VERSION 5.8 ;
BUSBITCHARS "[]" ;
DIVIDERCHAR "/" ;
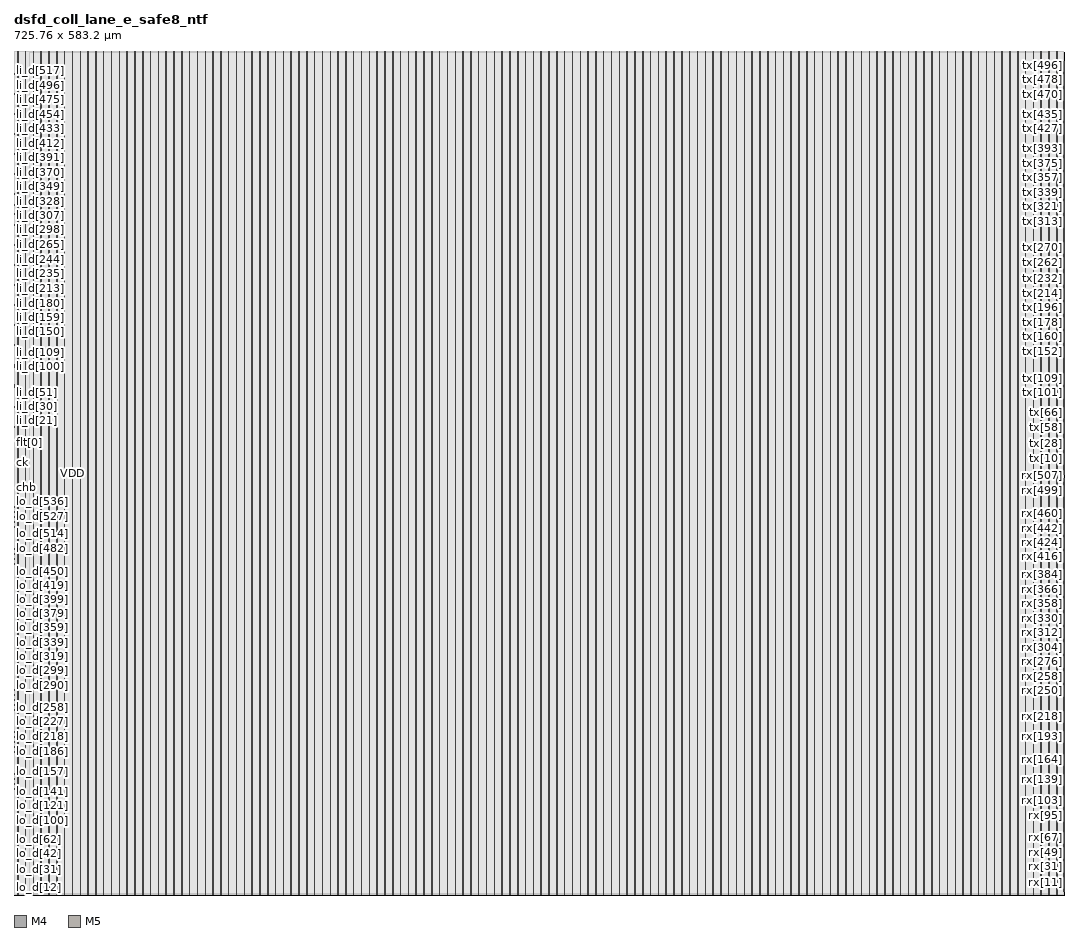
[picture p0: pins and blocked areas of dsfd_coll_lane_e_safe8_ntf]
MACRO dsfd_coll_lane_e_safe8_ntf
  CLASS BLOCK ;
  ORIGIN 0 0 ;
  FOREIGN dsfd_coll_lane_e_safe8_ntf 0 0 ;
  SIZE 725.76 BY 583.2 ;
  SYMMETRY X Y ;
  PIN lo_v
    DIRECTION INPUT ;
    USE SIGNAL ;
    PORT
      LAYER M4 ;
        RECT 0.000 277.008 0.192 277.032 ;
    END
  END lo_v
  PIN lo_r
    DIRECTION OUTPUT ;
    USE SIGNAL ;
    PORT
      LAYER M4 ;
        RECT 0.000 279.168 0.192 279.192 ;
    END
  END lo_r
  PIN lo_d[0]
    DIRECTION INPUT ;
    USE SIGNAL ;
    PORT
      LAYER M4 ;
        RECT 0.000 2.400 0.192 2.424 ;
    END
  END lo_d[0]
  PIN lo_d[1]
    DIRECTION INPUT ;
    USE SIGNAL ;
    PORT
      LAYER M4 ;
        RECT 0.000 2.880 0.192 2.904 ;
    END
  END lo_d[1]
  PIN lo_d[2]
    DIRECTION INPUT ;
    USE SIGNAL ;
    PORT
      LAYER M4 ;
        RECT 0.000 3.360 0.192 3.384 ;
    END
  END lo_d[2]
  PIN lo_d[3]
    DIRECTION INPUT ;
    USE SIGNAL ;
    PORT
      LAYER M4 ;
        RECT 0.000 3.888 0.192 3.912 ;
    END
  END lo_d[3]
  PIN lo_d[4]
    DIRECTION INPUT ;
    USE SIGNAL ;
    PORT
      LAYER M4 ;
        RECT 0.000 4.368 0.192 4.392 ;
    END
  END lo_d[4]
  PIN lo_d[5]
    DIRECTION INPUT ;
    USE SIGNAL ;
    PORT
      LAYER M4 ;
        RECT 0.000 4.848 0.192 4.872 ;
    END
  END lo_d[5]
  PIN lo_d[6]
    DIRECTION INPUT ;
    USE SIGNAL ;
    PORT
      LAYER M4 ;
        RECT 0.000 5.328 0.192 5.352 ;
    END
  END lo_d[6]
  PIN lo_d[7]
    DIRECTION INPUT ;
    USE SIGNAL ;
    PORT
      LAYER M4 ;
        RECT 0.000 5.856 0.192 5.880 ;
    END
  END lo_d[7]
  PIN lo_d[8]
    DIRECTION INPUT ;
    USE SIGNAL ;
    PORT
      LAYER M4 ;
        RECT 0.000 6.336 0.192 6.360 ;
    END
  END lo_d[8]
  PIN lo_d[9]
    DIRECTION INPUT ;
    USE SIGNAL ;
    PORT
      LAYER M4 ;
        RECT 0.000 6.816 0.192 6.840 ;
    END
  END lo_d[9]
  PIN lo_d[10]
    DIRECTION INPUT ;
    USE SIGNAL ;
    PORT
      LAYER M4 ;
        RECT 0.000 7.296 0.192 7.320 ;
    END
  END lo_d[10]
  PIN lo_d[11]
    DIRECTION INPUT ;
    USE SIGNAL ;
    PORT
      LAYER M4 ;
        RECT 0.000 7.824 0.192 7.848 ;
    END
  END lo_d[11]
  PIN lo_d[12]
    DIRECTION INPUT ;
    USE SIGNAL ;
    PORT
      LAYER M4 ;
        RECT 0.000 8.304 0.192 8.328 ;
    END
  END lo_d[12]
  PIN lo_d[13]
    DIRECTION INPUT ;
    USE SIGNAL ;
    PORT
      LAYER M4 ;
        RECT 0.000 8.784 0.192 8.808 ;
    END
  END lo_d[13]
  PIN lo_d[14]
    DIRECTION INPUT ;
    USE SIGNAL ;
    PORT
      LAYER M4 ;
        RECT 0.000 9.264 0.192 9.288 ;
    END
  END lo_d[14]
  PIN lo_d[15]
    DIRECTION INPUT ;
    USE SIGNAL ;
    PORT
      LAYER M4 ;
        RECT 0.000 9.792 0.192 9.816 ;
    END
  END lo_d[15]
  PIN lo_d[16]
    DIRECTION INPUT ;
    USE SIGNAL ;
    PORT
      LAYER M4 ;
        RECT 0.000 10.272 0.192 10.296 ;
    END
  END lo_d[16]
  PIN lo_d[17]
    DIRECTION INPUT ;
    USE SIGNAL ;
    PORT
      LAYER M4 ;
        RECT 0.000 10.752 0.192 10.776 ;
    END
  END lo_d[17]
  PIN lo_d[18]
    DIRECTION INPUT ;
    USE SIGNAL ;
    PORT
      LAYER M4 ;
        RECT 0.000 11.232 0.192 11.256 ;
    END
  END lo_d[18]
  PIN lo_d[19]
    DIRECTION INPUT ;
    USE SIGNAL ;
    PORT
      LAYER M4 ;
        RECT 0.000 11.760 0.192 11.784 ;
    END
  END lo_d[19]
  PIN lo_d[20]
    DIRECTION INPUT ;
    USE SIGNAL ;
    PORT
      LAYER M4 ;
        RECT 0.000 12.240 0.192 12.264 ;
    END
  END lo_d[20]
  PIN lo_d[21]
    DIRECTION INPUT ;
    USE SIGNAL ;
    PORT
      LAYER M4 ;
        RECT 0.000 12.720 0.192 12.744 ;
    END
  END lo_d[21]
  PIN lo_d[22]
    DIRECTION INPUT ;
    USE SIGNAL ;
    PORT
      LAYER M4 ;
        RECT 0.000 13.200 0.192 13.224 ;
    END
  END lo_d[22]
  PIN lo_d[23]
    DIRECTION INPUT ;
    USE SIGNAL ;
    PORT
      LAYER M4 ;
        RECT 0.000 13.728 0.192 13.752 ;
    END
  END lo_d[23]
  PIN lo_d[24]
    DIRECTION INPUT ;
    USE SIGNAL ;
    PORT
      LAYER M4 ;
        RECT 0.000 14.208 0.192 14.232 ;
    END
  END lo_d[24]
  PIN lo_d[25]
    DIRECTION INPUT ;
    USE SIGNAL ;
    PORT
      LAYER M4 ;
        RECT 0.000 14.688 0.192 14.712 ;
    END
  END lo_d[25]
  PIN lo_d[26]
    DIRECTION INPUT ;
    USE SIGNAL ;
    PORT
      LAYER M4 ;
        RECT 0.000 15.168 0.192 15.192 ;
    END
  END lo_d[26]
  PIN lo_d[27]
    DIRECTION INPUT ;
    USE SIGNAL ;
    PORT
      LAYER M4 ;
        RECT 0.000 15.696 0.192 15.720 ;
    END
  END lo_d[27]
  PIN lo_d[28]
    DIRECTION INPUT ;
    USE SIGNAL ;
    PORT
      LAYER M4 ;
        RECT 0.000 16.176 0.192 16.200 ;
    END
  END lo_d[28]
  PIN lo_d[29]
    DIRECTION INPUT ;
    USE SIGNAL ;
    PORT
      LAYER M4 ;
        RECT 0.000 16.656 0.192 16.680 ;
    END
  END lo_d[29]
  PIN lo_d[30]
    DIRECTION INPUT ;
    USE SIGNAL ;
    PORT
      LAYER M4 ;
        RECT 0.000 17.136 0.192 17.160 ;
    END
  END lo_d[30]
  PIN lo_d[31]
    DIRECTION INPUT ;
    USE SIGNAL ;
    PORT
      LAYER M4 ;
        RECT 0.000 17.664 0.192 17.688 ;
    END
  END lo_d[31]
  PIN lo_d[32]
    DIRECTION INPUT ;
    USE SIGNAL ;
    PORT
      LAYER M4 ;
        RECT 0.000 18.144 0.192 18.168 ;
    END
  END lo_d[32]
  PIN lo_d[33]
    DIRECTION INPUT ;
    USE SIGNAL ;
    PORT
      LAYER M4 ;
        RECT 0.000 18.624 0.192 18.648 ;
    END
  END lo_d[33]
  PIN lo_d[34]
    DIRECTION INPUT ;
    USE SIGNAL ;
    PORT
      LAYER M4 ;
        RECT 0.000 19.104 0.192 19.128 ;
    END
  END lo_d[34]
  PIN lo_d[35]
    DIRECTION INPUT ;
    USE SIGNAL ;
    PORT
      LAYER M4 ;
        RECT 0.000 19.632 0.192 19.656 ;
    END
  END lo_d[35]
  PIN lo_d[36]
    DIRECTION INPUT ;
    USE SIGNAL ;
    PORT
      LAYER M4 ;
        RECT 0.000 20.112 0.192 20.136 ;
    END
  END lo_d[36]
  PIN lo_d[37]
    DIRECTION INPUT ;
    USE SIGNAL ;
    PORT
      LAYER M4 ;
        RECT 0.000 20.592 0.192 20.616 ;
    END
  END lo_d[37]
  PIN lo_d[38]
    DIRECTION INPUT ;
    USE SIGNAL ;
    PORT
      LAYER M4 ;
        RECT 0.000 21.072 0.192 21.096 ;
    END
  END lo_d[38]
  PIN lo_d[39]
    DIRECTION INPUT ;
    USE SIGNAL ;
    PORT
      LAYER M4 ;
        RECT 0.000 21.600 0.192 21.624 ;
    END
  END lo_d[39]
  PIN lo_d[40]
    DIRECTION INPUT ;
    USE SIGNAL ;
    PORT
      LAYER M4 ;
        RECT 0.000 22.080 0.192 22.104 ;
    END
  END lo_d[40]
  PIN lo_d[41]
    DIRECTION INPUT ;
    USE SIGNAL ;
    PORT
      LAYER M4 ;
        RECT 0.000 22.560 0.192 22.584 ;
    END
  END lo_d[41]
  PIN lo_d[42]
    DIRECTION INPUT ;
    USE SIGNAL ;
    PORT
      LAYER M4 ;
        RECT 0.000 23.088 0.192 23.112 ;
    END
  END lo_d[42]
  PIN lo_d[43]
    DIRECTION INPUT ;
    USE SIGNAL ;
    PORT
      LAYER M4 ;
        RECT 0.000 23.568 0.192 23.592 ;
    END
  END lo_d[43]
  PIN lo_d[44]
    DIRECTION INPUT ;
    USE SIGNAL ;
    PORT
      LAYER M4 ;
        RECT 0.000 24.048 0.192 24.072 ;
    END
  END lo_d[44]
  PIN lo_d[45]
    DIRECTION INPUT ;
    USE SIGNAL ;
    PORT
      LAYER M4 ;
        RECT 0.000 24.528 0.192 24.552 ;
    END
  END lo_d[45]
  PIN lo_d[46]
    DIRECTION INPUT ;
    USE SIGNAL ;
    PORT
      LAYER M4 ;
        RECT 0.000 25.056 0.192 25.080 ;
    END
  END lo_d[46]
  PIN lo_d[47]
    DIRECTION INPUT ;
    USE SIGNAL ;
    PORT
      LAYER M4 ;
        RECT 0.000 25.536 0.192 25.560 ;
    END
  END lo_d[47]
  PIN lo_d[48]
    DIRECTION INPUT ;
    USE SIGNAL ;
    PORT
      LAYER M4 ;
        RECT 0.000 26.016 0.192 26.040 ;
    END
  END lo_d[48]
  PIN lo_d[49]
    DIRECTION INPUT ;
    USE SIGNAL ;
    PORT
      LAYER M4 ;
        RECT 0.000 26.496 0.192 26.520 ;
    END
  END lo_d[49]
  PIN lo_d[50]
    DIRECTION INPUT ;
    USE SIGNAL ;
    PORT
      LAYER M4 ;
        RECT 0.000 27.024 0.192 27.048 ;
    END
  END lo_d[50]
  PIN lo_d[51]
    DIRECTION INPUT ;
    USE SIGNAL ;
    PORT
      LAYER M4 ;
        RECT 0.000 27.504 0.192 27.528 ;
    END
  END lo_d[51]
  PIN lo_d[52]
    DIRECTION INPUT ;
    USE SIGNAL ;
    PORT
      LAYER M4 ;
        RECT 0.000 27.984 0.192 28.008 ;
    END
  END lo_d[52]
  PIN lo_d[53]
    DIRECTION INPUT ;
    USE SIGNAL ;
    PORT
      LAYER M4 ;
        RECT 0.000 28.464 0.192 28.488 ;
    END
  END lo_d[53]
  PIN lo_d[54]
    DIRECTION INPUT ;
    USE SIGNAL ;
    PORT
      LAYER M4 ;
        RECT 0.000 28.992 0.192 29.016 ;
    END
  END lo_d[54]
  PIN lo_d[55]
    DIRECTION INPUT ;
    USE SIGNAL ;
    PORT
      LAYER M4 ;
        RECT 0.000 29.472 0.192 29.496 ;
    END
  END lo_d[55]
  PIN lo_d[56]
    DIRECTION INPUT ;
    USE SIGNAL ;
    PORT
      LAYER M4 ;
        RECT 0.000 29.952 0.192 29.976 ;
    END
  END lo_d[56]
  PIN lo_d[57]
    DIRECTION INPUT ;
    USE SIGNAL ;
    PORT
      LAYER M4 ;
        RECT 0.000 30.432 0.192 30.456 ;
    END
  END lo_d[57]
  PIN lo_d[58]
    DIRECTION INPUT ;
    USE SIGNAL ;
    PORT
      LAYER M4 ;
        RECT 0.000 30.960 0.192 30.984 ;
    END
  END lo_d[58]
  PIN lo_d[59]
    DIRECTION INPUT ;
    USE SIGNAL ;
    PORT
      LAYER M4 ;
        RECT 0.000 31.440 0.192 31.464 ;
    END
  END lo_d[59]
  PIN lo_d[60]
    DIRECTION INPUT ;
    USE SIGNAL ;
    PORT
      LAYER M4 ;
        RECT 0.000 31.920 0.192 31.944 ;
    END
  END lo_d[60]
  PIN lo_d[61]
    DIRECTION INPUT ;
    USE SIGNAL ;
    PORT
      LAYER M4 ;
        RECT 0.000 32.400 0.192 32.424 ;
    END
  END lo_d[61]
  PIN lo_d[62]
    DIRECTION INPUT ;
    USE SIGNAL ;
    PORT
      LAYER M4 ;
        RECT 0.000 32.928 0.192 32.952 ;
    END
  END lo_d[62]
  PIN lo_d[63]
    DIRECTION INPUT ;
    USE SIGNAL ;
    PORT
      LAYER M4 ;
        RECT 0.000 33.408 0.192 33.432 ;
    END
  END lo_d[63]
  PIN lo_d[64]
    DIRECTION INPUT ;
    USE SIGNAL ;
    PORT
      LAYER M4 ;
        RECT 0.000 33.888 0.192 33.912 ;
    END
  END lo_d[64]
  PIN lo_d[65]
    DIRECTION INPUT ;
    USE SIGNAL ;
    PORT
      LAYER M4 ;
        RECT 0.000 34.368 0.192 34.392 ;
    END
  END lo_d[65]
  PIN lo_d[66]
    DIRECTION INPUT ;
    USE SIGNAL ;
    PORT
      LAYER M4 ;
        RECT 0.000 34.896 0.192 34.920 ;
    END
  END lo_d[66]
  PIN lo_d[67]
    DIRECTION INPUT ;
    USE SIGNAL ;
    PORT
      LAYER M4 ;
        RECT 0.000 35.376 0.192 35.400 ;
    END
  END lo_d[67]
  PIN lo_d[68]
    DIRECTION INPUT ;
    USE SIGNAL ;
    PORT
      LAYER M4 ;
        RECT 0.000 35.856 0.192 35.880 ;
    END
  END lo_d[68]
  PIN lo_d[69]
    DIRECTION INPUT ;
    USE SIGNAL ;
    PORT
      LAYER M4 ;
        RECT 0.000 36.336 0.192 36.360 ;
    END
  END lo_d[69]
  PIN lo_d[70]
    DIRECTION INPUT ;
    USE SIGNAL ;
    PORT
      LAYER M4 ;
        RECT 0.000 36.864 0.192 36.888 ;
    END
  END lo_d[70]
  PIN lo_d[71]
    DIRECTION INPUT ;
    USE SIGNAL ;
    PORT
      LAYER M4 ;
        RECT 0.000 37.344 0.192 37.368 ;
    END
  END lo_d[71]
  PIN lo_d[72]
    DIRECTION INPUT ;
    USE SIGNAL ;
    PORT
      LAYER M4 ;
        RECT 0.000 37.824 0.192 37.848 ;
    END
  END lo_d[72]
  PIN lo_d[73]
    DIRECTION INPUT ;
    USE SIGNAL ;
    PORT
      LAYER M4 ;
        RECT 0.000 38.304 0.192 38.328 ;
    END
  END lo_d[73]
  PIN lo_d[74]
    DIRECTION INPUT ;
    USE SIGNAL ;
    PORT
      LAYER M4 ;
        RECT 0.000 38.832 0.192 38.856 ;
    END
  END lo_d[74]
  PIN lo_d[75]
    DIRECTION INPUT ;
    USE SIGNAL ;
    PORT
      LAYER M4 ;
        RECT 0.000 39.312 0.192 39.336 ;
    END
  END lo_d[75]
  PIN lo_d[76]
    DIRECTION INPUT ;
    USE SIGNAL ;
    PORT
      LAYER M4 ;
        RECT 0.000 39.792 0.192 39.816 ;
    END
  END lo_d[76]
  PIN lo_d[77]
    DIRECTION INPUT ;
    USE SIGNAL ;
    PORT
      LAYER M4 ;
        RECT 0.000 40.272 0.192 40.296 ;
    END
  END lo_d[77]
  PIN lo_d[78]
    DIRECTION INPUT ;
    USE SIGNAL ;
    PORT
      LAYER M4 ;
        RECT 0.000 40.800 0.192 40.824 ;
    END
  END lo_d[78]
  PIN lo_d[79]
    DIRECTION INPUT ;
    USE SIGNAL ;
    PORT
      LAYER M4 ;
        RECT 0.000 41.280 0.192 41.304 ;
    END
  END lo_d[79]
  PIN lo_d[80]
    DIRECTION INPUT ;
    USE SIGNAL ;
    PORT
      LAYER M4 ;
        RECT 0.000 41.760 0.192 41.784 ;
    END
  END lo_d[80]
  PIN lo_d[81]
    DIRECTION INPUT ;
    USE SIGNAL ;
    PORT
      LAYER M4 ;
        RECT 0.000 42.240 0.192 42.264 ;
    END
  END lo_d[81]
  PIN lo_d[82]
    DIRECTION INPUT ;
    USE SIGNAL ;
    PORT
      LAYER M4 ;
        RECT 0.000 42.768 0.192 42.792 ;
    END
  END lo_d[82]
  PIN lo_d[83]
    DIRECTION INPUT ;
    USE SIGNAL ;
    PORT
      LAYER M4 ;
        RECT 0.000 43.248 0.192 43.272 ;
    END
  END lo_d[83]
  PIN lo_d[84]
    DIRECTION INPUT ;
    USE SIGNAL ;
    PORT
      LAYER M4 ;
        RECT 0.000 43.728 0.192 43.752 ;
    END
  END lo_d[84]
  PIN lo_d[85]
    DIRECTION INPUT ;
    USE SIGNAL ;
    PORT
      LAYER M4 ;
        RECT 0.000 44.208 0.192 44.232 ;
    END
  END lo_d[85]
  PIN lo_d[86]
    DIRECTION INPUT ;
    USE SIGNAL ;
    PORT
      LAYER M4 ;
        RECT 0.000 44.736 0.192 44.760 ;
    END
  END lo_d[86]
  PIN lo_d[87]
    DIRECTION INPUT ;
    USE SIGNAL ;
    PORT
      LAYER M4 ;
        RECT 0.000 45.216 0.192 45.240 ;
    END
  END lo_d[87]
  PIN lo_d[88]
    DIRECTION INPUT ;
    USE SIGNAL ;
    PORT
      LAYER M4 ;
        RECT 0.000 45.696 0.192 45.720 ;
    END
  END lo_d[88]
  PIN lo_d[89]
    DIRECTION INPUT ;
    USE SIGNAL ;
    PORT
      LAYER M4 ;
        RECT 0.000 46.176 0.192 46.200 ;
    END
  END lo_d[89]
  PIN lo_d[90]
    DIRECTION INPUT ;
    USE SIGNAL ;
    PORT
      LAYER M4 ;
        RECT 0.000 46.704 0.192 46.728 ;
    END
  END lo_d[90]
  PIN lo_d[91]
    DIRECTION INPUT ;
    USE SIGNAL ;
    PORT
      LAYER M4 ;
        RECT 0.000 47.184 0.192 47.208 ;
    END
  END lo_d[91]
  PIN lo_d[92]
    DIRECTION INPUT ;
    USE SIGNAL ;
    PORT
      LAYER M4 ;
        RECT 0.000 47.664 0.192 47.688 ;
    END
  END lo_d[92]
  PIN lo_d[93]
    DIRECTION INPUT ;
    USE SIGNAL ;
    PORT
      LAYER M4 ;
        RECT 0.000 48.144 0.192 48.168 ;
    END
  END lo_d[93]
  PIN lo_d[94]
    DIRECTION INPUT ;
    USE SIGNAL ;
    PORT
      LAYER M4 ;
        RECT 0.000 48.672 0.192 48.696 ;
    END
  END lo_d[94]
  PIN lo_d[95]
    DIRECTION INPUT ;
    USE SIGNAL ;
    PORT
      LAYER M4 ;
        RECT 0.000 49.152 0.192 49.176 ;
    END
  END lo_d[95]
  PIN lo_d[96]
    DIRECTION INPUT ;
    USE SIGNAL ;
    PORT
      LAYER M4 ;
        RECT 0.000 49.632 0.192 49.656 ;
    END
  END lo_d[96]
  PIN lo_d[97]
    DIRECTION INPUT ;
    USE SIGNAL ;
    PORT
      LAYER M4 ;
        RECT 0.000 50.112 0.192 50.136 ;
    END
  END lo_d[97]
  PIN lo_d[98]
    DIRECTION INPUT ;
    USE SIGNAL ;
    PORT
      LAYER M4 ;
        RECT 0.000 50.640 0.192 50.664 ;
    END
  END lo_d[98]
  PIN lo_d[99]
    DIRECTION INPUT ;
    USE SIGNAL ;
    PORT
      LAYER M4 ;
        RECT 0.000 51.120 0.192 51.144 ;
    END
  END lo_d[99]
  PIN lo_d[100]
    DIRECTION INPUT ;
    USE SIGNAL ;
    PORT
      LAYER M4 ;
        RECT 0.000 51.600 0.192 51.624 ;
    END
  END lo_d[100]
  PIN lo_d[101]
    DIRECTION INPUT ;
    USE SIGNAL ;
    PORT
      LAYER M4 ;
        RECT 0.000 52.080 0.192 52.104 ;
    END
  END lo_d[101]
  PIN lo_d[102]
    DIRECTION INPUT ;
    USE SIGNAL ;
    PORT
      LAYER M4 ;
        RECT 0.000 52.608 0.192 52.632 ;
    END
  END lo_d[102]
  PIN lo_d[103]
    DIRECTION INPUT ;
    USE SIGNAL ;
    PORT
      LAYER M4 ;
        RECT 0.000 53.088 0.192 53.112 ;
    END
  END lo_d[103]
  PIN lo_d[104]
    DIRECTION INPUT ;
    USE SIGNAL ;
    PORT
      LAYER M4 ;
        RECT 0.000 53.568 0.192 53.592 ;
    END
  END lo_d[104]
  PIN lo_d[105]
    DIRECTION INPUT ;
    USE SIGNAL ;
    PORT
      LAYER M4 ;
        RECT 0.000 54.048 0.192 54.072 ;
    END
  END lo_d[105]
  PIN lo_d[106]
    DIRECTION INPUT ;
    USE SIGNAL ;
    PORT
      LAYER M4 ;
        RECT 0.000 54.576 0.192 54.600 ;
    END
  END lo_d[106]
  PIN lo_d[107]
    DIRECTION INPUT ;
    USE SIGNAL ;
    PORT
      LAYER M4 ;
        RECT 0.000 55.056 0.192 55.080 ;
    END
  END lo_d[107]
  PIN lo_d[108]
    DIRECTION INPUT ;
    USE SIGNAL ;
    PORT
      LAYER M4 ;
        RECT 0.000 55.536 0.192 55.560 ;
    END
  END lo_d[108]
  PIN lo_d[109]
    DIRECTION INPUT ;
    USE SIGNAL ;
    PORT
      LAYER M4 ;
        RECT 0.000 56.016 0.192 56.040 ;
    END
  END lo_d[109]
  PIN lo_d[110]
    DIRECTION INPUT ;
    USE SIGNAL ;
    PORT
      LAYER M4 ;
        RECT 0.000 56.544 0.192 56.568 ;
    END
  END lo_d[110]
  PIN lo_d[111]
    DIRECTION INPUT ;
    USE SIGNAL ;
    PORT
      LAYER M4 ;
        RECT 0.000 57.024 0.192 57.048 ;
    END
  END lo_d[111]
  PIN lo_d[112]
    DIRECTION INPUT ;
    USE SIGNAL ;
    PORT
      LAYER M4 ;
        RECT 0.000 57.504 0.192 57.528 ;
    END
  END lo_d[112]
  PIN lo_d[113]
    DIRECTION INPUT ;
    USE SIGNAL ;
    PORT
      LAYER M4 ;
        RECT 0.000 57.984 0.192 58.008 ;
    END
  END lo_d[113]
  PIN lo_d[114]
    DIRECTION INPUT ;
    USE SIGNAL ;
    PORT
      LAYER M4 ;
        RECT 0.000 58.512 0.192 58.536 ;
    END
  END lo_d[114]
  PIN lo_d[115]
    DIRECTION INPUT ;
    USE SIGNAL ;
    PORT
      LAYER M4 ;
        RECT 0.000 58.992 0.192 59.016 ;
    END
  END lo_d[115]
  PIN lo_d[116]
    DIRECTION INPUT ;
    USE SIGNAL ;
    PORT
      LAYER M4 ;
        RECT 0.000 59.472 0.192 59.496 ;
    END
  END lo_d[116]
  PIN lo_d[117]
    DIRECTION INPUT ;
    USE SIGNAL ;
    PORT
      LAYER M4 ;
        RECT 0.000 59.952 0.192 59.976 ;
    END
  END lo_d[117]
  PIN lo_d[118]
    DIRECTION INPUT ;
    USE SIGNAL ;
    PORT
      LAYER M4 ;
        RECT 0.000 60.480 0.192 60.504 ;
    END
  END lo_d[118]
  PIN lo_d[119]
    DIRECTION INPUT ;
    USE SIGNAL ;
    PORT
      LAYER M4 ;
        RECT 0.000 60.960 0.192 60.984 ;
    END
  END lo_d[119]
  PIN lo_d[120]
    DIRECTION INPUT ;
    USE SIGNAL ;
    PORT
      LAYER M4 ;
        RECT 0.000 61.440 0.192 61.464 ;
    END
  END lo_d[120]
  PIN lo_d[121]
    DIRECTION INPUT ;
    USE SIGNAL ;
    PORT
      LAYER M4 ;
        RECT 0.000 61.968 0.192 61.992 ;
    END
  END lo_d[121]
  PIN lo_d[122]
    DIRECTION INPUT ;
    USE SIGNAL ;
    PORT
      LAYER M4 ;
        RECT 0.000 62.448 0.192 62.472 ;
    END
  END lo_d[122]
  PIN lo_d[123]
    DIRECTION INPUT ;
    USE SIGNAL ;
    PORT
      LAYER M4 ;
        RECT 0.000 62.928 0.192 62.952 ;
    END
  END lo_d[123]
  PIN lo_d[124]
    DIRECTION INPUT ;
    USE SIGNAL ;
    PORT
      LAYER M4 ;
        RECT 0.000 63.408 0.192 63.432 ;
    END
  END lo_d[124]
  PIN lo_d[125]
    DIRECTION INPUT ;
    USE SIGNAL ;
    PORT
      LAYER M4 ;
        RECT 0.000 63.936 0.192 63.960 ;
    END
  END lo_d[125]
  PIN lo_d[126]
    DIRECTION INPUT ;
    USE SIGNAL ;
    PORT
      LAYER M4 ;
        RECT 0.000 64.416 0.192 64.440 ;
    END
  END lo_d[126]
  PIN lo_d[127]
    DIRECTION INPUT ;
    USE SIGNAL ;
    PORT
      LAYER M4 ;
        RECT 0.000 64.896 0.192 64.920 ;
    END
  END lo_d[127]
  PIN lo_d[128]
    DIRECTION INPUT ;
    USE SIGNAL ;
    PORT
      LAYER M4 ;
        RECT 0.000 65.376 0.192 65.400 ;
    END
  END lo_d[128]
  PIN lo_d[129]
    DIRECTION INPUT ;
    USE SIGNAL ;
    PORT
      LAYER M4 ;
        RECT 0.000 65.904 0.192 65.928 ;
    END
  END lo_d[129]
  PIN lo_d[130]
    DIRECTION INPUT ;
    USE SIGNAL ;
    PORT
      LAYER M4 ;
        RECT 0.000 66.384 0.192 66.408 ;
    END
  END lo_d[130]
  PIN lo_d[131]
    DIRECTION INPUT ;
    USE SIGNAL ;
    PORT
      LAYER M4 ;
        RECT 0.000 66.864 0.192 66.888 ;
    END
  END lo_d[131]
  PIN lo_d[132]
    DIRECTION INPUT ;
    USE SIGNAL ;
    PORT
      LAYER M4 ;
        RECT 0.000 67.344 0.192 67.368 ;
    END
  END lo_d[132]
  PIN lo_d[133]
    DIRECTION INPUT ;
    USE SIGNAL ;
    PORT
      LAYER M4 ;
        RECT 0.000 67.872 0.192 67.896 ;
    END
  END lo_d[133]
  PIN lo_d[134]
    DIRECTION INPUT ;
    USE SIGNAL ;
    PORT
      LAYER M4 ;
        RECT 0.000 68.352 0.192 68.376 ;
    END
  END lo_d[134]
  PIN lo_d[135]
    DIRECTION INPUT ;
    USE SIGNAL ;
    PORT
      LAYER M4 ;
        RECT 0.000 68.832 0.192 68.856 ;
    END
  END lo_d[135]
  PIN lo_d[136]
    DIRECTION INPUT ;
    USE SIGNAL ;
    PORT
      LAYER M4 ;
        RECT 0.000 69.312 0.192 69.336 ;
    END
  END lo_d[136]
  PIN lo_d[137]
    DIRECTION INPUT ;
    USE SIGNAL ;
    PORT
      LAYER M4 ;
        RECT 0.000 69.840 0.192 69.864 ;
    END
  END lo_d[137]
  PIN lo_d[138]
    DIRECTION INPUT ;
    USE SIGNAL ;
    PORT
      LAYER M4 ;
        RECT 0.000 70.320 0.192 70.344 ;
    END
  END lo_d[138]
  PIN lo_d[139]
    DIRECTION INPUT ;
    USE SIGNAL ;
    PORT
      LAYER M4 ;
        RECT 0.000 70.800 0.192 70.824 ;
    END
  END lo_d[139]
  PIN lo_d[140]
    DIRECTION INPUT ;
    USE SIGNAL ;
    PORT
      LAYER M4 ;
        RECT 0.000 71.280 0.192 71.304 ;
    END
  END lo_d[140]
  PIN lo_d[141]
    DIRECTION INPUT ;
    USE SIGNAL ;
    PORT
      LAYER M4 ;
        RECT 0.000 71.808 0.192 71.832 ;
    END
  END lo_d[141]
  PIN lo_d[142]
    DIRECTION INPUT ;
    USE SIGNAL ;
    PORT
      LAYER M4 ;
        RECT 0.000 72.288 0.192 72.312 ;
    END
  END lo_d[142]
  PIN lo_d[143]
    DIRECTION INPUT ;
    USE SIGNAL ;
    PORT
      LAYER M4 ;
        RECT 0.000 72.768 0.192 72.792 ;
    END
  END lo_d[143]
  PIN lo_d[144]
    DIRECTION INPUT ;
    USE SIGNAL ;
    PORT
      LAYER M4 ;
        RECT 0.000 73.248 0.192 73.272 ;
    END
  END lo_d[144]
  PIN lo_d[145]
    DIRECTION INPUT ;
    USE SIGNAL ;
    PORT
      LAYER M4 ;
        RECT 0.000 73.776 0.192 73.800 ;
    END
  END lo_d[145]
  PIN lo_d[146]
    DIRECTION INPUT ;
    USE SIGNAL ;
    PORT
      LAYER M4 ;
        RECT 0.000 74.256 0.192 74.280 ;
    END
  END lo_d[146]
  PIN lo_d[147]
    DIRECTION INPUT ;
    USE SIGNAL ;
    PORT
      LAYER M4 ;
        RECT 0.000 74.736 0.192 74.760 ;
    END
  END lo_d[147]
  PIN lo_d[148]
    DIRECTION INPUT ;
    USE SIGNAL ;
    PORT
      LAYER M4 ;
        RECT 0.000 75.216 0.192 75.240 ;
    END
  END lo_d[148]
  PIN lo_d[149]
    DIRECTION INPUT ;
    USE SIGNAL ;
    PORT
      LAYER M4 ;
        RECT 0.000 75.744 0.192 75.768 ;
    END
  END lo_d[149]
  PIN lo_d[150]
    DIRECTION INPUT ;
    USE SIGNAL ;
    PORT
      LAYER M4 ;
        RECT 0.000 76.224 0.192 76.248 ;
    END
  END lo_d[150]
  PIN lo_d[151]
    DIRECTION INPUT ;
    USE SIGNAL ;
    PORT
      LAYER M4 ;
        RECT 0.000 76.704 0.192 76.728 ;
    END
  END lo_d[151]
  PIN lo_d[152]
    DIRECTION INPUT ;
    USE SIGNAL ;
    PORT
      LAYER M4 ;
        RECT 0.000 77.184 0.192 77.208 ;
    END
  END lo_d[152]
  PIN lo_d[153]
    DIRECTION INPUT ;
    USE SIGNAL ;
    PORT
      LAYER M4 ;
        RECT 0.000 77.712 0.192 77.736 ;
    END
  END lo_d[153]
  PIN lo_d[154]
    DIRECTION INPUT ;
    USE SIGNAL ;
    PORT
      LAYER M4 ;
        RECT 0.000 78.192 0.192 78.216 ;
    END
  END lo_d[154]
  PIN lo_d[155]
    DIRECTION INPUT ;
    USE SIGNAL ;
    PORT
      LAYER M4 ;
        RECT 0.000 78.672 0.192 78.696 ;
    END
  END lo_d[155]
  PIN lo_d[156]
    DIRECTION INPUT ;
    USE SIGNAL ;
    PORT
      LAYER M4 ;
        RECT 0.000 79.152 0.192 79.176 ;
    END
  END lo_d[156]
  PIN lo_d[157]
    DIRECTION INPUT ;
    USE SIGNAL ;
    PORT
      LAYER M4 ;
        RECT 0.000 79.680 0.192 79.704 ;
    END
  END lo_d[157]
  PIN lo_d[158]
    DIRECTION INPUT ;
    USE SIGNAL ;
    PORT
      LAYER M4 ;
        RECT 0.000 80.160 0.192 80.184 ;
    END
  END lo_d[158]
  PIN lo_d[159]
    DIRECTION INPUT ;
    USE SIGNAL ;
    PORT
      LAYER M4 ;
        RECT 0.000 80.640 0.192 80.664 ;
    END
  END lo_d[159]
  PIN lo_d[160]
    DIRECTION INPUT ;
    USE SIGNAL ;
    PORT
      LAYER M4 ;
        RECT 0.000 81.120 0.192 81.144 ;
    END
  END lo_d[160]
  PIN lo_d[161]
    DIRECTION INPUT ;
    USE SIGNAL ;
    PORT
      LAYER M4 ;
        RECT 0.000 81.648 0.192 81.672 ;
    END
  END lo_d[161]
  PIN lo_d[162]
    DIRECTION INPUT ;
    USE SIGNAL ;
    PORT
      LAYER M4 ;
        RECT 0.000 82.128 0.192 82.152 ;
    END
  END lo_d[162]
  PIN lo_d[163]
    DIRECTION INPUT ;
    USE SIGNAL ;
    PORT
      LAYER M4 ;
        RECT 0.000 82.608 0.192 82.632 ;
    END
  END lo_d[163]
  PIN lo_d[164]
    DIRECTION INPUT ;
    USE SIGNAL ;
    PORT
      LAYER M4 ;
        RECT 0.000 83.088 0.192 83.112 ;
    END
  END lo_d[164]
  PIN lo_d[165]
    DIRECTION INPUT ;
    USE SIGNAL ;
    PORT
      LAYER M4 ;
        RECT 0.000 83.616 0.192 83.640 ;
    END
  END lo_d[165]
  PIN lo_d[166]
    DIRECTION INPUT ;
    USE SIGNAL ;
    PORT
      LAYER M4 ;
        RECT 0.000 84.096 0.192 84.120 ;
    END
  END lo_d[166]
  PIN lo_d[167]
    DIRECTION INPUT ;
    USE SIGNAL ;
    PORT
      LAYER M4 ;
        RECT 0.000 84.576 0.192 84.600 ;
    END
  END lo_d[167]
  PIN lo_d[168]
    DIRECTION INPUT ;
    USE SIGNAL ;
    PORT
      LAYER M4 ;
        RECT 0.000 85.056 0.192 85.080 ;
    END
  END lo_d[168]
  PIN lo_d[169]
    DIRECTION INPUT ;
    USE SIGNAL ;
    PORT
      LAYER M4 ;
        RECT 0.000 85.584 0.192 85.608 ;
    END
  END lo_d[169]
  PIN lo_d[170]
    DIRECTION INPUT ;
    USE SIGNAL ;
    PORT
      LAYER M4 ;
        RECT 0.000 86.064 0.192 86.088 ;
    END
  END lo_d[170]
  PIN lo_d[171]
    DIRECTION INPUT ;
    USE SIGNAL ;
    PORT
      LAYER M4 ;
        RECT 0.000 86.544 0.192 86.568 ;
    END
  END lo_d[171]
  PIN lo_d[172]
    DIRECTION INPUT ;
    USE SIGNAL ;
    PORT
      LAYER M4 ;
        RECT 0.000 87.024 0.192 87.048 ;
    END
  END lo_d[172]
  PIN lo_d[173]
    DIRECTION INPUT ;
    USE SIGNAL ;
    PORT
      LAYER M4 ;
        RECT 0.000 87.552 0.192 87.576 ;
    END
  END lo_d[173]
  PIN lo_d[174]
    DIRECTION INPUT ;
    USE SIGNAL ;
    PORT
      LAYER M4 ;
        RECT 0.000 88.032 0.192 88.056 ;
    END
  END lo_d[174]
  PIN lo_d[175]
    DIRECTION INPUT ;
    USE SIGNAL ;
    PORT
      LAYER M4 ;
        RECT 0.000 88.512 0.192 88.536 ;
    END
  END lo_d[175]
  PIN lo_d[176]
    DIRECTION INPUT ;
    USE SIGNAL ;
    PORT
      LAYER M4 ;
        RECT 0.000 88.992 0.192 89.016 ;
    END
  END lo_d[176]
  PIN lo_d[177]
    DIRECTION INPUT ;
    USE SIGNAL ;
    PORT
      LAYER M4 ;
        RECT 0.000 89.520 0.192 89.544 ;
    END
  END lo_d[177]
  PIN lo_d[178]
    DIRECTION INPUT ;
    USE SIGNAL ;
    PORT
      LAYER M4 ;
        RECT 0.000 90.000 0.192 90.024 ;
    END
  END lo_d[178]
  PIN lo_d[179]
    DIRECTION INPUT ;
    USE SIGNAL ;
    PORT
      LAYER M4 ;
        RECT 0.000 90.480 0.192 90.504 ;
    END
  END lo_d[179]
  PIN lo_d[180]
    DIRECTION INPUT ;
    USE SIGNAL ;
    PORT
      LAYER M4 ;
        RECT 0.000 90.960 0.192 90.984 ;
    END
  END lo_d[180]
  PIN lo_d[181]
    DIRECTION INPUT ;
    USE SIGNAL ;
    PORT
      LAYER M4 ;
        RECT 0.000 91.488 0.192 91.512 ;
    END
  END lo_d[181]
  PIN lo_d[182]
    DIRECTION INPUT ;
    USE SIGNAL ;
    PORT
      LAYER M4 ;
        RECT 0.000 91.968 0.192 91.992 ;
    END
  END lo_d[182]
  PIN lo_d[183]
    DIRECTION INPUT ;
    USE SIGNAL ;
    PORT
      LAYER M4 ;
        RECT 0.000 92.448 0.192 92.472 ;
    END
  END lo_d[183]
  PIN lo_d[184]
    DIRECTION INPUT ;
    USE SIGNAL ;
    PORT
      LAYER M4 ;
        RECT 0.000 92.928 0.192 92.952 ;
    END
  END lo_d[184]
  PIN lo_d[185]
    DIRECTION INPUT ;
    USE SIGNAL ;
    PORT
      LAYER M4 ;
        RECT 0.000 93.456 0.192 93.480 ;
    END
  END lo_d[185]
  PIN lo_d[186]
    DIRECTION INPUT ;
    USE SIGNAL ;
    PORT
      LAYER M4 ;
        RECT 0.000 93.936 0.192 93.960 ;
    END
  END lo_d[186]
  PIN lo_d[187]
    DIRECTION INPUT ;
    USE SIGNAL ;
    PORT
      LAYER M4 ;
        RECT 0.000 94.416 0.192 94.440 ;
    END
  END lo_d[187]
  PIN lo_d[188]
    DIRECTION INPUT ;
    USE SIGNAL ;
    PORT
      LAYER M4 ;
        RECT 0.000 94.896 0.192 94.920 ;
    END
  END lo_d[188]
  PIN lo_d[189]
    DIRECTION INPUT ;
    USE SIGNAL ;
    PORT
      LAYER M4 ;
        RECT 0.000 95.424 0.192 95.448 ;
    END
  END lo_d[189]
  PIN lo_d[190]
    DIRECTION INPUT ;
    USE SIGNAL ;
    PORT
      LAYER M4 ;
        RECT 0.000 95.904 0.192 95.928 ;
    END
  END lo_d[190]
  PIN lo_d[191]
    DIRECTION INPUT ;
    USE SIGNAL ;
    PORT
      LAYER M4 ;
        RECT 0.000 96.384 0.192 96.408 ;
    END
  END lo_d[191]
  PIN lo_d[192]
    DIRECTION INPUT ;
    USE SIGNAL ;
    PORT
      LAYER M4 ;
        RECT 0.000 96.864 0.192 96.888 ;
    END
  END lo_d[192]
  PIN lo_d[193]
    DIRECTION INPUT ;
    USE SIGNAL ;
    PORT
      LAYER M4 ;
        RECT 0.000 97.392 0.192 97.416 ;
    END
  END lo_d[193]
  PIN lo_d[194]
    DIRECTION INPUT ;
    USE SIGNAL ;
    PORT
      LAYER M4 ;
        RECT 0.000 97.872 0.192 97.896 ;
    END
  END lo_d[194]
  PIN lo_d[195]
    DIRECTION INPUT ;
    USE SIGNAL ;
    PORT
      LAYER M4 ;
        RECT 0.000 98.352 0.192 98.376 ;
    END
  END lo_d[195]
  PIN lo_d[196]
    DIRECTION INPUT ;
    USE SIGNAL ;
    PORT
      LAYER M4 ;
        RECT 0.000 98.832 0.192 98.856 ;
    END
  END lo_d[196]
  PIN lo_d[197]
    DIRECTION INPUT ;
    USE SIGNAL ;
    PORT
      LAYER M4 ;
        RECT 0.000 99.360 0.192 99.384 ;
    END
  END lo_d[197]
  PIN lo_d[198]
    DIRECTION INPUT ;
    USE SIGNAL ;
    PORT
      LAYER M4 ;
        RECT 0.000 99.840 0.192 99.864 ;
    END
  END lo_d[198]
  PIN lo_d[199]
    DIRECTION INPUT ;
    USE SIGNAL ;
    PORT
      LAYER M4 ;
        RECT 0.000 100.320 0.192 100.344 ;
    END
  END lo_d[199]
  PIN lo_d[200]
    DIRECTION INPUT ;
    USE SIGNAL ;
    PORT
      LAYER M4 ;
        RECT 0.000 100.848 0.192 100.872 ;
    END
  END lo_d[200]
  PIN lo_d[201]
    DIRECTION INPUT ;
    USE SIGNAL ;
    PORT
      LAYER M4 ;
        RECT 0.000 101.328 0.192 101.352 ;
    END
  END lo_d[201]
  PIN lo_d[202]
    DIRECTION INPUT ;
    USE SIGNAL ;
    PORT
      LAYER M4 ;
        RECT 0.000 101.808 0.192 101.832 ;
    END
  END lo_d[202]
  PIN lo_d[203]
    DIRECTION INPUT ;
    USE SIGNAL ;
    PORT
      LAYER M4 ;
        RECT 0.000 102.288 0.192 102.312 ;
    END
  END lo_d[203]
  PIN lo_d[204]
    DIRECTION INPUT ;
    USE SIGNAL ;
    PORT
      LAYER M4 ;
        RECT 0.000 102.816 0.192 102.840 ;
    END
  END lo_d[204]
  PIN lo_d[205]
    DIRECTION INPUT ;
    USE SIGNAL ;
    PORT
      LAYER M4 ;
        RECT 0.000 103.296 0.192 103.320 ;
    END
  END lo_d[205]
  PIN lo_d[206]
    DIRECTION INPUT ;
    USE SIGNAL ;
    PORT
      LAYER M4 ;
        RECT 0.000 103.776 0.192 103.800 ;
    END
  END lo_d[206]
  PIN lo_d[207]
    DIRECTION INPUT ;
    USE SIGNAL ;
    PORT
      LAYER M4 ;
        RECT 0.000 104.256 0.192 104.280 ;
    END
  END lo_d[207]
  PIN lo_d[208]
    DIRECTION INPUT ;
    USE SIGNAL ;
    PORT
      LAYER M4 ;
        RECT 0.000 104.784 0.192 104.808 ;
    END
  END lo_d[208]
  PIN lo_d[209]
    DIRECTION INPUT ;
    USE SIGNAL ;
    PORT
      LAYER M4 ;
        RECT 0.000 105.264 0.192 105.288 ;
    END
  END lo_d[209]
  PIN lo_d[210]
    DIRECTION INPUT ;
    USE SIGNAL ;
    PORT
      LAYER M4 ;
        RECT 0.000 105.744 0.192 105.768 ;
    END
  END lo_d[210]
  PIN lo_d[211]
    DIRECTION INPUT ;
    USE SIGNAL ;
    PORT
      LAYER M4 ;
        RECT 0.000 106.224 0.192 106.248 ;
    END
  END lo_d[211]
  PIN lo_d[212]
    DIRECTION INPUT ;
    USE SIGNAL ;
    PORT
      LAYER M4 ;
        RECT 0.000 106.752 0.192 106.776 ;
    END
  END lo_d[212]
  PIN lo_d[213]
    DIRECTION INPUT ;
    USE SIGNAL ;
    PORT
      LAYER M4 ;
        RECT 0.000 107.232 0.192 107.256 ;
    END
  END lo_d[213]
  PIN lo_d[214]
    DIRECTION INPUT ;
    USE SIGNAL ;
    PORT
      LAYER M4 ;
        RECT 0.000 107.712 0.192 107.736 ;
    END
  END lo_d[214]
  PIN lo_d[215]
    DIRECTION INPUT ;
    USE SIGNAL ;
    PORT
      LAYER M4 ;
        RECT 0.000 108.192 0.192 108.216 ;
    END
  END lo_d[215]
  PIN lo_d[216]
    DIRECTION INPUT ;
    USE SIGNAL ;
    PORT
      LAYER M4 ;
        RECT 0.000 108.720 0.192 108.744 ;
    END
  END lo_d[216]
  PIN lo_d[217]
    DIRECTION INPUT ;
    USE SIGNAL ;
    PORT
      LAYER M4 ;
        RECT 0.000 109.200 0.192 109.224 ;
    END
  END lo_d[217]
  PIN lo_d[218]
    DIRECTION INPUT ;
    USE SIGNAL ;
    PORT
      LAYER M4 ;
        RECT 0.000 109.680 0.192 109.704 ;
    END
  END lo_d[218]
  PIN lo_d[219]
    DIRECTION INPUT ;
    USE SIGNAL ;
    PORT
      LAYER M4 ;
        RECT 0.000 110.160 0.192 110.184 ;
    END
  END lo_d[219]
  PIN lo_d[220]
    DIRECTION INPUT ;
    USE SIGNAL ;
    PORT
      LAYER M4 ;
        RECT 0.000 110.688 0.192 110.712 ;
    END
  END lo_d[220]
  PIN lo_d[221]
    DIRECTION INPUT ;
    USE SIGNAL ;
    PORT
      LAYER M4 ;
        RECT 0.000 111.168 0.192 111.192 ;
    END
  END lo_d[221]
  PIN lo_d[222]
    DIRECTION INPUT ;
    USE SIGNAL ;
    PORT
      LAYER M4 ;
        RECT 0.000 111.648 0.192 111.672 ;
    END
  END lo_d[222]
  PIN lo_d[223]
    DIRECTION INPUT ;
    USE SIGNAL ;
    PORT
      LAYER M4 ;
        RECT 0.000 112.128 0.192 112.152 ;
    END
  END lo_d[223]
  PIN lo_d[224]
    DIRECTION INPUT ;
    USE SIGNAL ;
    PORT
      LAYER M4 ;
        RECT 0.000 112.656 0.192 112.680 ;
    END
  END lo_d[224]
  PIN lo_d[225]
    DIRECTION INPUT ;
    USE SIGNAL ;
    PORT
      LAYER M4 ;
        RECT 0.000 113.136 0.192 113.160 ;
    END
  END lo_d[225]
  PIN lo_d[226]
    DIRECTION INPUT ;
    USE SIGNAL ;
    PORT
      LAYER M4 ;
        RECT 0.000 113.616 0.192 113.640 ;
    END
  END lo_d[226]
  PIN lo_d[227]
    DIRECTION INPUT ;
    USE SIGNAL ;
    PORT
      LAYER M4 ;
        RECT 0.000 114.096 0.192 114.120 ;
    END
  END lo_d[227]
  PIN lo_d[228]
    DIRECTION INPUT ;
    USE SIGNAL ;
    PORT
      LAYER M4 ;
        RECT 0.000 114.624 0.192 114.648 ;
    END
  END lo_d[228]
  PIN lo_d[229]
    DIRECTION INPUT ;
    USE SIGNAL ;
    PORT
      LAYER M4 ;
        RECT 0.000 115.104 0.192 115.128 ;
    END
  END lo_d[229]
  PIN lo_d[230]
    DIRECTION INPUT ;
    USE SIGNAL ;
    PORT
      LAYER M4 ;
        RECT 0.000 115.584 0.192 115.608 ;
    END
  END lo_d[230]
  PIN lo_d[231]
    DIRECTION INPUT ;
    USE SIGNAL ;
    PORT
      LAYER M4 ;
        RECT 0.000 116.064 0.192 116.088 ;
    END
  END lo_d[231]
  PIN lo_d[232]
    DIRECTION INPUT ;
    USE SIGNAL ;
    PORT
      LAYER M4 ;
        RECT 0.000 116.592 0.192 116.616 ;
    END
  END lo_d[232]
  PIN lo_d[233]
    DIRECTION INPUT ;
    USE SIGNAL ;
    PORT
      LAYER M4 ;
        RECT 0.000 117.072 0.192 117.096 ;
    END
  END lo_d[233]
  PIN lo_d[234]
    DIRECTION INPUT ;
    USE SIGNAL ;
    PORT
      LAYER M4 ;
        RECT 0.000 117.552 0.192 117.576 ;
    END
  END lo_d[234]
  PIN lo_d[235]
    DIRECTION INPUT ;
    USE SIGNAL ;
    PORT
      LAYER M4 ;
        RECT 0.000 118.032 0.192 118.056 ;
    END
  END lo_d[235]
  PIN lo_d[236]
    DIRECTION INPUT ;
    USE SIGNAL ;
    PORT
      LAYER M4 ;
        RECT 0.000 118.560 0.192 118.584 ;
    END
  END lo_d[236]
  PIN lo_d[237]
    DIRECTION INPUT ;
    USE SIGNAL ;
    PORT
      LAYER M4 ;
        RECT 0.000 119.040 0.192 119.064 ;
    END
  END lo_d[237]
  PIN lo_d[238]
    DIRECTION INPUT ;
    USE SIGNAL ;
    PORT
      LAYER M4 ;
        RECT 0.000 119.520 0.192 119.544 ;
    END
  END lo_d[238]
  PIN lo_d[239]
    DIRECTION INPUT ;
    USE SIGNAL ;
    PORT
      LAYER M4 ;
        RECT 0.000 120.000 0.192 120.024 ;
    END
  END lo_d[239]
  PIN lo_d[240]
    DIRECTION INPUT ;
    USE SIGNAL ;
    PORT
      LAYER M4 ;
        RECT 0.000 120.528 0.192 120.552 ;
    END
  END lo_d[240]
  PIN lo_d[241]
    DIRECTION INPUT ;
    USE SIGNAL ;
    PORT
      LAYER M4 ;
        RECT 0.000 121.008 0.192 121.032 ;
    END
  END lo_d[241]
  PIN lo_d[242]
    DIRECTION INPUT ;
    USE SIGNAL ;
    PORT
      LAYER M4 ;
        RECT 0.000 121.488 0.192 121.512 ;
    END
  END lo_d[242]
  PIN lo_d[243]
    DIRECTION INPUT ;
    USE SIGNAL ;
    PORT
      LAYER M4 ;
        RECT 0.000 121.968 0.192 121.992 ;
    END
  END lo_d[243]
  PIN lo_d[244]
    DIRECTION INPUT ;
    USE SIGNAL ;
    PORT
      LAYER M4 ;
        RECT 0.000 122.496 0.192 122.520 ;
    END
  END lo_d[244]
  PIN lo_d[245]
    DIRECTION INPUT ;
    USE SIGNAL ;
    PORT
      LAYER M4 ;
        RECT 0.000 122.976 0.192 123.000 ;
    END
  END lo_d[245]
  PIN lo_d[246]
    DIRECTION INPUT ;
    USE SIGNAL ;
    PORT
      LAYER M4 ;
        RECT 0.000 123.456 0.192 123.480 ;
    END
  END lo_d[246]
  PIN lo_d[247]
    DIRECTION INPUT ;
    USE SIGNAL ;
    PORT
      LAYER M4 ;
        RECT 0.000 123.936 0.192 123.960 ;
    END
  END lo_d[247]
  PIN lo_d[248]
    DIRECTION INPUT ;
    USE SIGNAL ;
    PORT
      LAYER M4 ;
        RECT 0.000 124.464 0.192 124.488 ;
    END
  END lo_d[248]
  PIN lo_d[249]
    DIRECTION INPUT ;
    USE SIGNAL ;
    PORT
      LAYER M4 ;
        RECT 0.000 124.944 0.192 124.968 ;
    END
  END lo_d[249]
  PIN lo_d[250]
    DIRECTION INPUT ;
    USE SIGNAL ;
    PORT
      LAYER M4 ;
        RECT 0.000 125.424 0.192 125.448 ;
    END
  END lo_d[250]
  PIN lo_d[251]
    DIRECTION INPUT ;
    USE SIGNAL ;
    PORT
      LAYER M4 ;
        RECT 0.000 125.904 0.192 125.928 ;
    END
  END lo_d[251]
  PIN lo_d[252]
    DIRECTION INPUT ;
    USE SIGNAL ;
    PORT
      LAYER M4 ;
        RECT 0.000 126.432 0.192 126.456 ;
    END
  END lo_d[252]
  PIN lo_d[253]
    DIRECTION INPUT ;
    USE SIGNAL ;
    PORT
      LAYER M4 ;
        RECT 0.000 126.912 0.192 126.936 ;
    END
  END lo_d[253]
  PIN lo_d[254]
    DIRECTION INPUT ;
    USE SIGNAL ;
    PORT
      LAYER M4 ;
        RECT 0.000 127.392 0.192 127.416 ;
    END
  END lo_d[254]
  PIN lo_d[255]
    DIRECTION INPUT ;
    USE SIGNAL ;
    PORT
      LAYER M4 ;
        RECT 0.000 127.872 0.192 127.896 ;
    END
  END lo_d[255]
  PIN lo_d[256]
    DIRECTION INPUT ;
    USE SIGNAL ;
    PORT
      LAYER M4 ;
        RECT 0.000 128.400 0.192 128.424 ;
    END
  END lo_d[256]
  PIN lo_d[257]
    DIRECTION INPUT ;
    USE SIGNAL ;
    PORT
      LAYER M4 ;
        RECT 0.000 128.880 0.192 128.904 ;
    END
  END lo_d[257]
  PIN lo_d[258]
    DIRECTION INPUT ;
    USE SIGNAL ;
    PORT
      LAYER M4 ;
        RECT 0.000 129.360 0.192 129.384 ;
    END
  END lo_d[258]
  PIN lo_d[259]
    DIRECTION INPUT ;
    USE SIGNAL ;
    PORT
      LAYER M4 ;
        RECT 0.000 129.840 0.192 129.864 ;
    END
  END lo_d[259]
  PIN lo_d[260]
    DIRECTION INPUT ;
    USE SIGNAL ;
    PORT
      LAYER M4 ;
        RECT 0.000 130.368 0.192 130.392 ;
    END
  END lo_d[260]
  PIN lo_d[261]
    DIRECTION INPUT ;
    USE SIGNAL ;
    PORT
      LAYER M4 ;
        RECT 0.000 130.848 0.192 130.872 ;
    END
  END lo_d[261]
  PIN lo_d[262]
    DIRECTION INPUT ;
    USE SIGNAL ;
    PORT
      LAYER M4 ;
        RECT 0.000 131.328 0.192 131.352 ;
    END
  END lo_d[262]
  PIN lo_d[263]
    DIRECTION INPUT ;
    USE SIGNAL ;
    PORT
      LAYER M4 ;
        RECT 0.000 131.808 0.192 131.832 ;
    END
  END lo_d[263]
  PIN lo_d[264]
    DIRECTION INPUT ;
    USE SIGNAL ;
    PORT
      LAYER M4 ;
        RECT 0.000 132.336 0.192 132.360 ;
    END
  END lo_d[264]
  PIN lo_d[265]
    DIRECTION INPUT ;
    USE SIGNAL ;
    PORT
      LAYER M4 ;
        RECT 0.000 132.816 0.192 132.840 ;
    END
  END lo_d[265]
  PIN lo_d[266]
    DIRECTION INPUT ;
    USE SIGNAL ;
    PORT
      LAYER M4 ;
        RECT 0.000 133.296 0.192 133.320 ;
    END
  END lo_d[266]
  PIN lo_d[267]
    DIRECTION INPUT ;
    USE SIGNAL ;
    PORT
      LAYER M4 ;
        RECT 0.000 133.776 0.192 133.800 ;
    END
  END lo_d[267]
  PIN lo_d[268]
    DIRECTION INPUT ;
    USE SIGNAL ;
    PORT
      LAYER M4 ;
        RECT 0.000 134.304 0.192 134.328 ;
    END
  END lo_d[268]
  PIN lo_d[269]
    DIRECTION INPUT ;
    USE SIGNAL ;
    PORT
      LAYER M4 ;
        RECT 0.000 134.784 0.192 134.808 ;
    END
  END lo_d[269]
  PIN lo_d[270]
    DIRECTION INPUT ;
    USE SIGNAL ;
    PORT
      LAYER M4 ;
        RECT 0.000 135.264 0.192 135.288 ;
    END
  END lo_d[270]
  PIN lo_d[271]
    DIRECTION INPUT ;
    USE SIGNAL ;
    PORT
      LAYER M4 ;
        RECT 0.000 135.744 0.192 135.768 ;
    END
  END lo_d[271]
  PIN lo_d[272]
    DIRECTION INPUT ;
    USE SIGNAL ;
    PORT
      LAYER M4 ;
        RECT 0.000 136.272 0.192 136.296 ;
    END
  END lo_d[272]
  PIN lo_d[273]
    DIRECTION INPUT ;
    USE SIGNAL ;
    PORT
      LAYER M4 ;
        RECT 0.000 136.752 0.192 136.776 ;
    END
  END lo_d[273]
  PIN lo_d[274]
    DIRECTION INPUT ;
    USE SIGNAL ;
    PORT
      LAYER M4 ;
        RECT 0.000 137.232 0.192 137.256 ;
    END
  END lo_d[274]
  PIN lo_d[275]
    DIRECTION INPUT ;
    USE SIGNAL ;
    PORT
      LAYER M4 ;
        RECT 0.000 137.712 0.192 137.736 ;
    END
  END lo_d[275]
  PIN lo_d[276]
    DIRECTION INPUT ;
    USE SIGNAL ;
    PORT
      LAYER M4 ;
        RECT 0.000 138.240 0.192 138.264 ;
    END
  END lo_d[276]
  PIN lo_d[277]
    DIRECTION INPUT ;
    USE SIGNAL ;
    PORT
      LAYER M4 ;
        RECT 0.000 138.720 0.192 138.744 ;
    END
  END lo_d[277]
  PIN lo_d[278]
    DIRECTION INPUT ;
    USE SIGNAL ;
    PORT
      LAYER M4 ;
        RECT 0.000 139.200 0.192 139.224 ;
    END
  END lo_d[278]
  PIN lo_d[279]
    DIRECTION INPUT ;
    USE SIGNAL ;
    PORT
      LAYER M4 ;
        RECT 0.000 139.728 0.192 139.752 ;
    END
  END lo_d[279]
  PIN lo_d[280]
    DIRECTION INPUT ;
    USE SIGNAL ;
    PORT
      LAYER M4 ;
        RECT 0.000 140.208 0.192 140.232 ;
    END
  END lo_d[280]
  PIN lo_d[281]
    DIRECTION INPUT ;
    USE SIGNAL ;
    PORT
      LAYER M4 ;
        RECT 0.000 140.688 0.192 140.712 ;
    END
  END lo_d[281]
  PIN lo_d[282]
    DIRECTION INPUT ;
    USE SIGNAL ;
    PORT
      LAYER M4 ;
        RECT 0.000 141.168 0.192 141.192 ;
    END
  END lo_d[282]
  PIN lo_d[283]
    DIRECTION INPUT ;
    USE SIGNAL ;
    PORT
      LAYER M4 ;
        RECT 0.000 141.696 0.192 141.720 ;
    END
  END lo_d[283]
  PIN lo_d[284]
    DIRECTION INPUT ;
    USE SIGNAL ;
    PORT
      LAYER M4 ;
        RECT 0.000 142.176 0.192 142.200 ;
    END
  END lo_d[284]
  PIN lo_d[285]
    DIRECTION INPUT ;
    USE SIGNAL ;
    PORT
      LAYER M4 ;
        RECT 0.000 142.656 0.192 142.680 ;
    END
  END lo_d[285]
  PIN lo_d[286]
    DIRECTION INPUT ;
    USE SIGNAL ;
    PORT
      LAYER M4 ;
        RECT 0.000 143.136 0.192 143.160 ;
    END
  END lo_d[286]
  PIN lo_d[287]
    DIRECTION INPUT ;
    USE SIGNAL ;
    PORT
      LAYER M4 ;
        RECT 0.000 143.664 0.192 143.688 ;
    END
  END lo_d[287]
  PIN lo_d[288]
    DIRECTION INPUT ;
    USE SIGNAL ;
    PORT
      LAYER M4 ;
        RECT 0.000 144.144 0.192 144.168 ;
    END
  END lo_d[288]
  PIN lo_d[289]
    DIRECTION INPUT ;
    USE SIGNAL ;
    PORT
      LAYER M4 ;
        RECT 0.000 144.624 0.192 144.648 ;
    END
  END lo_d[289]
  PIN lo_d[290]
    DIRECTION INPUT ;
    USE SIGNAL ;
    PORT
      LAYER M4 ;
        RECT 0.000 145.104 0.192 145.128 ;
    END
  END lo_d[290]
  PIN lo_d[291]
    DIRECTION INPUT ;
    USE SIGNAL ;
    PORT
      LAYER M4 ;
        RECT 0.000 145.632 0.192 145.656 ;
    END
  END lo_d[291]
  PIN lo_d[292]
    DIRECTION INPUT ;
    USE SIGNAL ;
    PORT
      LAYER M4 ;
        RECT 0.000 146.112 0.192 146.136 ;
    END
  END lo_d[292]
  PIN lo_d[293]
    DIRECTION INPUT ;
    USE SIGNAL ;
    PORT
      LAYER M4 ;
        RECT 0.000 146.592 0.192 146.616 ;
    END
  END lo_d[293]
  PIN lo_d[294]
    DIRECTION INPUT ;
    USE SIGNAL ;
    PORT
      LAYER M4 ;
        RECT 0.000 147.072 0.192 147.096 ;
    END
  END lo_d[294]
  PIN lo_d[295]
    DIRECTION INPUT ;
    USE SIGNAL ;
    PORT
      LAYER M4 ;
        RECT 0.000 147.600 0.192 147.624 ;
    END
  END lo_d[295]
  PIN lo_d[296]
    DIRECTION INPUT ;
    USE SIGNAL ;
    PORT
      LAYER M4 ;
        RECT 0.000 148.080 0.192 148.104 ;
    END
  END lo_d[296]
  PIN lo_d[297]
    DIRECTION INPUT ;
    USE SIGNAL ;
    PORT
      LAYER M4 ;
        RECT 0.000 148.560 0.192 148.584 ;
    END
  END lo_d[297]
  PIN lo_d[298]
    DIRECTION INPUT ;
    USE SIGNAL ;
    PORT
      LAYER M4 ;
        RECT 0.000 149.040 0.192 149.064 ;
    END
  END lo_d[298]
  PIN lo_d[299]
    DIRECTION INPUT ;
    USE SIGNAL ;
    PORT
      LAYER M4 ;
        RECT 0.000 149.568 0.192 149.592 ;
    END
  END lo_d[299]
  PIN lo_d[300]
    DIRECTION INPUT ;
    USE SIGNAL ;
    PORT
      LAYER M4 ;
        RECT 0.000 150.048 0.192 150.072 ;
    END
  END lo_d[300]
  PIN lo_d[301]
    DIRECTION INPUT ;
    USE SIGNAL ;
    PORT
      LAYER M4 ;
        RECT 0.000 150.528 0.192 150.552 ;
    END
  END lo_d[301]
  PIN lo_d[302]
    DIRECTION INPUT ;
    USE SIGNAL ;
    PORT
      LAYER M4 ;
        RECT 0.000 151.008 0.192 151.032 ;
    END
  END lo_d[302]
  PIN lo_d[303]
    DIRECTION INPUT ;
    USE SIGNAL ;
    PORT
      LAYER M4 ;
        RECT 0.000 151.536 0.192 151.560 ;
    END
  END lo_d[303]
  PIN lo_d[304]
    DIRECTION INPUT ;
    USE SIGNAL ;
    PORT
      LAYER M4 ;
        RECT 0.000 152.016 0.192 152.040 ;
    END
  END lo_d[304]
  PIN lo_d[305]
    DIRECTION INPUT ;
    USE SIGNAL ;
    PORT
      LAYER M4 ;
        RECT 0.000 152.496 0.192 152.520 ;
    END
  END lo_d[305]
  PIN lo_d[306]
    DIRECTION INPUT ;
    USE SIGNAL ;
    PORT
      LAYER M4 ;
        RECT 0.000 152.976 0.192 153.000 ;
    END
  END lo_d[306]
  PIN lo_d[307]
    DIRECTION INPUT ;
    USE SIGNAL ;
    PORT
      LAYER M4 ;
        RECT 0.000 153.504 0.192 153.528 ;
    END
  END lo_d[307]
  PIN lo_d[308]
    DIRECTION INPUT ;
    USE SIGNAL ;
    PORT
      LAYER M4 ;
        RECT 0.000 153.984 0.192 154.008 ;
    END
  END lo_d[308]
  PIN lo_d[309]
    DIRECTION INPUT ;
    USE SIGNAL ;
    PORT
      LAYER M4 ;
        RECT 0.000 154.464 0.192 154.488 ;
    END
  END lo_d[309]
  PIN lo_d[310]
    DIRECTION INPUT ;
    USE SIGNAL ;
    PORT
      LAYER M4 ;
        RECT 0.000 154.944 0.192 154.968 ;
    END
  END lo_d[310]
  PIN lo_d[311]
    DIRECTION INPUT ;
    USE SIGNAL ;
    PORT
      LAYER M4 ;
        RECT 0.000 155.472 0.192 155.496 ;
    END
  END lo_d[311]
  PIN lo_d[312]
    DIRECTION INPUT ;
    USE SIGNAL ;
    PORT
      LAYER M4 ;
        RECT 0.000 155.952 0.192 155.976 ;
    END
  END lo_d[312]
  PIN lo_d[313]
    DIRECTION INPUT ;
    USE SIGNAL ;
    PORT
      LAYER M4 ;
        RECT 0.000 156.432 0.192 156.456 ;
    END
  END lo_d[313]
  PIN lo_d[314]
    DIRECTION INPUT ;
    USE SIGNAL ;
    PORT
      LAYER M4 ;
        RECT 0.000 156.912 0.192 156.936 ;
    END
  END lo_d[314]
  PIN lo_d[315]
    DIRECTION INPUT ;
    USE SIGNAL ;
    PORT
      LAYER M4 ;
        RECT 0.000 157.440 0.192 157.464 ;
    END
  END lo_d[315]
  PIN lo_d[316]
    DIRECTION INPUT ;
    USE SIGNAL ;
    PORT
      LAYER M4 ;
        RECT 0.000 157.920 0.192 157.944 ;
    END
  END lo_d[316]
  PIN lo_d[317]
    DIRECTION INPUT ;
    USE SIGNAL ;
    PORT
      LAYER M4 ;
        RECT 0.000 158.400 0.192 158.424 ;
    END
  END lo_d[317]
  PIN lo_d[318]
    DIRECTION INPUT ;
    USE SIGNAL ;
    PORT
      LAYER M4 ;
        RECT 0.000 158.880 0.192 158.904 ;
    END
  END lo_d[318]
  PIN lo_d[319]
    DIRECTION INPUT ;
    USE SIGNAL ;
    PORT
      LAYER M4 ;
        RECT 0.000 159.408 0.192 159.432 ;
    END
  END lo_d[319]
  PIN lo_d[320]
    DIRECTION INPUT ;
    USE SIGNAL ;
    PORT
      LAYER M4 ;
        RECT 0.000 159.888 0.192 159.912 ;
    END
  END lo_d[320]
  PIN lo_d[321]
    DIRECTION INPUT ;
    USE SIGNAL ;
    PORT
      LAYER M4 ;
        RECT 0.000 160.368 0.192 160.392 ;
    END
  END lo_d[321]
  PIN lo_d[322]
    DIRECTION INPUT ;
    USE SIGNAL ;
    PORT
      LAYER M4 ;
        RECT 0.000 160.848 0.192 160.872 ;
    END
  END lo_d[322]
  PIN lo_d[323]
    DIRECTION INPUT ;
    USE SIGNAL ;
    PORT
      LAYER M4 ;
        RECT 0.000 161.376 0.192 161.400 ;
    END
  END lo_d[323]
  PIN lo_d[324]
    DIRECTION INPUT ;
    USE SIGNAL ;
    PORT
      LAYER M4 ;
        RECT 0.000 161.856 0.192 161.880 ;
    END
  END lo_d[324]
  PIN lo_d[325]
    DIRECTION INPUT ;
    USE SIGNAL ;
    PORT
      LAYER M4 ;
        RECT 0.000 162.336 0.192 162.360 ;
    END
  END lo_d[325]
  PIN lo_d[326]
    DIRECTION INPUT ;
    USE SIGNAL ;
    PORT
      LAYER M4 ;
        RECT 0.000 162.816 0.192 162.840 ;
    END
  END lo_d[326]
  PIN lo_d[327]
    DIRECTION INPUT ;
    USE SIGNAL ;
    PORT
      LAYER M4 ;
        RECT 0.000 163.344 0.192 163.368 ;
    END
  END lo_d[327]
  PIN lo_d[328]
    DIRECTION INPUT ;
    USE SIGNAL ;
    PORT
      LAYER M4 ;
        RECT 0.000 163.824 0.192 163.848 ;
    END
  END lo_d[328]
  PIN lo_d[329]
    DIRECTION INPUT ;
    USE SIGNAL ;
    PORT
      LAYER M4 ;
        RECT 0.000 164.304 0.192 164.328 ;
    END
  END lo_d[329]
  PIN lo_d[330]
    DIRECTION INPUT ;
    USE SIGNAL ;
    PORT
      LAYER M4 ;
        RECT 0.000 164.784 0.192 164.808 ;
    END
  END lo_d[330]
  PIN lo_d[331]
    DIRECTION INPUT ;
    USE SIGNAL ;
    PORT
      LAYER M4 ;
        RECT 0.000 165.312 0.192 165.336 ;
    END
  END lo_d[331]
  PIN lo_d[332]
    DIRECTION INPUT ;
    USE SIGNAL ;
    PORT
      LAYER M4 ;
        RECT 0.000 165.792 0.192 165.816 ;
    END
  END lo_d[332]
  PIN lo_d[333]
    DIRECTION INPUT ;
    USE SIGNAL ;
    PORT
      LAYER M4 ;
        RECT 0.000 166.272 0.192 166.296 ;
    END
  END lo_d[333]
  PIN lo_d[334]
    DIRECTION INPUT ;
    USE SIGNAL ;
    PORT
      LAYER M4 ;
        RECT 0.000 166.752 0.192 166.776 ;
    END
  END lo_d[334]
  PIN lo_d[335]
    DIRECTION INPUT ;
    USE SIGNAL ;
    PORT
      LAYER M4 ;
        RECT 0.000 167.280 0.192 167.304 ;
    END
  END lo_d[335]
  PIN lo_d[336]
    DIRECTION INPUT ;
    USE SIGNAL ;
    PORT
      LAYER M4 ;
        RECT 0.000 167.760 0.192 167.784 ;
    END
  END lo_d[336]
  PIN lo_d[337]
    DIRECTION INPUT ;
    USE SIGNAL ;
    PORT
      LAYER M4 ;
        RECT 0.000 168.240 0.192 168.264 ;
    END
  END lo_d[337]
  PIN lo_d[338]
    DIRECTION INPUT ;
    USE SIGNAL ;
    PORT
      LAYER M4 ;
        RECT 0.000 168.720 0.192 168.744 ;
    END
  END lo_d[338]
  PIN lo_d[339]
    DIRECTION INPUT ;
    USE SIGNAL ;
    PORT
      LAYER M4 ;
        RECT 0.000 169.248 0.192 169.272 ;
    END
  END lo_d[339]
  PIN lo_d[340]
    DIRECTION INPUT ;
    USE SIGNAL ;
    PORT
      LAYER M4 ;
        RECT 0.000 169.728 0.192 169.752 ;
    END
  END lo_d[340]
  PIN lo_d[341]
    DIRECTION INPUT ;
    USE SIGNAL ;
    PORT
      LAYER M4 ;
        RECT 0.000 170.208 0.192 170.232 ;
    END
  END lo_d[341]
  PIN lo_d[342]
    DIRECTION INPUT ;
    USE SIGNAL ;
    PORT
      LAYER M4 ;
        RECT 0.000 170.688 0.192 170.712 ;
    END
  END lo_d[342]
  PIN lo_d[343]
    DIRECTION INPUT ;
    USE SIGNAL ;
    PORT
      LAYER M4 ;
        RECT 0.000 171.216 0.192 171.240 ;
    END
  END lo_d[343]
  PIN lo_d[344]
    DIRECTION INPUT ;
    USE SIGNAL ;
    PORT
      LAYER M4 ;
        RECT 0.000 171.696 0.192 171.720 ;
    END
  END lo_d[344]
  PIN lo_d[345]
    DIRECTION INPUT ;
    USE SIGNAL ;
    PORT
      LAYER M4 ;
        RECT 0.000 172.176 0.192 172.200 ;
    END
  END lo_d[345]
  PIN lo_d[346]
    DIRECTION INPUT ;
    USE SIGNAL ;
    PORT
      LAYER M4 ;
        RECT 0.000 172.656 0.192 172.680 ;
    END
  END lo_d[346]
  PIN lo_d[347]
    DIRECTION INPUT ;
    USE SIGNAL ;
    PORT
      LAYER M4 ;
        RECT 0.000 173.184 0.192 173.208 ;
    END
  END lo_d[347]
  PIN lo_d[348]
    DIRECTION INPUT ;
    USE SIGNAL ;
    PORT
      LAYER M4 ;
        RECT 0.000 173.664 0.192 173.688 ;
    END
  END lo_d[348]
  PIN lo_d[349]
    DIRECTION INPUT ;
    USE SIGNAL ;
    PORT
      LAYER M4 ;
        RECT 0.000 174.144 0.192 174.168 ;
    END
  END lo_d[349]
  PIN lo_d[350]
    DIRECTION INPUT ;
    USE SIGNAL ;
    PORT
      LAYER M4 ;
        RECT 0.000 174.624 0.192 174.648 ;
    END
  END lo_d[350]
  PIN lo_d[351]
    DIRECTION INPUT ;
    USE SIGNAL ;
    PORT
      LAYER M4 ;
        RECT 0.000 175.152 0.192 175.176 ;
    END
  END lo_d[351]
  PIN lo_d[352]
    DIRECTION INPUT ;
    USE SIGNAL ;
    PORT
      LAYER M4 ;
        RECT 0.000 175.632 0.192 175.656 ;
    END
  END lo_d[352]
  PIN lo_d[353]
    DIRECTION INPUT ;
    USE SIGNAL ;
    PORT
      LAYER M4 ;
        RECT 0.000 176.112 0.192 176.136 ;
    END
  END lo_d[353]
  PIN lo_d[354]
    DIRECTION INPUT ;
    USE SIGNAL ;
    PORT
      LAYER M4 ;
        RECT 0.000 176.592 0.192 176.616 ;
    END
  END lo_d[354]
  PIN lo_d[355]
    DIRECTION INPUT ;
    USE SIGNAL ;
    PORT
      LAYER M4 ;
        RECT 0.000 177.120 0.192 177.144 ;
    END
  END lo_d[355]
  PIN lo_d[356]
    DIRECTION INPUT ;
    USE SIGNAL ;
    PORT
      LAYER M4 ;
        RECT 0.000 177.600 0.192 177.624 ;
    END
  END lo_d[356]
  PIN lo_d[357]
    DIRECTION INPUT ;
    USE SIGNAL ;
    PORT
      LAYER M4 ;
        RECT 0.000 178.080 0.192 178.104 ;
    END
  END lo_d[357]
  PIN lo_d[358]
    DIRECTION INPUT ;
    USE SIGNAL ;
    PORT
      LAYER M4 ;
        RECT 0.000 178.608 0.192 178.632 ;
    END
  END lo_d[358]
  PIN lo_d[359]
    DIRECTION INPUT ;
    USE SIGNAL ;
    PORT
      LAYER M4 ;
        RECT 0.000 179.088 0.192 179.112 ;
    END
  END lo_d[359]
  PIN lo_d[360]
    DIRECTION INPUT ;
    USE SIGNAL ;
    PORT
      LAYER M4 ;
        RECT 0.000 179.568 0.192 179.592 ;
    END
  END lo_d[360]
  PIN lo_d[361]
    DIRECTION INPUT ;
    USE SIGNAL ;
    PORT
      LAYER M4 ;
        RECT 0.000 180.048 0.192 180.072 ;
    END
  END lo_d[361]
  PIN lo_d[362]
    DIRECTION INPUT ;
    USE SIGNAL ;
    PORT
      LAYER M4 ;
        RECT 0.000 180.576 0.192 180.600 ;
    END
  END lo_d[362]
  PIN lo_d[363]
    DIRECTION INPUT ;
    USE SIGNAL ;
    PORT
      LAYER M4 ;
        RECT 0.000 181.056 0.192 181.080 ;
    END
  END lo_d[363]
  PIN lo_d[364]
    DIRECTION INPUT ;
    USE SIGNAL ;
    PORT
      LAYER M4 ;
        RECT 0.000 181.536 0.192 181.560 ;
    END
  END lo_d[364]
  PIN lo_d[365]
    DIRECTION INPUT ;
    USE SIGNAL ;
    PORT
      LAYER M4 ;
        RECT 0.000 182.016 0.192 182.040 ;
    END
  END lo_d[365]
  PIN lo_d[366]
    DIRECTION INPUT ;
    USE SIGNAL ;
    PORT
      LAYER M4 ;
        RECT 0.000 182.544 0.192 182.568 ;
    END
  END lo_d[366]
  PIN lo_d[367]
    DIRECTION INPUT ;
    USE SIGNAL ;
    PORT
      LAYER M4 ;
        RECT 0.000 183.024 0.192 183.048 ;
    END
  END lo_d[367]
  PIN lo_d[368]
    DIRECTION INPUT ;
    USE SIGNAL ;
    PORT
      LAYER M4 ;
        RECT 0.000 183.504 0.192 183.528 ;
    END
  END lo_d[368]
  PIN lo_d[369]
    DIRECTION INPUT ;
    USE SIGNAL ;
    PORT
      LAYER M4 ;
        RECT 0.000 183.984 0.192 184.008 ;
    END
  END lo_d[369]
  PIN lo_d[370]
    DIRECTION INPUT ;
    USE SIGNAL ;
    PORT
      LAYER M4 ;
        RECT 0.000 184.512 0.192 184.536 ;
    END
  END lo_d[370]
  PIN lo_d[371]
    DIRECTION INPUT ;
    USE SIGNAL ;
    PORT
      LAYER M4 ;
        RECT 0.000 184.992 0.192 185.016 ;
    END
  END lo_d[371]
  PIN lo_d[372]
    DIRECTION INPUT ;
    USE SIGNAL ;
    PORT
      LAYER M4 ;
        RECT 0.000 185.472 0.192 185.496 ;
    END
  END lo_d[372]
  PIN lo_d[373]
    DIRECTION INPUT ;
    USE SIGNAL ;
    PORT
      LAYER M4 ;
        RECT 0.000 185.952 0.192 185.976 ;
    END
  END lo_d[373]
  PIN lo_d[374]
    DIRECTION INPUT ;
    USE SIGNAL ;
    PORT
      LAYER M4 ;
        RECT 0.000 186.480 0.192 186.504 ;
    END
  END lo_d[374]
  PIN lo_d[375]
    DIRECTION INPUT ;
    USE SIGNAL ;
    PORT
      LAYER M4 ;
        RECT 0.000 186.960 0.192 186.984 ;
    END
  END lo_d[375]
  PIN lo_d[376]
    DIRECTION INPUT ;
    USE SIGNAL ;
    PORT
      LAYER M4 ;
        RECT 0.000 187.440 0.192 187.464 ;
    END
  END lo_d[376]
  PIN lo_d[377]
    DIRECTION INPUT ;
    USE SIGNAL ;
    PORT
      LAYER M4 ;
        RECT 0.000 187.920 0.192 187.944 ;
    END
  END lo_d[377]
  PIN lo_d[378]
    DIRECTION INPUT ;
    USE SIGNAL ;
    PORT
      LAYER M4 ;
        RECT 0.000 188.448 0.192 188.472 ;
    END
  END lo_d[378]
  PIN lo_d[379]
    DIRECTION INPUT ;
    USE SIGNAL ;
    PORT
      LAYER M4 ;
        RECT 0.000 188.928 0.192 188.952 ;
    END
  END lo_d[379]
  PIN lo_d[380]
    DIRECTION INPUT ;
    USE SIGNAL ;
    PORT
      LAYER M4 ;
        RECT 0.000 189.408 0.192 189.432 ;
    END
  END lo_d[380]
  PIN lo_d[381]
    DIRECTION INPUT ;
    USE SIGNAL ;
    PORT
      LAYER M4 ;
        RECT 0.000 189.888 0.192 189.912 ;
    END
  END lo_d[381]
  PIN lo_d[382]
    DIRECTION INPUT ;
    USE SIGNAL ;
    PORT
      LAYER M4 ;
        RECT 0.000 190.416 0.192 190.440 ;
    END
  END lo_d[382]
  PIN lo_d[383]
    DIRECTION INPUT ;
    USE SIGNAL ;
    PORT
      LAYER M4 ;
        RECT 0.000 190.896 0.192 190.920 ;
    END
  END lo_d[383]
  PIN lo_d[384]
    DIRECTION INPUT ;
    USE SIGNAL ;
    PORT
      LAYER M4 ;
        RECT 0.000 191.376 0.192 191.400 ;
    END
  END lo_d[384]
  PIN lo_d[385]
    DIRECTION INPUT ;
    USE SIGNAL ;
    PORT
      LAYER M4 ;
        RECT 0.000 191.856 0.192 191.880 ;
    END
  END lo_d[385]
  PIN lo_d[386]
    DIRECTION INPUT ;
    USE SIGNAL ;
    PORT
      LAYER M4 ;
        RECT 0.000 192.384 0.192 192.408 ;
    END
  END lo_d[386]
  PIN lo_d[387]
    DIRECTION INPUT ;
    USE SIGNAL ;
    PORT
      LAYER M4 ;
        RECT 0.000 192.864 0.192 192.888 ;
    END
  END lo_d[387]
  PIN lo_d[388]
    DIRECTION INPUT ;
    USE SIGNAL ;
    PORT
      LAYER M4 ;
        RECT 0.000 193.344 0.192 193.368 ;
    END
  END lo_d[388]
  PIN lo_d[389]
    DIRECTION INPUT ;
    USE SIGNAL ;
    PORT
      LAYER M4 ;
        RECT 0.000 193.824 0.192 193.848 ;
    END
  END lo_d[389]
  PIN lo_d[390]
    DIRECTION INPUT ;
    USE SIGNAL ;
    PORT
      LAYER M4 ;
        RECT 0.000 194.352 0.192 194.376 ;
    END
  END lo_d[390]
  PIN lo_d[391]
    DIRECTION INPUT ;
    USE SIGNAL ;
    PORT
      LAYER M4 ;
        RECT 0.000 194.832 0.192 194.856 ;
    END
  END lo_d[391]
  PIN lo_d[392]
    DIRECTION INPUT ;
    USE SIGNAL ;
    PORT
      LAYER M4 ;
        RECT 0.000 195.312 0.192 195.336 ;
    END
  END lo_d[392]
  PIN lo_d[393]
    DIRECTION INPUT ;
    USE SIGNAL ;
    PORT
      LAYER M4 ;
        RECT 0.000 195.792 0.192 195.816 ;
    END
  END lo_d[393]
  PIN lo_d[394]
    DIRECTION INPUT ;
    USE SIGNAL ;
    PORT
      LAYER M4 ;
        RECT 0.000 196.320 0.192 196.344 ;
    END
  END lo_d[394]
  PIN lo_d[395]
    DIRECTION INPUT ;
    USE SIGNAL ;
    PORT
      LAYER M4 ;
        RECT 0.000 196.800 0.192 196.824 ;
    END
  END lo_d[395]
  PIN lo_d[396]
    DIRECTION INPUT ;
    USE SIGNAL ;
    PORT
      LAYER M4 ;
        RECT 0.000 197.280 0.192 197.304 ;
    END
  END lo_d[396]
  PIN lo_d[397]
    DIRECTION INPUT ;
    USE SIGNAL ;
    PORT
      LAYER M4 ;
        RECT 0.000 197.760 0.192 197.784 ;
    END
  END lo_d[397]
  PIN lo_d[398]
    DIRECTION INPUT ;
    USE SIGNAL ;
    PORT
      LAYER M4 ;
        RECT 0.000 198.288 0.192 198.312 ;
    END
  END lo_d[398]
  PIN lo_d[399]
    DIRECTION INPUT ;
    USE SIGNAL ;
    PORT
      LAYER M4 ;
        RECT 0.000 198.768 0.192 198.792 ;
    END
  END lo_d[399]
  PIN lo_d[400]
    DIRECTION INPUT ;
    USE SIGNAL ;
    PORT
      LAYER M4 ;
        RECT 0.000 199.248 0.192 199.272 ;
    END
  END lo_d[400]
  PIN lo_d[401]
    DIRECTION INPUT ;
    USE SIGNAL ;
    PORT
      LAYER M4 ;
        RECT 0.000 199.728 0.192 199.752 ;
    END
  END lo_d[401]
  PIN lo_d[402]
    DIRECTION INPUT ;
    USE SIGNAL ;
    PORT
      LAYER M4 ;
        RECT 0.000 200.256 0.192 200.280 ;
    END
  END lo_d[402]
  PIN lo_d[403]
    DIRECTION INPUT ;
    USE SIGNAL ;
    PORT
      LAYER M4 ;
        RECT 0.000 200.736 0.192 200.760 ;
    END
  END lo_d[403]
  PIN lo_d[404]
    DIRECTION INPUT ;
    USE SIGNAL ;
    PORT
      LAYER M4 ;
        RECT 0.000 201.216 0.192 201.240 ;
    END
  END lo_d[404]
  PIN lo_d[405]
    DIRECTION INPUT ;
    USE SIGNAL ;
    PORT
      LAYER M4 ;
        RECT 0.000 201.696 0.192 201.720 ;
    END
  END lo_d[405]
  PIN lo_d[406]
    DIRECTION INPUT ;
    USE SIGNAL ;
    PORT
      LAYER M4 ;
        RECT 0.000 202.224 0.192 202.248 ;
    END
  END lo_d[406]
  PIN lo_d[407]
    DIRECTION INPUT ;
    USE SIGNAL ;
    PORT
      LAYER M4 ;
        RECT 0.000 202.704 0.192 202.728 ;
    END
  END lo_d[407]
  PIN lo_d[408]
    DIRECTION INPUT ;
    USE SIGNAL ;
    PORT
      LAYER M4 ;
        RECT 0.000 203.184 0.192 203.208 ;
    END
  END lo_d[408]
  PIN lo_d[409]
    DIRECTION INPUT ;
    USE SIGNAL ;
    PORT
      LAYER M4 ;
        RECT 0.000 203.664 0.192 203.688 ;
    END
  END lo_d[409]
  PIN lo_d[410]
    DIRECTION INPUT ;
    USE SIGNAL ;
    PORT
      LAYER M4 ;
        RECT 0.000 204.192 0.192 204.216 ;
    END
  END lo_d[410]
  PIN lo_d[411]
    DIRECTION INPUT ;
    USE SIGNAL ;
    PORT
      LAYER M4 ;
        RECT 0.000 204.672 0.192 204.696 ;
    END
  END lo_d[411]
  PIN lo_d[412]
    DIRECTION INPUT ;
    USE SIGNAL ;
    PORT
      LAYER M4 ;
        RECT 0.000 205.152 0.192 205.176 ;
    END
  END lo_d[412]
  PIN lo_d[413]
    DIRECTION INPUT ;
    USE SIGNAL ;
    PORT
      LAYER M4 ;
        RECT 0.000 205.632 0.192 205.656 ;
    END
  END lo_d[413]
  PIN lo_d[414]
    DIRECTION INPUT ;
    USE SIGNAL ;
    PORT
      LAYER M4 ;
        RECT 0.000 206.160 0.192 206.184 ;
    END
  END lo_d[414]
  PIN lo_d[415]
    DIRECTION INPUT ;
    USE SIGNAL ;
    PORT
      LAYER M4 ;
        RECT 0.000 206.640 0.192 206.664 ;
    END
  END lo_d[415]
  PIN lo_d[416]
    DIRECTION INPUT ;
    USE SIGNAL ;
    PORT
      LAYER M4 ;
        RECT 0.000 207.120 0.192 207.144 ;
    END
  END lo_d[416]
  PIN lo_d[417]
    DIRECTION INPUT ;
    USE SIGNAL ;
    PORT
      LAYER M4 ;
        RECT 0.000 207.600 0.192 207.624 ;
    END
  END lo_d[417]
  PIN lo_d[418]
    DIRECTION INPUT ;
    USE SIGNAL ;
    PORT
      LAYER M4 ;
        RECT 0.000 208.128 0.192 208.152 ;
    END
  END lo_d[418]
  PIN lo_d[419]
    DIRECTION INPUT ;
    USE SIGNAL ;
    PORT
      LAYER M4 ;
        RECT 0.000 208.608 0.192 208.632 ;
    END
  END lo_d[419]
  PIN lo_d[420]
    DIRECTION INPUT ;
    USE SIGNAL ;
    PORT
      LAYER M4 ;
        RECT 0.000 209.088 0.192 209.112 ;
    END
  END lo_d[420]
  PIN lo_d[421]
    DIRECTION INPUT ;
    USE SIGNAL ;
    PORT
      LAYER M4 ;
        RECT 0.000 209.568 0.192 209.592 ;
    END
  END lo_d[421]
  PIN lo_d[422]
    DIRECTION INPUT ;
    USE SIGNAL ;
    PORT
      LAYER M4 ;
        RECT 0.000 210.096 0.192 210.120 ;
    END
  END lo_d[422]
  PIN lo_d[423]
    DIRECTION INPUT ;
    USE SIGNAL ;
    PORT
      LAYER M4 ;
        RECT 0.000 210.576 0.192 210.600 ;
    END
  END lo_d[423]
  PIN lo_d[424]
    DIRECTION INPUT ;
    USE SIGNAL ;
    PORT
      LAYER M4 ;
        RECT 0.000 211.056 0.192 211.080 ;
    END
  END lo_d[424]
  PIN lo_d[425]
    DIRECTION INPUT ;
    USE SIGNAL ;
    PORT
      LAYER M4 ;
        RECT 0.000 211.536 0.192 211.560 ;
    END
  END lo_d[425]
  PIN lo_d[426]
    DIRECTION INPUT ;
    USE SIGNAL ;
    PORT
      LAYER M4 ;
        RECT 0.000 212.064 0.192 212.088 ;
    END
  END lo_d[426]
  PIN lo_d[427]
    DIRECTION INPUT ;
    USE SIGNAL ;
    PORT
      LAYER M4 ;
        RECT 0.000 212.544 0.192 212.568 ;
    END
  END lo_d[427]
  PIN lo_d[428]
    DIRECTION INPUT ;
    USE SIGNAL ;
    PORT
      LAYER M4 ;
        RECT 0.000 213.024 0.192 213.048 ;
    END
  END lo_d[428]
  PIN lo_d[429]
    DIRECTION INPUT ;
    USE SIGNAL ;
    PORT
      LAYER M4 ;
        RECT 0.000 213.504 0.192 213.528 ;
    END
  END lo_d[429]
  PIN lo_d[430]
    DIRECTION INPUT ;
    USE SIGNAL ;
    PORT
      LAYER M4 ;
        RECT 0.000 214.032 0.192 214.056 ;
    END
  END lo_d[430]
  PIN lo_d[431]
    DIRECTION INPUT ;
    USE SIGNAL ;
    PORT
      LAYER M4 ;
        RECT 0.000 214.512 0.192 214.536 ;
    END
  END lo_d[431]
  PIN lo_d[432]
    DIRECTION INPUT ;
    USE SIGNAL ;
    PORT
      LAYER M4 ;
        RECT 0.000 214.992 0.192 215.016 ;
    END
  END lo_d[432]
  PIN lo_d[433]
    DIRECTION INPUT ;
    USE SIGNAL ;
    PORT
      LAYER M4 ;
        RECT 0.000 215.472 0.192 215.496 ;
    END
  END lo_d[433]
  PIN lo_d[434]
    DIRECTION INPUT ;
    USE SIGNAL ;
    PORT
      LAYER M4 ;
        RECT 0.000 216.000 0.192 216.024 ;
    END
  END lo_d[434]
  PIN lo_d[435]
    DIRECTION INPUT ;
    USE SIGNAL ;
    PORT
      LAYER M4 ;
        RECT 0.000 216.480 0.192 216.504 ;
    END
  END lo_d[435]
  PIN lo_d[436]
    DIRECTION INPUT ;
    USE SIGNAL ;
    PORT
      LAYER M4 ;
        RECT 0.000 216.960 0.192 216.984 ;
    END
  END lo_d[436]
  PIN lo_d[437]
    DIRECTION INPUT ;
    USE SIGNAL ;
    PORT
      LAYER M4 ;
        RECT 0.000 217.488 0.192 217.512 ;
    END
  END lo_d[437]
  PIN lo_d[438]
    DIRECTION INPUT ;
    USE SIGNAL ;
    PORT
      LAYER M4 ;
        RECT 0.000 217.968 0.192 217.992 ;
    END
  END lo_d[438]
  PIN lo_d[439]
    DIRECTION INPUT ;
    USE SIGNAL ;
    PORT
      LAYER M4 ;
        RECT 0.000 218.448 0.192 218.472 ;
    END
  END lo_d[439]
  PIN lo_d[440]
    DIRECTION INPUT ;
    USE SIGNAL ;
    PORT
      LAYER M4 ;
        RECT 0.000 218.928 0.192 218.952 ;
    END
  END lo_d[440]
  PIN lo_d[441]
    DIRECTION INPUT ;
    USE SIGNAL ;
    PORT
      LAYER M4 ;
        RECT 0.000 219.456 0.192 219.480 ;
    END
  END lo_d[441]
  PIN lo_d[442]
    DIRECTION INPUT ;
    USE SIGNAL ;
    PORT
      LAYER M4 ;
        RECT 0.000 219.936 0.192 219.960 ;
    END
  END lo_d[442]
  PIN lo_d[443]
    DIRECTION INPUT ;
    USE SIGNAL ;
    PORT
      LAYER M4 ;
        RECT 0.000 220.416 0.192 220.440 ;
    END
  END lo_d[443]
  PIN lo_d[444]
    DIRECTION INPUT ;
    USE SIGNAL ;
    PORT
      LAYER M4 ;
        RECT 0.000 220.896 0.192 220.920 ;
    END
  END lo_d[444]
  PIN lo_d[445]
    DIRECTION INPUT ;
    USE SIGNAL ;
    PORT
      LAYER M4 ;
        RECT 0.000 221.424 0.192 221.448 ;
    END
  END lo_d[445]
  PIN lo_d[446]
    DIRECTION INPUT ;
    USE SIGNAL ;
    PORT
      LAYER M4 ;
        RECT 0.000 221.904 0.192 221.928 ;
    END
  END lo_d[446]
  PIN lo_d[447]
    DIRECTION INPUT ;
    USE SIGNAL ;
    PORT
      LAYER M4 ;
        RECT 0.000 222.384 0.192 222.408 ;
    END
  END lo_d[447]
  PIN lo_d[448]
    DIRECTION INPUT ;
    USE SIGNAL ;
    PORT
      LAYER M4 ;
        RECT 0.000 222.864 0.192 222.888 ;
    END
  END lo_d[448]
  PIN lo_d[449]
    DIRECTION INPUT ;
    USE SIGNAL ;
    PORT
      LAYER M4 ;
        RECT 0.000 223.392 0.192 223.416 ;
    END
  END lo_d[449]
  PIN lo_d[450]
    DIRECTION INPUT ;
    USE SIGNAL ;
    PORT
      LAYER M4 ;
        RECT 0.000 223.872 0.192 223.896 ;
    END
  END lo_d[450]
  PIN lo_d[451]
    DIRECTION INPUT ;
    USE SIGNAL ;
    PORT
      LAYER M4 ;
        RECT 0.000 224.352 0.192 224.376 ;
    END
  END lo_d[451]
  PIN lo_d[452]
    DIRECTION INPUT ;
    USE SIGNAL ;
    PORT
      LAYER M4 ;
        RECT 0.000 224.832 0.192 224.856 ;
    END
  END lo_d[452]
  PIN lo_d[453]
    DIRECTION INPUT ;
    USE SIGNAL ;
    PORT
      LAYER M4 ;
        RECT 0.000 225.360 0.192 225.384 ;
    END
  END lo_d[453]
  PIN lo_d[454]
    DIRECTION INPUT ;
    USE SIGNAL ;
    PORT
      LAYER M4 ;
        RECT 0.000 225.840 0.192 225.864 ;
    END
  END lo_d[454]
  PIN lo_d[455]
    DIRECTION INPUT ;
    USE SIGNAL ;
    PORT
      LAYER M4 ;
        RECT 0.000 226.320 0.192 226.344 ;
    END
  END lo_d[455]
  PIN lo_d[456]
    DIRECTION INPUT ;
    USE SIGNAL ;
    PORT
      LAYER M4 ;
        RECT 0.000 226.800 0.192 226.824 ;
    END
  END lo_d[456]
  PIN lo_d[457]
    DIRECTION INPUT ;
    USE SIGNAL ;
    PORT
      LAYER M4 ;
        RECT 0.000 227.328 0.192 227.352 ;
    END
  END lo_d[457]
  PIN lo_d[458]
    DIRECTION INPUT ;
    USE SIGNAL ;
    PORT
      LAYER M4 ;
        RECT 0.000 227.808 0.192 227.832 ;
    END
  END lo_d[458]
  PIN lo_d[459]
    DIRECTION INPUT ;
    USE SIGNAL ;
    PORT
      LAYER M4 ;
        RECT 0.000 228.288 0.192 228.312 ;
    END
  END lo_d[459]
  PIN lo_d[460]
    DIRECTION INPUT ;
    USE SIGNAL ;
    PORT
      LAYER M4 ;
        RECT 0.000 228.768 0.192 228.792 ;
    END
  END lo_d[460]
  PIN lo_d[461]
    DIRECTION INPUT ;
    USE SIGNAL ;
    PORT
      LAYER M4 ;
        RECT 0.000 229.296 0.192 229.320 ;
    END
  END lo_d[461]
  PIN lo_d[462]
    DIRECTION INPUT ;
    USE SIGNAL ;
    PORT
      LAYER M4 ;
        RECT 0.000 229.776 0.192 229.800 ;
    END
  END lo_d[462]
  PIN lo_d[463]
    DIRECTION INPUT ;
    USE SIGNAL ;
    PORT
      LAYER M4 ;
        RECT 0.000 230.256 0.192 230.280 ;
    END
  END lo_d[463]
  PIN lo_d[464]
    DIRECTION INPUT ;
    USE SIGNAL ;
    PORT
      LAYER M4 ;
        RECT 0.000 230.736 0.192 230.760 ;
    END
  END lo_d[464]
  PIN lo_d[465]
    DIRECTION INPUT ;
    USE SIGNAL ;
    PORT
      LAYER M4 ;
        RECT 0.000 231.264 0.192 231.288 ;
    END
  END lo_d[465]
  PIN lo_d[466]
    DIRECTION INPUT ;
    USE SIGNAL ;
    PORT
      LAYER M4 ;
        RECT 0.000 231.744 0.192 231.768 ;
    END
  END lo_d[466]
  PIN lo_d[467]
    DIRECTION INPUT ;
    USE SIGNAL ;
    PORT
      LAYER M4 ;
        RECT 0.000 232.224 0.192 232.248 ;
    END
  END lo_d[467]
  PIN lo_d[468]
    DIRECTION INPUT ;
    USE SIGNAL ;
    PORT
      LAYER M4 ;
        RECT 0.000 232.704 0.192 232.728 ;
    END
  END lo_d[468]
  PIN lo_d[469]
    DIRECTION INPUT ;
    USE SIGNAL ;
    PORT
      LAYER M4 ;
        RECT 0.000 233.232 0.192 233.256 ;
    END
  END lo_d[469]
  PIN lo_d[470]
    DIRECTION INPUT ;
    USE SIGNAL ;
    PORT
      LAYER M4 ;
        RECT 0.000 233.712 0.192 233.736 ;
    END
  END lo_d[470]
  PIN lo_d[471]
    DIRECTION INPUT ;
    USE SIGNAL ;
    PORT
      LAYER M4 ;
        RECT 0.000 234.192 0.192 234.216 ;
    END
  END lo_d[471]
  PIN lo_d[472]
    DIRECTION INPUT ;
    USE SIGNAL ;
    PORT
      LAYER M4 ;
        RECT 0.000 234.672 0.192 234.696 ;
    END
  END lo_d[472]
  PIN lo_d[473]
    DIRECTION INPUT ;
    USE SIGNAL ;
    PORT
      LAYER M4 ;
        RECT 0.000 235.200 0.192 235.224 ;
    END
  END lo_d[473]
  PIN lo_d[474]
    DIRECTION INPUT ;
    USE SIGNAL ;
    PORT
      LAYER M4 ;
        RECT 0.000 235.680 0.192 235.704 ;
    END
  END lo_d[474]
  PIN lo_d[475]
    DIRECTION INPUT ;
    USE SIGNAL ;
    PORT
      LAYER M4 ;
        RECT 0.000 236.160 0.192 236.184 ;
    END
  END lo_d[475]
  PIN lo_d[476]
    DIRECTION INPUT ;
    USE SIGNAL ;
    PORT
      LAYER M4 ;
        RECT 0.000 236.640 0.192 236.664 ;
    END
  END lo_d[476]
  PIN lo_d[477]
    DIRECTION INPUT ;
    USE SIGNAL ;
    PORT
      LAYER M4 ;
        RECT 0.000 237.168 0.192 237.192 ;
    END
  END lo_d[477]
  PIN lo_d[478]
    DIRECTION INPUT ;
    USE SIGNAL ;
    PORT
      LAYER M4 ;
        RECT 0.000 237.648 0.192 237.672 ;
    END
  END lo_d[478]
  PIN lo_d[479]
    DIRECTION INPUT ;
    USE SIGNAL ;
    PORT
      LAYER M4 ;
        RECT 0.000 238.128 0.192 238.152 ;
    END
  END lo_d[479]
  PIN lo_d[480]
    DIRECTION INPUT ;
    USE SIGNAL ;
    PORT
      LAYER M4 ;
        RECT 0.000 238.608 0.192 238.632 ;
    END
  END lo_d[480]
  PIN lo_d[481]
    DIRECTION INPUT ;
    USE SIGNAL ;
    PORT
      LAYER M4 ;
        RECT 0.000 239.136 0.192 239.160 ;
    END
  END lo_d[481]
  PIN lo_d[482]
    DIRECTION INPUT ;
    USE SIGNAL ;
    PORT
      LAYER M4 ;
        RECT 0.000 239.616 0.192 239.640 ;
    END
  END lo_d[482]
  PIN lo_d[483]
    DIRECTION INPUT ;
    USE SIGNAL ;
    PORT
      LAYER M4 ;
        RECT 0.000 240.096 0.192 240.120 ;
    END
  END lo_d[483]
  PIN lo_d[484]
    DIRECTION INPUT ;
    USE SIGNAL ;
    PORT
      LAYER M4 ;
        RECT 0.000 240.576 0.192 240.600 ;
    END
  END lo_d[484]
  PIN lo_d[485]
    DIRECTION INPUT ;
    USE SIGNAL ;
    PORT
      LAYER M4 ;
        RECT 0.000 241.104 0.192 241.128 ;
    END
  END lo_d[485]
  PIN lo_d[486]
    DIRECTION INPUT ;
    USE SIGNAL ;
    PORT
      LAYER M4 ;
        RECT 0.000 241.584 0.192 241.608 ;
    END
  END lo_d[486]
  PIN lo_d[487]
    DIRECTION INPUT ;
    USE SIGNAL ;
    PORT
      LAYER M4 ;
        RECT 0.000 242.064 0.192 242.088 ;
    END
  END lo_d[487]
  PIN lo_d[488]
    DIRECTION INPUT ;
    USE SIGNAL ;
    PORT
      LAYER M4 ;
        RECT 0.000 242.544 0.192 242.568 ;
    END
  END lo_d[488]
  PIN lo_d[489]
    DIRECTION INPUT ;
    USE SIGNAL ;
    PORT
      LAYER M4 ;
        RECT 0.000 243.072 0.192 243.096 ;
    END
  END lo_d[489]
  PIN lo_d[490]
    DIRECTION INPUT ;
    USE SIGNAL ;
    PORT
      LAYER M4 ;
        RECT 0.000 243.552 0.192 243.576 ;
    END
  END lo_d[490]
  PIN lo_d[491]
    DIRECTION INPUT ;
    USE SIGNAL ;
    PORT
      LAYER M4 ;
        RECT 0.000 244.032 0.192 244.056 ;
    END
  END lo_d[491]
  PIN lo_d[492]
    DIRECTION INPUT ;
    USE SIGNAL ;
    PORT
      LAYER M4 ;
        RECT 0.000 244.512 0.192 244.536 ;
    END
  END lo_d[492]
  PIN lo_d[493]
    DIRECTION INPUT ;
    USE SIGNAL ;
    PORT
      LAYER M4 ;
        RECT 0.000 245.040 0.192 245.064 ;
    END
  END lo_d[493]
  PIN lo_d[494]
    DIRECTION INPUT ;
    USE SIGNAL ;
    PORT
      LAYER M4 ;
        RECT 0.000 245.520 0.192 245.544 ;
    END
  END lo_d[494]
  PIN lo_d[495]
    DIRECTION INPUT ;
    USE SIGNAL ;
    PORT
      LAYER M4 ;
        RECT 0.000 246.000 0.192 246.024 ;
    END
  END lo_d[495]
  PIN lo_d[496]
    DIRECTION INPUT ;
    USE SIGNAL ;
    PORT
      LAYER M4 ;
        RECT 0.000 246.480 0.192 246.504 ;
    END
  END lo_d[496]
  PIN lo_d[497]
    DIRECTION INPUT ;
    USE SIGNAL ;
    PORT
      LAYER M4 ;
        RECT 0.000 247.008 0.192 247.032 ;
    END
  END lo_d[497]
  PIN lo_d[498]
    DIRECTION INPUT ;
    USE SIGNAL ;
    PORT
      LAYER M4 ;
        RECT 0.000 247.488 0.192 247.512 ;
    END
  END lo_d[498]
  PIN lo_d[499]
    DIRECTION INPUT ;
    USE SIGNAL ;
    PORT
      LAYER M4 ;
        RECT 0.000 247.968 0.192 247.992 ;
    END
  END lo_d[499]
  PIN lo_d[500]
    DIRECTION INPUT ;
    USE SIGNAL ;
    PORT
      LAYER M4 ;
        RECT 0.000 248.448 0.192 248.472 ;
    END
  END lo_d[500]
  PIN lo_d[501]
    DIRECTION INPUT ;
    USE SIGNAL ;
    PORT
      LAYER M4 ;
        RECT 0.000 248.976 0.192 249.000 ;
    END
  END lo_d[501]
  PIN lo_d[502]
    DIRECTION INPUT ;
    USE SIGNAL ;
    PORT
      LAYER M4 ;
        RECT 0.000 249.456 0.192 249.480 ;
    END
  END lo_d[502]
  PIN lo_d[503]
    DIRECTION INPUT ;
    USE SIGNAL ;
    PORT
      LAYER M4 ;
        RECT 0.000 249.936 0.192 249.960 ;
    END
  END lo_d[503]
  PIN lo_d[504]
    DIRECTION INPUT ;
    USE SIGNAL ;
    PORT
      LAYER M4 ;
        RECT 0.000 250.416 0.192 250.440 ;
    END
  END lo_d[504]
  PIN lo_d[505]
    DIRECTION INPUT ;
    USE SIGNAL ;
    PORT
      LAYER M4 ;
        RECT 0.000 250.944 0.192 250.968 ;
    END
  END lo_d[505]
  PIN lo_d[506]
    DIRECTION INPUT ;
    USE SIGNAL ;
    PORT
      LAYER M4 ;
        RECT 0.000 251.424 0.192 251.448 ;
    END
  END lo_d[506]
  PIN lo_d[507]
    DIRECTION INPUT ;
    USE SIGNAL ;
    PORT
      LAYER M4 ;
        RECT 0.000 251.904 0.192 251.928 ;
    END
  END lo_d[507]
  PIN lo_d[508]
    DIRECTION INPUT ;
    USE SIGNAL ;
    PORT
      LAYER M4 ;
        RECT 0.000 252.384 0.192 252.408 ;
    END
  END lo_d[508]
  PIN lo_d[509]
    DIRECTION INPUT ;
    USE SIGNAL ;
    PORT
      LAYER M4 ;
        RECT 0.000 252.912 0.192 252.936 ;
    END
  END lo_d[509]
  PIN lo_d[510]
    DIRECTION INPUT ;
    USE SIGNAL ;
    PORT
      LAYER M4 ;
        RECT 0.000 253.392 0.192 253.416 ;
    END
  END lo_d[510]
  PIN lo_d[511]
    DIRECTION INPUT ;
    USE SIGNAL ;
    PORT
      LAYER M4 ;
        RECT 0.000 253.872 0.192 253.896 ;
    END
  END lo_d[511]
  PIN lo_d[512]
    DIRECTION INPUT ;
    USE SIGNAL ;
    PORT
      LAYER M4 ;
        RECT 0.000 254.352 0.192 254.376 ;
    END
  END lo_d[512]
  PIN lo_d[513]
    DIRECTION INPUT ;
    USE SIGNAL ;
    PORT
      LAYER M4 ;
        RECT 0.000 254.880 0.192 254.904 ;
    END
  END lo_d[513]
  PIN lo_d[514]
    DIRECTION INPUT ;
    USE SIGNAL ;
    PORT
      LAYER M4 ;
        RECT 0.000 255.360 0.192 255.384 ;
    END
  END lo_d[514]
  PIN lo_d[515]
    DIRECTION INPUT ;
    USE SIGNAL ;
    PORT
      LAYER M4 ;
        RECT 0.000 255.840 0.192 255.864 ;
    END
  END lo_d[515]
  PIN lo_d[516]
    DIRECTION INPUT ;
    USE SIGNAL ;
    PORT
      LAYER M4 ;
        RECT 0.000 256.368 0.192 256.392 ;
    END
  END lo_d[516]
  PIN lo_d[517]
    DIRECTION INPUT ;
    USE SIGNAL ;
    PORT
      LAYER M4 ;
        RECT 0.000 256.848 0.192 256.872 ;
    END
  END lo_d[517]
  PIN lo_d[518]
    DIRECTION INPUT ;
    USE SIGNAL ;
    PORT
      LAYER M4 ;
        RECT 0.000 257.328 0.192 257.352 ;
    END
  END lo_d[518]
  PIN lo_d[519]
    DIRECTION INPUT ;
    USE SIGNAL ;
    PORT
      LAYER M4 ;
        RECT 0.000 257.808 0.192 257.832 ;
    END
  END lo_d[519]
  PIN lo_d[520]
    DIRECTION INPUT ;
    USE SIGNAL ;
    PORT
      LAYER M4 ;
        RECT 0.000 258.336 0.192 258.360 ;
    END
  END lo_d[520]
  PIN lo_d[521]
    DIRECTION INPUT ;
    USE SIGNAL ;
    PORT
      LAYER M4 ;
        RECT 0.000 258.816 0.192 258.840 ;
    END
  END lo_d[521]
  PIN lo_d[522]
    DIRECTION INPUT ;
    USE SIGNAL ;
    PORT
      LAYER M4 ;
        RECT 0.000 259.296 0.192 259.320 ;
    END
  END lo_d[522]
  PIN lo_d[523]
    DIRECTION INPUT ;
    USE SIGNAL ;
    PORT
      LAYER M4 ;
        RECT 0.000 259.776 0.192 259.800 ;
    END
  END lo_d[523]
  PIN lo_d[524]
    DIRECTION INPUT ;
    USE SIGNAL ;
    PORT
      LAYER M4 ;
        RECT 0.000 260.304 0.192 260.328 ;
    END
  END lo_d[524]
  PIN lo_d[525]
    DIRECTION INPUT ;
    USE SIGNAL ;
    PORT
      LAYER M4 ;
        RECT 0.000 260.784 0.192 260.808 ;
    END
  END lo_d[525]
  PIN lo_d[526]
    DIRECTION INPUT ;
    USE SIGNAL ;
    PORT
      LAYER M4 ;
        RECT 0.000 261.264 0.192 261.288 ;
    END
  END lo_d[526]
  PIN lo_d[527]
    DIRECTION INPUT ;
    USE SIGNAL ;
    PORT
      LAYER M4 ;
        RECT 0.000 261.744 0.192 261.768 ;
    END
  END lo_d[527]
  PIN lo_d[528]
    DIRECTION INPUT ;
    USE SIGNAL ;
    PORT
      LAYER M4 ;
        RECT 0.000 262.272 0.192 262.296 ;
    END
  END lo_d[528]
  PIN lo_d[529]
    DIRECTION INPUT ;
    USE SIGNAL ;
    PORT
      LAYER M4 ;
        RECT 0.000 262.752 0.192 262.776 ;
    END
  END lo_d[529]
  PIN lo_d[530]
    DIRECTION INPUT ;
    USE SIGNAL ;
    PORT
      LAYER M4 ;
        RECT 0.000 263.232 0.192 263.256 ;
    END
  END lo_d[530]
  PIN lo_d[531]
    DIRECTION INPUT ;
    USE SIGNAL ;
    PORT
      LAYER M4 ;
        RECT 0.000 263.712 0.192 263.736 ;
    END
  END lo_d[531]
  PIN lo_d[532]
    DIRECTION INPUT ;
    USE SIGNAL ;
    PORT
      LAYER M4 ;
        RECT 0.000 264.240 0.192 264.264 ;
    END
  END lo_d[532]
  PIN lo_d[533]
    DIRECTION INPUT ;
    USE SIGNAL ;
    PORT
      LAYER M4 ;
        RECT 0.000 264.720 0.192 264.744 ;
    END
  END lo_d[533]
  PIN lo_d[534]
    DIRECTION INPUT ;
    USE SIGNAL ;
    PORT
      LAYER M4 ;
        RECT 0.000 265.200 0.192 265.224 ;
    END
  END lo_d[534]
  PIN lo_d[535]
    DIRECTION INPUT ;
    USE SIGNAL ;
    PORT
      LAYER M4 ;
        RECT 0.000 265.680 0.192 265.704 ;
    END
  END lo_d[535]
  PIN lo_d[536]
    DIRECTION INPUT ;
    USE SIGNAL ;
    PORT
      LAYER M4 ;
        RECT 0.000 266.208 0.192 266.232 ;
    END
  END lo_d[536]
  PIN lo_d[537]
    DIRECTION INPUT ;
    USE SIGNAL ;
    PORT
      LAYER M4 ;
        RECT 0.000 266.688 0.192 266.712 ;
    END
  END lo_d[537]
  PIN lo_d[538]
    DIRECTION INPUT ;
    USE SIGNAL ;
    PORT
      LAYER M4 ;
        RECT 0.000 267.168 0.192 267.192 ;
    END
  END lo_d[538]
  PIN lo_d[539]
    DIRECTION INPUT ;
    USE SIGNAL ;
    PORT
      LAYER M4 ;
        RECT 0.000 267.648 0.192 267.672 ;
    END
  END lo_d[539]
  PIN lo_d[540]
    DIRECTION INPUT ;
    USE SIGNAL ;
    PORT
      LAYER M4 ;
        RECT 0.000 268.176 0.192 268.200 ;
    END
  END lo_d[540]
  PIN lo_d[541]
    DIRECTION INPUT ;
    USE SIGNAL ;
    PORT
      LAYER M4 ;
        RECT 0.000 268.656 0.192 268.680 ;
    END
  END lo_d[541]
  PIN lo_d[542]
    DIRECTION INPUT ;
    USE SIGNAL ;
    PORT
      LAYER M4 ;
        RECT 0.000 269.136 0.192 269.160 ;
    END
  END lo_d[542]
  PIN lo_d[543]
    DIRECTION INPUT ;
    USE SIGNAL ;
    PORT
      LAYER M4 ;
        RECT 0.000 269.616 0.192 269.640 ;
    END
  END lo_d[543]
  PIN lo_d[544]
    DIRECTION INPUT ;
    USE SIGNAL ;
    PORT
      LAYER M4 ;
        RECT 0.000 270.144 0.192 270.168 ;
    END
  END lo_d[544]
  PIN lo_d[545]
    DIRECTION INPUT ;
    USE SIGNAL ;
    PORT
      LAYER M4 ;
        RECT 0.000 270.624 0.192 270.648 ;
    END
  END lo_d[545]
  PIN lo_d[546]
    DIRECTION INPUT ;
    USE SIGNAL ;
    PORT
      LAYER M4 ;
        RECT 0.000 271.104 0.192 271.128 ;
    END
  END lo_d[546]
  PIN lo_d[547]
    DIRECTION INPUT ;
    USE SIGNAL ;
    PORT
      LAYER M4 ;
        RECT 0.000 271.584 0.192 271.608 ;
    END
  END lo_d[547]
  PIN lo_d[548]
    DIRECTION INPUT ;
    USE SIGNAL ;
    PORT
      LAYER M4 ;
        RECT 0.000 272.112 0.192 272.136 ;
    END
  END lo_d[548]
  PIN lo_d[549]
    DIRECTION INPUT ;
    USE SIGNAL ;
    PORT
      LAYER M4 ;
        RECT 0.000 272.592 0.192 272.616 ;
    END
  END lo_d[549]
  PIN lo_d[550]
    DIRECTION INPUT ;
    USE SIGNAL ;
    PORT
      LAYER M4 ;
        RECT 0.000 273.072 0.192 273.096 ;
    END
  END lo_d[550]
  PIN lo_d[551]
    DIRECTION INPUT ;
    USE SIGNAL ;
    PORT
      LAYER M4 ;
        RECT 0.000 273.552 0.192 273.576 ;
    END
  END lo_d[551]
  PIN lo_d[552]
    DIRECTION INPUT ;
    USE SIGNAL ;
    PORT
      LAYER M4 ;
        RECT 0.000 274.080 0.192 274.104 ;
    END
  END lo_d[552]
  PIN li_v
    DIRECTION OUTPUT ;
    USE SIGNAL ;
    PORT
      LAYER M4 ;
        RECT 0.000 307.248 0.192 307.272 ;
    END
  END li_v
  PIN li_r
    DIRECTION INPUT ;
    USE SIGNAL ;
    PORT
      LAYER M4 ;
        RECT 0.000 309.408 0.192 309.432 ;
    END
  END li_r
  PIN li_d[0]
    DIRECTION OUTPUT ;
    USE SIGNAL ;
    PORT
      LAYER M4 ;
        RECT 0.000 317.760 0.192 317.784 ;
    END
  END li_d[0]
  PIN li_d[1]
    DIRECTION OUTPUT ;
    USE SIGNAL ;
    PORT
      LAYER M4 ;
        RECT 0.000 318.240 0.192 318.264 ;
    END
  END li_d[1]
  PIN li_d[2]
    DIRECTION OUTPUT ;
    USE SIGNAL ;
    PORT
      LAYER M4 ;
        RECT 0.000 318.720 0.192 318.744 ;
    END
  END li_d[2]
  PIN li_d[3]
    DIRECTION OUTPUT ;
    USE SIGNAL ;
    PORT
      LAYER M4 ;
        RECT 0.000 319.152 0.192 319.176 ;
    END
  END li_d[3]
  PIN li_d[4]
    DIRECTION OUTPUT ;
    USE SIGNAL ;
    PORT
      LAYER M4 ;
        RECT 0.000 319.632 0.192 319.656 ;
    END
  END li_d[4]
  PIN li_d[5]
    DIRECTION OUTPUT ;
    USE SIGNAL ;
    PORT
      LAYER M4 ;
        RECT 0.000 320.112 0.192 320.136 ;
    END
  END li_d[5]
  PIN li_d[6]
    DIRECTION OUTPUT ;
    USE SIGNAL ;
    PORT
      LAYER M4 ;
        RECT 0.000 320.592 0.192 320.616 ;
    END
  END li_d[6]
  PIN li_d[7]
    DIRECTION OUTPUT ;
    USE SIGNAL ;
    PORT
      LAYER M4 ;
        RECT 0.000 321.072 0.192 321.096 ;
    END
  END li_d[7]
  PIN li_d[8]
    DIRECTION OUTPUT ;
    USE SIGNAL ;
    PORT
      LAYER M4 ;
        RECT 0.000 321.552 0.192 321.576 ;
    END
  END li_d[8]
  PIN li_d[9]
    DIRECTION OUTPUT ;
    USE SIGNAL ;
    PORT
      LAYER M4 ;
        RECT 0.000 322.032 0.192 322.056 ;
    END
  END li_d[9]
  PIN li_d[10]
    DIRECTION OUTPUT ;
    USE SIGNAL ;
    PORT
      LAYER M4 ;
        RECT 0.000 322.512 0.192 322.536 ;
    END
  END li_d[10]
  PIN li_d[11]
    DIRECTION OUTPUT ;
    USE SIGNAL ;
    PORT
      LAYER M4 ;
        RECT 0.000 322.992 0.192 323.016 ;
    END
  END li_d[11]
  PIN li_d[12]
    DIRECTION OUTPUT ;
    USE SIGNAL ;
    PORT
      LAYER M4 ;
        RECT 0.000 323.472 0.192 323.496 ;
    END
  END li_d[12]
  PIN li_d[13]
    DIRECTION OUTPUT ;
    USE SIGNAL ;
    PORT
      LAYER M4 ;
        RECT 0.000 323.952 0.192 323.976 ;
    END
  END li_d[13]
  PIN li_d[14]
    DIRECTION OUTPUT ;
    USE SIGNAL ;
    PORT
      LAYER M4 ;
        RECT 0.000 324.432 0.192 324.456 ;
    END
  END li_d[14]
  PIN li_d[15]
    DIRECTION OUTPUT ;
    USE SIGNAL ;
    PORT
      LAYER M4 ;
        RECT 0.000 324.912 0.192 324.936 ;
    END
  END li_d[15]
  PIN li_d[16]
    DIRECTION OUTPUT ;
    USE SIGNAL ;
    PORT
      LAYER M4 ;
        RECT 0.000 325.392 0.192 325.416 ;
    END
  END li_d[16]
  PIN li_d[17]
    DIRECTION OUTPUT ;
    USE SIGNAL ;
    PORT
      LAYER M4 ;
        RECT 0.000 325.824 0.192 325.848 ;
    END
  END li_d[17]
  PIN li_d[18]
    DIRECTION OUTPUT ;
    USE SIGNAL ;
    PORT
      LAYER M4 ;
        RECT 0.000 326.304 0.192 326.328 ;
    END
  END li_d[18]
  PIN li_d[19]
    DIRECTION OUTPUT ;
    USE SIGNAL ;
    PORT
      LAYER M4 ;
        RECT 0.000 326.784 0.192 326.808 ;
    END
  END li_d[19]
  PIN li_d[20]
    DIRECTION OUTPUT ;
    USE SIGNAL ;
    PORT
      LAYER M4 ;
        RECT 0.000 327.264 0.192 327.288 ;
    END
  END li_d[20]
  PIN li_d[21]
    DIRECTION OUTPUT ;
    USE SIGNAL ;
    PORT
      LAYER M4 ;
        RECT 0.000 327.744 0.192 327.768 ;
    END
  END li_d[21]
  PIN li_d[22]
    DIRECTION OUTPUT ;
    USE SIGNAL ;
    PORT
      LAYER M4 ;
        RECT 0.000 328.224 0.192 328.248 ;
    END
  END li_d[22]
  PIN li_d[23]
    DIRECTION OUTPUT ;
    USE SIGNAL ;
    PORT
      LAYER M4 ;
        RECT 0.000 328.704 0.192 328.728 ;
    END
  END li_d[23]
  PIN li_d[24]
    DIRECTION OUTPUT ;
    USE SIGNAL ;
    PORT
      LAYER M4 ;
        RECT 0.000 329.184 0.192 329.208 ;
    END
  END li_d[24]
  PIN li_d[25]
    DIRECTION OUTPUT ;
    USE SIGNAL ;
    PORT
      LAYER M4 ;
        RECT 0.000 329.664 0.192 329.688 ;
    END
  END li_d[25]
  PIN li_d[26]
    DIRECTION OUTPUT ;
    USE SIGNAL ;
    PORT
      LAYER M4 ;
        RECT 0.000 330.144 0.192 330.168 ;
    END
  END li_d[26]
  PIN li_d[27]
    DIRECTION OUTPUT ;
    USE SIGNAL ;
    PORT
      LAYER M4 ;
        RECT 0.000 330.624 0.192 330.648 ;
    END
  END li_d[27]
  PIN li_d[28]
    DIRECTION OUTPUT ;
    USE SIGNAL ;
    PORT
      LAYER M4 ;
        RECT 0.000 331.104 0.192 331.128 ;
    END
  END li_d[28]
  PIN li_d[29]
    DIRECTION OUTPUT ;
    USE SIGNAL ;
    PORT
      LAYER M4 ;
        RECT 0.000 331.584 0.192 331.608 ;
    END
  END li_d[29]
  PIN li_d[30]
    DIRECTION OUTPUT ;
    USE SIGNAL ;
    PORT
      LAYER M4 ;
        RECT 0.000 332.064 0.192 332.088 ;
    END
  END li_d[30]
  PIN li_d[31]
    DIRECTION OUTPUT ;
    USE SIGNAL ;
    PORT
      LAYER M4 ;
        RECT 0.000 332.496 0.192 332.520 ;
    END
  END li_d[31]
  PIN li_d[32]
    DIRECTION OUTPUT ;
    USE SIGNAL ;
    PORT
      LAYER M4 ;
        RECT 0.000 332.976 0.192 333.000 ;
    END
  END li_d[32]
  PIN li_d[33]
    DIRECTION OUTPUT ;
    USE SIGNAL ;
    PORT
      LAYER M4 ;
        RECT 0.000 333.456 0.192 333.480 ;
    END
  END li_d[33]
  PIN li_d[34]
    DIRECTION OUTPUT ;
    USE SIGNAL ;
    PORT
      LAYER M4 ;
        RECT 0.000 333.936 0.192 333.960 ;
    END
  END li_d[34]
  PIN li_d[35]
    DIRECTION OUTPUT ;
    USE SIGNAL ;
    PORT
      LAYER M4 ;
        RECT 0.000 334.416 0.192 334.440 ;
    END
  END li_d[35]
  PIN li_d[36]
    DIRECTION OUTPUT ;
    USE SIGNAL ;
    PORT
      LAYER M4 ;
        RECT 0.000 334.896 0.192 334.920 ;
    END
  END li_d[36]
  PIN li_d[37]
    DIRECTION OUTPUT ;
    USE SIGNAL ;
    PORT
      LAYER M4 ;
        RECT 0.000 335.376 0.192 335.400 ;
    END
  END li_d[37]
  PIN li_d[38]
    DIRECTION OUTPUT ;
    USE SIGNAL ;
    PORT
      LAYER M4 ;
        RECT 0.000 335.856 0.192 335.880 ;
    END
  END li_d[38]
  PIN li_d[39]
    DIRECTION OUTPUT ;
    USE SIGNAL ;
    PORT
      LAYER M4 ;
        RECT 0.000 336.336 0.192 336.360 ;
    END
  END li_d[39]
  PIN li_d[40]
    DIRECTION OUTPUT ;
    USE SIGNAL ;
    PORT
      LAYER M4 ;
        RECT 0.000 336.816 0.192 336.840 ;
    END
  END li_d[40]
  PIN li_d[41]
    DIRECTION OUTPUT ;
    USE SIGNAL ;
    PORT
      LAYER M4 ;
        RECT 0.000 337.296 0.192 337.320 ;
    END
  END li_d[41]
  PIN li_d[42]
    DIRECTION OUTPUT ;
    USE SIGNAL ;
    PORT
      LAYER M4 ;
        RECT 0.000 337.776 0.192 337.800 ;
    END
  END li_d[42]
  PIN li_d[43]
    DIRECTION OUTPUT ;
    USE SIGNAL ;
    PORT
      LAYER M4 ;
        RECT 0.000 338.256 0.192 338.280 ;
    END
  END li_d[43]
  PIN li_d[44]
    DIRECTION OUTPUT ;
    USE SIGNAL ;
    PORT
      LAYER M4 ;
        RECT 0.000 338.736 0.192 338.760 ;
    END
  END li_d[44]
  PIN li_d[45]
    DIRECTION OUTPUT ;
    USE SIGNAL ;
    PORT
      LAYER M4 ;
        RECT 0.000 339.168 0.192 339.192 ;
    END
  END li_d[45]
  PIN li_d[46]
    DIRECTION OUTPUT ;
    USE SIGNAL ;
    PORT
      LAYER M4 ;
        RECT 0.000 339.648 0.192 339.672 ;
    END
  END li_d[46]
  PIN li_d[47]
    DIRECTION OUTPUT ;
    USE SIGNAL ;
    PORT
      LAYER M4 ;
        RECT 0.000 340.128 0.192 340.152 ;
    END
  END li_d[47]
  PIN li_d[48]
    DIRECTION OUTPUT ;
    USE SIGNAL ;
    PORT
      LAYER M4 ;
        RECT 0.000 340.608 0.192 340.632 ;
    END
  END li_d[48]
  PIN li_d[49]
    DIRECTION OUTPUT ;
    USE SIGNAL ;
    PORT
      LAYER M4 ;
        RECT 0.000 341.088 0.192 341.112 ;
    END
  END li_d[49]
  PIN li_d[50]
    DIRECTION OUTPUT ;
    USE SIGNAL ;
    PORT
      LAYER M4 ;
        RECT 0.000 341.568 0.192 341.592 ;
    END
  END li_d[50]
  PIN li_d[51]
    DIRECTION OUTPUT ;
    USE SIGNAL ;
    PORT
      LAYER M4 ;
        RECT 0.000 342.048 0.192 342.072 ;
    END
  END li_d[51]
  PIN li_d[52]
    DIRECTION OUTPUT ;
    USE SIGNAL ;
    PORT
      LAYER M4 ;
        RECT 0.000 342.528 0.192 342.552 ;
    END
  END li_d[52]
  PIN li_d[53]
    DIRECTION OUTPUT ;
    USE SIGNAL ;
    PORT
      LAYER M4 ;
        RECT 0.000 343.008 0.192 343.032 ;
    END
  END li_d[53]
  PIN li_d[54]
    DIRECTION OUTPUT ;
    USE SIGNAL ;
    PORT
      LAYER M4 ;
        RECT 0.000 343.488 0.192 343.512 ;
    END
  END li_d[54]
  PIN li_d[55]
    DIRECTION OUTPUT ;
    USE SIGNAL ;
    PORT
      LAYER M4 ;
        RECT 0.000 343.968 0.192 343.992 ;
    END
  END li_d[55]
  PIN li_d[56]
    DIRECTION OUTPUT ;
    USE SIGNAL ;
    PORT
      LAYER M4 ;
        RECT 0.000 344.448 0.192 344.472 ;
    END
  END li_d[56]
  PIN li_d[57]
    DIRECTION OUTPUT ;
    USE SIGNAL ;
    PORT
      LAYER M4 ;
        RECT 0.000 344.928 0.192 344.952 ;
    END
  END li_d[57]
  PIN li_d[58]
    DIRECTION OUTPUT ;
    USE SIGNAL ;
    PORT
      LAYER M4 ;
        RECT 0.000 345.408 0.192 345.432 ;
    END
  END li_d[58]
  PIN li_d[59]
    DIRECTION OUTPUT ;
    USE SIGNAL ;
    PORT
      LAYER M4 ;
        RECT 0.000 345.840 0.192 345.864 ;
    END
  END li_d[59]
  PIN li_d[60]
    DIRECTION OUTPUT ;
    USE SIGNAL ;
    PORT
      LAYER M4 ;
        RECT 0.000 346.320 0.192 346.344 ;
    END
  END li_d[60]
  PIN li_d[61]
    DIRECTION OUTPUT ;
    USE SIGNAL ;
    PORT
      LAYER M4 ;
        RECT 0.000 346.800 0.192 346.824 ;
    END
  END li_d[61]
  PIN li_d[62]
    DIRECTION OUTPUT ;
    USE SIGNAL ;
    PORT
      LAYER M4 ;
        RECT 0.000 347.280 0.192 347.304 ;
    END
  END li_d[62]
  PIN li_d[63]
    DIRECTION OUTPUT ;
    USE SIGNAL ;
    PORT
      LAYER M4 ;
        RECT 0.000 347.760 0.192 347.784 ;
    END
  END li_d[63]
  PIN li_d[64]
    DIRECTION OUTPUT ;
    USE SIGNAL ;
    PORT
      LAYER M4 ;
        RECT 0.000 348.240 0.192 348.264 ;
    END
  END li_d[64]
  PIN li_d[65]
    DIRECTION OUTPUT ;
    USE SIGNAL ;
    PORT
      LAYER M4 ;
        RECT 0.000 348.720 0.192 348.744 ;
    END
  END li_d[65]
  PIN li_d[66]
    DIRECTION OUTPUT ;
    USE SIGNAL ;
    PORT
      LAYER M4 ;
        RECT 0.000 349.200 0.192 349.224 ;
    END
  END li_d[66]
  PIN li_d[67]
    DIRECTION OUTPUT ;
    USE SIGNAL ;
    PORT
      LAYER M4 ;
        RECT 0.000 349.680 0.192 349.704 ;
    END
  END li_d[67]
  PIN li_d[68]
    DIRECTION OUTPUT ;
    USE SIGNAL ;
    PORT
      LAYER M4 ;
        RECT 0.000 350.160 0.192 350.184 ;
    END
  END li_d[68]
  PIN li_d[69]
    DIRECTION OUTPUT ;
    USE SIGNAL ;
    PORT
      LAYER M4 ;
        RECT 0.000 350.640 0.192 350.664 ;
    END
  END li_d[69]
  PIN li_d[70]
    DIRECTION OUTPUT ;
    USE SIGNAL ;
    PORT
      LAYER M4 ;
        RECT 0.000 351.120 0.192 351.144 ;
    END
  END li_d[70]
  PIN li_d[71]
    DIRECTION OUTPUT ;
    USE SIGNAL ;
    PORT
      LAYER M4 ;
        RECT 0.000 351.600 0.192 351.624 ;
    END
  END li_d[71]
  PIN li_d[72]
    DIRECTION OUTPUT ;
    USE SIGNAL ;
    PORT
      LAYER M4 ;
        RECT 0.000 352.080 0.192 352.104 ;
    END
  END li_d[72]
  PIN li_d[73]
    DIRECTION OUTPUT ;
    USE SIGNAL ;
    PORT
      LAYER M4 ;
        RECT 0.000 352.512 0.192 352.536 ;
    END
  END li_d[73]
  PIN li_d[74]
    DIRECTION OUTPUT ;
    USE SIGNAL ;
    PORT
      LAYER M4 ;
        RECT 0.000 352.992 0.192 353.016 ;
    END
  END li_d[74]
  PIN li_d[75]
    DIRECTION OUTPUT ;
    USE SIGNAL ;
    PORT
      LAYER M4 ;
        RECT 0.000 353.472 0.192 353.496 ;
    END
  END li_d[75]
  PIN li_d[76]
    DIRECTION OUTPUT ;
    USE SIGNAL ;
    PORT
      LAYER M4 ;
        RECT 0.000 353.952 0.192 353.976 ;
    END
  END li_d[76]
  PIN li_d[77]
    DIRECTION OUTPUT ;
    USE SIGNAL ;
    PORT
      LAYER M4 ;
        RECT 0.000 354.432 0.192 354.456 ;
    END
  END li_d[77]
  PIN li_d[78]
    DIRECTION OUTPUT ;
    USE SIGNAL ;
    PORT
      LAYER M4 ;
        RECT 0.000 354.912 0.192 354.936 ;
    END
  END li_d[78]
  PIN li_d[79]
    DIRECTION OUTPUT ;
    USE SIGNAL ;
    PORT
      LAYER M4 ;
        RECT 0.000 355.392 0.192 355.416 ;
    END
  END li_d[79]
  PIN li_d[80]
    DIRECTION OUTPUT ;
    USE SIGNAL ;
    PORT
      LAYER M4 ;
        RECT 0.000 355.872 0.192 355.896 ;
    END
  END li_d[80]
  PIN li_d[81]
    DIRECTION OUTPUT ;
    USE SIGNAL ;
    PORT
      LAYER M4 ;
        RECT 0.000 356.352 0.192 356.376 ;
    END
  END li_d[81]
  PIN li_d[82]
    DIRECTION OUTPUT ;
    USE SIGNAL ;
    PORT
      LAYER M4 ;
        RECT 0.000 356.832 0.192 356.856 ;
    END
  END li_d[82]
  PIN li_d[83]
    DIRECTION OUTPUT ;
    USE SIGNAL ;
    PORT
      LAYER M4 ;
        RECT 0.000 357.312 0.192 357.336 ;
    END
  END li_d[83]
  PIN li_d[84]
    DIRECTION OUTPUT ;
    USE SIGNAL ;
    PORT
      LAYER M4 ;
        RECT 0.000 357.792 0.192 357.816 ;
    END
  END li_d[84]
  PIN li_d[85]
    DIRECTION OUTPUT ;
    USE SIGNAL ;
    PORT
      LAYER M4 ;
        RECT 0.000 358.272 0.192 358.296 ;
    END
  END li_d[85]
  PIN li_d[86]
    DIRECTION OUTPUT ;
    USE SIGNAL ;
    PORT
      LAYER M4 ;
        RECT 0.000 358.704 0.192 358.728 ;
    END
  END li_d[86]
  PIN li_d[87]
    DIRECTION OUTPUT ;
    USE SIGNAL ;
    PORT
      LAYER M4 ;
        RECT 0.000 359.184 0.192 359.208 ;
    END
  END li_d[87]
  PIN li_d[88]
    DIRECTION OUTPUT ;
    USE SIGNAL ;
    PORT
      LAYER M4 ;
        RECT 0.000 359.664 0.192 359.688 ;
    END
  END li_d[88]
  PIN li_d[89]
    DIRECTION OUTPUT ;
    USE SIGNAL ;
    PORT
      LAYER M4 ;
        RECT 0.000 360.144 0.192 360.168 ;
    END
  END li_d[89]
  PIN li_d[90]
    DIRECTION OUTPUT ;
    USE SIGNAL ;
    PORT
      LAYER M4 ;
        RECT 0.000 360.624 0.192 360.648 ;
    END
  END li_d[90]
  PIN li_d[91]
    DIRECTION OUTPUT ;
    USE SIGNAL ;
    PORT
      LAYER M4 ;
        RECT 0.000 361.104 0.192 361.128 ;
    END
  END li_d[91]
  PIN li_d[92]
    DIRECTION OUTPUT ;
    USE SIGNAL ;
    PORT
      LAYER M4 ;
        RECT 0.000 361.584 0.192 361.608 ;
    END
  END li_d[92]
  PIN li_d[93]
    DIRECTION OUTPUT ;
    USE SIGNAL ;
    PORT
      LAYER M4 ;
        RECT 0.000 362.064 0.192 362.088 ;
    END
  END li_d[93]
  PIN li_d[94]
    DIRECTION OUTPUT ;
    USE SIGNAL ;
    PORT
      LAYER M4 ;
        RECT 0.000 362.544 0.192 362.568 ;
    END
  END li_d[94]
  PIN li_d[95]
    DIRECTION OUTPUT ;
    USE SIGNAL ;
    PORT
      LAYER M4 ;
        RECT 0.000 363.024 0.192 363.048 ;
    END
  END li_d[95]
  PIN li_d[96]
    DIRECTION OUTPUT ;
    USE SIGNAL ;
    PORT
      LAYER M4 ;
        RECT 0.000 363.504 0.192 363.528 ;
    END
  END li_d[96]
  PIN li_d[97]
    DIRECTION OUTPUT ;
    USE SIGNAL ;
    PORT
      LAYER M4 ;
        RECT 0.000 363.984 0.192 364.008 ;
    END
  END li_d[97]
  PIN li_d[98]
    DIRECTION OUTPUT ;
    USE SIGNAL ;
    PORT
      LAYER M4 ;
        RECT 0.000 364.464 0.192 364.488 ;
    END
  END li_d[98]
  PIN li_d[99]
    DIRECTION OUTPUT ;
    USE SIGNAL ;
    PORT
      LAYER M4 ;
        RECT 0.000 364.944 0.192 364.968 ;
    END
  END li_d[99]
  PIN li_d[100]
    DIRECTION OUTPUT ;
    USE SIGNAL ;
    PORT
      LAYER M4 ;
        RECT 0.000 365.376 0.192 365.400 ;
    END
  END li_d[100]
  PIN li_d[101]
    DIRECTION OUTPUT ;
    USE SIGNAL ;
    PORT
      LAYER M4 ;
        RECT 0.000 365.856 0.192 365.880 ;
    END
  END li_d[101]
  PIN li_d[102]
    DIRECTION OUTPUT ;
    USE SIGNAL ;
    PORT
      LAYER M4 ;
        RECT 0.000 366.336 0.192 366.360 ;
    END
  END li_d[102]
  PIN li_d[103]
    DIRECTION OUTPUT ;
    USE SIGNAL ;
    PORT
      LAYER M4 ;
        RECT 0.000 366.816 0.192 366.840 ;
    END
  END li_d[103]
  PIN li_d[104]
    DIRECTION OUTPUT ;
    USE SIGNAL ;
    PORT
      LAYER M4 ;
        RECT 0.000 367.296 0.192 367.320 ;
    END
  END li_d[104]
  PIN li_d[105]
    DIRECTION OUTPUT ;
    USE SIGNAL ;
    PORT
      LAYER M4 ;
        RECT 0.000 367.776 0.192 367.800 ;
    END
  END li_d[105]
  PIN li_d[106]
    DIRECTION OUTPUT ;
    USE SIGNAL ;
    PORT
      LAYER M4 ;
        RECT 0.000 368.256 0.192 368.280 ;
    END
  END li_d[106]
  PIN li_d[107]
    DIRECTION OUTPUT ;
    USE SIGNAL ;
    PORT
      LAYER M4 ;
        RECT 0.000 368.736 0.192 368.760 ;
    END
  END li_d[107]
  PIN li_d[108]
    DIRECTION OUTPUT ;
    USE SIGNAL ;
    PORT
      LAYER M4 ;
        RECT 0.000 369.216 0.192 369.240 ;
    END
  END li_d[108]
  PIN li_d[109]
    DIRECTION OUTPUT ;
    USE SIGNAL ;
    PORT
      LAYER M4 ;
        RECT 0.000 369.696 0.192 369.720 ;
    END
  END li_d[109]
  PIN li_d[110]
    DIRECTION OUTPUT ;
    USE SIGNAL ;
    PORT
      LAYER M4 ;
        RECT 0.000 370.176 0.192 370.200 ;
    END
  END li_d[110]
  PIN li_d[111]
    DIRECTION OUTPUT ;
    USE SIGNAL ;
    PORT
      LAYER M4 ;
        RECT 0.000 370.656 0.192 370.680 ;
    END
  END li_d[111]
  PIN li_d[112]
    DIRECTION OUTPUT ;
    USE SIGNAL ;
    PORT
      LAYER M4 ;
        RECT 0.000 371.136 0.192 371.160 ;
    END
  END li_d[112]
  PIN li_d[113]
    DIRECTION OUTPUT ;
    USE SIGNAL ;
    PORT
      LAYER M4 ;
        RECT 0.000 371.616 0.192 371.640 ;
    END
  END li_d[113]
  PIN li_d[114]
    DIRECTION OUTPUT ;
    USE SIGNAL ;
    PORT
      LAYER M4 ;
        RECT 0.000 372.048 0.192 372.072 ;
    END
  END li_d[114]
  PIN li_d[115]
    DIRECTION OUTPUT ;
    USE SIGNAL ;
    PORT
      LAYER M4 ;
        RECT 0.000 372.528 0.192 372.552 ;
    END
  END li_d[115]
  PIN li_d[116]
    DIRECTION OUTPUT ;
    USE SIGNAL ;
    PORT
      LAYER M4 ;
        RECT 0.000 373.008 0.192 373.032 ;
    END
  END li_d[116]
  PIN li_d[117]
    DIRECTION OUTPUT ;
    USE SIGNAL ;
    PORT
      LAYER M4 ;
        RECT 0.000 373.488 0.192 373.512 ;
    END
  END li_d[117]
  PIN li_d[118]
    DIRECTION OUTPUT ;
    USE SIGNAL ;
    PORT
      LAYER M4 ;
        RECT 0.000 373.968 0.192 373.992 ;
    END
  END li_d[118]
  PIN li_d[119]
    DIRECTION OUTPUT ;
    USE SIGNAL ;
    PORT
      LAYER M4 ;
        RECT 0.000 374.448 0.192 374.472 ;
    END
  END li_d[119]
  PIN li_d[120]
    DIRECTION OUTPUT ;
    USE SIGNAL ;
    PORT
      LAYER M4 ;
        RECT 0.000 374.928 0.192 374.952 ;
    END
  END li_d[120]
  PIN li_d[121]
    DIRECTION OUTPUT ;
    USE SIGNAL ;
    PORT
      LAYER M4 ;
        RECT 0.000 375.408 0.192 375.432 ;
    END
  END li_d[121]
  PIN li_d[122]
    DIRECTION OUTPUT ;
    USE SIGNAL ;
    PORT
      LAYER M4 ;
        RECT 0.000 375.888 0.192 375.912 ;
    END
  END li_d[122]
  PIN li_d[123]
    DIRECTION OUTPUT ;
    USE SIGNAL ;
    PORT
      LAYER M4 ;
        RECT 0.000 376.368 0.192 376.392 ;
    END
  END li_d[123]
  PIN li_d[124]
    DIRECTION OUTPUT ;
    USE SIGNAL ;
    PORT
      LAYER M4 ;
        RECT 0.000 376.848 0.192 376.872 ;
    END
  END li_d[124]
  PIN li_d[125]
    DIRECTION OUTPUT ;
    USE SIGNAL ;
    PORT
      LAYER M4 ;
        RECT 0.000 377.328 0.192 377.352 ;
    END
  END li_d[125]
  PIN li_d[126]
    DIRECTION OUTPUT ;
    USE SIGNAL ;
    PORT
      LAYER M4 ;
        RECT 0.000 377.808 0.192 377.832 ;
    END
  END li_d[126]
  PIN li_d[127]
    DIRECTION OUTPUT ;
    USE SIGNAL ;
    PORT
      LAYER M4 ;
        RECT 0.000 378.288 0.192 378.312 ;
    END
  END li_d[127]
  PIN li_d[128]
    DIRECTION OUTPUT ;
    USE SIGNAL ;
    PORT
      LAYER M4 ;
        RECT 0.000 378.720 0.192 378.744 ;
    END
  END li_d[128]
  PIN li_d[129]
    DIRECTION OUTPUT ;
    USE SIGNAL ;
    PORT
      LAYER M4 ;
        RECT 0.000 379.200 0.192 379.224 ;
    END
  END li_d[129]
  PIN li_d[130]
    DIRECTION OUTPUT ;
    USE SIGNAL ;
    PORT
      LAYER M4 ;
        RECT 0.000 379.680 0.192 379.704 ;
    END
  END li_d[130]
  PIN li_d[131]
    DIRECTION OUTPUT ;
    USE SIGNAL ;
    PORT
      LAYER M4 ;
        RECT 0.000 380.160 0.192 380.184 ;
    END
  END li_d[131]
  PIN li_d[132]
    DIRECTION OUTPUT ;
    USE SIGNAL ;
    PORT
      LAYER M4 ;
        RECT 0.000 380.640 0.192 380.664 ;
    END
  END li_d[132]
  PIN li_d[133]
    DIRECTION OUTPUT ;
    USE SIGNAL ;
    PORT
      LAYER M4 ;
        RECT 0.000 381.120 0.192 381.144 ;
    END
  END li_d[133]
  PIN li_d[134]
    DIRECTION OUTPUT ;
    USE SIGNAL ;
    PORT
      LAYER M4 ;
        RECT 0.000 381.600 0.192 381.624 ;
    END
  END li_d[134]
  PIN li_d[135]
    DIRECTION OUTPUT ;
    USE SIGNAL ;
    PORT
      LAYER M4 ;
        RECT 0.000 382.080 0.192 382.104 ;
    END
  END li_d[135]
  PIN li_d[136]
    DIRECTION OUTPUT ;
    USE SIGNAL ;
    PORT
      LAYER M4 ;
        RECT 0.000 382.560 0.192 382.584 ;
    END
  END li_d[136]
  PIN li_d[137]
    DIRECTION OUTPUT ;
    USE SIGNAL ;
    PORT
      LAYER M4 ;
        RECT 0.000 383.040 0.192 383.064 ;
    END
  END li_d[137]
  PIN li_d[138]
    DIRECTION OUTPUT ;
    USE SIGNAL ;
    PORT
      LAYER M4 ;
        RECT 0.000 383.520 0.192 383.544 ;
    END
  END li_d[138]
  PIN li_d[139]
    DIRECTION OUTPUT ;
    USE SIGNAL ;
    PORT
      LAYER M4 ;
        RECT 0.000 384.000 0.192 384.024 ;
    END
  END li_d[139]
  PIN li_d[140]
    DIRECTION OUTPUT ;
    USE SIGNAL ;
    PORT
      LAYER M4 ;
        RECT 0.000 384.480 0.192 384.504 ;
    END
  END li_d[140]
  PIN li_d[141]
    DIRECTION OUTPUT ;
    USE SIGNAL ;
    PORT
      LAYER M4 ;
        RECT 0.000 384.960 0.192 384.984 ;
    END
  END li_d[141]
  PIN li_d[142]
    DIRECTION OUTPUT ;
    USE SIGNAL ;
    PORT
      LAYER M4 ;
        RECT 0.000 385.392 0.192 385.416 ;
    END
  END li_d[142]
  PIN li_d[143]
    DIRECTION OUTPUT ;
    USE SIGNAL ;
    PORT
      LAYER M4 ;
        RECT 0.000 385.872 0.192 385.896 ;
    END
  END li_d[143]
  PIN li_d[144]
    DIRECTION OUTPUT ;
    USE SIGNAL ;
    PORT
      LAYER M4 ;
        RECT 0.000 386.352 0.192 386.376 ;
    END
  END li_d[144]
  PIN li_d[145]
    DIRECTION OUTPUT ;
    USE SIGNAL ;
    PORT
      LAYER M4 ;
        RECT 0.000 386.832 0.192 386.856 ;
    END
  END li_d[145]
  PIN li_d[146]
    DIRECTION OUTPUT ;
    USE SIGNAL ;
    PORT
      LAYER M4 ;
        RECT 0.000 387.312 0.192 387.336 ;
    END
  END li_d[146]
  PIN li_d[147]
    DIRECTION OUTPUT ;
    USE SIGNAL ;
    PORT
      LAYER M4 ;
        RECT 0.000 387.792 0.192 387.816 ;
    END
  END li_d[147]
  PIN li_d[148]
    DIRECTION OUTPUT ;
    USE SIGNAL ;
    PORT
      LAYER M4 ;
        RECT 0.000 388.272 0.192 388.296 ;
    END
  END li_d[148]
  PIN li_d[149]
    DIRECTION OUTPUT ;
    USE SIGNAL ;
    PORT
      LAYER M4 ;
        RECT 0.000 388.752 0.192 388.776 ;
    END
  END li_d[149]
  PIN li_d[150]
    DIRECTION OUTPUT ;
    USE SIGNAL ;
    PORT
      LAYER M4 ;
        RECT 0.000 389.232 0.192 389.256 ;
    END
  END li_d[150]
  PIN li_d[151]
    DIRECTION OUTPUT ;
    USE SIGNAL ;
    PORT
      LAYER M4 ;
        RECT 0.000 389.712 0.192 389.736 ;
    END
  END li_d[151]
  PIN li_d[152]
    DIRECTION OUTPUT ;
    USE SIGNAL ;
    PORT
      LAYER M4 ;
        RECT 0.000 390.192 0.192 390.216 ;
    END
  END li_d[152]
  PIN li_d[153]
    DIRECTION OUTPUT ;
    USE SIGNAL ;
    PORT
      LAYER M4 ;
        RECT 0.000 390.672 0.192 390.696 ;
    END
  END li_d[153]
  PIN li_d[154]
    DIRECTION OUTPUT ;
    USE SIGNAL ;
    PORT
      LAYER M4 ;
        RECT 0.000 391.152 0.192 391.176 ;
    END
  END li_d[154]
  PIN li_d[155]
    DIRECTION OUTPUT ;
    USE SIGNAL ;
    PORT
      LAYER M4 ;
        RECT 0.000 391.632 0.192 391.656 ;
    END
  END li_d[155]
  PIN li_d[156]
    DIRECTION OUTPUT ;
    USE SIGNAL ;
    PORT
      LAYER M4 ;
        RECT 0.000 392.064 0.192 392.088 ;
    END
  END li_d[156]
  PIN li_d[157]
    DIRECTION OUTPUT ;
    USE SIGNAL ;
    PORT
      LAYER M4 ;
        RECT 0.000 392.544 0.192 392.568 ;
    END
  END li_d[157]
  PIN li_d[158]
    DIRECTION OUTPUT ;
    USE SIGNAL ;
    PORT
      LAYER M4 ;
        RECT 0.000 393.024 0.192 393.048 ;
    END
  END li_d[158]
  PIN li_d[159]
    DIRECTION OUTPUT ;
    USE SIGNAL ;
    PORT
      LAYER M4 ;
        RECT 0.000 393.504 0.192 393.528 ;
    END
  END li_d[159]
  PIN li_d[160]
    DIRECTION OUTPUT ;
    USE SIGNAL ;
    PORT
      LAYER M4 ;
        RECT 0.000 393.984 0.192 394.008 ;
    END
  END li_d[160]
  PIN li_d[161]
    DIRECTION OUTPUT ;
    USE SIGNAL ;
    PORT
      LAYER M4 ;
        RECT 0.000 394.464 0.192 394.488 ;
    END
  END li_d[161]
  PIN li_d[162]
    DIRECTION OUTPUT ;
    USE SIGNAL ;
    PORT
      LAYER M4 ;
        RECT 0.000 394.944 0.192 394.968 ;
    END
  END li_d[162]
  PIN li_d[163]
    DIRECTION OUTPUT ;
    USE SIGNAL ;
    PORT
      LAYER M4 ;
        RECT 0.000 395.424 0.192 395.448 ;
    END
  END li_d[163]
  PIN li_d[164]
    DIRECTION OUTPUT ;
    USE SIGNAL ;
    PORT
      LAYER M4 ;
        RECT 0.000 395.904 0.192 395.928 ;
    END
  END li_d[164]
  PIN li_d[165]
    DIRECTION OUTPUT ;
    USE SIGNAL ;
    PORT
      LAYER M4 ;
        RECT 0.000 396.384 0.192 396.408 ;
    END
  END li_d[165]
  PIN li_d[166]
    DIRECTION OUTPUT ;
    USE SIGNAL ;
    PORT
      LAYER M4 ;
        RECT 0.000 396.864 0.192 396.888 ;
    END
  END li_d[166]
  PIN li_d[167]
    DIRECTION OUTPUT ;
    USE SIGNAL ;
    PORT
      LAYER M4 ;
        RECT 0.000 397.344 0.192 397.368 ;
    END
  END li_d[167]
  PIN li_d[168]
    DIRECTION OUTPUT ;
    USE SIGNAL ;
    PORT
      LAYER M4 ;
        RECT 0.000 397.824 0.192 397.848 ;
    END
  END li_d[168]
  PIN li_d[169]
    DIRECTION OUTPUT ;
    USE SIGNAL ;
    PORT
      LAYER M4 ;
        RECT 0.000 398.256 0.192 398.280 ;
    END
  END li_d[169]
  PIN li_d[170]
    DIRECTION OUTPUT ;
    USE SIGNAL ;
    PORT
      LAYER M4 ;
        RECT 0.000 398.736 0.192 398.760 ;
    END
  END li_d[170]
  PIN li_d[171]
    DIRECTION OUTPUT ;
    USE SIGNAL ;
    PORT
      LAYER M4 ;
        RECT 0.000 399.216 0.192 399.240 ;
    END
  END li_d[171]
  PIN li_d[172]
    DIRECTION OUTPUT ;
    USE SIGNAL ;
    PORT
      LAYER M4 ;
        RECT 0.000 399.696 0.192 399.720 ;
    END
  END li_d[172]
  PIN li_d[173]
    DIRECTION OUTPUT ;
    USE SIGNAL ;
    PORT
      LAYER M4 ;
        RECT 0.000 400.176 0.192 400.200 ;
    END
  END li_d[173]
  PIN li_d[174]
    DIRECTION OUTPUT ;
    USE SIGNAL ;
    PORT
      LAYER M4 ;
        RECT 0.000 400.656 0.192 400.680 ;
    END
  END li_d[174]
  PIN li_d[175]
    DIRECTION OUTPUT ;
    USE SIGNAL ;
    PORT
      LAYER M4 ;
        RECT 0.000 401.136 0.192 401.160 ;
    END
  END li_d[175]
  PIN li_d[176]
    DIRECTION OUTPUT ;
    USE SIGNAL ;
    PORT
      LAYER M4 ;
        RECT 0.000 401.616 0.192 401.640 ;
    END
  END li_d[176]
  PIN li_d[177]
    DIRECTION OUTPUT ;
    USE SIGNAL ;
    PORT
      LAYER M4 ;
        RECT 0.000 402.096 0.192 402.120 ;
    END
  END li_d[177]
  PIN li_d[178]
    DIRECTION OUTPUT ;
    USE SIGNAL ;
    PORT
      LAYER M4 ;
        RECT 0.000 402.576 0.192 402.600 ;
    END
  END li_d[178]
  PIN li_d[179]
    DIRECTION OUTPUT ;
    USE SIGNAL ;
    PORT
      LAYER M4 ;
        RECT 0.000 403.056 0.192 403.080 ;
    END
  END li_d[179]
  PIN li_d[180]
    DIRECTION OUTPUT ;
    USE SIGNAL ;
    PORT
      LAYER M4 ;
        RECT 0.000 403.536 0.192 403.560 ;
    END
  END li_d[180]
  PIN li_d[181]
    DIRECTION OUTPUT ;
    USE SIGNAL ;
    PORT
      LAYER M4 ;
        RECT 0.000 404.016 0.192 404.040 ;
    END
  END li_d[181]
  PIN li_d[182]
    DIRECTION OUTPUT ;
    USE SIGNAL ;
    PORT
      LAYER M4 ;
        RECT 0.000 404.496 0.192 404.520 ;
    END
  END li_d[182]
  PIN li_d[183]
    DIRECTION OUTPUT ;
    USE SIGNAL ;
    PORT
      LAYER M4 ;
        RECT 0.000 404.928 0.192 404.952 ;
    END
  END li_d[183]
  PIN li_d[184]
    DIRECTION OUTPUT ;
    USE SIGNAL ;
    PORT
      LAYER M4 ;
        RECT 0.000 405.408 0.192 405.432 ;
    END
  END li_d[184]
  PIN li_d[185]
    DIRECTION OUTPUT ;
    USE SIGNAL ;
    PORT
      LAYER M4 ;
        RECT 0.000 405.888 0.192 405.912 ;
    END
  END li_d[185]
  PIN li_d[186]
    DIRECTION OUTPUT ;
    USE SIGNAL ;
    PORT
      LAYER M4 ;
        RECT 0.000 406.368 0.192 406.392 ;
    END
  END li_d[186]
  PIN li_d[187]
    DIRECTION OUTPUT ;
    USE SIGNAL ;
    PORT
      LAYER M4 ;
        RECT 0.000 406.848 0.192 406.872 ;
    END
  END li_d[187]
  PIN li_d[188]
    DIRECTION OUTPUT ;
    USE SIGNAL ;
    PORT
      LAYER M4 ;
        RECT 0.000 407.328 0.192 407.352 ;
    END
  END li_d[188]
  PIN li_d[189]
    DIRECTION OUTPUT ;
    USE SIGNAL ;
    PORT
      LAYER M4 ;
        RECT 0.000 407.808 0.192 407.832 ;
    END
  END li_d[189]
  PIN li_d[190]
    DIRECTION OUTPUT ;
    USE SIGNAL ;
    PORT
      LAYER M4 ;
        RECT 0.000 408.288 0.192 408.312 ;
    END
  END li_d[190]
  PIN li_d[191]
    DIRECTION OUTPUT ;
    USE SIGNAL ;
    PORT
      LAYER M4 ;
        RECT 0.000 408.768 0.192 408.792 ;
    END
  END li_d[191]
  PIN li_d[192]
    DIRECTION OUTPUT ;
    USE SIGNAL ;
    PORT
      LAYER M4 ;
        RECT 0.000 409.248 0.192 409.272 ;
    END
  END li_d[192]
  PIN li_d[193]
    DIRECTION OUTPUT ;
    USE SIGNAL ;
    PORT
      LAYER M4 ;
        RECT 0.000 409.728 0.192 409.752 ;
    END
  END li_d[193]
  PIN li_d[194]
    DIRECTION OUTPUT ;
    USE SIGNAL ;
    PORT
      LAYER M4 ;
        RECT 0.000 410.208 0.192 410.232 ;
    END
  END li_d[194]
  PIN li_d[195]
    DIRECTION OUTPUT ;
    USE SIGNAL ;
    PORT
      LAYER M4 ;
        RECT 0.000 410.688 0.192 410.712 ;
    END
  END li_d[195]
  PIN li_d[196]
    DIRECTION OUTPUT ;
    USE SIGNAL ;
    PORT
      LAYER M4 ;
        RECT 0.000 411.168 0.192 411.192 ;
    END
  END li_d[196]
  PIN li_d[197]
    DIRECTION OUTPUT ;
    USE SIGNAL ;
    PORT
      LAYER M4 ;
        RECT 0.000 411.600 0.192 411.624 ;
    END
  END li_d[197]
  PIN li_d[198]
    DIRECTION OUTPUT ;
    USE SIGNAL ;
    PORT
      LAYER M4 ;
        RECT 0.000 412.080 0.192 412.104 ;
    END
  END li_d[198]
  PIN li_d[199]
    DIRECTION OUTPUT ;
    USE SIGNAL ;
    PORT
      LAYER M4 ;
        RECT 0.000 412.560 0.192 412.584 ;
    END
  END li_d[199]
  PIN li_d[200]
    DIRECTION OUTPUT ;
    USE SIGNAL ;
    PORT
      LAYER M4 ;
        RECT 0.000 413.040 0.192 413.064 ;
    END
  END li_d[200]
  PIN li_d[201]
    DIRECTION OUTPUT ;
    USE SIGNAL ;
    PORT
      LAYER M4 ;
        RECT 0.000 413.520 0.192 413.544 ;
    END
  END li_d[201]
  PIN li_d[202]
    DIRECTION OUTPUT ;
    USE SIGNAL ;
    PORT
      LAYER M4 ;
        RECT 0.000 414.000 0.192 414.024 ;
    END
  END li_d[202]
  PIN li_d[203]
    DIRECTION OUTPUT ;
    USE SIGNAL ;
    PORT
      LAYER M4 ;
        RECT 0.000 414.480 0.192 414.504 ;
    END
  END li_d[203]
  PIN li_d[204]
    DIRECTION OUTPUT ;
    USE SIGNAL ;
    PORT
      LAYER M4 ;
        RECT 0.000 414.960 0.192 414.984 ;
    END
  END li_d[204]
  PIN li_d[205]
    DIRECTION OUTPUT ;
    USE SIGNAL ;
    PORT
      LAYER M4 ;
        RECT 0.000 415.440 0.192 415.464 ;
    END
  END li_d[205]
  PIN li_d[206]
    DIRECTION OUTPUT ;
    USE SIGNAL ;
    PORT
      LAYER M4 ;
        RECT 0.000 415.920 0.192 415.944 ;
    END
  END li_d[206]
  PIN li_d[207]
    DIRECTION OUTPUT ;
    USE SIGNAL ;
    PORT
      LAYER M4 ;
        RECT 0.000 416.400 0.192 416.424 ;
    END
  END li_d[207]
  PIN li_d[208]
    DIRECTION OUTPUT ;
    USE SIGNAL ;
    PORT
      LAYER M4 ;
        RECT 0.000 416.880 0.192 416.904 ;
    END
  END li_d[208]
  PIN li_d[209]
    DIRECTION OUTPUT ;
    USE SIGNAL ;
    PORT
      LAYER M4 ;
        RECT 0.000 417.360 0.192 417.384 ;
    END
  END li_d[209]
  PIN li_d[210]
    DIRECTION OUTPUT ;
    USE SIGNAL ;
    PORT
      LAYER M4 ;
        RECT 0.000 417.840 0.192 417.864 ;
    END
  END li_d[210]
  PIN li_d[211]
    DIRECTION OUTPUT ;
    USE SIGNAL ;
    PORT
      LAYER M4 ;
        RECT 0.000 418.272 0.192 418.296 ;
    END
  END li_d[211]
  PIN li_d[212]
    DIRECTION OUTPUT ;
    USE SIGNAL ;
    PORT
      LAYER M4 ;
        RECT 0.000 418.752 0.192 418.776 ;
    END
  END li_d[212]
  PIN li_d[213]
    DIRECTION OUTPUT ;
    USE SIGNAL ;
    PORT
      LAYER M4 ;
        RECT 0.000 419.232 0.192 419.256 ;
    END
  END li_d[213]
  PIN li_d[214]
    DIRECTION OUTPUT ;
    USE SIGNAL ;
    PORT
      LAYER M4 ;
        RECT 0.000 419.712 0.192 419.736 ;
    END
  END li_d[214]
  PIN li_d[215]
    DIRECTION OUTPUT ;
    USE SIGNAL ;
    PORT
      LAYER M4 ;
        RECT 0.000 420.192 0.192 420.216 ;
    END
  END li_d[215]
  PIN li_d[216]
    DIRECTION OUTPUT ;
    USE SIGNAL ;
    PORT
      LAYER M4 ;
        RECT 0.000 420.672 0.192 420.696 ;
    END
  END li_d[216]
  PIN li_d[217]
    DIRECTION OUTPUT ;
    USE SIGNAL ;
    PORT
      LAYER M4 ;
        RECT 0.000 421.152 0.192 421.176 ;
    END
  END li_d[217]
  PIN li_d[218]
    DIRECTION OUTPUT ;
    USE SIGNAL ;
    PORT
      LAYER M4 ;
        RECT 0.000 421.632 0.192 421.656 ;
    END
  END li_d[218]
  PIN li_d[219]
    DIRECTION OUTPUT ;
    USE SIGNAL ;
    PORT
      LAYER M4 ;
        RECT 0.000 422.112 0.192 422.136 ;
    END
  END li_d[219]
  PIN li_d[220]
    DIRECTION OUTPUT ;
    USE SIGNAL ;
    PORT
      LAYER M4 ;
        RECT 0.000 422.592 0.192 422.616 ;
    END
  END li_d[220]
  PIN li_d[221]
    DIRECTION OUTPUT ;
    USE SIGNAL ;
    PORT
      LAYER M4 ;
        RECT 0.000 423.072 0.192 423.096 ;
    END
  END li_d[221]
  PIN li_d[222]
    DIRECTION OUTPUT ;
    USE SIGNAL ;
    PORT
      LAYER M4 ;
        RECT 0.000 423.552 0.192 423.576 ;
    END
  END li_d[222]
  PIN li_d[223]
    DIRECTION OUTPUT ;
    USE SIGNAL ;
    PORT
      LAYER M4 ;
        RECT 0.000 424.032 0.192 424.056 ;
    END
  END li_d[223]
  PIN li_d[224]
    DIRECTION OUTPUT ;
    USE SIGNAL ;
    PORT
      LAYER M4 ;
        RECT 0.000 424.512 0.192 424.536 ;
    END
  END li_d[224]
  PIN li_d[225]
    DIRECTION OUTPUT ;
    USE SIGNAL ;
    PORT
      LAYER M4 ;
        RECT 0.000 424.944 0.192 424.968 ;
    END
  END li_d[225]
  PIN li_d[226]
    DIRECTION OUTPUT ;
    USE SIGNAL ;
    PORT
      LAYER M4 ;
        RECT 0.000 425.424 0.192 425.448 ;
    END
  END li_d[226]
  PIN li_d[227]
    DIRECTION OUTPUT ;
    USE SIGNAL ;
    PORT
      LAYER M4 ;
        RECT 0.000 425.904 0.192 425.928 ;
    END
  END li_d[227]
  PIN li_d[228]
    DIRECTION OUTPUT ;
    USE SIGNAL ;
    PORT
      LAYER M4 ;
        RECT 0.000 426.384 0.192 426.408 ;
    END
  END li_d[228]
  PIN li_d[229]
    DIRECTION OUTPUT ;
    USE SIGNAL ;
    PORT
      LAYER M4 ;
        RECT 0.000 426.864 0.192 426.888 ;
    END
  END li_d[229]
  PIN li_d[230]
    DIRECTION OUTPUT ;
    USE SIGNAL ;
    PORT
      LAYER M4 ;
        RECT 0.000 427.344 0.192 427.368 ;
    END
  END li_d[230]
  PIN li_d[231]
    DIRECTION OUTPUT ;
    USE SIGNAL ;
    PORT
      LAYER M4 ;
        RECT 0.000 427.824 0.192 427.848 ;
    END
  END li_d[231]
  PIN li_d[232]
    DIRECTION OUTPUT ;
    USE SIGNAL ;
    PORT
      LAYER M4 ;
        RECT 0.000 428.304 0.192 428.328 ;
    END
  END li_d[232]
  PIN li_d[233]
    DIRECTION OUTPUT ;
    USE SIGNAL ;
    PORT
      LAYER M4 ;
        RECT 0.000 428.784 0.192 428.808 ;
    END
  END li_d[233]
  PIN li_d[234]
    DIRECTION OUTPUT ;
    USE SIGNAL ;
    PORT
      LAYER M4 ;
        RECT 0.000 429.264 0.192 429.288 ;
    END
  END li_d[234]
  PIN li_d[235]
    DIRECTION OUTPUT ;
    USE SIGNAL ;
    PORT
      LAYER M4 ;
        RECT 0.000 429.744 0.192 429.768 ;
    END
  END li_d[235]
  PIN li_d[236]
    DIRECTION OUTPUT ;
    USE SIGNAL ;
    PORT
      LAYER M4 ;
        RECT 0.000 430.224 0.192 430.248 ;
    END
  END li_d[236]
  PIN li_d[237]
    DIRECTION OUTPUT ;
    USE SIGNAL ;
    PORT
      LAYER M4 ;
        RECT 0.000 430.704 0.192 430.728 ;
    END
  END li_d[237]
  PIN li_d[238]
    DIRECTION OUTPUT ;
    USE SIGNAL ;
    PORT
      LAYER M4 ;
        RECT 0.000 431.136 0.192 431.160 ;
    END
  END li_d[238]
  PIN li_d[239]
    DIRECTION OUTPUT ;
    USE SIGNAL ;
    PORT
      LAYER M4 ;
        RECT 0.000 431.616 0.192 431.640 ;
    END
  END li_d[239]
  PIN li_d[240]
    DIRECTION OUTPUT ;
    USE SIGNAL ;
    PORT
      LAYER M4 ;
        RECT 0.000 432.096 0.192 432.120 ;
    END
  END li_d[240]
  PIN li_d[241]
    DIRECTION OUTPUT ;
    USE SIGNAL ;
    PORT
      LAYER M4 ;
        RECT 0.000 432.576 0.192 432.600 ;
    END
  END li_d[241]
  PIN li_d[242]
    DIRECTION OUTPUT ;
    USE SIGNAL ;
    PORT
      LAYER M4 ;
        RECT 0.000 433.056 0.192 433.080 ;
    END
  END li_d[242]
  PIN li_d[243]
    DIRECTION OUTPUT ;
    USE SIGNAL ;
    PORT
      LAYER M4 ;
        RECT 0.000 433.536 0.192 433.560 ;
    END
  END li_d[243]
  PIN li_d[244]
    DIRECTION OUTPUT ;
    USE SIGNAL ;
    PORT
      LAYER M4 ;
        RECT 0.000 434.016 0.192 434.040 ;
    END
  END li_d[244]
  PIN li_d[245]
    DIRECTION OUTPUT ;
    USE SIGNAL ;
    PORT
      LAYER M4 ;
        RECT 0.000 434.496 0.192 434.520 ;
    END
  END li_d[245]
  PIN li_d[246]
    DIRECTION OUTPUT ;
    USE SIGNAL ;
    PORT
      LAYER M4 ;
        RECT 0.000 434.976 0.192 435.000 ;
    END
  END li_d[246]
  PIN li_d[247]
    DIRECTION OUTPUT ;
    USE SIGNAL ;
    PORT
      LAYER M4 ;
        RECT 0.000 435.456 0.192 435.480 ;
    END
  END li_d[247]
  PIN li_d[248]
    DIRECTION OUTPUT ;
    USE SIGNAL ;
    PORT
      LAYER M4 ;
        RECT 0.000 435.936 0.192 435.960 ;
    END
  END li_d[248]
  PIN li_d[249]
    DIRECTION OUTPUT ;
    USE SIGNAL ;
    PORT
      LAYER M4 ;
        RECT 0.000 436.416 0.192 436.440 ;
    END
  END li_d[249]
  PIN li_d[250]
    DIRECTION OUTPUT ;
    USE SIGNAL ;
    PORT
      LAYER M4 ;
        RECT 0.000 436.896 0.192 436.920 ;
    END
  END li_d[250]
  PIN li_d[251]
    DIRECTION OUTPUT ;
    USE SIGNAL ;
    PORT
      LAYER M4 ;
        RECT 0.000 437.376 0.192 437.400 ;
    END
  END li_d[251]
  PIN li_d[252]
    DIRECTION OUTPUT ;
    USE SIGNAL ;
    PORT
      LAYER M4 ;
        RECT 0.000 437.808 0.192 437.832 ;
    END
  END li_d[252]
  PIN li_d[253]
    DIRECTION OUTPUT ;
    USE SIGNAL ;
    PORT
      LAYER M4 ;
        RECT 0.000 438.288 0.192 438.312 ;
    END
  END li_d[253]
  PIN li_d[254]
    DIRECTION OUTPUT ;
    USE SIGNAL ;
    PORT
      LAYER M4 ;
        RECT 0.000 438.768 0.192 438.792 ;
    END
  END li_d[254]
  PIN li_d[255]
    DIRECTION OUTPUT ;
    USE SIGNAL ;
    PORT
      LAYER M4 ;
        RECT 0.000 439.248 0.192 439.272 ;
    END
  END li_d[255]
  PIN li_d[256]
    DIRECTION OUTPUT ;
    USE SIGNAL ;
    PORT
      LAYER M4 ;
        RECT 0.000 439.728 0.192 439.752 ;
    END
  END li_d[256]
  PIN li_d[257]
    DIRECTION OUTPUT ;
    USE SIGNAL ;
    PORT
      LAYER M4 ;
        RECT 0.000 440.208 0.192 440.232 ;
    END
  END li_d[257]
  PIN li_d[258]
    DIRECTION OUTPUT ;
    USE SIGNAL ;
    PORT
      LAYER M4 ;
        RECT 0.000 440.688 0.192 440.712 ;
    END
  END li_d[258]
  PIN li_d[259]
    DIRECTION OUTPUT ;
    USE SIGNAL ;
    PORT
      LAYER M4 ;
        RECT 0.000 441.168 0.192 441.192 ;
    END
  END li_d[259]
  PIN li_d[260]
    DIRECTION OUTPUT ;
    USE SIGNAL ;
    PORT
      LAYER M4 ;
        RECT 0.000 441.648 0.192 441.672 ;
    END
  END li_d[260]
  PIN li_d[261]
    DIRECTION OUTPUT ;
    USE SIGNAL ;
    PORT
      LAYER M4 ;
        RECT 0.000 442.128 0.192 442.152 ;
    END
  END li_d[261]
  PIN li_d[262]
    DIRECTION OUTPUT ;
    USE SIGNAL ;
    PORT
      LAYER M4 ;
        RECT 0.000 442.608 0.192 442.632 ;
    END
  END li_d[262]
  PIN li_d[263]
    DIRECTION OUTPUT ;
    USE SIGNAL ;
    PORT
      LAYER M4 ;
        RECT 0.000 443.088 0.192 443.112 ;
    END
  END li_d[263]
  PIN li_d[264]
    DIRECTION OUTPUT ;
    USE SIGNAL ;
    PORT
      LAYER M4 ;
        RECT 0.000 443.568 0.192 443.592 ;
    END
  END li_d[264]
  PIN li_d[265]
    DIRECTION OUTPUT ;
    USE SIGNAL ;
    PORT
      LAYER M4 ;
        RECT 0.000 444.048 0.192 444.072 ;
    END
  END li_d[265]
  PIN li_d[266]
    DIRECTION OUTPUT ;
    USE SIGNAL ;
    PORT
      LAYER M4 ;
        RECT 0.000 444.480 0.192 444.504 ;
    END
  END li_d[266]
  PIN li_d[267]
    DIRECTION OUTPUT ;
    USE SIGNAL ;
    PORT
      LAYER M4 ;
        RECT 0.000 444.960 0.192 444.984 ;
    END
  END li_d[267]
  PIN li_d[268]
    DIRECTION OUTPUT ;
    USE SIGNAL ;
    PORT
      LAYER M4 ;
        RECT 0.000 445.440 0.192 445.464 ;
    END
  END li_d[268]
  PIN li_d[269]
    DIRECTION OUTPUT ;
    USE SIGNAL ;
    PORT
      LAYER M4 ;
        RECT 0.000 445.920 0.192 445.944 ;
    END
  END li_d[269]
  PIN li_d[270]
    DIRECTION OUTPUT ;
    USE SIGNAL ;
    PORT
      LAYER M4 ;
        RECT 0.000 446.400 0.192 446.424 ;
    END
  END li_d[270]
  PIN li_d[271]
    DIRECTION OUTPUT ;
    USE SIGNAL ;
    PORT
      LAYER M4 ;
        RECT 0.000 446.880 0.192 446.904 ;
    END
  END li_d[271]
  PIN li_d[272]
    DIRECTION OUTPUT ;
    USE SIGNAL ;
    PORT
      LAYER M4 ;
        RECT 0.000 447.360 0.192 447.384 ;
    END
  END li_d[272]
  PIN li_d[273]
    DIRECTION OUTPUT ;
    USE SIGNAL ;
    PORT
      LAYER M4 ;
        RECT 0.000 447.840 0.192 447.864 ;
    END
  END li_d[273]
  PIN li_d[274]
    DIRECTION OUTPUT ;
    USE SIGNAL ;
    PORT
      LAYER M4 ;
        RECT 0.000 448.320 0.192 448.344 ;
    END
  END li_d[274]
  PIN li_d[275]
    DIRECTION OUTPUT ;
    USE SIGNAL ;
    PORT
      LAYER M4 ;
        RECT 0.000 448.800 0.192 448.824 ;
    END
  END li_d[275]
  PIN li_d[276]
    DIRECTION OUTPUT ;
    USE SIGNAL ;
    PORT
      LAYER M4 ;
        RECT 0.000 449.280 0.192 449.304 ;
    END
  END li_d[276]
  PIN li_d[277]
    DIRECTION OUTPUT ;
    USE SIGNAL ;
    PORT
      LAYER M4 ;
        RECT 0.000 449.760 0.192 449.784 ;
    END
  END li_d[277]
  PIN li_d[278]
    DIRECTION OUTPUT ;
    USE SIGNAL ;
    PORT
      LAYER M4 ;
        RECT 0.000 450.240 0.192 450.264 ;
    END
  END li_d[278]
  PIN li_d[279]
    DIRECTION OUTPUT ;
    USE SIGNAL ;
    PORT
      LAYER M4 ;
        RECT 0.000 450.720 0.192 450.744 ;
    END
  END li_d[279]
  PIN li_d[280]
    DIRECTION OUTPUT ;
    USE SIGNAL ;
    PORT
      LAYER M4 ;
        RECT 0.000 451.152 0.192 451.176 ;
    END
  END li_d[280]
  PIN li_d[281]
    DIRECTION OUTPUT ;
    USE SIGNAL ;
    PORT
      LAYER M4 ;
        RECT 0.000 451.632 0.192 451.656 ;
    END
  END li_d[281]
  PIN li_d[282]
    DIRECTION OUTPUT ;
    USE SIGNAL ;
    PORT
      LAYER M4 ;
        RECT 0.000 452.112 0.192 452.136 ;
    END
  END li_d[282]
  PIN li_d[283]
    DIRECTION OUTPUT ;
    USE SIGNAL ;
    PORT
      LAYER M4 ;
        RECT 0.000 452.592 0.192 452.616 ;
    END
  END li_d[283]
  PIN li_d[284]
    DIRECTION OUTPUT ;
    USE SIGNAL ;
    PORT
      LAYER M4 ;
        RECT 0.000 453.072 0.192 453.096 ;
    END
  END li_d[284]
  PIN li_d[285]
    DIRECTION OUTPUT ;
    USE SIGNAL ;
    PORT
      LAYER M4 ;
        RECT 0.000 453.552 0.192 453.576 ;
    END
  END li_d[285]
  PIN li_d[286]
    DIRECTION OUTPUT ;
    USE SIGNAL ;
    PORT
      LAYER M4 ;
        RECT 0.000 454.032 0.192 454.056 ;
    END
  END li_d[286]
  PIN li_d[287]
    DIRECTION OUTPUT ;
    USE SIGNAL ;
    PORT
      LAYER M4 ;
        RECT 0.000 454.512 0.192 454.536 ;
    END
  END li_d[287]
  PIN li_d[288]
    DIRECTION OUTPUT ;
    USE SIGNAL ;
    PORT
      LAYER M4 ;
        RECT 0.000 454.992 0.192 455.016 ;
    END
  END li_d[288]
  PIN li_d[289]
    DIRECTION OUTPUT ;
    USE SIGNAL ;
    PORT
      LAYER M4 ;
        RECT 0.000 455.472 0.192 455.496 ;
    END
  END li_d[289]
  PIN li_d[290]
    DIRECTION OUTPUT ;
    USE SIGNAL ;
    PORT
      LAYER M4 ;
        RECT 0.000 455.952 0.192 455.976 ;
    END
  END li_d[290]
  PIN li_d[291]
    DIRECTION OUTPUT ;
    USE SIGNAL ;
    PORT
      LAYER M4 ;
        RECT 0.000 456.432 0.192 456.456 ;
    END
  END li_d[291]
  PIN li_d[292]
    DIRECTION OUTPUT ;
    USE SIGNAL ;
    PORT
      LAYER M4 ;
        RECT 0.000 456.912 0.192 456.936 ;
    END
  END li_d[292]
  PIN li_d[293]
    DIRECTION OUTPUT ;
    USE SIGNAL ;
    PORT
      LAYER M4 ;
        RECT 0.000 457.392 0.192 457.416 ;
    END
  END li_d[293]
  PIN li_d[294]
    DIRECTION OUTPUT ;
    USE SIGNAL ;
    PORT
      LAYER M4 ;
        RECT 0.000 457.824 0.192 457.848 ;
    END
  END li_d[294]
  PIN li_d[295]
    DIRECTION OUTPUT ;
    USE SIGNAL ;
    PORT
      LAYER M4 ;
        RECT 0.000 458.304 0.192 458.328 ;
    END
  END li_d[295]
  PIN li_d[296]
    DIRECTION OUTPUT ;
    USE SIGNAL ;
    PORT
      LAYER M4 ;
        RECT 0.000 458.784 0.192 458.808 ;
    END
  END li_d[296]
  PIN li_d[297]
    DIRECTION OUTPUT ;
    USE SIGNAL ;
    PORT
      LAYER M4 ;
        RECT 0.000 459.264 0.192 459.288 ;
    END
  END li_d[297]
  PIN li_d[298]
    DIRECTION OUTPUT ;
    USE SIGNAL ;
    PORT
      LAYER M4 ;
        RECT 0.000 459.744 0.192 459.768 ;
    END
  END li_d[298]
  PIN li_d[299]
    DIRECTION OUTPUT ;
    USE SIGNAL ;
    PORT
      LAYER M4 ;
        RECT 0.000 460.224 0.192 460.248 ;
    END
  END li_d[299]
  PIN li_d[300]
    DIRECTION OUTPUT ;
    USE SIGNAL ;
    PORT
      LAYER M4 ;
        RECT 0.000 460.704 0.192 460.728 ;
    END
  END li_d[300]
  PIN li_d[301]
    DIRECTION OUTPUT ;
    USE SIGNAL ;
    PORT
      LAYER M4 ;
        RECT 0.000 461.184 0.192 461.208 ;
    END
  END li_d[301]
  PIN li_d[302]
    DIRECTION OUTPUT ;
    USE SIGNAL ;
    PORT
      LAYER M4 ;
        RECT 0.000 461.664 0.192 461.688 ;
    END
  END li_d[302]
  PIN li_d[303]
    DIRECTION OUTPUT ;
    USE SIGNAL ;
    PORT
      LAYER M4 ;
        RECT 0.000 462.144 0.192 462.168 ;
    END
  END li_d[303]
  PIN li_d[304]
    DIRECTION OUTPUT ;
    USE SIGNAL ;
    PORT
      LAYER M4 ;
        RECT 0.000 462.624 0.192 462.648 ;
    END
  END li_d[304]
  PIN li_d[305]
    DIRECTION OUTPUT ;
    USE SIGNAL ;
    PORT
      LAYER M4 ;
        RECT 0.000 463.104 0.192 463.128 ;
    END
  END li_d[305]
  PIN li_d[306]
    DIRECTION OUTPUT ;
    USE SIGNAL ;
    PORT
      LAYER M4 ;
        RECT 0.000 463.584 0.192 463.608 ;
    END
  END li_d[306]
  PIN li_d[307]
    DIRECTION OUTPUT ;
    USE SIGNAL ;
    PORT
      LAYER M4 ;
        RECT 0.000 464.064 0.192 464.088 ;
    END
  END li_d[307]
  PIN li_d[308]
    DIRECTION OUTPUT ;
    USE SIGNAL ;
    PORT
      LAYER M4 ;
        RECT 0.000 464.496 0.192 464.520 ;
    END
  END li_d[308]
  PIN li_d[309]
    DIRECTION OUTPUT ;
    USE SIGNAL ;
    PORT
      LAYER M4 ;
        RECT 0.000 464.976 0.192 465.000 ;
    END
  END li_d[309]
  PIN li_d[310]
    DIRECTION OUTPUT ;
    USE SIGNAL ;
    PORT
      LAYER M4 ;
        RECT 0.000 465.456 0.192 465.480 ;
    END
  END li_d[310]
  PIN li_d[311]
    DIRECTION OUTPUT ;
    USE SIGNAL ;
    PORT
      LAYER M4 ;
        RECT 0.000 465.936 0.192 465.960 ;
    END
  END li_d[311]
  PIN li_d[312]
    DIRECTION OUTPUT ;
    USE SIGNAL ;
    PORT
      LAYER M4 ;
        RECT 0.000 466.416 0.192 466.440 ;
    END
  END li_d[312]
  PIN li_d[313]
    DIRECTION OUTPUT ;
    USE SIGNAL ;
    PORT
      LAYER M4 ;
        RECT 0.000 466.896 0.192 466.920 ;
    END
  END li_d[313]
  PIN li_d[314]
    DIRECTION OUTPUT ;
    USE SIGNAL ;
    PORT
      LAYER M4 ;
        RECT 0.000 467.376 0.192 467.400 ;
    END
  END li_d[314]
  PIN li_d[315]
    DIRECTION OUTPUT ;
    USE SIGNAL ;
    PORT
      LAYER M4 ;
        RECT 0.000 467.856 0.192 467.880 ;
    END
  END li_d[315]
  PIN li_d[316]
    DIRECTION OUTPUT ;
    USE SIGNAL ;
    PORT
      LAYER M4 ;
        RECT 0.000 468.336 0.192 468.360 ;
    END
  END li_d[316]
  PIN li_d[317]
    DIRECTION OUTPUT ;
    USE SIGNAL ;
    PORT
      LAYER M4 ;
        RECT 0.000 468.816 0.192 468.840 ;
    END
  END li_d[317]
  PIN li_d[318]
    DIRECTION OUTPUT ;
    USE SIGNAL ;
    PORT
      LAYER M4 ;
        RECT 0.000 469.296 0.192 469.320 ;
    END
  END li_d[318]
  PIN li_d[319]
    DIRECTION OUTPUT ;
    USE SIGNAL ;
    PORT
      LAYER M4 ;
        RECT 0.000 469.776 0.192 469.800 ;
    END
  END li_d[319]
  PIN li_d[320]
    DIRECTION OUTPUT ;
    USE SIGNAL ;
    PORT
      LAYER M4 ;
        RECT 0.000 470.256 0.192 470.280 ;
    END
  END li_d[320]
  PIN li_d[321]
    DIRECTION OUTPUT ;
    USE SIGNAL ;
    PORT
      LAYER M4 ;
        RECT 0.000 470.688 0.192 470.712 ;
    END
  END li_d[321]
  PIN li_d[322]
    DIRECTION OUTPUT ;
    USE SIGNAL ;
    PORT
      LAYER M4 ;
        RECT 0.000 471.168 0.192 471.192 ;
    END
  END li_d[322]
  PIN li_d[323]
    DIRECTION OUTPUT ;
    USE SIGNAL ;
    PORT
      LAYER M4 ;
        RECT 0.000 471.648 0.192 471.672 ;
    END
  END li_d[323]
  PIN li_d[324]
    DIRECTION OUTPUT ;
    USE SIGNAL ;
    PORT
      LAYER M4 ;
        RECT 0.000 472.128 0.192 472.152 ;
    END
  END li_d[324]
  PIN li_d[325]
    DIRECTION OUTPUT ;
    USE SIGNAL ;
    PORT
      LAYER M4 ;
        RECT 0.000 472.608 0.192 472.632 ;
    END
  END li_d[325]
  PIN li_d[326]
    DIRECTION OUTPUT ;
    USE SIGNAL ;
    PORT
      LAYER M4 ;
        RECT 0.000 473.088 0.192 473.112 ;
    END
  END li_d[326]
  PIN li_d[327]
    DIRECTION OUTPUT ;
    USE SIGNAL ;
    PORT
      LAYER M4 ;
        RECT 0.000 473.568 0.192 473.592 ;
    END
  END li_d[327]
  PIN li_d[328]
    DIRECTION OUTPUT ;
    USE SIGNAL ;
    PORT
      LAYER M4 ;
        RECT 0.000 474.048 0.192 474.072 ;
    END
  END li_d[328]
  PIN li_d[329]
    DIRECTION OUTPUT ;
    USE SIGNAL ;
    PORT
      LAYER M4 ;
        RECT 0.000 474.528 0.192 474.552 ;
    END
  END li_d[329]
  PIN li_d[330]
    DIRECTION OUTPUT ;
    USE SIGNAL ;
    PORT
      LAYER M4 ;
        RECT 0.000 475.008 0.192 475.032 ;
    END
  END li_d[330]
  PIN li_d[331]
    DIRECTION OUTPUT ;
    USE SIGNAL ;
    PORT
      LAYER M4 ;
        RECT 0.000 475.488 0.192 475.512 ;
    END
  END li_d[331]
  PIN li_d[332]
    DIRECTION OUTPUT ;
    USE SIGNAL ;
    PORT
      LAYER M4 ;
        RECT 0.000 475.968 0.192 475.992 ;
    END
  END li_d[332]
  PIN li_d[333]
    DIRECTION OUTPUT ;
    USE SIGNAL ;
    PORT
      LAYER M4 ;
        RECT 0.000 476.448 0.192 476.472 ;
    END
  END li_d[333]
  PIN li_d[334]
    DIRECTION OUTPUT ;
    USE SIGNAL ;
    PORT
      LAYER M4 ;
        RECT 0.000 476.928 0.192 476.952 ;
    END
  END li_d[334]
  PIN li_d[335]
    DIRECTION OUTPUT ;
    USE SIGNAL ;
    PORT
      LAYER M4 ;
        RECT 0.000 477.360 0.192 477.384 ;
    END
  END li_d[335]
  PIN li_d[336]
    DIRECTION OUTPUT ;
    USE SIGNAL ;
    PORT
      LAYER M4 ;
        RECT 0.000 477.840 0.192 477.864 ;
    END
  END li_d[336]
  PIN li_d[337]
    DIRECTION OUTPUT ;
    USE SIGNAL ;
    PORT
      LAYER M4 ;
        RECT 0.000 478.320 0.192 478.344 ;
    END
  END li_d[337]
  PIN li_d[338]
    DIRECTION OUTPUT ;
    USE SIGNAL ;
    PORT
      LAYER M4 ;
        RECT 0.000 478.800 0.192 478.824 ;
    END
  END li_d[338]
  PIN li_d[339]
    DIRECTION OUTPUT ;
    USE SIGNAL ;
    PORT
      LAYER M4 ;
        RECT 0.000 479.280 0.192 479.304 ;
    END
  END li_d[339]
  PIN li_d[340]
    DIRECTION OUTPUT ;
    USE SIGNAL ;
    PORT
      LAYER M4 ;
        RECT 0.000 479.760 0.192 479.784 ;
    END
  END li_d[340]
  PIN li_d[341]
    DIRECTION OUTPUT ;
    USE SIGNAL ;
    PORT
      LAYER M4 ;
        RECT 0.000 480.240 0.192 480.264 ;
    END
  END li_d[341]
  PIN li_d[342]
    DIRECTION OUTPUT ;
    USE SIGNAL ;
    PORT
      LAYER M4 ;
        RECT 0.000 480.720 0.192 480.744 ;
    END
  END li_d[342]
  PIN li_d[343]
    DIRECTION OUTPUT ;
    USE SIGNAL ;
    PORT
      LAYER M4 ;
        RECT 0.000 481.200 0.192 481.224 ;
    END
  END li_d[343]
  PIN li_d[344]
    DIRECTION OUTPUT ;
    USE SIGNAL ;
    PORT
      LAYER M4 ;
        RECT 0.000 481.680 0.192 481.704 ;
    END
  END li_d[344]
  PIN li_d[345]
    DIRECTION OUTPUT ;
    USE SIGNAL ;
    PORT
      LAYER M4 ;
        RECT 0.000 482.160 0.192 482.184 ;
    END
  END li_d[345]
  PIN li_d[346]
    DIRECTION OUTPUT ;
    USE SIGNAL ;
    PORT
      LAYER M4 ;
        RECT 0.000 482.640 0.192 482.664 ;
    END
  END li_d[346]
  PIN li_d[347]
    DIRECTION OUTPUT ;
    USE SIGNAL ;
    PORT
      LAYER M4 ;
        RECT 0.000 483.120 0.192 483.144 ;
    END
  END li_d[347]
  PIN li_d[348]
    DIRECTION OUTPUT ;
    USE SIGNAL ;
    PORT
      LAYER M4 ;
        RECT 0.000 483.600 0.192 483.624 ;
    END
  END li_d[348]
  PIN li_d[349]
    DIRECTION OUTPUT ;
    USE SIGNAL ;
    PORT
      LAYER M4 ;
        RECT 0.000 484.032 0.192 484.056 ;
    END
  END li_d[349]
  PIN li_d[350]
    DIRECTION OUTPUT ;
    USE SIGNAL ;
    PORT
      LAYER M4 ;
        RECT 0.000 484.512 0.192 484.536 ;
    END
  END li_d[350]
  PIN li_d[351]
    DIRECTION OUTPUT ;
    USE SIGNAL ;
    PORT
      LAYER M4 ;
        RECT 0.000 484.992 0.192 485.016 ;
    END
  END li_d[351]
  PIN li_d[352]
    DIRECTION OUTPUT ;
    USE SIGNAL ;
    PORT
      LAYER M4 ;
        RECT 0.000 485.472 0.192 485.496 ;
    END
  END li_d[352]
  PIN li_d[353]
    DIRECTION OUTPUT ;
    USE SIGNAL ;
    PORT
      LAYER M4 ;
        RECT 0.000 485.952 0.192 485.976 ;
    END
  END li_d[353]
  PIN li_d[354]
    DIRECTION OUTPUT ;
    USE SIGNAL ;
    PORT
      LAYER M4 ;
        RECT 0.000 486.432 0.192 486.456 ;
    END
  END li_d[354]
  PIN li_d[355]
    DIRECTION OUTPUT ;
    USE SIGNAL ;
    PORT
      LAYER M4 ;
        RECT 0.000 486.912 0.192 486.936 ;
    END
  END li_d[355]
  PIN li_d[356]
    DIRECTION OUTPUT ;
    USE SIGNAL ;
    PORT
      LAYER M4 ;
        RECT 0.000 487.392 0.192 487.416 ;
    END
  END li_d[356]
  PIN li_d[357]
    DIRECTION OUTPUT ;
    USE SIGNAL ;
    PORT
      LAYER M4 ;
        RECT 0.000 487.872 0.192 487.896 ;
    END
  END li_d[357]
  PIN li_d[358]
    DIRECTION OUTPUT ;
    USE SIGNAL ;
    PORT
      LAYER M4 ;
        RECT 0.000 488.352 0.192 488.376 ;
    END
  END li_d[358]
  PIN li_d[359]
    DIRECTION OUTPUT ;
    USE SIGNAL ;
    PORT
      LAYER M4 ;
        RECT 0.000 488.832 0.192 488.856 ;
    END
  END li_d[359]
  PIN li_d[360]
    DIRECTION OUTPUT ;
    USE SIGNAL ;
    PORT
      LAYER M4 ;
        RECT 0.000 489.312 0.192 489.336 ;
    END
  END li_d[360]
  PIN li_d[361]
    DIRECTION OUTPUT ;
    USE SIGNAL ;
    PORT
      LAYER M4 ;
        RECT 0.000 489.792 0.192 489.816 ;
    END
  END li_d[361]
  PIN li_d[362]
    DIRECTION OUTPUT ;
    USE SIGNAL ;
    PORT
      LAYER M4 ;
        RECT 0.000 490.272 0.192 490.296 ;
    END
  END li_d[362]
  PIN li_d[363]
    DIRECTION OUTPUT ;
    USE SIGNAL ;
    PORT
      LAYER M4 ;
        RECT 0.000 490.704 0.192 490.728 ;
    END
  END li_d[363]
  PIN li_d[364]
    DIRECTION OUTPUT ;
    USE SIGNAL ;
    PORT
      LAYER M4 ;
        RECT 0.000 491.184 0.192 491.208 ;
    END
  END li_d[364]
  PIN li_d[365]
    DIRECTION OUTPUT ;
    USE SIGNAL ;
    PORT
      LAYER M4 ;
        RECT 0.000 491.664 0.192 491.688 ;
    END
  END li_d[365]
  PIN li_d[366]
    DIRECTION OUTPUT ;
    USE SIGNAL ;
    PORT
      LAYER M4 ;
        RECT 0.000 492.144 0.192 492.168 ;
    END
  END li_d[366]
  PIN li_d[367]
    DIRECTION OUTPUT ;
    USE SIGNAL ;
    PORT
      LAYER M4 ;
        RECT 0.000 492.624 0.192 492.648 ;
    END
  END li_d[367]
  PIN li_d[368]
    DIRECTION OUTPUT ;
    USE SIGNAL ;
    PORT
      LAYER M4 ;
        RECT 0.000 493.104 0.192 493.128 ;
    END
  END li_d[368]
  PIN li_d[369]
    DIRECTION OUTPUT ;
    USE SIGNAL ;
    PORT
      LAYER M4 ;
        RECT 0.000 493.584 0.192 493.608 ;
    END
  END li_d[369]
  PIN li_d[370]
    DIRECTION OUTPUT ;
    USE SIGNAL ;
    PORT
      LAYER M4 ;
        RECT 0.000 494.064 0.192 494.088 ;
    END
  END li_d[370]
  PIN li_d[371]
    DIRECTION OUTPUT ;
    USE SIGNAL ;
    PORT
      LAYER M4 ;
        RECT 0.000 494.544 0.192 494.568 ;
    END
  END li_d[371]
  PIN li_d[372]
    DIRECTION OUTPUT ;
    USE SIGNAL ;
    PORT
      LAYER M4 ;
        RECT 0.000 495.024 0.192 495.048 ;
    END
  END li_d[372]
  PIN li_d[373]
    DIRECTION OUTPUT ;
    USE SIGNAL ;
    PORT
      LAYER M4 ;
        RECT 0.000 495.504 0.192 495.528 ;
    END
  END li_d[373]
  PIN li_d[374]
    DIRECTION OUTPUT ;
    USE SIGNAL ;
    PORT
      LAYER M4 ;
        RECT 0.000 495.984 0.192 496.008 ;
    END
  END li_d[374]
  PIN li_d[375]
    DIRECTION OUTPUT ;
    USE SIGNAL ;
    PORT
      LAYER M4 ;
        RECT 0.000 496.464 0.192 496.488 ;
    END
  END li_d[375]
  PIN li_d[376]
    DIRECTION OUTPUT ;
    USE SIGNAL ;
    PORT
      LAYER M4 ;
        RECT 0.000 496.944 0.192 496.968 ;
    END
  END li_d[376]
  PIN li_d[377]
    DIRECTION OUTPUT ;
    USE SIGNAL ;
    PORT
      LAYER M4 ;
        RECT 0.000 497.376 0.192 497.400 ;
    END
  END li_d[377]
  PIN li_d[378]
    DIRECTION OUTPUT ;
    USE SIGNAL ;
    PORT
      LAYER M4 ;
        RECT 0.000 497.856 0.192 497.880 ;
    END
  END li_d[378]
  PIN li_d[379]
    DIRECTION OUTPUT ;
    USE SIGNAL ;
    PORT
      LAYER M4 ;
        RECT 0.000 498.336 0.192 498.360 ;
    END
  END li_d[379]
  PIN li_d[380]
    DIRECTION OUTPUT ;
    USE SIGNAL ;
    PORT
      LAYER M4 ;
        RECT 0.000 498.816 0.192 498.840 ;
    END
  END li_d[380]
  PIN li_d[381]
    DIRECTION OUTPUT ;
    USE SIGNAL ;
    PORT
      LAYER M4 ;
        RECT 0.000 499.296 0.192 499.320 ;
    END
  END li_d[381]
  PIN li_d[382]
    DIRECTION OUTPUT ;
    USE SIGNAL ;
    PORT
      LAYER M4 ;
        RECT 0.000 499.776 0.192 499.800 ;
    END
  END li_d[382]
  PIN li_d[383]
    DIRECTION OUTPUT ;
    USE SIGNAL ;
    PORT
      LAYER M4 ;
        RECT 0.000 500.256 0.192 500.280 ;
    END
  END li_d[383]
  PIN li_d[384]
    DIRECTION OUTPUT ;
    USE SIGNAL ;
    PORT
      LAYER M4 ;
        RECT 0.000 500.736 0.192 500.760 ;
    END
  END li_d[384]
  PIN li_d[385]
    DIRECTION OUTPUT ;
    USE SIGNAL ;
    PORT
      LAYER M4 ;
        RECT 0.000 501.216 0.192 501.240 ;
    END
  END li_d[385]
  PIN li_d[386]
    DIRECTION OUTPUT ;
    USE SIGNAL ;
    PORT
      LAYER M4 ;
        RECT 0.000 501.696 0.192 501.720 ;
    END
  END li_d[386]
  PIN li_d[387]
    DIRECTION OUTPUT ;
    USE SIGNAL ;
    PORT
      LAYER M4 ;
        RECT 0.000 502.176 0.192 502.200 ;
    END
  END li_d[387]
  PIN li_d[388]
    DIRECTION OUTPUT ;
    USE SIGNAL ;
    PORT
      LAYER M4 ;
        RECT 0.000 502.656 0.192 502.680 ;
    END
  END li_d[388]
  PIN li_d[389]
    DIRECTION OUTPUT ;
    USE SIGNAL ;
    PORT
      LAYER M4 ;
        RECT 0.000 503.136 0.192 503.160 ;
    END
  END li_d[389]
  PIN li_d[390]
    DIRECTION OUTPUT ;
    USE SIGNAL ;
    PORT
      LAYER M4 ;
        RECT 0.000 503.616 0.192 503.640 ;
    END
  END li_d[390]
  PIN li_d[391]
    DIRECTION OUTPUT ;
    USE SIGNAL ;
    PORT
      LAYER M4 ;
        RECT 0.000 504.048 0.192 504.072 ;
    END
  END li_d[391]
  PIN li_d[392]
    DIRECTION OUTPUT ;
    USE SIGNAL ;
    PORT
      LAYER M4 ;
        RECT 0.000 504.528 0.192 504.552 ;
    END
  END li_d[392]
  PIN li_d[393]
    DIRECTION OUTPUT ;
    USE SIGNAL ;
    PORT
      LAYER M4 ;
        RECT 0.000 505.008 0.192 505.032 ;
    END
  END li_d[393]
  PIN li_d[394]
    DIRECTION OUTPUT ;
    USE SIGNAL ;
    PORT
      LAYER M4 ;
        RECT 0.000 505.488 0.192 505.512 ;
    END
  END li_d[394]
  PIN li_d[395]
    DIRECTION OUTPUT ;
    USE SIGNAL ;
    PORT
      LAYER M4 ;
        RECT 0.000 505.968 0.192 505.992 ;
    END
  END li_d[395]
  PIN li_d[396]
    DIRECTION OUTPUT ;
    USE SIGNAL ;
    PORT
      LAYER M4 ;
        RECT 0.000 506.448 0.192 506.472 ;
    END
  END li_d[396]
  PIN li_d[397]
    DIRECTION OUTPUT ;
    USE SIGNAL ;
    PORT
      LAYER M4 ;
        RECT 0.000 506.928 0.192 506.952 ;
    END
  END li_d[397]
  PIN li_d[398]
    DIRECTION OUTPUT ;
    USE SIGNAL ;
    PORT
      LAYER M4 ;
        RECT 0.000 507.408 0.192 507.432 ;
    END
  END li_d[398]
  PIN li_d[399]
    DIRECTION OUTPUT ;
    USE SIGNAL ;
    PORT
      LAYER M4 ;
        RECT 0.000 507.888 0.192 507.912 ;
    END
  END li_d[399]
  PIN li_d[400]
    DIRECTION OUTPUT ;
    USE SIGNAL ;
    PORT
      LAYER M4 ;
        RECT 0.000 508.368 0.192 508.392 ;
    END
  END li_d[400]
  PIN li_d[401]
    DIRECTION OUTPUT ;
    USE SIGNAL ;
    PORT
      LAYER M4 ;
        RECT 0.000 508.848 0.192 508.872 ;
    END
  END li_d[401]
  PIN li_d[402]
    DIRECTION OUTPUT ;
    USE SIGNAL ;
    PORT
      LAYER M4 ;
        RECT 0.000 509.328 0.192 509.352 ;
    END
  END li_d[402]
  PIN li_d[403]
    DIRECTION OUTPUT ;
    USE SIGNAL ;
    PORT
      LAYER M4 ;
        RECT 0.000 509.808 0.192 509.832 ;
    END
  END li_d[403]
  PIN li_d[404]
    DIRECTION OUTPUT ;
    USE SIGNAL ;
    PORT
      LAYER M4 ;
        RECT 0.000 510.240 0.192 510.264 ;
    END
  END li_d[404]
  PIN li_d[405]
    DIRECTION OUTPUT ;
    USE SIGNAL ;
    PORT
      LAYER M4 ;
        RECT 0.000 510.720 0.192 510.744 ;
    END
  END li_d[405]
  PIN li_d[406]
    DIRECTION OUTPUT ;
    USE SIGNAL ;
    PORT
      LAYER M4 ;
        RECT 0.000 511.200 0.192 511.224 ;
    END
  END li_d[406]
  PIN li_d[407]
    DIRECTION OUTPUT ;
    USE SIGNAL ;
    PORT
      LAYER M4 ;
        RECT 0.000 511.680 0.192 511.704 ;
    END
  END li_d[407]
  PIN li_d[408]
    DIRECTION OUTPUT ;
    USE SIGNAL ;
    PORT
      LAYER M4 ;
        RECT 0.000 512.160 0.192 512.184 ;
    END
  END li_d[408]
  PIN li_d[409]
    DIRECTION OUTPUT ;
    USE SIGNAL ;
    PORT
      LAYER M4 ;
        RECT 0.000 512.640 0.192 512.664 ;
    END
  END li_d[409]
  PIN li_d[410]
    DIRECTION OUTPUT ;
    USE SIGNAL ;
    PORT
      LAYER M4 ;
        RECT 0.000 513.120 0.192 513.144 ;
    END
  END li_d[410]
  PIN li_d[411]
    DIRECTION OUTPUT ;
    USE SIGNAL ;
    PORT
      LAYER M4 ;
        RECT 0.000 513.600 0.192 513.624 ;
    END
  END li_d[411]
  PIN li_d[412]
    DIRECTION OUTPUT ;
    USE SIGNAL ;
    PORT
      LAYER M4 ;
        RECT 0.000 514.080 0.192 514.104 ;
    END
  END li_d[412]
  PIN li_d[413]
    DIRECTION OUTPUT ;
    USE SIGNAL ;
    PORT
      LAYER M4 ;
        RECT 0.000 514.560 0.192 514.584 ;
    END
  END li_d[413]
  PIN li_d[414]
    DIRECTION OUTPUT ;
    USE SIGNAL ;
    PORT
      LAYER M4 ;
        RECT 0.000 515.040 0.192 515.064 ;
    END
  END li_d[414]
  PIN li_d[415]
    DIRECTION OUTPUT ;
    USE SIGNAL ;
    PORT
      LAYER M4 ;
        RECT 0.000 515.520 0.192 515.544 ;
    END
  END li_d[415]
  PIN li_d[416]
    DIRECTION OUTPUT ;
    USE SIGNAL ;
    PORT
      LAYER M4 ;
        RECT 0.000 516.000 0.192 516.024 ;
    END
  END li_d[416]
  PIN li_d[417]
    DIRECTION OUTPUT ;
    USE SIGNAL ;
    PORT
      LAYER M4 ;
        RECT 0.000 516.480 0.192 516.504 ;
    END
  END li_d[417]
  PIN li_d[418]
    DIRECTION OUTPUT ;
    USE SIGNAL ;
    PORT
      LAYER M4 ;
        RECT 0.000 516.912 0.192 516.936 ;
    END
  END li_d[418]
  PIN li_d[419]
    DIRECTION OUTPUT ;
    USE SIGNAL ;
    PORT
      LAYER M4 ;
        RECT 0.000 517.392 0.192 517.416 ;
    END
  END li_d[419]
  PIN li_d[420]
    DIRECTION OUTPUT ;
    USE SIGNAL ;
    PORT
      LAYER M4 ;
        RECT 0.000 517.872 0.192 517.896 ;
    END
  END li_d[420]
  PIN li_d[421]
    DIRECTION OUTPUT ;
    USE SIGNAL ;
    PORT
      LAYER M4 ;
        RECT 0.000 518.352 0.192 518.376 ;
    END
  END li_d[421]
  PIN li_d[422]
    DIRECTION OUTPUT ;
    USE SIGNAL ;
    PORT
      LAYER M4 ;
        RECT 0.000 518.832 0.192 518.856 ;
    END
  END li_d[422]
  PIN li_d[423]
    DIRECTION OUTPUT ;
    USE SIGNAL ;
    PORT
      LAYER M4 ;
        RECT 0.000 519.312 0.192 519.336 ;
    END
  END li_d[423]
  PIN li_d[424]
    DIRECTION OUTPUT ;
    USE SIGNAL ;
    PORT
      LAYER M4 ;
        RECT 0.000 519.792 0.192 519.816 ;
    END
  END li_d[424]
  PIN li_d[425]
    DIRECTION OUTPUT ;
    USE SIGNAL ;
    PORT
      LAYER M4 ;
        RECT 0.000 520.272 0.192 520.296 ;
    END
  END li_d[425]
  PIN li_d[426]
    DIRECTION OUTPUT ;
    USE SIGNAL ;
    PORT
      LAYER M4 ;
        RECT 0.000 520.752 0.192 520.776 ;
    END
  END li_d[426]
  PIN li_d[427]
    DIRECTION OUTPUT ;
    USE SIGNAL ;
    PORT
      LAYER M4 ;
        RECT 0.000 521.232 0.192 521.256 ;
    END
  END li_d[427]
  PIN li_d[428]
    DIRECTION OUTPUT ;
    USE SIGNAL ;
    PORT
      LAYER M4 ;
        RECT 0.000 521.712 0.192 521.736 ;
    END
  END li_d[428]
  PIN li_d[429]
    DIRECTION OUTPUT ;
    USE SIGNAL ;
    PORT
      LAYER M4 ;
        RECT 0.000 522.192 0.192 522.216 ;
    END
  END li_d[429]
  PIN li_d[430]
    DIRECTION OUTPUT ;
    USE SIGNAL ;
    PORT
      LAYER M4 ;
        RECT 0.000 522.672 0.192 522.696 ;
    END
  END li_d[430]
  PIN li_d[431]
    DIRECTION OUTPUT ;
    USE SIGNAL ;
    PORT
      LAYER M4 ;
        RECT 0.000 523.152 0.192 523.176 ;
    END
  END li_d[431]
  PIN li_d[432]
    DIRECTION OUTPUT ;
    USE SIGNAL ;
    PORT
      LAYER M4 ;
        RECT 0.000 523.584 0.192 523.608 ;
    END
  END li_d[432]
  PIN li_d[433]
    DIRECTION OUTPUT ;
    USE SIGNAL ;
    PORT
      LAYER M4 ;
        RECT 0.000 524.064 0.192 524.088 ;
    END
  END li_d[433]
  PIN li_d[434]
    DIRECTION OUTPUT ;
    USE SIGNAL ;
    PORT
      LAYER M4 ;
        RECT 0.000 524.544 0.192 524.568 ;
    END
  END li_d[434]
  PIN li_d[435]
    DIRECTION OUTPUT ;
    USE SIGNAL ;
    PORT
      LAYER M4 ;
        RECT 0.000 525.024 0.192 525.048 ;
    END
  END li_d[435]
  PIN li_d[436]
    DIRECTION OUTPUT ;
    USE SIGNAL ;
    PORT
      LAYER M4 ;
        RECT 0.000 525.504 0.192 525.528 ;
    END
  END li_d[436]
  PIN li_d[437]
    DIRECTION OUTPUT ;
    USE SIGNAL ;
    PORT
      LAYER M4 ;
        RECT 0.000 525.984 0.192 526.008 ;
    END
  END li_d[437]
  PIN li_d[438]
    DIRECTION OUTPUT ;
    USE SIGNAL ;
    PORT
      LAYER M4 ;
        RECT 0.000 526.464 0.192 526.488 ;
    END
  END li_d[438]
  PIN li_d[439]
    DIRECTION OUTPUT ;
    USE SIGNAL ;
    PORT
      LAYER M4 ;
        RECT 0.000 526.944 0.192 526.968 ;
    END
  END li_d[439]
  PIN li_d[440]
    DIRECTION OUTPUT ;
    USE SIGNAL ;
    PORT
      LAYER M4 ;
        RECT 0.000 527.424 0.192 527.448 ;
    END
  END li_d[440]
  PIN li_d[441]
    DIRECTION OUTPUT ;
    USE SIGNAL ;
    PORT
      LAYER M4 ;
        RECT 0.000 527.904 0.192 527.928 ;
    END
  END li_d[441]
  PIN li_d[442]
    DIRECTION OUTPUT ;
    USE SIGNAL ;
    PORT
      LAYER M4 ;
        RECT 0.000 528.384 0.192 528.408 ;
    END
  END li_d[442]
  PIN li_d[443]
    DIRECTION OUTPUT ;
    USE SIGNAL ;
    PORT
      LAYER M4 ;
        RECT 0.000 528.864 0.192 528.888 ;
    END
  END li_d[443]
  PIN li_d[444]
    DIRECTION OUTPUT ;
    USE SIGNAL ;
    PORT
      LAYER M4 ;
        RECT 0.000 529.344 0.192 529.368 ;
    END
  END li_d[444]
  PIN li_d[445]
    DIRECTION OUTPUT ;
    USE SIGNAL ;
    PORT
      LAYER M4 ;
        RECT 0.000 529.824 0.192 529.848 ;
    END
  END li_d[445]
  PIN li_d[446]
    DIRECTION OUTPUT ;
    USE SIGNAL ;
    PORT
      LAYER M4 ;
        RECT 0.000 530.256 0.192 530.280 ;
    END
  END li_d[446]
  PIN li_d[447]
    DIRECTION OUTPUT ;
    USE SIGNAL ;
    PORT
      LAYER M4 ;
        RECT 0.000 530.736 0.192 530.760 ;
    END
  END li_d[447]
  PIN li_d[448]
    DIRECTION OUTPUT ;
    USE SIGNAL ;
    PORT
      LAYER M4 ;
        RECT 0.000 531.216 0.192 531.240 ;
    END
  END li_d[448]
  PIN li_d[449]
    DIRECTION OUTPUT ;
    USE SIGNAL ;
    PORT
      LAYER M4 ;
        RECT 0.000 531.696 0.192 531.720 ;
    END
  END li_d[449]
  PIN li_d[450]
    DIRECTION OUTPUT ;
    USE SIGNAL ;
    PORT
      LAYER M4 ;
        RECT 0.000 532.176 0.192 532.200 ;
    END
  END li_d[450]
  PIN li_d[451]
    DIRECTION OUTPUT ;
    USE SIGNAL ;
    PORT
      LAYER M4 ;
        RECT 0.000 532.656 0.192 532.680 ;
    END
  END li_d[451]
  PIN li_d[452]
    DIRECTION OUTPUT ;
    USE SIGNAL ;
    PORT
      LAYER M4 ;
        RECT 0.000 533.136 0.192 533.160 ;
    END
  END li_d[452]
  PIN li_d[453]
    DIRECTION OUTPUT ;
    USE SIGNAL ;
    PORT
      LAYER M4 ;
        RECT 0.000 533.616 0.192 533.640 ;
    END
  END li_d[453]
  PIN li_d[454]
    DIRECTION OUTPUT ;
    USE SIGNAL ;
    PORT
      LAYER M4 ;
        RECT 0.000 534.096 0.192 534.120 ;
    END
  END li_d[454]
  PIN li_d[455]
    DIRECTION OUTPUT ;
    USE SIGNAL ;
    PORT
      LAYER M4 ;
        RECT 0.000 534.576 0.192 534.600 ;
    END
  END li_d[455]
  PIN li_d[456]
    DIRECTION OUTPUT ;
    USE SIGNAL ;
    PORT
      LAYER M4 ;
        RECT 0.000 535.056 0.192 535.080 ;
    END
  END li_d[456]
  PIN li_d[457]
    DIRECTION OUTPUT ;
    USE SIGNAL ;
    PORT
      LAYER M4 ;
        RECT 0.000 535.536 0.192 535.560 ;
    END
  END li_d[457]
  PIN li_d[458]
    DIRECTION OUTPUT ;
    USE SIGNAL ;
    PORT
      LAYER M4 ;
        RECT 0.000 536.016 0.192 536.040 ;
    END
  END li_d[458]
  PIN li_d[459]
    DIRECTION OUTPUT ;
    USE SIGNAL ;
    PORT
      LAYER M4 ;
        RECT 0.000 536.496 0.192 536.520 ;
    END
  END li_d[459]
  PIN li_d[460]
    DIRECTION OUTPUT ;
    USE SIGNAL ;
    PORT
      LAYER M4 ;
        RECT 0.000 536.928 0.192 536.952 ;
    END
  END li_d[460]
  PIN li_d[461]
    DIRECTION OUTPUT ;
    USE SIGNAL ;
    PORT
      LAYER M4 ;
        RECT 0.000 537.408 0.192 537.432 ;
    END
  END li_d[461]
  PIN li_d[462]
    DIRECTION OUTPUT ;
    USE SIGNAL ;
    PORT
      LAYER M4 ;
        RECT 0.000 537.888 0.192 537.912 ;
    END
  END li_d[462]
  PIN li_d[463]
    DIRECTION OUTPUT ;
    USE SIGNAL ;
    PORT
      LAYER M4 ;
        RECT 0.000 538.368 0.192 538.392 ;
    END
  END li_d[463]
  PIN li_d[464]
    DIRECTION OUTPUT ;
    USE SIGNAL ;
    PORT
      LAYER M4 ;
        RECT 0.000 538.848 0.192 538.872 ;
    END
  END li_d[464]
  PIN li_d[465]
    DIRECTION OUTPUT ;
    USE SIGNAL ;
    PORT
      LAYER M4 ;
        RECT 0.000 539.328 0.192 539.352 ;
    END
  END li_d[465]
  PIN li_d[466]
    DIRECTION OUTPUT ;
    USE SIGNAL ;
    PORT
      LAYER M4 ;
        RECT 0.000 539.808 0.192 539.832 ;
    END
  END li_d[466]
  PIN li_d[467]
    DIRECTION OUTPUT ;
    USE SIGNAL ;
    PORT
      LAYER M4 ;
        RECT 0.000 540.288 0.192 540.312 ;
    END
  END li_d[467]
  PIN li_d[468]
    DIRECTION OUTPUT ;
    USE SIGNAL ;
    PORT
      LAYER M4 ;
        RECT 0.000 540.768 0.192 540.792 ;
    END
  END li_d[468]
  PIN li_d[469]
    DIRECTION OUTPUT ;
    USE SIGNAL ;
    PORT
      LAYER M4 ;
        RECT 0.000 541.248 0.192 541.272 ;
    END
  END li_d[469]
  PIN li_d[470]
    DIRECTION OUTPUT ;
    USE SIGNAL ;
    PORT
      LAYER M4 ;
        RECT 0.000 541.728 0.192 541.752 ;
    END
  END li_d[470]
  PIN li_d[471]
    DIRECTION OUTPUT ;
    USE SIGNAL ;
    PORT
      LAYER M4 ;
        RECT 0.000 542.208 0.192 542.232 ;
    END
  END li_d[471]
  PIN li_d[472]
    DIRECTION OUTPUT ;
    USE SIGNAL ;
    PORT
      LAYER M4 ;
        RECT 0.000 542.688 0.192 542.712 ;
    END
  END li_d[472]
  PIN li_d[473]
    DIRECTION OUTPUT ;
    USE SIGNAL ;
    PORT
      LAYER M4 ;
        RECT 0.000 543.168 0.192 543.192 ;
    END
  END li_d[473]
  PIN li_d[474]
    DIRECTION OUTPUT ;
    USE SIGNAL ;
    PORT
      LAYER M4 ;
        RECT 0.000 543.600 0.192 543.624 ;
    END
  END li_d[474]
  PIN li_d[475]
    DIRECTION OUTPUT ;
    USE SIGNAL ;
    PORT
      LAYER M4 ;
        RECT 0.000 544.080 0.192 544.104 ;
    END
  END li_d[475]
  PIN li_d[476]
    DIRECTION OUTPUT ;
    USE SIGNAL ;
    PORT
      LAYER M4 ;
        RECT 0.000 544.560 0.192 544.584 ;
    END
  END li_d[476]
  PIN li_d[477]
    DIRECTION OUTPUT ;
    USE SIGNAL ;
    PORT
      LAYER M4 ;
        RECT 0.000 545.040 0.192 545.064 ;
    END
  END li_d[477]
  PIN li_d[478]
    DIRECTION OUTPUT ;
    USE SIGNAL ;
    PORT
      LAYER M4 ;
        RECT 0.000 545.520 0.192 545.544 ;
    END
  END li_d[478]
  PIN li_d[479]
    DIRECTION OUTPUT ;
    USE SIGNAL ;
    PORT
      LAYER M4 ;
        RECT 0.000 546.000 0.192 546.024 ;
    END
  END li_d[479]
  PIN li_d[480]
    DIRECTION OUTPUT ;
    USE SIGNAL ;
    PORT
      LAYER M4 ;
        RECT 0.000 546.480 0.192 546.504 ;
    END
  END li_d[480]
  PIN li_d[481]
    DIRECTION OUTPUT ;
    USE SIGNAL ;
    PORT
      LAYER M4 ;
        RECT 0.000 546.960 0.192 546.984 ;
    END
  END li_d[481]
  PIN li_d[482]
    DIRECTION OUTPUT ;
    USE SIGNAL ;
    PORT
      LAYER M4 ;
        RECT 0.000 547.440 0.192 547.464 ;
    END
  END li_d[482]
  PIN li_d[483]
    DIRECTION OUTPUT ;
    USE SIGNAL ;
    PORT
      LAYER M4 ;
        RECT 0.000 547.920 0.192 547.944 ;
    END
  END li_d[483]
  PIN li_d[484]
    DIRECTION OUTPUT ;
    USE SIGNAL ;
    PORT
      LAYER M4 ;
        RECT 0.000 548.400 0.192 548.424 ;
    END
  END li_d[484]
  PIN li_d[485]
    DIRECTION OUTPUT ;
    USE SIGNAL ;
    PORT
      LAYER M4 ;
        RECT 0.000 548.880 0.192 548.904 ;
    END
  END li_d[485]
  PIN li_d[486]
    DIRECTION OUTPUT ;
    USE SIGNAL ;
    PORT
      LAYER M4 ;
        RECT 0.000 549.360 0.192 549.384 ;
    END
  END li_d[486]
  PIN li_d[487]
    DIRECTION OUTPUT ;
    USE SIGNAL ;
    PORT
      LAYER M4 ;
        RECT 0.000 549.792 0.192 549.816 ;
    END
  END li_d[487]
  PIN li_d[488]
    DIRECTION OUTPUT ;
    USE SIGNAL ;
    PORT
      LAYER M4 ;
        RECT 0.000 550.272 0.192 550.296 ;
    END
  END li_d[488]
  PIN li_d[489]
    DIRECTION OUTPUT ;
    USE SIGNAL ;
    PORT
      LAYER M4 ;
        RECT 0.000 550.752 0.192 550.776 ;
    END
  END li_d[489]
  PIN li_d[490]
    DIRECTION OUTPUT ;
    USE SIGNAL ;
    PORT
      LAYER M4 ;
        RECT 0.000 551.232 0.192 551.256 ;
    END
  END li_d[490]
  PIN li_d[491]
    DIRECTION OUTPUT ;
    USE SIGNAL ;
    PORT
      LAYER M4 ;
        RECT 0.000 551.712 0.192 551.736 ;
    END
  END li_d[491]
  PIN li_d[492]
    DIRECTION OUTPUT ;
    USE SIGNAL ;
    PORT
      LAYER M4 ;
        RECT 0.000 552.192 0.192 552.216 ;
    END
  END li_d[492]
  PIN li_d[493]
    DIRECTION OUTPUT ;
    USE SIGNAL ;
    PORT
      LAYER M4 ;
        RECT 0.000 552.672 0.192 552.696 ;
    END
  END li_d[493]
  PIN li_d[494]
    DIRECTION OUTPUT ;
    USE SIGNAL ;
    PORT
      LAYER M4 ;
        RECT 0.000 553.152 0.192 553.176 ;
    END
  END li_d[494]
  PIN li_d[495]
    DIRECTION OUTPUT ;
    USE SIGNAL ;
    PORT
      LAYER M4 ;
        RECT 0.000 553.632 0.192 553.656 ;
    END
  END li_d[495]
  PIN li_d[496]
    DIRECTION OUTPUT ;
    USE SIGNAL ;
    PORT
      LAYER M4 ;
        RECT 0.000 554.112 0.192 554.136 ;
    END
  END li_d[496]
  PIN li_d[497]
    DIRECTION OUTPUT ;
    USE SIGNAL ;
    PORT
      LAYER M4 ;
        RECT 0.000 554.592 0.192 554.616 ;
    END
  END li_d[497]
  PIN li_d[498]
    DIRECTION OUTPUT ;
    USE SIGNAL ;
    PORT
      LAYER M4 ;
        RECT 0.000 555.072 0.192 555.096 ;
    END
  END li_d[498]
  PIN li_d[499]
    DIRECTION OUTPUT ;
    USE SIGNAL ;
    PORT
      LAYER M4 ;
        RECT 0.000 555.552 0.192 555.576 ;
    END
  END li_d[499]
  PIN li_d[500]
    DIRECTION OUTPUT ;
    USE SIGNAL ;
    PORT
      LAYER M4 ;
        RECT 0.000 556.032 0.192 556.056 ;
    END
  END li_d[500]
  PIN li_d[501]
    DIRECTION OUTPUT ;
    USE SIGNAL ;
    PORT
      LAYER M4 ;
        RECT 0.000 556.464 0.192 556.488 ;
    END
  END li_d[501]
  PIN li_d[502]
    DIRECTION OUTPUT ;
    USE SIGNAL ;
    PORT
      LAYER M4 ;
        RECT 0.000 556.944 0.192 556.968 ;
    END
  END li_d[502]
  PIN li_d[503]
    DIRECTION OUTPUT ;
    USE SIGNAL ;
    PORT
      LAYER M4 ;
        RECT 0.000 557.424 0.192 557.448 ;
    END
  END li_d[503]
  PIN li_d[504]
    DIRECTION OUTPUT ;
    USE SIGNAL ;
    PORT
      LAYER M4 ;
        RECT 0.000 557.904 0.192 557.928 ;
    END
  END li_d[504]
  PIN li_d[505]
    DIRECTION OUTPUT ;
    USE SIGNAL ;
    PORT
      LAYER M4 ;
        RECT 0.000 558.384 0.192 558.408 ;
    END
  END li_d[505]
  PIN li_d[506]
    DIRECTION OUTPUT ;
    USE SIGNAL ;
    PORT
      LAYER M4 ;
        RECT 0.000 558.864 0.192 558.888 ;
    END
  END li_d[506]
  PIN li_d[507]
    DIRECTION OUTPUT ;
    USE SIGNAL ;
    PORT
      LAYER M4 ;
        RECT 0.000 559.344 0.192 559.368 ;
    END
  END li_d[507]
  PIN li_d[508]
    DIRECTION OUTPUT ;
    USE SIGNAL ;
    PORT
      LAYER M4 ;
        RECT 0.000 559.824 0.192 559.848 ;
    END
  END li_d[508]
  PIN li_d[509]
    DIRECTION OUTPUT ;
    USE SIGNAL ;
    PORT
      LAYER M4 ;
        RECT 0.000 560.304 0.192 560.328 ;
    END
  END li_d[509]
  PIN li_d[510]
    DIRECTION OUTPUT ;
    USE SIGNAL ;
    PORT
      LAYER M4 ;
        RECT 0.000 560.784 0.192 560.808 ;
    END
  END li_d[510]
  PIN li_d[511]
    DIRECTION OUTPUT ;
    USE SIGNAL ;
    PORT
      LAYER M4 ;
        RECT 0.000 561.264 0.192 561.288 ;
    END
  END li_d[511]
  PIN li_d[512]
    DIRECTION OUTPUT ;
    USE SIGNAL ;
    PORT
      LAYER M4 ;
        RECT 0.000 561.744 0.192 561.768 ;
    END
  END li_d[512]
  PIN li_d[513]
    DIRECTION OUTPUT ;
    USE SIGNAL ;
    PORT
      LAYER M4 ;
        RECT 0.000 562.224 0.192 562.248 ;
    END
  END li_d[513]
  PIN li_d[514]
    DIRECTION OUTPUT ;
    USE SIGNAL ;
    PORT
      LAYER M4 ;
        RECT 0.000 562.704 0.192 562.728 ;
    END
  END li_d[514]
  PIN li_d[515]
    DIRECTION OUTPUT ;
    USE SIGNAL ;
    PORT
      LAYER M4 ;
        RECT 0.000 563.136 0.192 563.160 ;
    END
  END li_d[515]
  PIN li_d[516]
    DIRECTION OUTPUT ;
    USE SIGNAL ;
    PORT
      LAYER M4 ;
        RECT 0.000 563.616 0.192 563.640 ;
    END
  END li_d[516]
  PIN li_d[517]
    DIRECTION OUTPUT ;
    USE SIGNAL ;
    PORT
      LAYER M4 ;
        RECT 0.000 564.096 0.192 564.120 ;
    END
  END li_d[517]
  PIN li_d[518]
    DIRECTION OUTPUT ;
    USE SIGNAL ;
    PORT
      LAYER M4 ;
        RECT 0.000 564.576 0.192 564.600 ;
    END
  END li_d[518]
  PIN li_d[519]
    DIRECTION OUTPUT ;
    USE SIGNAL ;
    PORT
      LAYER M4 ;
        RECT 0.000 565.056 0.192 565.080 ;
    END
  END li_d[519]
  PIN li_d[520]
    DIRECTION OUTPUT ;
    USE SIGNAL ;
    PORT
      LAYER M4 ;
        RECT 0.000 565.536 0.192 565.560 ;
    END
  END li_d[520]
  PIN li_d[521]
    DIRECTION OUTPUT ;
    USE SIGNAL ;
    PORT
      LAYER M4 ;
        RECT 0.000 566.016 0.192 566.040 ;
    END
  END li_d[521]
  PIN li_d[522]
    DIRECTION OUTPUT ;
    USE SIGNAL ;
    PORT
      LAYER M4 ;
        RECT 0.000 566.496 0.192 566.520 ;
    END
  END li_d[522]
  PIN li_d[523]
    DIRECTION OUTPUT ;
    USE SIGNAL ;
    PORT
      LAYER M4 ;
        RECT 0.000 566.976 0.192 567.000 ;
    END
  END li_d[523]
  PIN li_d[524]
    DIRECTION OUTPUT ;
    USE SIGNAL ;
    PORT
      LAYER M4 ;
        RECT 0.000 567.456 0.192 567.480 ;
    END
  END li_d[524]
  PIN li_d[525]
    DIRECTION OUTPUT ;
    USE SIGNAL ;
    PORT
      LAYER M4 ;
        RECT 0.000 567.936 0.192 567.960 ;
    END
  END li_d[525]
  PIN li_d[526]
    DIRECTION OUTPUT ;
    USE SIGNAL ;
    PORT
      LAYER M4 ;
        RECT 0.000 568.416 0.192 568.440 ;
    END
  END li_d[526]
  PIN li_d[527]
    DIRECTION OUTPUT ;
    USE SIGNAL ;
    PORT
      LAYER M4 ;
        RECT 0.000 568.896 0.192 568.920 ;
    END
  END li_d[527]
  PIN li_d[528]
    DIRECTION OUTPUT ;
    USE SIGNAL ;
    PORT
      LAYER M4 ;
        RECT 0.000 569.376 0.192 569.400 ;
    END
  END li_d[528]
  PIN li_d[529]
    DIRECTION OUTPUT ;
    USE SIGNAL ;
    PORT
      LAYER M4 ;
        RECT 0.000 569.808 0.192 569.832 ;
    END
  END li_d[529]
  PIN li_d[530]
    DIRECTION OUTPUT ;
    USE SIGNAL ;
    PORT
      LAYER M4 ;
        RECT 0.000 570.288 0.192 570.312 ;
    END
  END li_d[530]
  PIN li_d[531]
    DIRECTION OUTPUT ;
    USE SIGNAL ;
    PORT
      LAYER M4 ;
        RECT 0.000 570.768 0.192 570.792 ;
    END
  END li_d[531]
  PIN li_d[532]
    DIRECTION OUTPUT ;
    USE SIGNAL ;
    PORT
      LAYER M4 ;
        RECT 0.000 571.248 0.192 571.272 ;
    END
  END li_d[532]
  PIN li_d[533]
    DIRECTION OUTPUT ;
    USE SIGNAL ;
    PORT
      LAYER M4 ;
        RECT 0.000 571.728 0.192 571.752 ;
    END
  END li_d[533]
  PIN li_d[534]
    DIRECTION OUTPUT ;
    USE SIGNAL ;
    PORT
      LAYER M4 ;
        RECT 0.000 572.208 0.192 572.232 ;
    END
  END li_d[534]
  PIN li_d[535]
    DIRECTION OUTPUT ;
    USE SIGNAL ;
    PORT
      LAYER M4 ;
        RECT 0.000 572.688 0.192 572.712 ;
    END
  END li_d[535]
  PIN li_d[536]
    DIRECTION OUTPUT ;
    USE SIGNAL ;
    PORT
      LAYER M4 ;
        RECT 0.000 573.168 0.192 573.192 ;
    END
  END li_d[536]
  PIN li_d[537]
    DIRECTION OUTPUT ;
    USE SIGNAL ;
    PORT
      LAYER M4 ;
        RECT 0.000 573.648 0.192 573.672 ;
    END
  END li_d[537]
  PIN li_d[538]
    DIRECTION OUTPUT ;
    USE SIGNAL ;
    PORT
      LAYER M4 ;
        RECT 0.000 574.128 0.192 574.152 ;
    END
  END li_d[538]
  PIN li_d[539]
    DIRECTION OUTPUT ;
    USE SIGNAL ;
    PORT
      LAYER M4 ;
        RECT 0.000 574.608 0.192 574.632 ;
    END
  END li_d[539]
  PIN li_d[540]
    DIRECTION OUTPUT ;
    USE SIGNAL ;
    PORT
      LAYER M4 ;
        RECT 0.000 575.088 0.192 575.112 ;
    END
  END li_d[540]
  PIN li_d[541]
    DIRECTION OUTPUT ;
    USE SIGNAL ;
    PORT
      LAYER M4 ;
        RECT 0.000 575.568 0.192 575.592 ;
    END
  END li_d[541]
  PIN li_d[542]
    DIRECTION OUTPUT ;
    USE SIGNAL ;
    PORT
      LAYER M4 ;
        RECT 0.000 576.048 0.192 576.072 ;
    END
  END li_d[542]
  PIN li_d[543]
    DIRECTION OUTPUT ;
    USE SIGNAL ;
    PORT
      LAYER M4 ;
        RECT 0.000 576.480 0.192 576.504 ;
    END
  END li_d[543]
  PIN li_d[544]
    DIRECTION OUTPUT ;
    USE SIGNAL ;
    PORT
      LAYER M4 ;
        RECT 0.000 576.960 0.192 576.984 ;
    END
  END li_d[544]
  PIN li_d[545]
    DIRECTION OUTPUT ;
    USE SIGNAL ;
    PORT
      LAYER M4 ;
        RECT 0.000 577.440 0.192 577.464 ;
    END
  END li_d[545]
  PIN li_d[546]
    DIRECTION OUTPUT ;
    USE SIGNAL ;
    PORT
      LAYER M4 ;
        RECT 0.000 577.920 0.192 577.944 ;
    END
  END li_d[546]
  PIN li_d[547]
    DIRECTION OUTPUT ;
    USE SIGNAL ;
    PORT
      LAYER M4 ;
        RECT 0.000 578.400 0.192 578.424 ;
    END
  END li_d[547]
  PIN li_d[548]
    DIRECTION OUTPUT ;
    USE SIGNAL ;
    PORT
      LAYER M4 ;
        RECT 0.000 578.880 0.192 578.904 ;
    END
  END li_d[548]
  PIN li_d[549]
    DIRECTION OUTPUT ;
    USE SIGNAL ;
    PORT
      LAYER M4 ;
        RECT 0.000 579.360 0.192 579.384 ;
    END
  END li_d[549]
  PIN li_d[550]
    DIRECTION OUTPUT ;
    USE SIGNAL ;
    PORT
      LAYER M4 ;
        RECT 0.000 579.840 0.192 579.864 ;
    END
  END li_d[550]
  PIN li_d[551]
    DIRECTION OUTPUT ;
    USE SIGNAL ;
    PORT
      LAYER M4 ;
        RECT 0.000 580.320 0.192 580.344 ;
    END
  END li_d[551]
  PIN li_d[552]
    DIRECTION OUTPUT ;
    USE SIGNAL ;
    PORT
      LAYER M4 ;
        RECT 0.000 580.800 0.192 580.824 ;
    END
  END li_d[552]
  PIN flt[0]
    DIRECTION OUTPUT ;
    USE SIGNAL ;
    PORT
      LAYER M4 ;
        RECT 0.000 312.672 0.192 312.696 ;
    END
  END flt[0]
  PIN flt[1]
    DIRECTION OUTPUT ;
    USE SIGNAL ;
    PORT
      LAYER M4 ;
        RECT 0.000 313.728 0.192 313.752 ;
    END
  END flt[1]
  PIN flt[2]
    DIRECTION OUTPUT ;
    USE SIGNAL ;
    PORT
      LAYER M4 ;
        RECT 0.000 314.784 0.192 314.808 ;
    END
  END flt[2]
  PIN ck
    DIRECTION INPUT ;
    USE CLOCK ;
    PORT
      LAYER M4 ;
        RECT 0.000 299.136 0.192 299.160 ;
    END
  END ck
  PIN rs
    DIRECTION INPUT ;
    USE SIGNAL ;
    PORT
      LAYER M4 ;
        RECT 0.000 303.456 0.192 303.480 ;
    END
  END rs
  PIN chb
    DIRECTION INPUT ;
    USE SIGNAL ;
    PORT
      LAYER M4 ;
        RECT 0.000 281.856 0.192 281.880 ;
    END
  END chb
  PIN rx[0]
    DIRECTION INPUT ;
    USE SIGNAL ;
    PORT
      LAYER M4 ;
        RECT 725.568 2.448 725.760 2.472 ;
    END
  END rx[0]
  PIN rx[1]
    DIRECTION INPUT ;
    USE SIGNAL ;
    PORT
      LAYER M4 ;
        RECT 725.568 2.976 725.760 3.000 ;
    END
  END rx[1]
  PIN rx[2]
    DIRECTION INPUT ;
    USE SIGNAL ;
    PORT
      LAYER M4 ;
        RECT 725.568 3.552 725.760 3.576 ;
    END
  END rx[2]
  PIN rx[3]
    DIRECTION INPUT ;
    USE SIGNAL ;
    PORT
      LAYER M4 ;
        RECT 725.568 4.080 725.760 4.104 ;
    END
  END rx[3]
  PIN rx[4]
    DIRECTION INPUT ;
    USE SIGNAL ;
    PORT
      LAYER M4 ;
        RECT 725.568 4.656 725.760 4.680 ;
    END
  END rx[4]
  PIN rx[5]
    DIRECTION INPUT ;
    USE SIGNAL ;
    PORT
      LAYER M4 ;
        RECT 725.568 5.184 725.760 5.208 ;
    END
  END rx[5]
  PIN rx[6]
    DIRECTION INPUT ;
    USE SIGNAL ;
    PORT
      LAYER M4 ;
        RECT 725.568 5.760 725.760 5.784 ;
    END
  END rx[6]
  PIN rx[7]
    DIRECTION INPUT ;
    USE SIGNAL ;
    PORT
      LAYER M4 ;
        RECT 725.568 6.336 725.760 6.360 ;
    END
  END rx[7]
  PIN rx[8]
    DIRECTION INPUT ;
    USE SIGNAL ;
    PORT
      LAYER M4 ;
        RECT 725.568 6.864 725.760 6.888 ;
    END
  END rx[8]
  PIN rx[9]
    DIRECTION INPUT ;
    USE SIGNAL ;
    PORT
      LAYER M4 ;
        RECT 725.568 7.440 725.760 7.464 ;
    END
  END rx[9]
  PIN rx[10]
    DIRECTION INPUT ;
    USE SIGNAL ;
    PORT
      LAYER M4 ;
        RECT 725.568 7.968 725.760 7.992 ;
    END
  END rx[10]
  PIN rx[11]
    DIRECTION INPUT ;
    USE SIGNAL ;
    PORT
      LAYER M4 ;
        RECT 725.568 8.544 725.760 8.568 ;
    END
  END rx[11]
  PIN rx[12]
    DIRECTION INPUT ;
    USE SIGNAL ;
    PORT
      LAYER M4 ;
        RECT 725.568 9.072 725.760 9.096 ;
    END
  END rx[12]
  PIN rx[13]
    DIRECTION INPUT ;
    USE SIGNAL ;
    PORT
      LAYER M4 ;
        RECT 725.568 9.648 725.760 9.672 ;
    END
  END rx[13]
  PIN rx[14]
    DIRECTION INPUT ;
    USE SIGNAL ;
    PORT
      LAYER M4 ;
        RECT 725.568 10.224 725.760 10.248 ;
    END
  END rx[14]
  PIN rx[15]
    DIRECTION INPUT ;
    USE SIGNAL ;
    PORT
      LAYER M4 ;
        RECT 725.568 10.752 725.760 10.776 ;
    END
  END rx[15]
  PIN rx[16]
    DIRECTION INPUT ;
    USE SIGNAL ;
    PORT
      LAYER M4 ;
        RECT 725.568 11.328 725.760 11.352 ;
    END
  END rx[16]
  PIN rx[17]
    DIRECTION INPUT ;
    USE SIGNAL ;
    PORT
      LAYER M4 ;
        RECT 725.568 11.856 725.760 11.880 ;
    END
  END rx[17]
  PIN rx[18]
    DIRECTION INPUT ;
    USE SIGNAL ;
    PORT
      LAYER M4 ;
        RECT 725.568 12.432 725.760 12.456 ;
    END
  END rx[18]
  PIN rx[19]
    DIRECTION INPUT ;
    USE SIGNAL ;
    PORT
      LAYER M4 ;
        RECT 725.568 13.008 725.760 13.032 ;
    END
  END rx[19]
  PIN rx[20]
    DIRECTION INPUT ;
    USE SIGNAL ;
    PORT
      LAYER M4 ;
        RECT 725.568 13.536 725.760 13.560 ;
    END
  END rx[20]
  PIN rx[21]
    DIRECTION INPUT ;
    USE SIGNAL ;
    PORT
      LAYER M4 ;
        RECT 725.568 14.112 725.760 14.136 ;
    END
  END rx[21]
  PIN rx[22]
    DIRECTION INPUT ;
    USE SIGNAL ;
    PORT
      LAYER M4 ;
        RECT 725.568 14.640 725.760 14.664 ;
    END
  END rx[22]
  PIN rx[23]
    DIRECTION INPUT ;
    USE SIGNAL ;
    PORT
      LAYER M4 ;
        RECT 725.568 15.216 725.760 15.240 ;
    END
  END rx[23]
  PIN rx[24]
    DIRECTION INPUT ;
    USE SIGNAL ;
    PORT
      LAYER M4 ;
        RECT 725.568 15.744 725.760 15.768 ;
    END
  END rx[24]
  PIN rx[25]
    DIRECTION INPUT ;
    USE SIGNAL ;
    PORT
      LAYER M4 ;
        RECT 725.568 16.320 725.760 16.344 ;
    END
  END rx[25]
  PIN rx[26]
    DIRECTION INPUT ;
    USE SIGNAL ;
    PORT
      LAYER M4 ;
        RECT 725.568 16.896 725.760 16.920 ;
    END
  END rx[26]
  PIN rx[27]
    DIRECTION INPUT ;
    USE SIGNAL ;
    PORT
      LAYER M4 ;
        RECT 725.568 17.424 725.760 17.448 ;
    END
  END rx[27]
  PIN rx[28]
    DIRECTION INPUT ;
    USE SIGNAL ;
    PORT
      LAYER M4 ;
        RECT 725.568 18.000 725.760 18.024 ;
    END
  END rx[28]
  PIN rx[29]
    DIRECTION INPUT ;
    USE SIGNAL ;
    PORT
      LAYER M4 ;
        RECT 725.568 18.528 725.760 18.552 ;
    END
  END rx[29]
  PIN rx[30]
    DIRECTION INPUT ;
    USE SIGNAL ;
    PORT
      LAYER M4 ;
        RECT 725.568 19.104 725.760 19.128 ;
    END
  END rx[30]
  PIN rx[31]
    DIRECTION INPUT ;
    USE SIGNAL ;
    PORT
      LAYER M4 ;
        RECT 725.568 19.632 725.760 19.656 ;
    END
  END rx[31]
  PIN rx[32]
    DIRECTION INPUT ;
    USE SIGNAL ;
    PORT
      LAYER M4 ;
        RECT 725.568 20.208 725.760 20.232 ;
    END
  END rx[32]
  PIN rx[33]
    DIRECTION INPUT ;
    USE SIGNAL ;
    PORT
      LAYER M4 ;
        RECT 725.568 20.784 725.760 20.808 ;
    END
  END rx[33]
  PIN rx[34]
    DIRECTION INPUT ;
    USE SIGNAL ;
    PORT
      LAYER M4 ;
        RECT 725.568 21.312 725.760 21.336 ;
    END
  END rx[34]
  PIN rx[35]
    DIRECTION INPUT ;
    USE SIGNAL ;
    PORT
      LAYER M4 ;
        RECT 725.568 21.888 725.760 21.912 ;
    END
  END rx[35]
  PIN rx[36]
    DIRECTION INPUT ;
    USE SIGNAL ;
    PORT
      LAYER M4 ;
        RECT 725.568 22.416 725.760 22.440 ;
    END
  END rx[36]
  PIN rx[37]
    DIRECTION INPUT ;
    USE SIGNAL ;
    PORT
      LAYER M4 ;
        RECT 725.568 22.992 725.760 23.016 ;
    END
  END rx[37]
  PIN rx[38]
    DIRECTION INPUT ;
    USE SIGNAL ;
    PORT
      LAYER M4 ;
        RECT 725.568 23.520 725.760 23.544 ;
    END
  END rx[38]
  PIN rx[39]
    DIRECTION INPUT ;
    USE SIGNAL ;
    PORT
      LAYER M4 ;
        RECT 725.568 24.096 725.760 24.120 ;
    END
  END rx[39]
  PIN rx[40]
    DIRECTION INPUT ;
    USE SIGNAL ;
    PORT
      LAYER M4 ;
        RECT 725.568 24.672 725.760 24.696 ;
    END
  END rx[40]
  PIN rx[41]
    DIRECTION INPUT ;
    USE SIGNAL ;
    PORT
      LAYER M4 ;
        RECT 725.568 25.200 725.760 25.224 ;
    END
  END rx[41]
  PIN rx[42]
    DIRECTION INPUT ;
    USE SIGNAL ;
    PORT
      LAYER M4 ;
        RECT 725.568 25.776 725.760 25.800 ;
    END
  END rx[42]
  PIN rx[43]
    DIRECTION INPUT ;
    USE SIGNAL ;
    PORT
      LAYER M4 ;
        RECT 725.568 26.304 725.760 26.328 ;
    END
  END rx[43]
  PIN rx[44]
    DIRECTION INPUT ;
    USE SIGNAL ;
    PORT
      LAYER M4 ;
        RECT 725.568 26.880 725.760 26.904 ;
    END
  END rx[44]
  PIN rx[45]
    DIRECTION INPUT ;
    USE SIGNAL ;
    PORT
      LAYER M4 ;
        RECT 725.568 27.456 725.760 27.480 ;
    END
  END rx[45]
  PIN rx[46]
    DIRECTION INPUT ;
    USE SIGNAL ;
    PORT
      LAYER M4 ;
        RECT 725.568 27.984 725.760 28.008 ;
    END
  END rx[46]
  PIN rx[47]
    DIRECTION INPUT ;
    USE SIGNAL ;
    PORT
      LAYER M4 ;
        RECT 725.568 28.560 725.760 28.584 ;
    END
  END rx[47]
  PIN rx[48]
    DIRECTION INPUT ;
    USE SIGNAL ;
    PORT
      LAYER M4 ;
        RECT 725.568 29.088 725.760 29.112 ;
    END
  END rx[48]
  PIN rx[49]
    DIRECTION INPUT ;
    USE SIGNAL ;
    PORT
      LAYER M4 ;
        RECT 725.568 29.664 725.760 29.688 ;
    END
  END rx[49]
  PIN rx[50]
    DIRECTION INPUT ;
    USE SIGNAL ;
    PORT
      LAYER M4 ;
        RECT 725.568 30.192 725.760 30.216 ;
    END
  END rx[50]
  PIN rx[51]
    DIRECTION INPUT ;
    USE SIGNAL ;
    PORT
      LAYER M4 ;
        RECT 725.568 30.768 725.760 30.792 ;
    END
  END rx[51]
  PIN rx[52]
    DIRECTION INPUT ;
    USE SIGNAL ;
    PORT
      LAYER M4 ;
        RECT 725.568 31.344 725.760 31.368 ;
    END
  END rx[52]
  PIN rx[53]
    DIRECTION INPUT ;
    USE SIGNAL ;
    PORT
      LAYER M4 ;
        RECT 725.568 31.872 725.760 31.896 ;
    END
  END rx[53]
  PIN rx[54]
    DIRECTION INPUT ;
    USE SIGNAL ;
    PORT
      LAYER M4 ;
        RECT 725.568 32.448 725.760 32.472 ;
    END
  END rx[54]
  PIN rx[55]
    DIRECTION INPUT ;
    USE SIGNAL ;
    PORT
      LAYER M4 ;
        RECT 725.568 32.976 725.760 33.000 ;
    END
  END rx[55]
  PIN rx[56]
    DIRECTION INPUT ;
    USE SIGNAL ;
    PORT
      LAYER M4 ;
        RECT 725.568 33.552 725.760 33.576 ;
    END
  END rx[56]
  PIN rx[57]
    DIRECTION INPUT ;
    USE SIGNAL ;
    PORT
      LAYER M4 ;
        RECT 725.568 34.080 725.760 34.104 ;
    END
  END rx[57]
  PIN rx[58]
    DIRECTION INPUT ;
    USE SIGNAL ;
    PORT
      LAYER M4 ;
        RECT 725.568 34.656 725.760 34.680 ;
    END
  END rx[58]
  PIN rx[59]
    DIRECTION INPUT ;
    USE SIGNAL ;
    PORT
      LAYER M4 ;
        RECT 725.568 35.232 725.760 35.256 ;
    END
  END rx[59]
  PIN rx[60]
    DIRECTION INPUT ;
    USE SIGNAL ;
    PORT
      LAYER M4 ;
        RECT 725.568 35.760 725.760 35.784 ;
    END
  END rx[60]
  PIN rx[61]
    DIRECTION INPUT ;
    USE SIGNAL ;
    PORT
      LAYER M4 ;
        RECT 725.568 36.336 725.760 36.360 ;
    END
  END rx[61]
  PIN rx[62]
    DIRECTION INPUT ;
    USE SIGNAL ;
    PORT
      LAYER M4 ;
        RECT 725.568 36.864 725.760 36.888 ;
    END
  END rx[62]
  PIN rx[63]
    DIRECTION INPUT ;
    USE SIGNAL ;
    PORT
      LAYER M4 ;
        RECT 725.568 37.440 725.760 37.464 ;
    END
  END rx[63]
  PIN rx[64]
    DIRECTION INPUT ;
    USE SIGNAL ;
    PORT
      LAYER M4 ;
        RECT 725.568 38.016 725.760 38.040 ;
    END
  END rx[64]
  PIN rx[65]
    DIRECTION INPUT ;
    USE SIGNAL ;
    PORT
      LAYER M4 ;
        RECT 725.568 38.544 725.760 38.568 ;
    END
  END rx[65]
  PIN rx[66]
    DIRECTION INPUT ;
    USE SIGNAL ;
    PORT
      LAYER M4 ;
        RECT 725.568 39.120 725.760 39.144 ;
    END
  END rx[66]
  PIN rx[67]
    DIRECTION INPUT ;
    USE SIGNAL ;
    PORT
      LAYER M4 ;
        RECT 725.568 39.648 725.760 39.672 ;
    END
  END rx[67]
  PIN rx[68]
    DIRECTION INPUT ;
    USE SIGNAL ;
    PORT
      LAYER M4 ;
        RECT 725.568 40.224 725.760 40.248 ;
    END
  END rx[68]
  PIN rx[69]
    DIRECTION INPUT ;
    USE SIGNAL ;
    PORT
      LAYER M4 ;
        RECT 725.568 40.752 725.760 40.776 ;
    END
  END rx[69]
  PIN rx[70]
    DIRECTION INPUT ;
    USE SIGNAL ;
    PORT
      LAYER M4 ;
        RECT 725.568 41.328 725.760 41.352 ;
    END
  END rx[70]
  PIN rx[71]
    DIRECTION INPUT ;
    USE SIGNAL ;
    PORT
      LAYER M4 ;
        RECT 725.568 41.904 725.760 41.928 ;
    END
  END rx[71]
  PIN rx[72]
    DIRECTION INPUT ;
    USE SIGNAL ;
    PORT
      LAYER M4 ;
        RECT 725.568 42.432 725.760 42.456 ;
    END
  END rx[72]
  PIN rx[73]
    DIRECTION INPUT ;
    USE SIGNAL ;
    PORT
      LAYER M4 ;
        RECT 725.568 43.008 725.760 43.032 ;
    END
  END rx[73]
  PIN rx[74]
    DIRECTION INPUT ;
    USE SIGNAL ;
    PORT
      LAYER M4 ;
        RECT 725.568 43.536 725.760 43.560 ;
    END
  END rx[74]
  PIN rx[75]
    DIRECTION INPUT ;
    USE SIGNAL ;
    PORT
      LAYER M4 ;
        RECT 725.568 44.112 725.760 44.136 ;
    END
  END rx[75]
  PIN rx[76]
    DIRECTION INPUT ;
    USE SIGNAL ;
    PORT
      LAYER M4 ;
        RECT 725.568 44.640 725.760 44.664 ;
    END
  END rx[76]
  PIN rx[77]
    DIRECTION INPUT ;
    USE SIGNAL ;
    PORT
      LAYER M4 ;
        RECT 725.568 45.216 725.760 45.240 ;
    END
  END rx[77]
  PIN rx[78]
    DIRECTION INPUT ;
    USE SIGNAL ;
    PORT
      LAYER M4 ;
        RECT 725.568 45.792 725.760 45.816 ;
    END
  END rx[78]
  PIN rx[79]
    DIRECTION INPUT ;
    USE SIGNAL ;
    PORT
      LAYER M4 ;
        RECT 725.568 46.320 725.760 46.344 ;
    END
  END rx[79]
  PIN rx[80]
    DIRECTION INPUT ;
    USE SIGNAL ;
    PORT
      LAYER M4 ;
        RECT 725.568 46.896 725.760 46.920 ;
    END
  END rx[80]
  PIN rx[81]
    DIRECTION INPUT ;
    USE SIGNAL ;
    PORT
      LAYER M4 ;
        RECT 725.568 47.424 725.760 47.448 ;
    END
  END rx[81]
  PIN rx[82]
    DIRECTION INPUT ;
    USE SIGNAL ;
    PORT
      LAYER M4 ;
        RECT 725.568 48.000 725.760 48.024 ;
    END
  END rx[82]
  PIN rx[83]
    DIRECTION INPUT ;
    USE SIGNAL ;
    PORT
      LAYER M4 ;
        RECT 725.568 48.528 725.760 48.552 ;
    END
  END rx[83]
  PIN rx[84]
    DIRECTION INPUT ;
    USE SIGNAL ;
    PORT
      LAYER M4 ;
        RECT 725.568 49.104 725.760 49.128 ;
    END
  END rx[84]
  PIN rx[85]
    DIRECTION INPUT ;
    USE SIGNAL ;
    PORT
      LAYER M4 ;
        RECT 725.568 49.680 725.760 49.704 ;
    END
  END rx[85]
  PIN rx[86]
    DIRECTION INPUT ;
    USE SIGNAL ;
    PORT
      LAYER M4 ;
        RECT 725.568 50.208 725.760 50.232 ;
    END
  END rx[86]
  PIN rx[87]
    DIRECTION INPUT ;
    USE SIGNAL ;
    PORT
      LAYER M4 ;
        RECT 725.568 50.784 725.760 50.808 ;
    END
  END rx[87]
  PIN rx[88]
    DIRECTION INPUT ;
    USE SIGNAL ;
    PORT
      LAYER M4 ;
        RECT 725.568 51.312 725.760 51.336 ;
    END
  END rx[88]
  PIN rx[89]
    DIRECTION INPUT ;
    USE SIGNAL ;
    PORT
      LAYER M4 ;
        RECT 725.568 51.888 725.760 51.912 ;
    END
  END rx[89]
  PIN rx[90]
    DIRECTION INPUT ;
    USE SIGNAL ;
    PORT
      LAYER M4 ;
        RECT 725.568 52.464 725.760 52.488 ;
    END
  END rx[90]
  PIN rx[91]
    DIRECTION INPUT ;
    USE SIGNAL ;
    PORT
      LAYER M4 ;
        RECT 725.568 52.992 725.760 53.016 ;
    END
  END rx[91]
  PIN rx[92]
    DIRECTION INPUT ;
    USE SIGNAL ;
    PORT
      LAYER M4 ;
        RECT 725.568 53.568 725.760 53.592 ;
    END
  END rx[92]
  PIN rx[93]
    DIRECTION INPUT ;
    USE SIGNAL ;
    PORT
      LAYER M4 ;
        RECT 725.568 54.096 725.760 54.120 ;
    END
  END rx[93]
  PIN rx[94]
    DIRECTION INPUT ;
    USE SIGNAL ;
    PORT
      LAYER M4 ;
        RECT 725.568 54.672 725.760 54.696 ;
    END
  END rx[94]
  PIN rx[95]
    DIRECTION INPUT ;
    USE SIGNAL ;
    PORT
      LAYER M4 ;
        RECT 725.568 55.200 725.760 55.224 ;
    END
  END rx[95]
  PIN rx[96]
    DIRECTION INPUT ;
    USE SIGNAL ;
    PORT
      LAYER M4 ;
        RECT 725.568 55.776 725.760 55.800 ;
    END
  END rx[96]
  PIN rx[97]
    DIRECTION INPUT ;
    USE SIGNAL ;
    PORT
      LAYER M4 ;
        RECT 725.568 56.352 725.760 56.376 ;
    END
  END rx[97]
  PIN rx[98]
    DIRECTION INPUT ;
    USE SIGNAL ;
    PORT
      LAYER M4 ;
        RECT 725.568 56.880 725.760 56.904 ;
    END
  END rx[98]
  PIN rx[99]
    DIRECTION INPUT ;
    USE SIGNAL ;
    PORT
      LAYER M4 ;
        RECT 725.568 57.456 725.760 57.480 ;
    END
  END rx[99]
  PIN rx[100]
    DIRECTION INPUT ;
    USE SIGNAL ;
    PORT
      LAYER M4 ;
        RECT 725.568 57.984 725.760 58.008 ;
    END
  END rx[100]
  PIN rx[101]
    DIRECTION INPUT ;
    USE SIGNAL ;
    PORT
      LAYER M4 ;
        RECT 725.568 58.560 725.760 58.584 ;
    END
  END rx[101]
  PIN rx[102]
    DIRECTION INPUT ;
    USE SIGNAL ;
    PORT
      LAYER M4 ;
        RECT 725.568 59.088 725.760 59.112 ;
    END
  END rx[102]
  PIN rx[103]
    DIRECTION INPUT ;
    USE SIGNAL ;
    PORT
      LAYER M4 ;
        RECT 725.568 59.664 725.760 59.688 ;
    END
  END rx[103]
  PIN rx[104]
    DIRECTION INPUT ;
    USE SIGNAL ;
    PORT
      LAYER M4 ;
        RECT 725.568 60.240 725.760 60.264 ;
    END
  END rx[104]
  PIN rx[105]
    DIRECTION INPUT ;
    USE SIGNAL ;
    PORT
      LAYER M4 ;
        RECT 725.568 60.768 725.760 60.792 ;
    END
  END rx[105]
  PIN rx[106]
    DIRECTION INPUT ;
    USE SIGNAL ;
    PORT
      LAYER M4 ;
        RECT 725.568 61.344 725.760 61.368 ;
    END
  END rx[106]
  PIN rx[107]
    DIRECTION INPUT ;
    USE SIGNAL ;
    PORT
      LAYER M4 ;
        RECT 725.568 61.872 725.760 61.896 ;
    END
  END rx[107]
  PIN rx[108]
    DIRECTION INPUT ;
    USE SIGNAL ;
    PORT
      LAYER M4 ;
        RECT 725.568 62.448 725.760 62.472 ;
    END
  END rx[108]
  PIN rx[109]
    DIRECTION INPUT ;
    USE SIGNAL ;
    PORT
      LAYER M4 ;
        RECT 725.568 63.024 725.760 63.048 ;
    END
  END rx[109]
  PIN rx[110]
    DIRECTION INPUT ;
    USE SIGNAL ;
    PORT
      LAYER M4 ;
        RECT 725.568 63.552 725.760 63.576 ;
    END
  END rx[110]
  PIN rx[111]
    DIRECTION INPUT ;
    USE SIGNAL ;
    PORT
      LAYER M4 ;
        RECT 725.568 64.128 725.760 64.152 ;
    END
  END rx[111]
  PIN rx[112]
    DIRECTION INPUT ;
    USE SIGNAL ;
    PORT
      LAYER M4 ;
        RECT 725.568 64.656 725.760 64.680 ;
    END
  END rx[112]
  PIN rx[113]
    DIRECTION INPUT ;
    USE SIGNAL ;
    PORT
      LAYER M4 ;
        RECT 725.568 65.232 725.760 65.256 ;
    END
  END rx[113]
  PIN rx[114]
    DIRECTION INPUT ;
    USE SIGNAL ;
    PORT
      LAYER M4 ;
        RECT 725.568 65.760 725.760 65.784 ;
    END
  END rx[114]
  PIN rx[115]
    DIRECTION INPUT ;
    USE SIGNAL ;
    PORT
      LAYER M4 ;
        RECT 725.568 66.336 725.760 66.360 ;
    END
  END rx[115]
  PIN rx[116]
    DIRECTION INPUT ;
    USE SIGNAL ;
    PORT
      LAYER M4 ;
        RECT 725.568 66.912 725.760 66.936 ;
    END
  END rx[116]
  PIN rx[117]
    DIRECTION INPUT ;
    USE SIGNAL ;
    PORT
      LAYER M4 ;
        RECT 725.568 67.440 725.760 67.464 ;
    END
  END rx[117]
  PIN rx[118]
    DIRECTION INPUT ;
    USE SIGNAL ;
    PORT
      LAYER M4 ;
        RECT 725.568 68.016 725.760 68.040 ;
    END
  END rx[118]
  PIN rx[119]
    DIRECTION INPUT ;
    USE SIGNAL ;
    PORT
      LAYER M4 ;
        RECT 725.568 68.544 725.760 68.568 ;
    END
  END rx[119]
  PIN rx[120]
    DIRECTION INPUT ;
    USE SIGNAL ;
    PORT
      LAYER M4 ;
        RECT 725.568 69.120 725.760 69.144 ;
    END
  END rx[120]
  PIN rx[121]
    DIRECTION INPUT ;
    USE SIGNAL ;
    PORT
      LAYER M4 ;
        RECT 725.568 69.648 725.760 69.672 ;
    END
  END rx[121]
  PIN rx[122]
    DIRECTION INPUT ;
    USE SIGNAL ;
    PORT
      LAYER M4 ;
        RECT 725.568 70.224 725.760 70.248 ;
    END
  END rx[122]
  PIN rx[123]
    DIRECTION INPUT ;
    USE SIGNAL ;
    PORT
      LAYER M4 ;
        RECT 725.568 70.800 725.760 70.824 ;
    END
  END rx[123]
  PIN rx[124]
    DIRECTION INPUT ;
    USE SIGNAL ;
    PORT
      LAYER M4 ;
        RECT 725.568 71.328 725.760 71.352 ;
    END
  END rx[124]
  PIN rx[125]
    DIRECTION INPUT ;
    USE SIGNAL ;
    PORT
      LAYER M4 ;
        RECT 725.568 71.904 725.760 71.928 ;
    END
  END rx[125]
  PIN rx[126]
    DIRECTION INPUT ;
    USE SIGNAL ;
    PORT
      LAYER M4 ;
        RECT 725.568 72.432 725.760 72.456 ;
    END
  END rx[126]
  PIN rx[127]
    DIRECTION INPUT ;
    USE SIGNAL ;
    PORT
      LAYER M4 ;
        RECT 725.568 73.008 725.760 73.032 ;
    END
  END rx[127]
  PIN rx[128]
    DIRECTION INPUT ;
    USE SIGNAL ;
    PORT
      LAYER M4 ;
        RECT 725.568 73.536 725.760 73.560 ;
    END
  END rx[128]
  PIN rx[129]
    DIRECTION INPUT ;
    USE SIGNAL ;
    PORT
      LAYER M4 ;
        RECT 725.568 74.112 725.760 74.136 ;
    END
  END rx[129]
  PIN rx[130]
    DIRECTION INPUT ;
    USE SIGNAL ;
    PORT
      LAYER M4 ;
        RECT 725.568 74.688 725.760 74.712 ;
    END
  END rx[130]
  PIN rx[131]
    DIRECTION INPUT ;
    USE SIGNAL ;
    PORT
      LAYER M4 ;
        RECT 725.568 75.216 725.760 75.240 ;
    END
  END rx[131]
  PIN rx[132]
    DIRECTION INPUT ;
    USE SIGNAL ;
    PORT
      LAYER M4 ;
        RECT 725.568 75.792 725.760 75.816 ;
    END
  END rx[132]
  PIN rx[133]
    DIRECTION INPUT ;
    USE SIGNAL ;
    PORT
      LAYER M4 ;
        RECT 725.568 76.320 725.760 76.344 ;
    END
  END rx[133]
  PIN rx[134]
    DIRECTION INPUT ;
    USE SIGNAL ;
    PORT
      LAYER M4 ;
        RECT 725.568 76.896 725.760 76.920 ;
    END
  END rx[134]
  PIN rx[135]
    DIRECTION INPUT ;
    USE SIGNAL ;
    PORT
      LAYER M4 ;
        RECT 725.568 77.472 725.760 77.496 ;
    END
  END rx[135]
  PIN rx[136]
    DIRECTION INPUT ;
    USE SIGNAL ;
    PORT
      LAYER M4 ;
        RECT 725.568 78.000 725.760 78.024 ;
    END
  END rx[136]
  PIN rx[137]
    DIRECTION INPUT ;
    USE SIGNAL ;
    PORT
      LAYER M4 ;
        RECT 725.568 78.576 725.760 78.600 ;
    END
  END rx[137]
  PIN rx[138]
    DIRECTION INPUT ;
    USE SIGNAL ;
    PORT
      LAYER M4 ;
        RECT 725.568 79.104 725.760 79.128 ;
    END
  END rx[138]
  PIN rx[139]
    DIRECTION INPUT ;
    USE SIGNAL ;
    PORT
      LAYER M4 ;
        RECT 725.568 79.680 725.760 79.704 ;
    END
  END rx[139]
  PIN rx[140]
    DIRECTION INPUT ;
    USE SIGNAL ;
    PORT
      LAYER M4 ;
        RECT 725.568 80.208 725.760 80.232 ;
    END
  END rx[140]
  PIN rx[141]
    DIRECTION INPUT ;
    USE SIGNAL ;
    PORT
      LAYER M4 ;
        RECT 725.568 80.784 725.760 80.808 ;
    END
  END rx[141]
  PIN rx[142]
    DIRECTION INPUT ;
    USE SIGNAL ;
    PORT
      LAYER M4 ;
        RECT 725.568 81.360 725.760 81.384 ;
    END
  END rx[142]
  PIN rx[143]
    DIRECTION INPUT ;
    USE SIGNAL ;
    PORT
      LAYER M4 ;
        RECT 725.568 81.888 725.760 81.912 ;
    END
  END rx[143]
  PIN rx[144]
    DIRECTION INPUT ;
    USE SIGNAL ;
    PORT
      LAYER M4 ;
        RECT 725.568 82.464 725.760 82.488 ;
    END
  END rx[144]
  PIN rx[145]
    DIRECTION INPUT ;
    USE SIGNAL ;
    PORT
      LAYER M4 ;
        RECT 725.568 82.992 725.760 83.016 ;
    END
  END rx[145]
  PIN rx[146]
    DIRECTION INPUT ;
    USE SIGNAL ;
    PORT
      LAYER M4 ;
        RECT 725.568 83.568 725.760 83.592 ;
    END
  END rx[146]
  PIN rx[147]
    DIRECTION INPUT ;
    USE SIGNAL ;
    PORT
      LAYER M4 ;
        RECT 725.568 84.096 725.760 84.120 ;
    END
  END rx[147]
  PIN rx[148]
    DIRECTION INPUT ;
    USE SIGNAL ;
    PORT
      LAYER M4 ;
        RECT 725.568 84.672 725.760 84.696 ;
    END
  END rx[148]
  PIN rx[149]
    DIRECTION INPUT ;
    USE SIGNAL ;
    PORT
      LAYER M4 ;
        RECT 725.568 85.248 725.760 85.272 ;
    END
  END rx[149]
  PIN rx[150]
    DIRECTION INPUT ;
    USE SIGNAL ;
    PORT
      LAYER M4 ;
        RECT 725.568 85.776 725.760 85.800 ;
    END
  END rx[150]
  PIN rx[151]
    DIRECTION INPUT ;
    USE SIGNAL ;
    PORT
      LAYER M4 ;
        RECT 725.568 86.352 725.760 86.376 ;
    END
  END rx[151]
  PIN rx[152]
    DIRECTION INPUT ;
    USE SIGNAL ;
    PORT
      LAYER M4 ;
        RECT 725.568 86.880 725.760 86.904 ;
    END
  END rx[152]
  PIN rx[153]
    DIRECTION INPUT ;
    USE SIGNAL ;
    PORT
      LAYER M4 ;
        RECT 725.568 87.456 725.760 87.480 ;
    END
  END rx[153]
  PIN rx[154]
    DIRECTION INPUT ;
    USE SIGNAL ;
    PORT
      LAYER M4 ;
        RECT 725.568 87.984 725.760 88.008 ;
    END
  END rx[154]
  PIN rx[155]
    DIRECTION INPUT ;
    USE SIGNAL ;
    PORT
      LAYER M4 ;
        RECT 725.568 88.560 725.760 88.584 ;
    END
  END rx[155]
  PIN rx[156]
    DIRECTION INPUT ;
    USE SIGNAL ;
    PORT
      LAYER M4 ;
        RECT 725.568 89.136 725.760 89.160 ;
    END
  END rx[156]
  PIN rx[157]
    DIRECTION INPUT ;
    USE SIGNAL ;
    PORT
      LAYER M4 ;
        RECT 725.568 89.664 725.760 89.688 ;
    END
  END rx[157]
  PIN rx[158]
    DIRECTION INPUT ;
    USE SIGNAL ;
    PORT
      LAYER M4 ;
        RECT 725.568 90.240 725.760 90.264 ;
    END
  END rx[158]
  PIN rx[159]
    DIRECTION INPUT ;
    USE SIGNAL ;
    PORT
      LAYER M4 ;
        RECT 725.568 90.768 725.760 90.792 ;
    END
  END rx[159]
  PIN rx[160]
    DIRECTION INPUT ;
    USE SIGNAL ;
    PORT
      LAYER M4 ;
        RECT 725.568 91.344 725.760 91.368 ;
    END
  END rx[160]
  PIN rx[161]
    DIRECTION INPUT ;
    USE SIGNAL ;
    PORT
      LAYER M4 ;
        RECT 725.568 91.920 725.760 91.944 ;
    END
  END rx[161]
  PIN rx[162]
    DIRECTION INPUT ;
    USE SIGNAL ;
    PORT
      LAYER M4 ;
        RECT 725.568 92.448 725.760 92.472 ;
    END
  END rx[162]
  PIN rx[163]
    DIRECTION INPUT ;
    USE SIGNAL ;
    PORT
      LAYER M4 ;
        RECT 725.568 93.024 725.760 93.048 ;
    END
  END rx[163]
  PIN rx[164]
    DIRECTION INPUT ;
    USE SIGNAL ;
    PORT
      LAYER M4 ;
        RECT 725.568 93.552 725.760 93.576 ;
    END
  END rx[164]
  PIN rx[165]
    DIRECTION INPUT ;
    USE SIGNAL ;
    PORT
      LAYER M4 ;
        RECT 725.568 94.128 725.760 94.152 ;
    END
  END rx[165]
  PIN rx[166]
    DIRECTION INPUT ;
    USE SIGNAL ;
    PORT
      LAYER M4 ;
        RECT 725.568 94.656 725.760 94.680 ;
    END
  END rx[166]
  PIN rx[167]
    DIRECTION INPUT ;
    USE SIGNAL ;
    PORT
      LAYER M4 ;
        RECT 725.568 95.232 725.760 95.256 ;
    END
  END rx[167]
  PIN rx[168]
    DIRECTION INPUT ;
    USE SIGNAL ;
    PORT
      LAYER M4 ;
        RECT 725.568 95.808 725.760 95.832 ;
    END
  END rx[168]
  PIN rx[169]
    DIRECTION INPUT ;
    USE SIGNAL ;
    PORT
      LAYER M4 ;
        RECT 725.568 96.336 725.760 96.360 ;
    END
  END rx[169]
  PIN rx[170]
    DIRECTION INPUT ;
    USE SIGNAL ;
    PORT
      LAYER M4 ;
        RECT 725.568 96.912 725.760 96.936 ;
    END
  END rx[170]
  PIN rx[171]
    DIRECTION INPUT ;
    USE SIGNAL ;
    PORT
      LAYER M4 ;
        RECT 725.568 97.440 725.760 97.464 ;
    END
  END rx[171]
  PIN rx[172]
    DIRECTION INPUT ;
    USE SIGNAL ;
    PORT
      LAYER M4 ;
        RECT 725.568 98.016 725.760 98.040 ;
    END
  END rx[172]
  PIN rx[173]
    DIRECTION INPUT ;
    USE SIGNAL ;
    PORT
      LAYER M4 ;
        RECT 725.568 98.544 725.760 98.568 ;
    END
  END rx[173]
  PIN rx[174]
    DIRECTION INPUT ;
    USE SIGNAL ;
    PORT
      LAYER M4 ;
        RECT 725.568 99.120 725.760 99.144 ;
    END
  END rx[174]
  PIN rx[175]
    DIRECTION INPUT ;
    USE SIGNAL ;
    PORT
      LAYER M4 ;
        RECT 725.568 99.696 725.760 99.720 ;
    END
  END rx[175]
  PIN rx[176]
    DIRECTION INPUT ;
    USE SIGNAL ;
    PORT
      LAYER M4 ;
        RECT 725.568 100.224 725.760 100.248 ;
    END
  END rx[176]
  PIN rx[177]
    DIRECTION INPUT ;
    USE SIGNAL ;
    PORT
      LAYER M4 ;
        RECT 725.568 100.800 725.760 100.824 ;
    END
  END rx[177]
  PIN rx[178]
    DIRECTION INPUT ;
    USE SIGNAL ;
    PORT
      LAYER M4 ;
        RECT 725.568 101.328 725.760 101.352 ;
    END
  END rx[178]
  PIN rx[179]
    DIRECTION INPUT ;
    USE SIGNAL ;
    PORT
      LAYER M4 ;
        RECT 725.568 101.904 725.760 101.928 ;
    END
  END rx[179]
  PIN rx[180]
    DIRECTION INPUT ;
    USE SIGNAL ;
    PORT
      LAYER M4 ;
        RECT 725.568 102.480 725.760 102.504 ;
    END
  END rx[180]
  PIN rx[181]
    DIRECTION INPUT ;
    USE SIGNAL ;
    PORT
      LAYER M4 ;
        RECT 725.568 103.008 725.760 103.032 ;
    END
  END rx[181]
  PIN rx[182]
    DIRECTION INPUT ;
    USE SIGNAL ;
    PORT
      LAYER M4 ;
        RECT 725.568 103.584 725.760 103.608 ;
    END
  END rx[182]
  PIN rx[183]
    DIRECTION INPUT ;
    USE SIGNAL ;
    PORT
      LAYER M4 ;
        RECT 725.568 104.112 725.760 104.136 ;
    END
  END rx[183]
  PIN rx[184]
    DIRECTION INPUT ;
    USE SIGNAL ;
    PORT
      LAYER M4 ;
        RECT 725.568 104.688 725.760 104.712 ;
    END
  END rx[184]
  PIN rx[185]
    DIRECTION INPUT ;
    USE SIGNAL ;
    PORT
      LAYER M4 ;
        RECT 725.568 105.216 725.760 105.240 ;
    END
  END rx[185]
  PIN rx[186]
    DIRECTION INPUT ;
    USE SIGNAL ;
    PORT
      LAYER M4 ;
        RECT 725.568 105.792 725.760 105.816 ;
    END
  END rx[186]
  PIN rx[187]
    DIRECTION INPUT ;
    USE SIGNAL ;
    PORT
      LAYER M4 ;
        RECT 725.568 106.368 725.760 106.392 ;
    END
  END rx[187]
  PIN rx[188]
    DIRECTION INPUT ;
    USE SIGNAL ;
    PORT
      LAYER M4 ;
        RECT 725.568 106.896 725.760 106.920 ;
    END
  END rx[188]
  PIN rx[189]
    DIRECTION INPUT ;
    USE SIGNAL ;
    PORT
      LAYER M4 ;
        RECT 725.568 107.472 725.760 107.496 ;
    END
  END rx[189]
  PIN rx[190]
    DIRECTION INPUT ;
    USE SIGNAL ;
    PORT
      LAYER M4 ;
        RECT 725.568 108.000 725.760 108.024 ;
    END
  END rx[190]
  PIN rx[191]
    DIRECTION INPUT ;
    USE SIGNAL ;
    PORT
      LAYER M4 ;
        RECT 725.568 108.576 725.760 108.600 ;
    END
  END rx[191]
  PIN rx[192]
    DIRECTION INPUT ;
    USE SIGNAL ;
    PORT
      LAYER M4 ;
        RECT 725.568 109.104 725.760 109.128 ;
    END
  END rx[192]
  PIN rx[193]
    DIRECTION INPUT ;
    USE SIGNAL ;
    PORT
      LAYER M4 ;
        RECT 725.568 109.680 725.760 109.704 ;
    END
  END rx[193]
  PIN rx[194]
    DIRECTION INPUT ;
    USE SIGNAL ;
    PORT
      LAYER M4 ;
        RECT 725.568 110.256 725.760 110.280 ;
    END
  END rx[194]
  PIN rx[195]
    DIRECTION INPUT ;
    USE SIGNAL ;
    PORT
      LAYER M4 ;
        RECT 725.568 110.784 725.760 110.808 ;
    END
  END rx[195]
  PIN rx[196]
    DIRECTION INPUT ;
    USE SIGNAL ;
    PORT
      LAYER M4 ;
        RECT 725.568 111.360 725.760 111.384 ;
    END
  END rx[196]
  PIN rx[197]
    DIRECTION INPUT ;
    USE SIGNAL ;
    PORT
      LAYER M4 ;
        RECT 725.568 111.888 725.760 111.912 ;
    END
  END rx[197]
  PIN rx[198]
    DIRECTION INPUT ;
    USE SIGNAL ;
    PORT
      LAYER M4 ;
        RECT 725.568 112.464 725.760 112.488 ;
    END
  END rx[198]
  PIN rx[199]
    DIRECTION INPUT ;
    USE SIGNAL ;
    PORT
      LAYER M4 ;
        RECT 725.568 112.992 725.760 113.016 ;
    END
  END rx[199]
  PIN rx[200]
    DIRECTION INPUT ;
    USE SIGNAL ;
    PORT
      LAYER M4 ;
        RECT 725.568 113.568 725.760 113.592 ;
    END
  END rx[200]
  PIN rx[201]
    DIRECTION INPUT ;
    USE SIGNAL ;
    PORT
      LAYER M4 ;
        RECT 725.568 114.144 725.760 114.168 ;
    END
  END rx[201]
  PIN rx[202]
    DIRECTION INPUT ;
    USE SIGNAL ;
    PORT
      LAYER M4 ;
        RECT 725.568 114.672 725.760 114.696 ;
    END
  END rx[202]
  PIN rx[203]
    DIRECTION INPUT ;
    USE SIGNAL ;
    PORT
      LAYER M4 ;
        RECT 725.568 115.248 725.760 115.272 ;
    END
  END rx[203]
  PIN rx[204]
    DIRECTION INPUT ;
    USE SIGNAL ;
    PORT
      LAYER M4 ;
        RECT 725.568 115.776 725.760 115.800 ;
    END
  END rx[204]
  PIN rx[205]
    DIRECTION INPUT ;
    USE SIGNAL ;
    PORT
      LAYER M4 ;
        RECT 725.568 116.352 725.760 116.376 ;
    END
  END rx[205]
  PIN rx[206]
    DIRECTION INPUT ;
    USE SIGNAL ;
    PORT
      LAYER M4 ;
        RECT 725.568 116.928 725.760 116.952 ;
    END
  END rx[206]
  PIN rx[207]
    DIRECTION INPUT ;
    USE SIGNAL ;
    PORT
      LAYER M4 ;
        RECT 725.568 117.456 725.760 117.480 ;
    END
  END rx[207]
  PIN rx[208]
    DIRECTION INPUT ;
    USE SIGNAL ;
    PORT
      LAYER M4 ;
        RECT 725.568 118.032 725.760 118.056 ;
    END
  END rx[208]
  PIN rx[209]
    DIRECTION INPUT ;
    USE SIGNAL ;
    PORT
      LAYER M4 ;
        RECT 725.568 118.560 725.760 118.584 ;
    END
  END rx[209]
  PIN rx[210]
    DIRECTION INPUT ;
    USE SIGNAL ;
    PORT
      LAYER M4 ;
        RECT 725.568 119.136 725.760 119.160 ;
    END
  END rx[210]
  PIN rx[211]
    DIRECTION INPUT ;
    USE SIGNAL ;
    PORT
      LAYER M4 ;
        RECT 725.568 119.664 725.760 119.688 ;
    END
  END rx[211]
  PIN rx[212]
    DIRECTION INPUT ;
    USE SIGNAL ;
    PORT
      LAYER M4 ;
        RECT 725.568 120.240 725.760 120.264 ;
    END
  END rx[212]
  PIN rx[213]
    DIRECTION INPUT ;
    USE SIGNAL ;
    PORT
      LAYER M4 ;
        RECT 725.568 120.816 725.760 120.840 ;
    END
  END rx[213]
  PIN rx[214]
    DIRECTION INPUT ;
    USE SIGNAL ;
    PORT
      LAYER M4 ;
        RECT 725.568 121.344 725.760 121.368 ;
    END
  END rx[214]
  PIN rx[215]
    DIRECTION INPUT ;
    USE SIGNAL ;
    PORT
      LAYER M4 ;
        RECT 725.568 121.920 725.760 121.944 ;
    END
  END rx[215]
  PIN rx[216]
    DIRECTION INPUT ;
    USE SIGNAL ;
    PORT
      LAYER M4 ;
        RECT 725.568 122.448 725.760 122.472 ;
    END
  END rx[216]
  PIN rx[217]
    DIRECTION INPUT ;
    USE SIGNAL ;
    PORT
      LAYER M4 ;
        RECT 725.568 123.024 725.760 123.048 ;
    END
  END rx[217]
  PIN rx[218]
    DIRECTION INPUT ;
    USE SIGNAL ;
    PORT
      LAYER M4 ;
        RECT 725.568 123.552 725.760 123.576 ;
    END
  END rx[218]
  PIN rx[219]
    DIRECTION INPUT ;
    USE SIGNAL ;
    PORT
      LAYER M4 ;
        RECT 725.568 124.128 725.760 124.152 ;
    END
  END rx[219]
  PIN rx[220]
    DIRECTION INPUT ;
    USE SIGNAL ;
    PORT
      LAYER M4 ;
        RECT 725.568 124.704 725.760 124.728 ;
    END
  END rx[220]
  PIN rx[221]
    DIRECTION INPUT ;
    USE SIGNAL ;
    PORT
      LAYER M4 ;
        RECT 725.568 125.232 725.760 125.256 ;
    END
  END rx[221]
  PIN rx[222]
    DIRECTION INPUT ;
    USE SIGNAL ;
    PORT
      LAYER M4 ;
        RECT 725.568 125.808 725.760 125.832 ;
    END
  END rx[222]
  PIN rx[223]
    DIRECTION INPUT ;
    USE SIGNAL ;
    PORT
      LAYER M4 ;
        RECT 725.568 126.336 725.760 126.360 ;
    END
  END rx[223]
  PIN rx[224]
    DIRECTION INPUT ;
    USE SIGNAL ;
    PORT
      LAYER M4 ;
        RECT 725.568 126.912 725.760 126.936 ;
    END
  END rx[224]
  PIN rx[225]
    DIRECTION INPUT ;
    USE SIGNAL ;
    PORT
      LAYER M4 ;
        RECT 725.568 127.488 725.760 127.512 ;
    END
  END rx[225]
  PIN rx[226]
    DIRECTION INPUT ;
    USE SIGNAL ;
    PORT
      LAYER M4 ;
        RECT 725.568 128.016 725.760 128.040 ;
    END
  END rx[226]
  PIN rx[227]
    DIRECTION INPUT ;
    USE SIGNAL ;
    PORT
      LAYER M4 ;
        RECT 725.568 128.592 725.760 128.616 ;
    END
  END rx[227]
  PIN rx[228]
    DIRECTION INPUT ;
    USE SIGNAL ;
    PORT
      LAYER M4 ;
        RECT 725.568 129.120 725.760 129.144 ;
    END
  END rx[228]
  PIN rx[229]
    DIRECTION INPUT ;
    USE SIGNAL ;
    PORT
      LAYER M4 ;
        RECT 725.568 129.696 725.760 129.720 ;
    END
  END rx[229]
  PIN rx[230]
    DIRECTION INPUT ;
    USE SIGNAL ;
    PORT
      LAYER M4 ;
        RECT 725.568 130.224 725.760 130.248 ;
    END
  END rx[230]
  PIN rx[231]
    DIRECTION INPUT ;
    USE SIGNAL ;
    PORT
      LAYER M4 ;
        RECT 725.568 130.800 725.760 130.824 ;
    END
  END rx[231]
  PIN rx[232]
    DIRECTION INPUT ;
    USE SIGNAL ;
    PORT
      LAYER M4 ;
        RECT 725.568 131.376 725.760 131.400 ;
    END
  END rx[232]
  PIN rx[233]
    DIRECTION INPUT ;
    USE SIGNAL ;
    PORT
      LAYER M4 ;
        RECT 725.568 131.904 725.760 131.928 ;
    END
  END rx[233]
  PIN rx[234]
    DIRECTION INPUT ;
    USE SIGNAL ;
    PORT
      LAYER M4 ;
        RECT 725.568 132.480 725.760 132.504 ;
    END
  END rx[234]
  PIN rx[235]
    DIRECTION INPUT ;
    USE SIGNAL ;
    PORT
      LAYER M4 ;
        RECT 725.568 133.008 725.760 133.032 ;
    END
  END rx[235]
  PIN rx[236]
    DIRECTION INPUT ;
    USE SIGNAL ;
    PORT
      LAYER M4 ;
        RECT 725.568 133.584 725.760 133.608 ;
    END
  END rx[236]
  PIN rx[237]
    DIRECTION INPUT ;
    USE SIGNAL ;
    PORT
      LAYER M4 ;
        RECT 725.568 134.112 725.760 134.136 ;
    END
  END rx[237]
  PIN rx[238]
    DIRECTION INPUT ;
    USE SIGNAL ;
    PORT
      LAYER M4 ;
        RECT 725.568 134.688 725.760 134.712 ;
    END
  END rx[238]
  PIN rx[239]
    DIRECTION INPUT ;
    USE SIGNAL ;
    PORT
      LAYER M4 ;
        RECT 725.568 135.264 725.760 135.288 ;
    END
  END rx[239]
  PIN rx[240]
    DIRECTION INPUT ;
    USE SIGNAL ;
    PORT
      LAYER M4 ;
        RECT 725.568 135.792 725.760 135.816 ;
    END
  END rx[240]
  PIN rx[241]
    DIRECTION INPUT ;
    USE SIGNAL ;
    PORT
      LAYER M4 ;
        RECT 725.568 136.368 725.760 136.392 ;
    END
  END rx[241]
  PIN rx[242]
    DIRECTION INPUT ;
    USE SIGNAL ;
    PORT
      LAYER M4 ;
        RECT 725.568 136.896 725.760 136.920 ;
    END
  END rx[242]
  PIN rx[243]
    DIRECTION INPUT ;
    USE SIGNAL ;
    PORT
      LAYER M4 ;
        RECT 725.568 137.472 725.760 137.496 ;
    END
  END rx[243]
  PIN rx[244]
    DIRECTION INPUT ;
    USE SIGNAL ;
    PORT
      LAYER M4 ;
        RECT 725.568 138.000 725.760 138.024 ;
    END
  END rx[244]
  PIN rx[245]
    DIRECTION INPUT ;
    USE SIGNAL ;
    PORT
      LAYER M4 ;
        RECT 725.568 138.576 725.760 138.600 ;
    END
  END rx[245]
  PIN rx[246]
    DIRECTION INPUT ;
    USE SIGNAL ;
    PORT
      LAYER M4 ;
        RECT 725.568 139.152 725.760 139.176 ;
    END
  END rx[246]
  PIN rx[247]
    DIRECTION INPUT ;
    USE SIGNAL ;
    PORT
      LAYER M4 ;
        RECT 725.568 139.680 725.760 139.704 ;
    END
  END rx[247]
  PIN rx[248]
    DIRECTION INPUT ;
    USE SIGNAL ;
    PORT
      LAYER M4 ;
        RECT 725.568 140.256 725.760 140.280 ;
    END
  END rx[248]
  PIN rx[249]
    DIRECTION INPUT ;
    USE SIGNAL ;
    PORT
      LAYER M4 ;
        RECT 725.568 140.784 725.760 140.808 ;
    END
  END rx[249]
  PIN rx[250]
    DIRECTION INPUT ;
    USE SIGNAL ;
    PORT
      LAYER M4 ;
        RECT 725.568 141.360 725.760 141.384 ;
    END
  END rx[250]
  PIN rx[251]
    DIRECTION INPUT ;
    USE SIGNAL ;
    PORT
      LAYER M4 ;
        RECT 725.568 141.936 725.760 141.960 ;
    END
  END rx[251]
  PIN rx[252]
    DIRECTION INPUT ;
    USE SIGNAL ;
    PORT
      LAYER M4 ;
        RECT 725.568 142.464 725.760 142.488 ;
    END
  END rx[252]
  PIN rx[253]
    DIRECTION INPUT ;
    USE SIGNAL ;
    PORT
      LAYER M4 ;
        RECT 725.568 143.040 725.760 143.064 ;
    END
  END rx[253]
  PIN rx[254]
    DIRECTION INPUT ;
    USE SIGNAL ;
    PORT
      LAYER M4 ;
        RECT 725.568 143.568 725.760 143.592 ;
    END
  END rx[254]
  PIN rx[255]
    DIRECTION INPUT ;
    USE SIGNAL ;
    PORT
      LAYER M4 ;
        RECT 725.568 144.144 725.760 144.168 ;
    END
  END rx[255]
  PIN rx[256]
    DIRECTION INPUT ;
    USE SIGNAL ;
    PORT
      LAYER M4 ;
        RECT 725.568 144.672 725.760 144.696 ;
    END
  END rx[256]
  PIN rx[257]
    DIRECTION INPUT ;
    USE SIGNAL ;
    PORT
      LAYER M4 ;
        RECT 725.568 145.248 725.760 145.272 ;
    END
  END rx[257]
  PIN rx[258]
    DIRECTION INPUT ;
    USE SIGNAL ;
    PORT
      LAYER M4 ;
        RECT 725.568 145.824 725.760 145.848 ;
    END
  END rx[258]
  PIN rx[259]
    DIRECTION INPUT ;
    USE SIGNAL ;
    PORT
      LAYER M4 ;
        RECT 725.568 146.352 725.760 146.376 ;
    END
  END rx[259]
  PIN rx[260]
    DIRECTION INPUT ;
    USE SIGNAL ;
    PORT
      LAYER M4 ;
        RECT 725.568 146.928 725.760 146.952 ;
    END
  END rx[260]
  PIN rx[261]
    DIRECTION INPUT ;
    USE SIGNAL ;
    PORT
      LAYER M4 ;
        RECT 725.568 147.456 725.760 147.480 ;
    END
  END rx[261]
  PIN rx[262]
    DIRECTION INPUT ;
    USE SIGNAL ;
    PORT
      LAYER M4 ;
        RECT 725.568 148.032 725.760 148.056 ;
    END
  END rx[262]
  PIN rx[263]
    DIRECTION INPUT ;
    USE SIGNAL ;
    PORT
      LAYER M4 ;
        RECT 725.568 148.560 725.760 148.584 ;
    END
  END rx[263]
  PIN rx[264]
    DIRECTION INPUT ;
    USE SIGNAL ;
    PORT
      LAYER M4 ;
        RECT 725.568 149.136 725.760 149.160 ;
    END
  END rx[264]
  PIN rx[265]
    DIRECTION INPUT ;
    USE SIGNAL ;
    PORT
      LAYER M4 ;
        RECT 725.568 149.712 725.760 149.736 ;
    END
  END rx[265]
  PIN rx[266]
    DIRECTION INPUT ;
    USE SIGNAL ;
    PORT
      LAYER M4 ;
        RECT 725.568 150.240 725.760 150.264 ;
    END
  END rx[266]
  PIN rx[267]
    DIRECTION INPUT ;
    USE SIGNAL ;
    PORT
      LAYER M4 ;
        RECT 725.568 150.816 725.760 150.840 ;
    END
  END rx[267]
  PIN rx[268]
    DIRECTION INPUT ;
    USE SIGNAL ;
    PORT
      LAYER M4 ;
        RECT 725.568 151.344 725.760 151.368 ;
    END
  END rx[268]
  PIN rx[269]
    DIRECTION INPUT ;
    USE SIGNAL ;
    PORT
      LAYER M4 ;
        RECT 725.568 151.920 725.760 151.944 ;
    END
  END rx[269]
  PIN rx[270]
    DIRECTION INPUT ;
    USE SIGNAL ;
    PORT
      LAYER M4 ;
        RECT 725.568 152.496 725.760 152.520 ;
    END
  END rx[270]
  PIN rx[271]
    DIRECTION INPUT ;
    USE SIGNAL ;
    PORT
      LAYER M4 ;
        RECT 725.568 153.024 725.760 153.048 ;
    END
  END rx[271]
  PIN rx[272]
    DIRECTION INPUT ;
    USE SIGNAL ;
    PORT
      LAYER M4 ;
        RECT 725.568 153.600 725.760 153.624 ;
    END
  END rx[272]
  PIN rx[273]
    DIRECTION INPUT ;
    USE SIGNAL ;
    PORT
      LAYER M4 ;
        RECT 725.568 154.128 725.760 154.152 ;
    END
  END rx[273]
  PIN rx[274]
    DIRECTION INPUT ;
    USE SIGNAL ;
    PORT
      LAYER M4 ;
        RECT 725.568 154.704 725.760 154.728 ;
    END
  END rx[274]
  PIN rx[275]
    DIRECTION INPUT ;
    USE SIGNAL ;
    PORT
      LAYER M4 ;
        RECT 725.568 155.232 725.760 155.256 ;
    END
  END rx[275]
  PIN rx[276]
    DIRECTION INPUT ;
    USE SIGNAL ;
    PORT
      LAYER M4 ;
        RECT 725.568 155.808 725.760 155.832 ;
    END
  END rx[276]
  PIN rx[277]
    DIRECTION INPUT ;
    USE SIGNAL ;
    PORT
      LAYER M4 ;
        RECT 725.568 156.384 725.760 156.408 ;
    END
  END rx[277]
  PIN rx[278]
    DIRECTION INPUT ;
    USE SIGNAL ;
    PORT
      LAYER M4 ;
        RECT 725.568 156.912 725.760 156.936 ;
    END
  END rx[278]
  PIN rx[279]
    DIRECTION INPUT ;
    USE SIGNAL ;
    PORT
      LAYER M4 ;
        RECT 725.568 157.488 725.760 157.512 ;
    END
  END rx[279]
  PIN rx[280]
    DIRECTION INPUT ;
    USE SIGNAL ;
    PORT
      LAYER M4 ;
        RECT 725.568 158.016 725.760 158.040 ;
    END
  END rx[280]
  PIN rx[281]
    DIRECTION INPUT ;
    USE SIGNAL ;
    PORT
      LAYER M4 ;
        RECT 725.568 158.592 725.760 158.616 ;
    END
  END rx[281]
  PIN rx[282]
    DIRECTION INPUT ;
    USE SIGNAL ;
    PORT
      LAYER M4 ;
        RECT 725.568 159.120 725.760 159.144 ;
    END
  END rx[282]
  PIN rx[283]
    DIRECTION INPUT ;
    USE SIGNAL ;
    PORT
      LAYER M4 ;
        RECT 725.568 159.696 725.760 159.720 ;
    END
  END rx[283]
  PIN rx[284]
    DIRECTION INPUT ;
    USE SIGNAL ;
    PORT
      LAYER M4 ;
        RECT 725.568 160.272 725.760 160.296 ;
    END
  END rx[284]
  PIN rx[285]
    DIRECTION INPUT ;
    USE SIGNAL ;
    PORT
      LAYER M4 ;
        RECT 725.568 160.800 725.760 160.824 ;
    END
  END rx[285]
  PIN rx[286]
    DIRECTION INPUT ;
    USE SIGNAL ;
    PORT
      LAYER M4 ;
        RECT 725.568 161.376 725.760 161.400 ;
    END
  END rx[286]
  PIN rx[287]
    DIRECTION INPUT ;
    USE SIGNAL ;
    PORT
      LAYER M4 ;
        RECT 725.568 161.904 725.760 161.928 ;
    END
  END rx[287]
  PIN rx[288]
    DIRECTION INPUT ;
    USE SIGNAL ;
    PORT
      LAYER M4 ;
        RECT 725.568 162.480 725.760 162.504 ;
    END
  END rx[288]
  PIN rx[289]
    DIRECTION INPUT ;
    USE SIGNAL ;
    PORT
      LAYER M4 ;
        RECT 725.568 163.008 725.760 163.032 ;
    END
  END rx[289]
  PIN rx[290]
    DIRECTION INPUT ;
    USE SIGNAL ;
    PORT
      LAYER M4 ;
        RECT 725.568 163.584 725.760 163.608 ;
    END
  END rx[290]
  PIN rx[291]
    DIRECTION INPUT ;
    USE SIGNAL ;
    PORT
      LAYER M4 ;
        RECT 725.568 164.160 725.760 164.184 ;
    END
  END rx[291]
  PIN rx[292]
    DIRECTION INPUT ;
    USE SIGNAL ;
    PORT
      LAYER M4 ;
        RECT 725.568 164.688 725.760 164.712 ;
    END
  END rx[292]
  PIN rx[293]
    DIRECTION INPUT ;
    USE SIGNAL ;
    PORT
      LAYER M4 ;
        RECT 725.568 165.264 725.760 165.288 ;
    END
  END rx[293]
  PIN rx[294]
    DIRECTION INPUT ;
    USE SIGNAL ;
    PORT
      LAYER M4 ;
        RECT 725.568 165.792 725.760 165.816 ;
    END
  END rx[294]
  PIN rx[295]
    DIRECTION INPUT ;
    USE SIGNAL ;
    PORT
      LAYER M4 ;
        RECT 725.568 166.368 725.760 166.392 ;
    END
  END rx[295]
  PIN rx[296]
    DIRECTION INPUT ;
    USE SIGNAL ;
    PORT
      LAYER M4 ;
        RECT 725.568 166.944 725.760 166.968 ;
    END
  END rx[296]
  PIN rx[297]
    DIRECTION INPUT ;
    USE SIGNAL ;
    PORT
      LAYER M4 ;
        RECT 725.568 167.472 725.760 167.496 ;
    END
  END rx[297]
  PIN rx[298]
    DIRECTION INPUT ;
    USE SIGNAL ;
    PORT
      LAYER M4 ;
        RECT 725.568 168.048 725.760 168.072 ;
    END
  END rx[298]
  PIN rx[299]
    DIRECTION INPUT ;
    USE SIGNAL ;
    PORT
      LAYER M4 ;
        RECT 725.568 168.576 725.760 168.600 ;
    END
  END rx[299]
  PIN rx[300]
    DIRECTION INPUT ;
    USE SIGNAL ;
    PORT
      LAYER M4 ;
        RECT 725.568 169.152 725.760 169.176 ;
    END
  END rx[300]
  PIN rx[301]
    DIRECTION INPUT ;
    USE SIGNAL ;
    PORT
      LAYER M4 ;
        RECT 725.568 169.680 725.760 169.704 ;
    END
  END rx[301]
  PIN rx[302]
    DIRECTION INPUT ;
    USE SIGNAL ;
    PORT
      LAYER M4 ;
        RECT 725.568 170.256 725.760 170.280 ;
    END
  END rx[302]
  PIN rx[303]
    DIRECTION INPUT ;
    USE SIGNAL ;
    PORT
      LAYER M4 ;
        RECT 725.568 170.832 725.760 170.856 ;
    END
  END rx[303]
  PIN rx[304]
    DIRECTION INPUT ;
    USE SIGNAL ;
    PORT
      LAYER M4 ;
        RECT 725.568 171.360 725.760 171.384 ;
    END
  END rx[304]
  PIN rx[305]
    DIRECTION INPUT ;
    USE SIGNAL ;
    PORT
      LAYER M4 ;
        RECT 725.568 171.936 725.760 171.960 ;
    END
  END rx[305]
  PIN rx[306]
    DIRECTION INPUT ;
    USE SIGNAL ;
    PORT
      LAYER M4 ;
        RECT 725.568 172.464 725.760 172.488 ;
    END
  END rx[306]
  PIN rx[307]
    DIRECTION INPUT ;
    USE SIGNAL ;
    PORT
      LAYER M4 ;
        RECT 725.568 173.040 725.760 173.064 ;
    END
  END rx[307]
  PIN rx[308]
    DIRECTION INPUT ;
    USE SIGNAL ;
    PORT
      LAYER M4 ;
        RECT 725.568 173.568 725.760 173.592 ;
    END
  END rx[308]
  PIN rx[309]
    DIRECTION INPUT ;
    USE SIGNAL ;
    PORT
      LAYER M4 ;
        RECT 725.568 174.144 725.760 174.168 ;
    END
  END rx[309]
  PIN rx[310]
    DIRECTION INPUT ;
    USE SIGNAL ;
    PORT
      LAYER M4 ;
        RECT 725.568 174.720 725.760 174.744 ;
    END
  END rx[310]
  PIN rx[311]
    DIRECTION INPUT ;
    USE SIGNAL ;
    PORT
      LAYER M4 ;
        RECT 725.568 175.248 725.760 175.272 ;
    END
  END rx[311]
  PIN rx[312]
    DIRECTION INPUT ;
    USE SIGNAL ;
    PORT
      LAYER M4 ;
        RECT 725.568 175.824 725.760 175.848 ;
    END
  END rx[312]
  PIN rx[313]
    DIRECTION INPUT ;
    USE SIGNAL ;
    PORT
      LAYER M4 ;
        RECT 725.568 176.352 725.760 176.376 ;
    END
  END rx[313]
  PIN rx[314]
    DIRECTION INPUT ;
    USE SIGNAL ;
    PORT
      LAYER M4 ;
        RECT 725.568 176.928 725.760 176.952 ;
    END
  END rx[314]
  PIN rx[315]
    DIRECTION INPUT ;
    USE SIGNAL ;
    PORT
      LAYER M4 ;
        RECT 725.568 177.504 725.760 177.528 ;
    END
  END rx[315]
  PIN rx[316]
    DIRECTION INPUT ;
    USE SIGNAL ;
    PORT
      LAYER M4 ;
        RECT 725.568 178.032 725.760 178.056 ;
    END
  END rx[316]
  PIN rx[317]
    DIRECTION INPUT ;
    USE SIGNAL ;
    PORT
      LAYER M4 ;
        RECT 725.568 178.608 725.760 178.632 ;
    END
  END rx[317]
  PIN rx[318]
    DIRECTION INPUT ;
    USE SIGNAL ;
    PORT
      LAYER M4 ;
        RECT 725.568 179.136 725.760 179.160 ;
    END
  END rx[318]
  PIN rx[319]
    DIRECTION INPUT ;
    USE SIGNAL ;
    PORT
      LAYER M4 ;
        RECT 725.568 179.712 725.760 179.736 ;
    END
  END rx[319]
  PIN rx[320]
    DIRECTION INPUT ;
    USE SIGNAL ;
    PORT
      LAYER M4 ;
        RECT 725.568 180.240 725.760 180.264 ;
    END
  END rx[320]
  PIN rx[321]
    DIRECTION INPUT ;
    USE SIGNAL ;
    PORT
      LAYER M4 ;
        RECT 725.568 180.816 725.760 180.840 ;
    END
  END rx[321]
  PIN rx[322]
    DIRECTION INPUT ;
    USE SIGNAL ;
    PORT
      LAYER M4 ;
        RECT 725.568 181.392 725.760 181.416 ;
    END
  END rx[322]
  PIN rx[323]
    DIRECTION INPUT ;
    USE SIGNAL ;
    PORT
      LAYER M4 ;
        RECT 725.568 181.920 725.760 181.944 ;
    END
  END rx[323]
  PIN rx[324]
    DIRECTION INPUT ;
    USE SIGNAL ;
    PORT
      LAYER M4 ;
        RECT 725.568 182.496 725.760 182.520 ;
    END
  END rx[324]
  PIN rx[325]
    DIRECTION INPUT ;
    USE SIGNAL ;
    PORT
      LAYER M4 ;
        RECT 725.568 183.024 725.760 183.048 ;
    END
  END rx[325]
  PIN rx[326]
    DIRECTION INPUT ;
    USE SIGNAL ;
    PORT
      LAYER M4 ;
        RECT 725.568 183.600 725.760 183.624 ;
    END
  END rx[326]
  PIN rx[327]
    DIRECTION INPUT ;
    USE SIGNAL ;
    PORT
      LAYER M4 ;
        RECT 725.568 184.128 725.760 184.152 ;
    END
  END rx[327]
  PIN rx[328]
    DIRECTION INPUT ;
    USE SIGNAL ;
    PORT
      LAYER M4 ;
        RECT 725.568 184.704 725.760 184.728 ;
    END
  END rx[328]
  PIN rx[329]
    DIRECTION INPUT ;
    USE SIGNAL ;
    PORT
      LAYER M4 ;
        RECT 725.568 185.280 725.760 185.304 ;
    END
  END rx[329]
  PIN rx[330]
    DIRECTION INPUT ;
    USE SIGNAL ;
    PORT
      LAYER M4 ;
        RECT 725.568 185.808 725.760 185.832 ;
    END
  END rx[330]
  PIN rx[331]
    DIRECTION INPUT ;
    USE SIGNAL ;
    PORT
      LAYER M4 ;
        RECT 725.568 186.384 725.760 186.408 ;
    END
  END rx[331]
  PIN rx[332]
    DIRECTION INPUT ;
    USE SIGNAL ;
    PORT
      LAYER M4 ;
        RECT 725.568 186.912 725.760 186.936 ;
    END
  END rx[332]
  PIN rx[333]
    DIRECTION INPUT ;
    USE SIGNAL ;
    PORT
      LAYER M4 ;
        RECT 725.568 187.488 725.760 187.512 ;
    END
  END rx[333]
  PIN rx[334]
    DIRECTION INPUT ;
    USE SIGNAL ;
    PORT
      LAYER M4 ;
        RECT 725.568 188.016 725.760 188.040 ;
    END
  END rx[334]
  PIN rx[335]
    DIRECTION INPUT ;
    USE SIGNAL ;
    PORT
      LAYER M4 ;
        RECT 725.568 188.592 725.760 188.616 ;
    END
  END rx[335]
  PIN rx[336]
    DIRECTION INPUT ;
    USE SIGNAL ;
    PORT
      LAYER M4 ;
        RECT 725.568 189.168 725.760 189.192 ;
    END
  END rx[336]
  PIN rx[337]
    DIRECTION INPUT ;
    USE SIGNAL ;
    PORT
      LAYER M4 ;
        RECT 725.568 189.696 725.760 189.720 ;
    END
  END rx[337]
  PIN rx[338]
    DIRECTION INPUT ;
    USE SIGNAL ;
    PORT
      LAYER M4 ;
        RECT 725.568 190.272 725.760 190.296 ;
    END
  END rx[338]
  PIN rx[339]
    DIRECTION INPUT ;
    USE SIGNAL ;
    PORT
      LAYER M4 ;
        RECT 725.568 190.800 725.760 190.824 ;
    END
  END rx[339]
  PIN rx[340]
    DIRECTION INPUT ;
    USE SIGNAL ;
    PORT
      LAYER M4 ;
        RECT 725.568 191.376 725.760 191.400 ;
    END
  END rx[340]
  PIN rx[341]
    DIRECTION INPUT ;
    USE SIGNAL ;
    PORT
      LAYER M4 ;
        RECT 725.568 191.952 725.760 191.976 ;
    END
  END rx[341]
  PIN rx[342]
    DIRECTION INPUT ;
    USE SIGNAL ;
    PORT
      LAYER M4 ;
        RECT 725.568 192.480 725.760 192.504 ;
    END
  END rx[342]
  PIN rx[343]
    DIRECTION INPUT ;
    USE SIGNAL ;
    PORT
      LAYER M4 ;
        RECT 725.568 193.056 725.760 193.080 ;
    END
  END rx[343]
  PIN rx[344]
    DIRECTION INPUT ;
    USE SIGNAL ;
    PORT
      LAYER M4 ;
        RECT 725.568 193.584 725.760 193.608 ;
    END
  END rx[344]
  PIN rx[345]
    DIRECTION INPUT ;
    USE SIGNAL ;
    PORT
      LAYER M4 ;
        RECT 725.568 194.160 725.760 194.184 ;
    END
  END rx[345]
  PIN rx[346]
    DIRECTION INPUT ;
    USE SIGNAL ;
    PORT
      LAYER M4 ;
        RECT 725.568 194.688 725.760 194.712 ;
    END
  END rx[346]
  PIN rx[347]
    DIRECTION INPUT ;
    USE SIGNAL ;
    PORT
      LAYER M4 ;
        RECT 725.568 195.264 725.760 195.288 ;
    END
  END rx[347]
  PIN rx[348]
    DIRECTION INPUT ;
    USE SIGNAL ;
    PORT
      LAYER M4 ;
        RECT 725.568 195.840 725.760 195.864 ;
    END
  END rx[348]
  PIN rx[349]
    DIRECTION INPUT ;
    USE SIGNAL ;
    PORT
      LAYER M4 ;
        RECT 725.568 196.368 725.760 196.392 ;
    END
  END rx[349]
  PIN rx[350]
    DIRECTION INPUT ;
    USE SIGNAL ;
    PORT
      LAYER M4 ;
        RECT 725.568 196.944 725.760 196.968 ;
    END
  END rx[350]
  PIN rx[351]
    DIRECTION INPUT ;
    USE SIGNAL ;
    PORT
      LAYER M4 ;
        RECT 725.568 197.472 725.760 197.496 ;
    END
  END rx[351]
  PIN rx[352]
    DIRECTION INPUT ;
    USE SIGNAL ;
    PORT
      LAYER M4 ;
        RECT 725.568 198.048 725.760 198.072 ;
    END
  END rx[352]
  PIN rx[353]
    DIRECTION INPUT ;
    USE SIGNAL ;
    PORT
      LAYER M4 ;
        RECT 725.568 198.576 725.760 198.600 ;
    END
  END rx[353]
  PIN rx[354]
    DIRECTION INPUT ;
    USE SIGNAL ;
    PORT
      LAYER M4 ;
        RECT 725.568 199.152 725.760 199.176 ;
    END
  END rx[354]
  PIN rx[355]
    DIRECTION INPUT ;
    USE SIGNAL ;
    PORT
      LAYER M4 ;
        RECT 725.568 199.728 725.760 199.752 ;
    END
  END rx[355]
  PIN rx[356]
    DIRECTION INPUT ;
    USE SIGNAL ;
    PORT
      LAYER M4 ;
        RECT 725.568 200.256 725.760 200.280 ;
    END
  END rx[356]
  PIN rx[357]
    DIRECTION INPUT ;
    USE SIGNAL ;
    PORT
      LAYER M4 ;
        RECT 725.568 200.832 725.760 200.856 ;
    END
  END rx[357]
  PIN rx[358]
    DIRECTION INPUT ;
    USE SIGNAL ;
    PORT
      LAYER M4 ;
        RECT 725.568 201.360 725.760 201.384 ;
    END
  END rx[358]
  PIN rx[359]
    DIRECTION INPUT ;
    USE SIGNAL ;
    PORT
      LAYER M4 ;
        RECT 725.568 201.936 725.760 201.960 ;
    END
  END rx[359]
  PIN rx[360]
    DIRECTION INPUT ;
    USE SIGNAL ;
    PORT
      LAYER M4 ;
        RECT 725.568 202.464 725.760 202.488 ;
    END
  END rx[360]
  PIN rx[361]
    DIRECTION INPUT ;
    USE SIGNAL ;
    PORT
      LAYER M4 ;
        RECT 725.568 203.040 725.760 203.064 ;
    END
  END rx[361]
  PIN rx[362]
    DIRECTION INPUT ;
    USE SIGNAL ;
    PORT
      LAYER M4 ;
        RECT 725.568 203.616 725.760 203.640 ;
    END
  END rx[362]
  PIN rx[363]
    DIRECTION INPUT ;
    USE SIGNAL ;
    PORT
      LAYER M4 ;
        RECT 725.568 204.144 725.760 204.168 ;
    END
  END rx[363]
  PIN rx[364]
    DIRECTION INPUT ;
    USE SIGNAL ;
    PORT
      LAYER M4 ;
        RECT 725.568 204.720 725.760 204.744 ;
    END
  END rx[364]
  PIN rx[365]
    DIRECTION INPUT ;
    USE SIGNAL ;
    PORT
      LAYER M4 ;
        RECT 725.568 205.248 725.760 205.272 ;
    END
  END rx[365]
  PIN rx[366]
    DIRECTION INPUT ;
    USE SIGNAL ;
    PORT
      LAYER M4 ;
        RECT 725.568 205.824 725.760 205.848 ;
    END
  END rx[366]
  PIN rx[367]
    DIRECTION INPUT ;
    USE SIGNAL ;
    PORT
      LAYER M4 ;
        RECT 725.568 206.400 725.760 206.424 ;
    END
  END rx[367]
  PIN rx[368]
    DIRECTION INPUT ;
    USE SIGNAL ;
    PORT
      LAYER M4 ;
        RECT 725.568 206.928 725.760 206.952 ;
    END
  END rx[368]
  PIN rx[369]
    DIRECTION INPUT ;
    USE SIGNAL ;
    PORT
      LAYER M4 ;
        RECT 725.568 207.504 725.760 207.528 ;
    END
  END rx[369]
  PIN rx[370]
    DIRECTION INPUT ;
    USE SIGNAL ;
    PORT
      LAYER M4 ;
        RECT 725.568 208.032 725.760 208.056 ;
    END
  END rx[370]
  PIN rx[371]
    DIRECTION INPUT ;
    USE SIGNAL ;
    PORT
      LAYER M4 ;
        RECT 725.568 208.608 725.760 208.632 ;
    END
  END rx[371]
  PIN rx[372]
    DIRECTION INPUT ;
    USE SIGNAL ;
    PORT
      LAYER M4 ;
        RECT 725.568 209.136 725.760 209.160 ;
    END
  END rx[372]
  PIN rx[373]
    DIRECTION INPUT ;
    USE SIGNAL ;
    PORT
      LAYER M4 ;
        RECT 725.568 209.712 725.760 209.736 ;
    END
  END rx[373]
  PIN rx[374]
    DIRECTION INPUT ;
    USE SIGNAL ;
    PORT
      LAYER M4 ;
        RECT 725.568 210.288 725.760 210.312 ;
    END
  END rx[374]
  PIN rx[375]
    DIRECTION INPUT ;
    USE SIGNAL ;
    PORT
      LAYER M4 ;
        RECT 725.568 210.816 725.760 210.840 ;
    END
  END rx[375]
  PIN rx[376]
    DIRECTION INPUT ;
    USE SIGNAL ;
    PORT
      LAYER M4 ;
        RECT 725.568 211.392 725.760 211.416 ;
    END
  END rx[376]
  PIN rx[377]
    DIRECTION INPUT ;
    USE SIGNAL ;
    PORT
      LAYER M4 ;
        RECT 725.568 211.920 725.760 211.944 ;
    END
  END rx[377]
  PIN rx[378]
    DIRECTION INPUT ;
    USE SIGNAL ;
    PORT
      LAYER M4 ;
        RECT 725.568 212.496 725.760 212.520 ;
    END
  END rx[378]
  PIN rx[379]
    DIRECTION INPUT ;
    USE SIGNAL ;
    PORT
      LAYER M4 ;
        RECT 725.568 213.024 725.760 213.048 ;
    END
  END rx[379]
  PIN rx[380]
    DIRECTION INPUT ;
    USE SIGNAL ;
    PORT
      LAYER M4 ;
        RECT 725.568 213.600 725.760 213.624 ;
    END
  END rx[380]
  PIN rx[381]
    DIRECTION INPUT ;
    USE SIGNAL ;
    PORT
      LAYER M4 ;
        RECT 725.568 214.176 725.760 214.200 ;
    END
  END rx[381]
  PIN rx[382]
    DIRECTION INPUT ;
    USE SIGNAL ;
    PORT
      LAYER M4 ;
        RECT 725.568 214.704 725.760 214.728 ;
    END
  END rx[382]
  PIN rx[383]
    DIRECTION INPUT ;
    USE SIGNAL ;
    PORT
      LAYER M4 ;
        RECT 725.568 215.280 725.760 215.304 ;
    END
  END rx[383]
  PIN rx[384]
    DIRECTION INPUT ;
    USE SIGNAL ;
    PORT
      LAYER M4 ;
        RECT 725.568 215.808 725.760 215.832 ;
    END
  END rx[384]
  PIN rx[385]
    DIRECTION INPUT ;
    USE SIGNAL ;
    PORT
      LAYER M4 ;
        RECT 725.568 216.384 725.760 216.408 ;
    END
  END rx[385]
  PIN rx[386]
    DIRECTION INPUT ;
    USE SIGNAL ;
    PORT
      LAYER M4 ;
        RECT 725.568 216.960 725.760 216.984 ;
    END
  END rx[386]
  PIN rx[387]
    DIRECTION INPUT ;
    USE SIGNAL ;
    PORT
      LAYER M4 ;
        RECT 725.568 217.488 725.760 217.512 ;
    END
  END rx[387]
  PIN rx[388]
    DIRECTION INPUT ;
    USE SIGNAL ;
    PORT
      LAYER M4 ;
        RECT 725.568 218.064 725.760 218.088 ;
    END
  END rx[388]
  PIN rx[389]
    DIRECTION INPUT ;
    USE SIGNAL ;
    PORT
      LAYER M4 ;
        RECT 725.568 218.592 725.760 218.616 ;
    END
  END rx[389]
  PIN rx[390]
    DIRECTION INPUT ;
    USE SIGNAL ;
    PORT
      LAYER M4 ;
        RECT 725.568 219.168 725.760 219.192 ;
    END
  END rx[390]
  PIN rx[391]
    DIRECTION INPUT ;
    USE SIGNAL ;
    PORT
      LAYER M4 ;
        RECT 725.568 219.696 725.760 219.720 ;
    END
  END rx[391]
  PIN rx[392]
    DIRECTION INPUT ;
    USE SIGNAL ;
    PORT
      LAYER M4 ;
        RECT 725.568 220.272 725.760 220.296 ;
    END
  END rx[392]
  PIN rx[393]
    DIRECTION INPUT ;
    USE SIGNAL ;
    PORT
      LAYER M4 ;
        RECT 725.568 220.848 725.760 220.872 ;
    END
  END rx[393]
  PIN rx[394]
    DIRECTION INPUT ;
    USE SIGNAL ;
    PORT
      LAYER M4 ;
        RECT 725.568 221.376 725.760 221.400 ;
    END
  END rx[394]
  PIN rx[395]
    DIRECTION INPUT ;
    USE SIGNAL ;
    PORT
      LAYER M4 ;
        RECT 725.568 221.952 725.760 221.976 ;
    END
  END rx[395]
  PIN rx[396]
    DIRECTION INPUT ;
    USE SIGNAL ;
    PORT
      LAYER M4 ;
        RECT 725.568 222.480 725.760 222.504 ;
    END
  END rx[396]
  PIN rx[397]
    DIRECTION INPUT ;
    USE SIGNAL ;
    PORT
      LAYER M4 ;
        RECT 725.568 223.056 725.760 223.080 ;
    END
  END rx[397]
  PIN rx[398]
    DIRECTION INPUT ;
    USE SIGNAL ;
    PORT
      LAYER M4 ;
        RECT 725.568 223.584 725.760 223.608 ;
    END
  END rx[398]
  PIN rx[399]
    DIRECTION INPUT ;
    USE SIGNAL ;
    PORT
      LAYER M4 ;
        RECT 725.568 224.160 725.760 224.184 ;
    END
  END rx[399]
  PIN rx[400]
    DIRECTION INPUT ;
    USE SIGNAL ;
    PORT
      LAYER M4 ;
        RECT 725.568 224.736 725.760 224.760 ;
    END
  END rx[400]
  PIN rx[401]
    DIRECTION INPUT ;
    USE SIGNAL ;
    PORT
      LAYER M4 ;
        RECT 725.568 225.264 725.760 225.288 ;
    END
  END rx[401]
  PIN rx[402]
    DIRECTION INPUT ;
    USE SIGNAL ;
    PORT
      LAYER M4 ;
        RECT 725.568 225.840 725.760 225.864 ;
    END
  END rx[402]
  PIN rx[403]
    DIRECTION INPUT ;
    USE SIGNAL ;
    PORT
      LAYER M4 ;
        RECT 725.568 226.368 725.760 226.392 ;
    END
  END rx[403]
  PIN rx[404]
    DIRECTION INPUT ;
    USE SIGNAL ;
    PORT
      LAYER M4 ;
        RECT 725.568 226.944 725.760 226.968 ;
    END
  END rx[404]
  PIN rx[405]
    DIRECTION INPUT ;
    USE SIGNAL ;
    PORT
      LAYER M4 ;
        RECT 725.568 227.472 725.760 227.496 ;
    END
  END rx[405]
  PIN rx[406]
    DIRECTION INPUT ;
    USE SIGNAL ;
    PORT
      LAYER M4 ;
        RECT 725.568 228.048 725.760 228.072 ;
    END
  END rx[406]
  PIN rx[407]
    DIRECTION INPUT ;
    USE SIGNAL ;
    PORT
      LAYER M4 ;
        RECT 725.568 228.624 725.760 228.648 ;
    END
  END rx[407]
  PIN rx[408]
    DIRECTION INPUT ;
    USE SIGNAL ;
    PORT
      LAYER M4 ;
        RECT 725.568 229.152 725.760 229.176 ;
    END
  END rx[408]
  PIN rx[409]
    DIRECTION INPUT ;
    USE SIGNAL ;
    PORT
      LAYER M4 ;
        RECT 725.568 229.728 725.760 229.752 ;
    END
  END rx[409]
  PIN rx[410]
    DIRECTION INPUT ;
    USE SIGNAL ;
    PORT
      LAYER M4 ;
        RECT 725.568 230.256 725.760 230.280 ;
    END
  END rx[410]
  PIN rx[411]
    DIRECTION INPUT ;
    USE SIGNAL ;
    PORT
      LAYER M4 ;
        RECT 725.568 230.832 725.760 230.856 ;
    END
  END rx[411]
  PIN rx[412]
    DIRECTION INPUT ;
    USE SIGNAL ;
    PORT
      LAYER M4 ;
        RECT 725.568 231.408 725.760 231.432 ;
    END
  END rx[412]
  PIN rx[413]
    DIRECTION INPUT ;
    USE SIGNAL ;
    PORT
      LAYER M4 ;
        RECT 725.568 231.936 725.760 231.960 ;
    END
  END rx[413]
  PIN rx[414]
    DIRECTION INPUT ;
    USE SIGNAL ;
    PORT
      LAYER M4 ;
        RECT 725.568 232.512 725.760 232.536 ;
    END
  END rx[414]
  PIN rx[415]
    DIRECTION INPUT ;
    USE SIGNAL ;
    PORT
      LAYER M4 ;
        RECT 725.568 233.040 725.760 233.064 ;
    END
  END rx[415]
  PIN rx[416]
    DIRECTION INPUT ;
    USE SIGNAL ;
    PORT
      LAYER M4 ;
        RECT 725.568 233.616 725.760 233.640 ;
    END
  END rx[416]
  PIN rx[417]
    DIRECTION INPUT ;
    USE SIGNAL ;
    PORT
      LAYER M4 ;
        RECT 725.568 234.144 725.760 234.168 ;
    END
  END rx[417]
  PIN rx[418]
    DIRECTION INPUT ;
    USE SIGNAL ;
    PORT
      LAYER M4 ;
        RECT 725.568 234.720 725.760 234.744 ;
    END
  END rx[418]
  PIN rx[419]
    DIRECTION INPUT ;
    USE SIGNAL ;
    PORT
      LAYER M4 ;
        RECT 725.568 235.296 725.760 235.320 ;
    END
  END rx[419]
  PIN rx[420]
    DIRECTION INPUT ;
    USE SIGNAL ;
    PORT
      LAYER M4 ;
        RECT 725.568 235.824 725.760 235.848 ;
    END
  END rx[420]
  PIN rx[421]
    DIRECTION INPUT ;
    USE SIGNAL ;
    PORT
      LAYER M4 ;
        RECT 725.568 236.400 725.760 236.424 ;
    END
  END rx[421]
  PIN rx[422]
    DIRECTION INPUT ;
    USE SIGNAL ;
    PORT
      LAYER M4 ;
        RECT 725.568 236.928 725.760 236.952 ;
    END
  END rx[422]
  PIN rx[423]
    DIRECTION INPUT ;
    USE SIGNAL ;
    PORT
      LAYER M4 ;
        RECT 725.568 237.504 725.760 237.528 ;
    END
  END rx[423]
  PIN rx[424]
    DIRECTION INPUT ;
    USE SIGNAL ;
    PORT
      LAYER M4 ;
        RECT 725.568 238.032 725.760 238.056 ;
    END
  END rx[424]
  PIN rx[425]
    DIRECTION INPUT ;
    USE SIGNAL ;
    PORT
      LAYER M4 ;
        RECT 725.568 238.608 725.760 238.632 ;
    END
  END rx[425]
  PIN rx[426]
    DIRECTION INPUT ;
    USE SIGNAL ;
    PORT
      LAYER M4 ;
        RECT 725.568 239.184 725.760 239.208 ;
    END
  END rx[426]
  PIN rx[427]
    DIRECTION INPUT ;
    USE SIGNAL ;
    PORT
      LAYER M4 ;
        RECT 725.568 239.712 725.760 239.736 ;
    END
  END rx[427]
  PIN rx[428]
    DIRECTION INPUT ;
    USE SIGNAL ;
    PORT
      LAYER M4 ;
        RECT 725.568 240.288 725.760 240.312 ;
    END
  END rx[428]
  PIN rx[429]
    DIRECTION INPUT ;
    USE SIGNAL ;
    PORT
      LAYER M4 ;
        RECT 725.568 240.816 725.760 240.840 ;
    END
  END rx[429]
  PIN rx[430]
    DIRECTION INPUT ;
    USE SIGNAL ;
    PORT
      LAYER M4 ;
        RECT 725.568 241.392 725.760 241.416 ;
    END
  END rx[430]
  PIN rx[431]
    DIRECTION INPUT ;
    USE SIGNAL ;
    PORT
      LAYER M4 ;
        RECT 725.568 241.968 725.760 241.992 ;
    END
  END rx[431]
  PIN rx[432]
    DIRECTION INPUT ;
    USE SIGNAL ;
    PORT
      LAYER M4 ;
        RECT 725.568 242.496 725.760 242.520 ;
    END
  END rx[432]
  PIN rx[433]
    DIRECTION INPUT ;
    USE SIGNAL ;
    PORT
      LAYER M4 ;
        RECT 725.568 243.072 725.760 243.096 ;
    END
  END rx[433]
  PIN rx[434]
    DIRECTION INPUT ;
    USE SIGNAL ;
    PORT
      LAYER M4 ;
        RECT 725.568 243.600 725.760 243.624 ;
    END
  END rx[434]
  PIN rx[435]
    DIRECTION INPUT ;
    USE SIGNAL ;
    PORT
      LAYER M4 ;
        RECT 725.568 244.176 725.760 244.200 ;
    END
  END rx[435]
  PIN rx[436]
    DIRECTION INPUT ;
    USE SIGNAL ;
    PORT
      LAYER M4 ;
        RECT 725.568 244.704 725.760 244.728 ;
    END
  END rx[436]
  PIN rx[437]
    DIRECTION INPUT ;
    USE SIGNAL ;
    PORT
      LAYER M4 ;
        RECT 725.568 245.280 725.760 245.304 ;
    END
  END rx[437]
  PIN rx[438]
    DIRECTION INPUT ;
    USE SIGNAL ;
    PORT
      LAYER M4 ;
        RECT 725.568 245.856 725.760 245.880 ;
    END
  END rx[438]
  PIN rx[439]
    DIRECTION INPUT ;
    USE SIGNAL ;
    PORT
      LAYER M4 ;
        RECT 725.568 246.384 725.760 246.408 ;
    END
  END rx[439]
  PIN rx[440]
    DIRECTION INPUT ;
    USE SIGNAL ;
    PORT
      LAYER M4 ;
        RECT 725.568 246.960 725.760 246.984 ;
    END
  END rx[440]
  PIN rx[441]
    DIRECTION INPUT ;
    USE SIGNAL ;
    PORT
      LAYER M4 ;
        RECT 725.568 247.488 725.760 247.512 ;
    END
  END rx[441]
  PIN rx[442]
    DIRECTION INPUT ;
    USE SIGNAL ;
    PORT
      LAYER M4 ;
        RECT 725.568 248.064 725.760 248.088 ;
    END
  END rx[442]
  PIN rx[443]
    DIRECTION INPUT ;
    USE SIGNAL ;
    PORT
      LAYER M4 ;
        RECT 725.568 248.592 725.760 248.616 ;
    END
  END rx[443]
  PIN rx[444]
    DIRECTION INPUT ;
    USE SIGNAL ;
    PORT
      LAYER M4 ;
        RECT 725.568 249.168 725.760 249.192 ;
    END
  END rx[444]
  PIN rx[445]
    DIRECTION INPUT ;
    USE SIGNAL ;
    PORT
      LAYER M4 ;
        RECT 725.568 249.744 725.760 249.768 ;
    END
  END rx[445]
  PIN rx[446]
    DIRECTION INPUT ;
    USE SIGNAL ;
    PORT
      LAYER M4 ;
        RECT 725.568 250.272 725.760 250.296 ;
    END
  END rx[446]
  PIN rx[447]
    DIRECTION INPUT ;
    USE SIGNAL ;
    PORT
      LAYER M4 ;
        RECT 725.568 250.848 725.760 250.872 ;
    END
  END rx[447]
  PIN rx[448]
    DIRECTION INPUT ;
    USE SIGNAL ;
    PORT
      LAYER M4 ;
        RECT 725.568 251.376 725.760 251.400 ;
    END
  END rx[448]
  PIN rx[449]
    DIRECTION INPUT ;
    USE SIGNAL ;
    PORT
      LAYER M4 ;
        RECT 725.568 251.952 725.760 251.976 ;
    END
  END rx[449]
  PIN rx[450]
    DIRECTION INPUT ;
    USE SIGNAL ;
    PORT
      LAYER M4 ;
        RECT 725.568 252.480 725.760 252.504 ;
    END
  END rx[450]
  PIN rx[451]
    DIRECTION INPUT ;
    USE SIGNAL ;
    PORT
      LAYER M4 ;
        RECT 725.568 253.056 725.760 253.080 ;
    END
  END rx[451]
  PIN rx[452]
    DIRECTION INPUT ;
    USE SIGNAL ;
    PORT
      LAYER M4 ;
        RECT 725.568 253.632 725.760 253.656 ;
    END
  END rx[452]
  PIN rx[453]
    DIRECTION INPUT ;
    USE SIGNAL ;
    PORT
      LAYER M4 ;
        RECT 725.568 254.160 725.760 254.184 ;
    END
  END rx[453]
  PIN rx[454]
    DIRECTION INPUT ;
    USE SIGNAL ;
    PORT
      LAYER M4 ;
        RECT 725.568 254.736 725.760 254.760 ;
    END
  END rx[454]
  PIN rx[455]
    DIRECTION INPUT ;
    USE SIGNAL ;
    PORT
      LAYER M4 ;
        RECT 725.568 255.264 725.760 255.288 ;
    END
  END rx[455]
  PIN rx[456]
    DIRECTION INPUT ;
    USE SIGNAL ;
    PORT
      LAYER M4 ;
        RECT 725.568 255.840 725.760 255.864 ;
    END
  END rx[456]
  PIN rx[457]
    DIRECTION INPUT ;
    USE SIGNAL ;
    PORT
      LAYER M4 ;
        RECT 725.568 256.416 725.760 256.440 ;
    END
  END rx[457]
  PIN rx[458]
    DIRECTION INPUT ;
    USE SIGNAL ;
    PORT
      LAYER M4 ;
        RECT 725.568 256.944 725.760 256.968 ;
    END
  END rx[458]
  PIN rx[459]
    DIRECTION INPUT ;
    USE SIGNAL ;
    PORT
      LAYER M4 ;
        RECT 725.568 257.520 725.760 257.544 ;
    END
  END rx[459]
  PIN rx[460]
    DIRECTION INPUT ;
    USE SIGNAL ;
    PORT
      LAYER M4 ;
        RECT 725.568 258.048 725.760 258.072 ;
    END
  END rx[460]
  PIN rx[461]
    DIRECTION INPUT ;
    USE SIGNAL ;
    PORT
      LAYER M4 ;
        RECT 725.568 258.624 725.760 258.648 ;
    END
  END rx[461]
  PIN rx[462]
    DIRECTION INPUT ;
    USE SIGNAL ;
    PORT
      LAYER M4 ;
        RECT 725.568 259.152 725.760 259.176 ;
    END
  END rx[462]
  PIN rx[463]
    DIRECTION INPUT ;
    USE SIGNAL ;
    PORT
      LAYER M4 ;
        RECT 725.568 259.728 725.760 259.752 ;
    END
  END rx[463]
  PIN rx[464]
    DIRECTION INPUT ;
    USE SIGNAL ;
    PORT
      LAYER M4 ;
        RECT 725.568 260.304 725.760 260.328 ;
    END
  END rx[464]
  PIN rx[465]
    DIRECTION INPUT ;
    USE SIGNAL ;
    PORT
      LAYER M4 ;
        RECT 725.568 260.832 725.760 260.856 ;
    END
  END rx[465]
  PIN rx[466]
    DIRECTION INPUT ;
    USE SIGNAL ;
    PORT
      LAYER M4 ;
        RECT 725.568 261.408 725.760 261.432 ;
    END
  END rx[466]
  PIN rx[467]
    DIRECTION INPUT ;
    USE SIGNAL ;
    PORT
      LAYER M4 ;
        RECT 725.568 261.936 725.760 261.960 ;
    END
  END rx[467]
  PIN rx[468]
    DIRECTION INPUT ;
    USE SIGNAL ;
    PORT
      LAYER M4 ;
        RECT 725.568 262.512 725.760 262.536 ;
    END
  END rx[468]
  PIN rx[469]
    DIRECTION INPUT ;
    USE SIGNAL ;
    PORT
      LAYER M4 ;
        RECT 725.568 263.040 725.760 263.064 ;
    END
  END rx[469]
  PIN rx[470]
    DIRECTION INPUT ;
    USE SIGNAL ;
    PORT
      LAYER M4 ;
        RECT 725.568 263.616 725.760 263.640 ;
    END
  END rx[470]
  PIN rx[471]
    DIRECTION INPUT ;
    USE SIGNAL ;
    PORT
      LAYER M4 ;
        RECT 725.568 264.192 725.760 264.216 ;
    END
  END rx[471]
  PIN rx[472]
    DIRECTION INPUT ;
    USE SIGNAL ;
    PORT
      LAYER M4 ;
        RECT 725.568 264.720 725.760 264.744 ;
    END
  END rx[472]
  PIN rx[473]
    DIRECTION INPUT ;
    USE SIGNAL ;
    PORT
      LAYER M4 ;
        RECT 725.568 265.296 725.760 265.320 ;
    END
  END rx[473]
  PIN rx[474]
    DIRECTION INPUT ;
    USE SIGNAL ;
    PORT
      LAYER M4 ;
        RECT 725.568 265.824 725.760 265.848 ;
    END
  END rx[474]
  PIN rx[475]
    DIRECTION INPUT ;
    USE SIGNAL ;
    PORT
      LAYER M4 ;
        RECT 725.568 266.400 725.760 266.424 ;
    END
  END rx[475]
  PIN rx[476]
    DIRECTION INPUT ;
    USE SIGNAL ;
    PORT
      LAYER M4 ;
        RECT 725.568 266.976 725.760 267.000 ;
    END
  END rx[476]
  PIN rx[477]
    DIRECTION INPUT ;
    USE SIGNAL ;
    PORT
      LAYER M4 ;
        RECT 725.568 267.504 725.760 267.528 ;
    END
  END rx[477]
  PIN rx[478]
    DIRECTION INPUT ;
    USE SIGNAL ;
    PORT
      LAYER M4 ;
        RECT 725.568 268.080 725.760 268.104 ;
    END
  END rx[478]
  PIN rx[479]
    DIRECTION INPUT ;
    USE SIGNAL ;
    PORT
      LAYER M4 ;
        RECT 725.568 268.608 725.760 268.632 ;
    END
  END rx[479]
  PIN rx[480]
    DIRECTION INPUT ;
    USE SIGNAL ;
    PORT
      LAYER M4 ;
        RECT 725.568 269.184 725.760 269.208 ;
    END
  END rx[480]
  PIN rx[481]
    DIRECTION INPUT ;
    USE SIGNAL ;
    PORT
      LAYER M4 ;
        RECT 725.568 269.712 725.760 269.736 ;
    END
  END rx[481]
  PIN rx[482]
    DIRECTION INPUT ;
    USE SIGNAL ;
    PORT
      LAYER M4 ;
        RECT 725.568 270.288 725.760 270.312 ;
    END
  END rx[482]
  PIN rx[483]
    DIRECTION INPUT ;
    USE SIGNAL ;
    PORT
      LAYER M4 ;
        RECT 725.568 270.864 725.760 270.888 ;
    END
  END rx[483]
  PIN rx[484]
    DIRECTION INPUT ;
    USE SIGNAL ;
    PORT
      LAYER M4 ;
        RECT 725.568 271.392 725.760 271.416 ;
    END
  END rx[484]
  PIN rx[485]
    DIRECTION INPUT ;
    USE SIGNAL ;
    PORT
      LAYER M4 ;
        RECT 725.568 271.968 725.760 271.992 ;
    END
  END rx[485]
  PIN rx[486]
    DIRECTION INPUT ;
    USE SIGNAL ;
    PORT
      LAYER M4 ;
        RECT 725.568 272.496 725.760 272.520 ;
    END
  END rx[486]
  PIN rx[487]
    DIRECTION INPUT ;
    USE SIGNAL ;
    PORT
      LAYER M4 ;
        RECT 725.568 273.072 725.760 273.096 ;
    END
  END rx[487]
  PIN rx[488]
    DIRECTION INPUT ;
    USE SIGNAL ;
    PORT
      LAYER M4 ;
        RECT 725.568 273.600 725.760 273.624 ;
    END
  END rx[488]
  PIN rx[489]
    DIRECTION INPUT ;
    USE SIGNAL ;
    PORT
      LAYER M4 ;
        RECT 725.568 274.176 725.760 274.200 ;
    END
  END rx[489]
  PIN rx[490]
    DIRECTION INPUT ;
    USE SIGNAL ;
    PORT
      LAYER M4 ;
        RECT 725.568 274.752 725.760 274.776 ;
    END
  END rx[490]
  PIN rx[491]
    DIRECTION INPUT ;
    USE SIGNAL ;
    PORT
      LAYER M4 ;
        RECT 725.568 275.280 725.760 275.304 ;
    END
  END rx[491]
  PIN rx[492]
    DIRECTION INPUT ;
    USE SIGNAL ;
    PORT
      LAYER M4 ;
        RECT 725.568 275.856 725.760 275.880 ;
    END
  END rx[492]
  PIN rx[493]
    DIRECTION INPUT ;
    USE SIGNAL ;
    PORT
      LAYER M4 ;
        RECT 725.568 276.384 725.760 276.408 ;
    END
  END rx[493]
  PIN rx[494]
    DIRECTION INPUT ;
    USE SIGNAL ;
    PORT
      LAYER M4 ;
        RECT 725.568 276.960 725.760 276.984 ;
    END
  END rx[494]
  PIN rx[495]
    DIRECTION INPUT ;
    USE SIGNAL ;
    PORT
      LAYER M4 ;
        RECT 725.568 277.488 725.760 277.512 ;
    END
  END rx[495]
  PIN rx[496]
    DIRECTION INPUT ;
    USE SIGNAL ;
    PORT
      LAYER M4 ;
        RECT 725.568 278.064 725.760 278.088 ;
    END
  END rx[496]
  PIN rx[497]
    DIRECTION INPUT ;
    USE SIGNAL ;
    PORT
      LAYER M4 ;
        RECT 725.568 278.640 725.760 278.664 ;
    END
  END rx[497]
  PIN rx[498]
    DIRECTION INPUT ;
    USE SIGNAL ;
    PORT
      LAYER M4 ;
        RECT 725.568 279.168 725.760 279.192 ;
    END
  END rx[498]
  PIN rx[499]
    DIRECTION INPUT ;
    USE SIGNAL ;
    PORT
      LAYER M4 ;
        RECT 725.568 279.744 725.760 279.768 ;
    END
  END rx[499]
  PIN rx[500]
    DIRECTION INPUT ;
    USE SIGNAL ;
    PORT
      LAYER M4 ;
        RECT 725.568 280.272 725.760 280.296 ;
    END
  END rx[500]
  PIN rx[501]
    DIRECTION INPUT ;
    USE SIGNAL ;
    PORT
      LAYER M4 ;
        RECT 725.568 280.848 725.760 280.872 ;
    END
  END rx[501]
  PIN rx[502]
    DIRECTION INPUT ;
    USE SIGNAL ;
    PORT
      LAYER M4 ;
        RECT 725.568 281.424 725.760 281.448 ;
    END
  END rx[502]
  PIN rx[503]
    DIRECTION INPUT ;
    USE SIGNAL ;
    PORT
      LAYER M4 ;
        RECT 725.568 281.952 725.760 281.976 ;
    END
  END rx[503]
  PIN rx[504]
    DIRECTION INPUT ;
    USE SIGNAL ;
    PORT
      LAYER M4 ;
        RECT 725.568 282.528 725.760 282.552 ;
    END
  END rx[504]
  PIN rx[505]
    DIRECTION INPUT ;
    USE SIGNAL ;
    PORT
      LAYER M4 ;
        RECT 725.568 283.056 725.760 283.080 ;
    END
  END rx[505]
  PIN rx[506]
    DIRECTION INPUT ;
    USE SIGNAL ;
    PORT
      LAYER M4 ;
        RECT 725.568 283.632 725.760 283.656 ;
    END
  END rx[506]
  PIN rx[507]
    DIRECTION INPUT ;
    USE SIGNAL ;
    PORT
      LAYER M4 ;
        RECT 725.568 284.160 725.760 284.184 ;
    END
  END rx[507]
  PIN rx[508]
    DIRECTION INPUT ;
    USE SIGNAL ;
    PORT
      LAYER M4 ;
        RECT 725.568 284.736 725.760 284.760 ;
    END
  END rx[508]
  PIN rx[509]
    DIRECTION INPUT ;
    USE SIGNAL ;
    PORT
      LAYER M4 ;
        RECT 725.568 285.312 725.760 285.336 ;
    END
  END rx[509]
  PIN rx[510]
    DIRECTION INPUT ;
    USE SIGNAL ;
    PORT
      LAYER M4 ;
        RECT 725.568 285.840 725.760 285.864 ;
    END
  END rx[510]
  PIN rx[511]
    DIRECTION INPUT ;
    USE SIGNAL ;
    PORT
      LAYER M4 ;
        RECT 725.568 286.416 725.760 286.440 ;
    END
  END rx[511]
  PIN rx[512]
    DIRECTION INPUT ;
    USE SIGNAL ;
    PORT
      LAYER M4 ;
        RECT 725.568 286.944 725.760 286.968 ;
    END
  END rx[512]
  PIN rx[513]
    DIRECTION INPUT ;
    USE SIGNAL ;
    PORT
      LAYER M4 ;
        RECT 725.568 287.520 725.760 287.544 ;
    END
  END rx[513]
  PIN rx[514]
    DIRECTION INPUT ;
    USE SIGNAL ;
    PORT
      LAYER M4 ;
        RECT 725.568 288.048 725.760 288.072 ;
    END
  END rx[514]
  PIN tx[0]
    DIRECTION OUTPUT ;
    USE SIGNAL ;
    PORT
      LAYER M4 ;
        RECT 725.568 290.784 725.760 290.808 ;
    END
  END tx[0]
  PIN tx[1]
    DIRECTION OUTPUT ;
    USE SIGNAL ;
    PORT
      LAYER M4 ;
        RECT 725.568 291.360 725.760 291.384 ;
    END
  END tx[1]
  PIN tx[2]
    DIRECTION OUTPUT ;
    USE SIGNAL ;
    PORT
      LAYER M4 ;
        RECT 725.568 291.888 725.760 291.912 ;
    END
  END tx[2]
  PIN tx[3]
    DIRECTION OUTPUT ;
    USE SIGNAL ;
    PORT
      LAYER M4 ;
        RECT 725.568 292.464 725.760 292.488 ;
    END
  END tx[3]
  PIN tx[4]
    DIRECTION OUTPUT ;
    USE SIGNAL ;
    PORT
      LAYER M4 ;
        RECT 725.568 293.040 725.760 293.064 ;
    END
  END tx[4]
  PIN tx[5]
    DIRECTION OUTPUT ;
    USE SIGNAL ;
    PORT
      LAYER M4 ;
        RECT 725.568 293.568 725.760 293.592 ;
    END
  END tx[5]
  PIN tx[6]
    DIRECTION OUTPUT ;
    USE SIGNAL ;
    PORT
      LAYER M4 ;
        RECT 725.568 294.144 725.760 294.168 ;
    END
  END tx[6]
  PIN tx[7]
    DIRECTION OUTPUT ;
    USE SIGNAL ;
    PORT
      LAYER M4 ;
        RECT 725.568 294.720 725.760 294.744 ;
    END
  END tx[7]
  PIN tx[8]
    DIRECTION OUTPUT ;
    USE SIGNAL ;
    PORT
      LAYER M4 ;
        RECT 725.568 295.248 725.760 295.272 ;
    END
  END tx[8]
  PIN tx[9]
    DIRECTION OUTPUT ;
    USE SIGNAL ;
    PORT
      LAYER M4 ;
        RECT 725.568 295.824 725.760 295.848 ;
    END
  END tx[9]
  PIN tx[10]
    DIRECTION OUTPUT ;
    USE SIGNAL ;
    PORT
      LAYER M4 ;
        RECT 725.568 296.400 725.760 296.424 ;
    END
  END tx[10]
  PIN tx[11]
    DIRECTION OUTPUT ;
    USE SIGNAL ;
    PORT
      LAYER M4 ;
        RECT 725.568 296.928 725.760 296.952 ;
    END
  END tx[11]
  PIN tx[12]
    DIRECTION OUTPUT ;
    USE SIGNAL ;
    PORT
      LAYER M4 ;
        RECT 725.568 297.504 725.760 297.528 ;
    END
  END tx[12]
  PIN tx[13]
    DIRECTION OUTPUT ;
    USE SIGNAL ;
    PORT
      LAYER M4 ;
        RECT 725.568 298.032 725.760 298.056 ;
    END
  END tx[13]
  PIN tx[14]
    DIRECTION OUTPUT ;
    USE SIGNAL ;
    PORT
      LAYER M4 ;
        RECT 725.568 298.608 725.760 298.632 ;
    END
  END tx[14]
  PIN tx[15]
    DIRECTION OUTPUT ;
    USE SIGNAL ;
    PORT
      LAYER M4 ;
        RECT 725.568 299.184 725.760 299.208 ;
    END
  END tx[15]
  PIN tx[16]
    DIRECTION OUTPUT ;
    USE SIGNAL ;
    PORT
      LAYER M4 ;
        RECT 725.568 299.712 725.760 299.736 ;
    END
  END tx[16]
  PIN tx[17]
    DIRECTION OUTPUT ;
    USE SIGNAL ;
    PORT
      LAYER M4 ;
        RECT 725.568 300.288 725.760 300.312 ;
    END
  END tx[17]
  PIN tx[18]
    DIRECTION OUTPUT ;
    USE SIGNAL ;
    PORT
      LAYER M4 ;
        RECT 725.568 300.864 725.760 300.888 ;
    END
  END tx[18]
  PIN tx[19]
    DIRECTION OUTPUT ;
    USE SIGNAL ;
    PORT
      LAYER M4 ;
        RECT 725.568 301.392 725.760 301.416 ;
    END
  END tx[19]
  PIN tx[20]
    DIRECTION OUTPUT ;
    USE SIGNAL ;
    PORT
      LAYER M4 ;
        RECT 725.568 301.968 725.760 301.992 ;
    END
  END tx[20]
  PIN tx[21]
    DIRECTION OUTPUT ;
    USE SIGNAL ;
    PORT
      LAYER M4 ;
        RECT 725.568 302.544 725.760 302.568 ;
    END
  END tx[21]
  PIN tx[22]
    DIRECTION OUTPUT ;
    USE SIGNAL ;
    PORT
      LAYER M4 ;
        RECT 725.568 303.072 725.760 303.096 ;
    END
  END tx[22]
  PIN tx[23]
    DIRECTION OUTPUT ;
    USE SIGNAL ;
    PORT
      LAYER M4 ;
        RECT 725.568 303.648 725.760 303.672 ;
    END
  END tx[23]
  PIN tx[24]
    DIRECTION OUTPUT ;
    USE SIGNAL ;
    PORT
      LAYER M4 ;
        RECT 725.568 304.224 725.760 304.248 ;
    END
  END tx[24]
  PIN tx[25]
    DIRECTION OUTPUT ;
    USE SIGNAL ;
    PORT
      LAYER M4 ;
        RECT 725.568 304.752 725.760 304.776 ;
    END
  END tx[25]
  PIN tx[26]
    DIRECTION OUTPUT ;
    USE SIGNAL ;
    PORT
      LAYER M4 ;
        RECT 725.568 305.328 725.760 305.352 ;
    END
  END tx[26]
  PIN tx[27]
    DIRECTION OUTPUT ;
    USE SIGNAL ;
    PORT
      LAYER M4 ;
        RECT 725.568 305.904 725.760 305.928 ;
    END
  END tx[27]
  PIN tx[28]
    DIRECTION OUTPUT ;
    USE SIGNAL ;
    PORT
      LAYER M4 ;
        RECT 725.568 306.432 725.760 306.456 ;
    END
  END tx[28]
  PIN tx[29]
    DIRECTION OUTPUT ;
    USE SIGNAL ;
    PORT
      LAYER M4 ;
        RECT 725.568 307.008 725.760 307.032 ;
    END
  END tx[29]
  PIN tx[30]
    DIRECTION OUTPUT ;
    USE SIGNAL ;
    PORT
      LAYER M4 ;
        RECT 725.568 307.536 725.760 307.560 ;
    END
  END tx[30]
  PIN tx[31]
    DIRECTION OUTPUT ;
    USE SIGNAL ;
    PORT
      LAYER M4 ;
        RECT 725.568 308.112 725.760 308.136 ;
    END
  END tx[31]
  PIN tx[32]
    DIRECTION OUTPUT ;
    USE SIGNAL ;
    PORT
      LAYER M4 ;
        RECT 725.568 308.688 725.760 308.712 ;
    END
  END tx[32]
  PIN tx[33]
    DIRECTION OUTPUT ;
    USE SIGNAL ;
    PORT
      LAYER M4 ;
        RECT 725.568 309.216 725.760 309.240 ;
    END
  END tx[33]
  PIN tx[34]
    DIRECTION OUTPUT ;
    USE SIGNAL ;
    PORT
      LAYER M4 ;
        RECT 725.568 309.792 725.760 309.816 ;
    END
  END tx[34]
  PIN tx[35]
    DIRECTION OUTPUT ;
    USE SIGNAL ;
    PORT
      LAYER M4 ;
        RECT 725.568 310.368 725.760 310.392 ;
    END
  END tx[35]
  PIN tx[36]
    DIRECTION OUTPUT ;
    USE SIGNAL ;
    PORT
      LAYER M4 ;
        RECT 725.568 310.896 725.760 310.920 ;
    END
  END tx[36]
  PIN tx[37]
    DIRECTION OUTPUT ;
    USE SIGNAL ;
    PORT
      LAYER M4 ;
        RECT 725.568 311.472 725.760 311.496 ;
    END
  END tx[37]
  PIN tx[38]
    DIRECTION OUTPUT ;
    USE SIGNAL ;
    PORT
      LAYER M4 ;
        RECT 725.568 312.048 725.760 312.072 ;
    END
  END tx[38]
  PIN tx[39]
    DIRECTION OUTPUT ;
    USE SIGNAL ;
    PORT
      LAYER M4 ;
        RECT 725.568 312.576 725.760 312.600 ;
    END
  END tx[39]
  PIN tx[40]
    DIRECTION OUTPUT ;
    USE SIGNAL ;
    PORT
      LAYER M4 ;
        RECT 725.568 313.152 725.760 313.176 ;
    END
  END tx[40]
  PIN tx[41]
    DIRECTION OUTPUT ;
    USE SIGNAL ;
    PORT
      LAYER M4 ;
        RECT 725.568 313.728 725.760 313.752 ;
    END
  END tx[41]
  PIN tx[42]
    DIRECTION OUTPUT ;
    USE SIGNAL ;
    PORT
      LAYER M4 ;
        RECT 725.568 314.256 725.760 314.280 ;
    END
  END tx[42]
  PIN tx[43]
    DIRECTION OUTPUT ;
    USE SIGNAL ;
    PORT
      LAYER M4 ;
        RECT 725.568 314.832 725.760 314.856 ;
    END
  END tx[43]
  PIN tx[44]
    DIRECTION OUTPUT ;
    USE SIGNAL ;
    PORT
      LAYER M4 ;
        RECT 725.568 315.360 725.760 315.384 ;
    END
  END tx[44]
  PIN tx[45]
    DIRECTION OUTPUT ;
    USE SIGNAL ;
    PORT
      LAYER M4 ;
        RECT 725.568 315.936 725.760 315.960 ;
    END
  END tx[45]
  PIN tx[46]
    DIRECTION OUTPUT ;
    USE SIGNAL ;
    PORT
      LAYER M4 ;
        RECT 725.568 316.512 725.760 316.536 ;
    END
  END tx[46]
  PIN tx[47]
    DIRECTION OUTPUT ;
    USE SIGNAL ;
    PORT
      LAYER M4 ;
        RECT 725.568 317.040 725.760 317.064 ;
    END
  END tx[47]
  PIN tx[48]
    DIRECTION OUTPUT ;
    USE SIGNAL ;
    PORT
      LAYER M4 ;
        RECT 725.568 317.616 725.760 317.640 ;
    END
  END tx[48]
  PIN tx[49]
    DIRECTION OUTPUT ;
    USE SIGNAL ;
    PORT
      LAYER M4 ;
        RECT 725.568 318.192 725.760 318.216 ;
    END
  END tx[49]
  PIN tx[50]
    DIRECTION OUTPUT ;
    USE SIGNAL ;
    PORT
      LAYER M4 ;
        RECT 725.568 318.720 725.760 318.744 ;
    END
  END tx[50]
  PIN tx[51]
    DIRECTION OUTPUT ;
    USE SIGNAL ;
    PORT
      LAYER M4 ;
        RECT 725.568 319.296 725.760 319.320 ;
    END
  END tx[51]
  PIN tx[52]
    DIRECTION OUTPUT ;
    USE SIGNAL ;
    PORT
      LAYER M4 ;
        RECT 725.568 319.872 725.760 319.896 ;
    END
  END tx[52]
  PIN tx[53]
    DIRECTION OUTPUT ;
    USE SIGNAL ;
    PORT
      LAYER M4 ;
        RECT 725.568 320.400 725.760 320.424 ;
    END
  END tx[53]
  PIN tx[54]
    DIRECTION OUTPUT ;
    USE SIGNAL ;
    PORT
      LAYER M4 ;
        RECT 725.568 320.976 725.760 321.000 ;
    END
  END tx[54]
  PIN tx[55]
    DIRECTION OUTPUT ;
    USE SIGNAL ;
    PORT
      LAYER M4 ;
        RECT 725.568 321.552 725.760 321.576 ;
    END
  END tx[55]
  PIN tx[56]
    DIRECTION OUTPUT ;
    USE SIGNAL ;
    PORT
      LAYER M4 ;
        RECT 725.568 322.080 725.760 322.104 ;
    END
  END tx[56]
  PIN tx[57]
    DIRECTION OUTPUT ;
    USE SIGNAL ;
    PORT
      LAYER M4 ;
        RECT 725.568 322.656 725.760 322.680 ;
    END
  END tx[57]
  PIN tx[58]
    DIRECTION OUTPUT ;
    USE SIGNAL ;
    PORT
      LAYER M4 ;
        RECT 725.568 323.232 725.760 323.256 ;
    END
  END tx[58]
  PIN tx[59]
    DIRECTION OUTPUT ;
    USE SIGNAL ;
    PORT
      LAYER M4 ;
        RECT 725.568 323.760 725.760 323.784 ;
    END
  END tx[59]
  PIN tx[60]
    DIRECTION OUTPUT ;
    USE SIGNAL ;
    PORT
      LAYER M4 ;
        RECT 725.568 324.336 725.760 324.360 ;
    END
  END tx[60]
  PIN tx[61]
    DIRECTION OUTPUT ;
    USE SIGNAL ;
    PORT
      LAYER M4 ;
        RECT 725.568 324.864 725.760 324.888 ;
    END
  END tx[61]
  PIN tx[62]
    DIRECTION OUTPUT ;
    USE SIGNAL ;
    PORT
      LAYER M4 ;
        RECT 725.568 325.440 725.760 325.464 ;
    END
  END tx[62]
  PIN tx[63]
    DIRECTION OUTPUT ;
    USE SIGNAL ;
    PORT
      LAYER M4 ;
        RECT 725.568 326.016 725.760 326.040 ;
    END
  END tx[63]
  PIN tx[64]
    DIRECTION OUTPUT ;
    USE SIGNAL ;
    PORT
      LAYER M4 ;
        RECT 725.568 326.544 725.760 326.568 ;
    END
  END tx[64]
  PIN tx[65]
    DIRECTION OUTPUT ;
    USE SIGNAL ;
    PORT
      LAYER M4 ;
        RECT 725.568 327.120 725.760 327.144 ;
    END
  END tx[65]
  PIN tx[66]
    DIRECTION OUTPUT ;
    USE SIGNAL ;
    PORT
      LAYER M4 ;
        RECT 725.568 327.696 725.760 327.720 ;
    END
  END tx[66]
  PIN tx[67]
    DIRECTION OUTPUT ;
    USE SIGNAL ;
    PORT
      LAYER M4 ;
        RECT 725.568 328.224 725.760 328.248 ;
    END
  END tx[67]
  PIN tx[68]
    DIRECTION OUTPUT ;
    USE SIGNAL ;
    PORT
      LAYER M4 ;
        RECT 725.568 328.800 725.760 328.824 ;
    END
  END tx[68]
  PIN tx[69]
    DIRECTION OUTPUT ;
    USE SIGNAL ;
    PORT
      LAYER M4 ;
        RECT 725.568 329.376 725.760 329.400 ;
    END
  END tx[69]
  PIN tx[70]
    DIRECTION OUTPUT ;
    USE SIGNAL ;
    PORT
      LAYER M4 ;
        RECT 725.568 329.904 725.760 329.928 ;
    END
  END tx[70]
  PIN tx[71]
    DIRECTION OUTPUT ;
    USE SIGNAL ;
    PORT
      LAYER M4 ;
        RECT 725.568 330.480 725.760 330.504 ;
    END
  END tx[71]
  PIN tx[72]
    DIRECTION OUTPUT ;
    USE SIGNAL ;
    PORT
      LAYER M4 ;
        RECT 725.568 331.056 725.760 331.080 ;
    END
  END tx[72]
  PIN tx[73]
    DIRECTION OUTPUT ;
    USE SIGNAL ;
    PORT
      LAYER M4 ;
        RECT 725.568 331.584 725.760 331.608 ;
    END
  END tx[73]
  PIN tx[74]
    DIRECTION OUTPUT ;
    USE SIGNAL ;
    PORT
      LAYER M4 ;
        RECT 725.568 332.160 725.760 332.184 ;
    END
  END tx[74]
  PIN tx[75]
    DIRECTION OUTPUT ;
    USE SIGNAL ;
    PORT
      LAYER M4 ;
        RECT 725.568 332.688 725.760 332.712 ;
    END
  END tx[75]
  PIN tx[76]
    DIRECTION OUTPUT ;
    USE SIGNAL ;
    PORT
      LAYER M4 ;
        RECT 725.568 333.264 725.760 333.288 ;
    END
  END tx[76]
  PIN tx[77]
    DIRECTION OUTPUT ;
    USE SIGNAL ;
    PORT
      LAYER M4 ;
        RECT 725.568 333.840 725.760 333.864 ;
    END
  END tx[77]
  PIN tx[78]
    DIRECTION OUTPUT ;
    USE SIGNAL ;
    PORT
      LAYER M4 ;
        RECT 725.568 334.368 725.760 334.392 ;
    END
  END tx[78]
  PIN tx[79]
    DIRECTION OUTPUT ;
    USE SIGNAL ;
    PORT
      LAYER M4 ;
        RECT 725.568 334.944 725.760 334.968 ;
    END
  END tx[79]
  PIN tx[80]
    DIRECTION OUTPUT ;
    USE SIGNAL ;
    PORT
      LAYER M4 ;
        RECT 725.568 335.520 725.760 335.544 ;
    END
  END tx[80]
  PIN tx[81]
    DIRECTION OUTPUT ;
    USE SIGNAL ;
    PORT
      LAYER M4 ;
        RECT 725.568 336.048 725.760 336.072 ;
    END
  END tx[81]
  PIN tx[82]
    DIRECTION OUTPUT ;
    USE SIGNAL ;
    PORT
      LAYER M4 ;
        RECT 725.568 336.624 725.760 336.648 ;
    END
  END tx[82]
  PIN tx[83]
    DIRECTION OUTPUT ;
    USE SIGNAL ;
    PORT
      LAYER M4 ;
        RECT 725.568 337.200 725.760 337.224 ;
    END
  END tx[83]
  PIN tx[84]
    DIRECTION OUTPUT ;
    USE SIGNAL ;
    PORT
      LAYER M4 ;
        RECT 725.568 337.728 725.760 337.752 ;
    END
  END tx[84]
  PIN tx[85]
    DIRECTION OUTPUT ;
    USE SIGNAL ;
    PORT
      LAYER M4 ;
        RECT 725.568 338.304 725.760 338.328 ;
    END
  END tx[85]
  PIN tx[86]
    DIRECTION OUTPUT ;
    USE SIGNAL ;
    PORT
      LAYER M4 ;
        RECT 725.568 338.880 725.760 338.904 ;
    END
  END tx[86]
  PIN tx[87]
    DIRECTION OUTPUT ;
    USE SIGNAL ;
    PORT
      LAYER M4 ;
        RECT 725.568 339.408 725.760 339.432 ;
    END
  END tx[87]
  PIN tx[88]
    DIRECTION OUTPUT ;
    USE SIGNAL ;
    PORT
      LAYER M4 ;
        RECT 725.568 339.984 725.760 340.008 ;
    END
  END tx[88]
  PIN tx[89]
    DIRECTION OUTPUT ;
    USE SIGNAL ;
    PORT
      LAYER M4 ;
        RECT 725.568 340.560 725.760 340.584 ;
    END
  END tx[89]
  PIN tx[90]
    DIRECTION OUTPUT ;
    USE SIGNAL ;
    PORT
      LAYER M4 ;
        RECT 725.568 341.088 725.760 341.112 ;
    END
  END tx[90]
  PIN tx[91]
    DIRECTION OUTPUT ;
    USE SIGNAL ;
    PORT
      LAYER M4 ;
        RECT 725.568 341.664 725.760 341.688 ;
    END
  END tx[91]
  PIN tx[92]
    DIRECTION OUTPUT ;
    USE SIGNAL ;
    PORT
      LAYER M4 ;
        RECT 725.568 342.192 725.760 342.216 ;
    END
  END tx[92]
  PIN tx[93]
    DIRECTION OUTPUT ;
    USE SIGNAL ;
    PORT
      LAYER M4 ;
        RECT 725.568 342.768 725.760 342.792 ;
    END
  END tx[93]
  PIN tx[94]
    DIRECTION OUTPUT ;
    USE SIGNAL ;
    PORT
      LAYER M4 ;
        RECT 725.568 343.344 725.760 343.368 ;
    END
  END tx[94]
  PIN tx[95]
    DIRECTION OUTPUT ;
    USE SIGNAL ;
    PORT
      LAYER M4 ;
        RECT 725.568 343.872 725.760 343.896 ;
    END
  END tx[95]
  PIN tx[96]
    DIRECTION OUTPUT ;
    USE SIGNAL ;
    PORT
      LAYER M4 ;
        RECT 725.568 344.448 725.760 344.472 ;
    END
  END tx[96]
  PIN tx[97]
    DIRECTION OUTPUT ;
    USE SIGNAL ;
    PORT
      LAYER M4 ;
        RECT 725.568 345.024 725.760 345.048 ;
    END
  END tx[97]
  PIN tx[98]
    DIRECTION OUTPUT ;
    USE SIGNAL ;
    PORT
      LAYER M4 ;
        RECT 725.568 345.552 725.760 345.576 ;
    END
  END tx[98]
  PIN tx[99]
    DIRECTION OUTPUT ;
    USE SIGNAL ;
    PORT
      LAYER M4 ;
        RECT 725.568 346.128 725.760 346.152 ;
    END
  END tx[99]
  PIN tx[100]
    DIRECTION OUTPUT ;
    USE SIGNAL ;
    PORT
      LAYER M4 ;
        RECT 725.568 346.704 725.760 346.728 ;
    END
  END tx[100]
  PIN tx[101]
    DIRECTION OUTPUT ;
    USE SIGNAL ;
    PORT
      LAYER M4 ;
        RECT 725.568 347.232 725.760 347.256 ;
    END
  END tx[101]
  PIN tx[102]
    DIRECTION OUTPUT ;
    USE SIGNAL ;
    PORT
      LAYER M4 ;
        RECT 725.568 347.808 725.760 347.832 ;
    END
  END tx[102]
  PIN tx[103]
    DIRECTION OUTPUT ;
    USE SIGNAL ;
    PORT
      LAYER M4 ;
        RECT 725.568 348.384 725.760 348.408 ;
    END
  END tx[103]
  PIN tx[104]
    DIRECTION OUTPUT ;
    USE SIGNAL ;
    PORT
      LAYER M4 ;
        RECT 725.568 348.912 725.760 348.936 ;
    END
  END tx[104]
  PIN tx[105]
    DIRECTION OUTPUT ;
    USE SIGNAL ;
    PORT
      LAYER M4 ;
        RECT 725.568 349.488 725.760 349.512 ;
    END
  END tx[105]
  PIN tx[106]
    DIRECTION OUTPUT ;
    USE SIGNAL ;
    PORT
      LAYER M4 ;
        RECT 725.568 350.016 725.760 350.040 ;
    END
  END tx[106]
  PIN tx[107]
    DIRECTION OUTPUT ;
    USE SIGNAL ;
    PORT
      LAYER M4 ;
        RECT 725.568 350.592 725.760 350.616 ;
    END
  END tx[107]
  PIN tx[108]
    DIRECTION OUTPUT ;
    USE SIGNAL ;
    PORT
      LAYER M4 ;
        RECT 725.568 351.168 725.760 351.192 ;
    END
  END tx[108]
  PIN tx[109]
    DIRECTION OUTPUT ;
    USE SIGNAL ;
    PORT
      LAYER M4 ;
        RECT 725.568 351.696 725.760 351.720 ;
    END
  END tx[109]
  PIN tx[110]
    DIRECTION OUTPUT ;
    USE SIGNAL ;
    PORT
      LAYER M4 ;
        RECT 725.568 352.272 725.760 352.296 ;
    END
  END tx[110]
  PIN tx[111]
    DIRECTION OUTPUT ;
    USE SIGNAL ;
    PORT
      LAYER M4 ;
        RECT 725.568 352.848 725.760 352.872 ;
    END
  END tx[111]
  PIN tx[112]
    DIRECTION OUTPUT ;
    USE SIGNAL ;
    PORT
      LAYER M4 ;
        RECT 725.568 353.376 725.760 353.400 ;
    END
  END tx[112]
  PIN tx[113]
    DIRECTION OUTPUT ;
    USE SIGNAL ;
    PORT
      LAYER M4 ;
        RECT 725.568 353.952 725.760 353.976 ;
    END
  END tx[113]
  PIN tx[114]
    DIRECTION OUTPUT ;
    USE SIGNAL ;
    PORT
      LAYER M4 ;
        RECT 725.568 354.528 725.760 354.552 ;
    END
  END tx[114]
  PIN tx[115]
    DIRECTION OUTPUT ;
    USE SIGNAL ;
    PORT
      LAYER M4 ;
        RECT 725.568 355.056 725.760 355.080 ;
    END
  END tx[115]
  PIN tx[116]
    DIRECTION OUTPUT ;
    USE SIGNAL ;
    PORT
      LAYER M4 ;
        RECT 725.568 355.632 725.760 355.656 ;
    END
  END tx[116]
  PIN tx[117]
    DIRECTION OUTPUT ;
    USE SIGNAL ;
    PORT
      LAYER M4 ;
        RECT 725.568 356.208 725.760 356.232 ;
    END
  END tx[117]
  PIN tx[118]
    DIRECTION OUTPUT ;
    USE SIGNAL ;
    PORT
      LAYER M4 ;
        RECT 725.568 356.736 725.760 356.760 ;
    END
  END tx[118]
  PIN tx[119]
    DIRECTION OUTPUT ;
    USE SIGNAL ;
    PORT
      LAYER M4 ;
        RECT 725.568 357.312 725.760 357.336 ;
    END
  END tx[119]
  PIN tx[120]
    DIRECTION OUTPUT ;
    USE SIGNAL ;
    PORT
      LAYER M4 ;
        RECT 725.568 357.888 725.760 357.912 ;
    END
  END tx[120]
  PIN tx[121]
    DIRECTION OUTPUT ;
    USE SIGNAL ;
    PORT
      LAYER M4 ;
        RECT 725.568 358.416 725.760 358.440 ;
    END
  END tx[121]
  PIN tx[122]
    DIRECTION OUTPUT ;
    USE SIGNAL ;
    PORT
      LAYER M4 ;
        RECT 725.568 358.992 725.760 359.016 ;
    END
  END tx[122]
  PIN tx[123]
    DIRECTION OUTPUT ;
    USE SIGNAL ;
    PORT
      LAYER M4 ;
        RECT 725.568 359.520 725.760 359.544 ;
    END
  END tx[123]
  PIN tx[124]
    DIRECTION OUTPUT ;
    USE SIGNAL ;
    PORT
      LAYER M4 ;
        RECT 725.568 360.096 725.760 360.120 ;
    END
  END tx[124]
  PIN tx[125]
    DIRECTION OUTPUT ;
    USE SIGNAL ;
    PORT
      LAYER M4 ;
        RECT 725.568 360.672 725.760 360.696 ;
    END
  END tx[125]
  PIN tx[126]
    DIRECTION OUTPUT ;
    USE SIGNAL ;
    PORT
      LAYER M4 ;
        RECT 725.568 361.200 725.760 361.224 ;
    END
  END tx[126]
  PIN tx[127]
    DIRECTION OUTPUT ;
    USE SIGNAL ;
    PORT
      LAYER M4 ;
        RECT 725.568 361.776 725.760 361.800 ;
    END
  END tx[127]
  PIN tx[128]
    DIRECTION OUTPUT ;
    USE SIGNAL ;
    PORT
      LAYER M4 ;
        RECT 725.568 362.352 725.760 362.376 ;
    END
  END tx[128]
  PIN tx[129]
    DIRECTION OUTPUT ;
    USE SIGNAL ;
    PORT
      LAYER M4 ;
        RECT 725.568 362.880 725.760 362.904 ;
    END
  END tx[129]
  PIN tx[130]
    DIRECTION OUTPUT ;
    USE SIGNAL ;
    PORT
      LAYER M4 ;
        RECT 725.568 363.456 725.760 363.480 ;
    END
  END tx[130]
  PIN tx[131]
    DIRECTION OUTPUT ;
    USE SIGNAL ;
    PORT
      LAYER M4 ;
        RECT 725.568 364.032 725.760 364.056 ;
    END
  END tx[131]
  PIN tx[132]
    DIRECTION OUTPUT ;
    USE SIGNAL ;
    PORT
      LAYER M4 ;
        RECT 725.568 364.560 725.760 364.584 ;
    END
  END tx[132]
  PIN tx[133]
    DIRECTION OUTPUT ;
    USE SIGNAL ;
    PORT
      LAYER M4 ;
        RECT 725.568 365.136 725.760 365.160 ;
    END
  END tx[133]
  PIN tx[134]
    DIRECTION OUTPUT ;
    USE SIGNAL ;
    PORT
      LAYER M4 ;
        RECT 725.568 365.712 725.760 365.736 ;
    END
  END tx[134]
  PIN tx[135]
    DIRECTION OUTPUT ;
    USE SIGNAL ;
    PORT
      LAYER M4 ;
        RECT 725.568 366.240 725.760 366.264 ;
    END
  END tx[135]
  PIN tx[136]
    DIRECTION OUTPUT ;
    USE SIGNAL ;
    PORT
      LAYER M4 ;
        RECT 725.568 366.816 725.760 366.840 ;
    END
  END tx[136]
  PIN tx[137]
    DIRECTION OUTPUT ;
    USE SIGNAL ;
    PORT
      LAYER M4 ;
        RECT 725.568 367.392 725.760 367.416 ;
    END
  END tx[137]
  PIN tx[138]
    DIRECTION OUTPUT ;
    USE SIGNAL ;
    PORT
      LAYER M4 ;
        RECT 725.568 367.920 725.760 367.944 ;
    END
  END tx[138]
  PIN tx[139]
    DIRECTION OUTPUT ;
    USE SIGNAL ;
    PORT
      LAYER M4 ;
        RECT 725.568 368.496 725.760 368.520 ;
    END
  END tx[139]
  PIN tx[140]
    DIRECTION OUTPUT ;
    USE SIGNAL ;
    PORT
      LAYER M4 ;
        RECT 725.568 369.024 725.760 369.048 ;
    END
  END tx[140]
  PIN tx[141]
    DIRECTION OUTPUT ;
    USE SIGNAL ;
    PORT
      LAYER M4 ;
        RECT 725.568 369.600 725.760 369.624 ;
    END
  END tx[141]
  PIN tx[142]
    DIRECTION OUTPUT ;
    USE SIGNAL ;
    PORT
      LAYER M4 ;
        RECT 725.568 370.176 725.760 370.200 ;
    END
  END tx[142]
  PIN tx[143]
    DIRECTION OUTPUT ;
    USE SIGNAL ;
    PORT
      LAYER M4 ;
        RECT 725.568 370.704 725.760 370.728 ;
    END
  END tx[143]
  PIN tx[144]
    DIRECTION OUTPUT ;
    USE SIGNAL ;
    PORT
      LAYER M4 ;
        RECT 725.568 371.280 725.760 371.304 ;
    END
  END tx[144]
  PIN tx[145]
    DIRECTION OUTPUT ;
    USE SIGNAL ;
    PORT
      LAYER M4 ;
        RECT 725.568 371.856 725.760 371.880 ;
    END
  END tx[145]
  PIN tx[146]
    DIRECTION OUTPUT ;
    USE SIGNAL ;
    PORT
      LAYER M4 ;
        RECT 725.568 372.384 725.760 372.408 ;
    END
  END tx[146]
  PIN tx[147]
    DIRECTION OUTPUT ;
    USE SIGNAL ;
    PORT
      LAYER M4 ;
        RECT 725.568 372.960 725.760 372.984 ;
    END
  END tx[147]
  PIN tx[148]
    DIRECTION OUTPUT ;
    USE SIGNAL ;
    PORT
      LAYER M4 ;
        RECT 725.568 373.536 725.760 373.560 ;
    END
  END tx[148]
  PIN tx[149]
    DIRECTION OUTPUT ;
    USE SIGNAL ;
    PORT
      LAYER M4 ;
        RECT 725.568 374.064 725.760 374.088 ;
    END
  END tx[149]
  PIN tx[150]
    DIRECTION OUTPUT ;
    USE SIGNAL ;
    PORT
      LAYER M4 ;
        RECT 725.568 374.640 725.760 374.664 ;
    END
  END tx[150]
  PIN tx[151]
    DIRECTION OUTPUT ;
    USE SIGNAL ;
    PORT
      LAYER M4 ;
        RECT 725.568 375.216 725.760 375.240 ;
    END
  END tx[151]
  PIN tx[152]
    DIRECTION OUTPUT ;
    USE SIGNAL ;
    PORT
      LAYER M4 ;
        RECT 725.568 375.744 725.760 375.768 ;
    END
  END tx[152]
  PIN tx[153]
    DIRECTION OUTPUT ;
    USE SIGNAL ;
    PORT
      LAYER M4 ;
        RECT 725.568 376.320 725.760 376.344 ;
    END
  END tx[153]
  PIN tx[154]
    DIRECTION OUTPUT ;
    USE SIGNAL ;
    PORT
      LAYER M4 ;
        RECT 725.568 376.848 725.760 376.872 ;
    END
  END tx[154]
  PIN tx[155]
    DIRECTION OUTPUT ;
    USE SIGNAL ;
    PORT
      LAYER M4 ;
        RECT 725.568 377.424 725.760 377.448 ;
    END
  END tx[155]
  PIN tx[156]
    DIRECTION OUTPUT ;
    USE SIGNAL ;
    PORT
      LAYER M4 ;
        RECT 725.568 378.000 725.760 378.024 ;
    END
  END tx[156]
  PIN tx[157]
    DIRECTION OUTPUT ;
    USE SIGNAL ;
    PORT
      LAYER M4 ;
        RECT 725.568 378.528 725.760 378.552 ;
    END
  END tx[157]
  PIN tx[158]
    DIRECTION OUTPUT ;
    USE SIGNAL ;
    PORT
      LAYER M4 ;
        RECT 725.568 379.104 725.760 379.128 ;
    END
  END tx[158]
  PIN tx[159]
    DIRECTION OUTPUT ;
    USE SIGNAL ;
    PORT
      LAYER M4 ;
        RECT 725.568 379.680 725.760 379.704 ;
    END
  END tx[159]
  PIN tx[160]
    DIRECTION OUTPUT ;
    USE SIGNAL ;
    PORT
      LAYER M4 ;
        RECT 725.568 380.208 725.760 380.232 ;
    END
  END tx[160]
  PIN tx[161]
    DIRECTION OUTPUT ;
    USE SIGNAL ;
    PORT
      LAYER M4 ;
        RECT 725.568 380.784 725.760 380.808 ;
    END
  END tx[161]
  PIN tx[162]
    DIRECTION OUTPUT ;
    USE SIGNAL ;
    PORT
      LAYER M4 ;
        RECT 725.568 381.360 725.760 381.384 ;
    END
  END tx[162]
  PIN tx[163]
    DIRECTION OUTPUT ;
    USE SIGNAL ;
    PORT
      LAYER M4 ;
        RECT 725.568 381.888 725.760 381.912 ;
    END
  END tx[163]
  PIN tx[164]
    DIRECTION OUTPUT ;
    USE SIGNAL ;
    PORT
      LAYER M4 ;
        RECT 725.568 382.464 725.760 382.488 ;
    END
  END tx[164]
  PIN tx[165]
    DIRECTION OUTPUT ;
    USE SIGNAL ;
    PORT
      LAYER M4 ;
        RECT 725.568 383.040 725.760 383.064 ;
    END
  END tx[165]
  PIN tx[166]
    DIRECTION OUTPUT ;
    USE SIGNAL ;
    PORT
      LAYER M4 ;
        RECT 725.568 383.568 725.760 383.592 ;
    END
  END tx[166]
  PIN tx[167]
    DIRECTION OUTPUT ;
    USE SIGNAL ;
    PORT
      LAYER M4 ;
        RECT 725.568 384.144 725.760 384.168 ;
    END
  END tx[167]
  PIN tx[168]
    DIRECTION OUTPUT ;
    USE SIGNAL ;
    PORT
      LAYER M4 ;
        RECT 725.568 384.720 725.760 384.744 ;
    END
  END tx[168]
  PIN tx[169]
    DIRECTION OUTPUT ;
    USE SIGNAL ;
    PORT
      LAYER M4 ;
        RECT 725.568 385.248 725.760 385.272 ;
    END
  END tx[169]
  PIN tx[170]
    DIRECTION OUTPUT ;
    USE SIGNAL ;
    PORT
      LAYER M4 ;
        RECT 725.568 385.824 725.760 385.848 ;
    END
  END tx[170]
  PIN tx[171]
    DIRECTION OUTPUT ;
    USE SIGNAL ;
    PORT
      LAYER M4 ;
        RECT 725.568 386.352 725.760 386.376 ;
    END
  END tx[171]
  PIN tx[172]
    DIRECTION OUTPUT ;
    USE SIGNAL ;
    PORT
      LAYER M4 ;
        RECT 725.568 386.928 725.760 386.952 ;
    END
  END tx[172]
  PIN tx[173]
    DIRECTION OUTPUT ;
    USE SIGNAL ;
    PORT
      LAYER M4 ;
        RECT 725.568 387.504 725.760 387.528 ;
    END
  END tx[173]
  PIN tx[174]
    DIRECTION OUTPUT ;
    USE SIGNAL ;
    PORT
      LAYER M4 ;
        RECT 725.568 388.032 725.760 388.056 ;
    END
  END tx[174]
  PIN tx[175]
    DIRECTION OUTPUT ;
    USE SIGNAL ;
    PORT
      LAYER M4 ;
        RECT 725.568 388.608 725.760 388.632 ;
    END
  END tx[175]
  PIN tx[176]
    DIRECTION OUTPUT ;
    USE SIGNAL ;
    PORT
      LAYER M4 ;
        RECT 725.568 389.184 725.760 389.208 ;
    END
  END tx[176]
  PIN tx[177]
    DIRECTION OUTPUT ;
    USE SIGNAL ;
    PORT
      LAYER M4 ;
        RECT 725.568 389.712 725.760 389.736 ;
    END
  END tx[177]
  PIN tx[178]
    DIRECTION OUTPUT ;
    USE SIGNAL ;
    PORT
      LAYER M4 ;
        RECT 725.568 390.288 725.760 390.312 ;
    END
  END tx[178]
  PIN tx[179]
    DIRECTION OUTPUT ;
    USE SIGNAL ;
    PORT
      LAYER M4 ;
        RECT 725.568 390.864 725.760 390.888 ;
    END
  END tx[179]
  PIN tx[180]
    DIRECTION OUTPUT ;
    USE SIGNAL ;
    PORT
      LAYER M4 ;
        RECT 725.568 391.392 725.760 391.416 ;
    END
  END tx[180]
  PIN tx[181]
    DIRECTION OUTPUT ;
    USE SIGNAL ;
    PORT
      LAYER M4 ;
        RECT 725.568 391.968 725.760 391.992 ;
    END
  END tx[181]
  PIN tx[182]
    DIRECTION OUTPUT ;
    USE SIGNAL ;
    PORT
      LAYER M4 ;
        RECT 725.568 392.544 725.760 392.568 ;
    END
  END tx[182]
  PIN tx[183]
    DIRECTION OUTPUT ;
    USE SIGNAL ;
    PORT
      LAYER M4 ;
        RECT 725.568 393.072 725.760 393.096 ;
    END
  END tx[183]
  PIN tx[184]
    DIRECTION OUTPUT ;
    USE SIGNAL ;
    PORT
      LAYER M4 ;
        RECT 725.568 393.648 725.760 393.672 ;
    END
  END tx[184]
  PIN tx[185]
    DIRECTION OUTPUT ;
    USE SIGNAL ;
    PORT
      LAYER M4 ;
        RECT 725.568 394.176 725.760 394.200 ;
    END
  END tx[185]
  PIN tx[186]
    DIRECTION OUTPUT ;
    USE SIGNAL ;
    PORT
      LAYER M4 ;
        RECT 725.568 394.752 725.760 394.776 ;
    END
  END tx[186]
  PIN tx[187]
    DIRECTION OUTPUT ;
    USE SIGNAL ;
    PORT
      LAYER M4 ;
        RECT 725.568 395.328 725.760 395.352 ;
    END
  END tx[187]
  PIN tx[188]
    DIRECTION OUTPUT ;
    USE SIGNAL ;
    PORT
      LAYER M4 ;
        RECT 725.568 395.856 725.760 395.880 ;
    END
  END tx[188]
  PIN tx[189]
    DIRECTION OUTPUT ;
    USE SIGNAL ;
    PORT
      LAYER M4 ;
        RECT 725.568 396.432 725.760 396.456 ;
    END
  END tx[189]
  PIN tx[190]
    DIRECTION OUTPUT ;
    USE SIGNAL ;
    PORT
      LAYER M4 ;
        RECT 725.568 397.008 725.760 397.032 ;
    END
  END tx[190]
  PIN tx[191]
    DIRECTION OUTPUT ;
    USE SIGNAL ;
    PORT
      LAYER M4 ;
        RECT 725.568 397.536 725.760 397.560 ;
    END
  END tx[191]
  PIN tx[192]
    DIRECTION OUTPUT ;
    USE SIGNAL ;
    PORT
      LAYER M4 ;
        RECT 725.568 398.112 725.760 398.136 ;
    END
  END tx[192]
  PIN tx[193]
    DIRECTION OUTPUT ;
    USE SIGNAL ;
    PORT
      LAYER M4 ;
        RECT 725.568 398.688 725.760 398.712 ;
    END
  END tx[193]
  PIN tx[194]
    DIRECTION OUTPUT ;
    USE SIGNAL ;
    PORT
      LAYER M4 ;
        RECT 725.568 399.216 725.760 399.240 ;
    END
  END tx[194]
  PIN tx[195]
    DIRECTION OUTPUT ;
    USE SIGNAL ;
    PORT
      LAYER M4 ;
        RECT 725.568 399.792 725.760 399.816 ;
    END
  END tx[195]
  PIN tx[196]
    DIRECTION OUTPUT ;
    USE SIGNAL ;
    PORT
      LAYER M4 ;
        RECT 725.568 400.368 725.760 400.392 ;
    END
  END tx[196]
  PIN tx[197]
    DIRECTION OUTPUT ;
    USE SIGNAL ;
    PORT
      LAYER M4 ;
        RECT 725.568 400.896 725.760 400.920 ;
    END
  END tx[197]
  PIN tx[198]
    DIRECTION OUTPUT ;
    USE SIGNAL ;
    PORT
      LAYER M4 ;
        RECT 725.568 401.472 725.760 401.496 ;
    END
  END tx[198]
  PIN tx[199]
    DIRECTION OUTPUT ;
    USE SIGNAL ;
    PORT
      LAYER M4 ;
        RECT 725.568 402.048 725.760 402.072 ;
    END
  END tx[199]
  PIN tx[200]
    DIRECTION OUTPUT ;
    USE SIGNAL ;
    PORT
      LAYER M4 ;
        RECT 725.568 402.576 725.760 402.600 ;
    END
  END tx[200]
  PIN tx[201]
    DIRECTION OUTPUT ;
    USE SIGNAL ;
    PORT
      LAYER M4 ;
        RECT 725.568 403.152 725.760 403.176 ;
    END
  END tx[201]
  PIN tx[202]
    DIRECTION OUTPUT ;
    USE SIGNAL ;
    PORT
      LAYER M4 ;
        RECT 725.568 403.680 725.760 403.704 ;
    END
  END tx[202]
  PIN tx[203]
    DIRECTION OUTPUT ;
    USE SIGNAL ;
    PORT
      LAYER M4 ;
        RECT 725.568 404.256 725.760 404.280 ;
    END
  END tx[203]
  PIN tx[204]
    DIRECTION OUTPUT ;
    USE SIGNAL ;
    PORT
      LAYER M4 ;
        RECT 725.568 404.832 725.760 404.856 ;
    END
  END tx[204]
  PIN tx[205]
    DIRECTION OUTPUT ;
    USE SIGNAL ;
    PORT
      LAYER M4 ;
        RECT 725.568 405.360 725.760 405.384 ;
    END
  END tx[205]
  PIN tx[206]
    DIRECTION OUTPUT ;
    USE SIGNAL ;
    PORT
      LAYER M4 ;
        RECT 725.568 405.936 725.760 405.960 ;
    END
  END tx[206]
  PIN tx[207]
    DIRECTION OUTPUT ;
    USE SIGNAL ;
    PORT
      LAYER M4 ;
        RECT 725.568 406.512 725.760 406.536 ;
    END
  END tx[207]
  PIN tx[208]
    DIRECTION OUTPUT ;
    USE SIGNAL ;
    PORT
      LAYER M4 ;
        RECT 725.568 407.040 725.760 407.064 ;
    END
  END tx[208]
  PIN tx[209]
    DIRECTION OUTPUT ;
    USE SIGNAL ;
    PORT
      LAYER M4 ;
        RECT 725.568 407.616 725.760 407.640 ;
    END
  END tx[209]
  PIN tx[210]
    DIRECTION OUTPUT ;
    USE SIGNAL ;
    PORT
      LAYER M4 ;
        RECT 725.568 408.192 725.760 408.216 ;
    END
  END tx[210]
  PIN tx[211]
    DIRECTION OUTPUT ;
    USE SIGNAL ;
    PORT
      LAYER M4 ;
        RECT 725.568 408.720 725.760 408.744 ;
    END
  END tx[211]
  PIN tx[212]
    DIRECTION OUTPUT ;
    USE SIGNAL ;
    PORT
      LAYER M4 ;
        RECT 725.568 409.296 725.760 409.320 ;
    END
  END tx[212]
  PIN tx[213]
    DIRECTION OUTPUT ;
    USE SIGNAL ;
    PORT
      LAYER M4 ;
        RECT 725.568 409.872 725.760 409.896 ;
    END
  END tx[213]
  PIN tx[214]
    DIRECTION OUTPUT ;
    USE SIGNAL ;
    PORT
      LAYER M4 ;
        RECT 725.568 410.400 725.760 410.424 ;
    END
  END tx[214]
  PIN tx[215]
    DIRECTION OUTPUT ;
    USE SIGNAL ;
    PORT
      LAYER M4 ;
        RECT 725.568 410.976 725.760 411.000 ;
    END
  END tx[215]
  PIN tx[216]
    DIRECTION OUTPUT ;
    USE SIGNAL ;
    PORT
      LAYER M4 ;
        RECT 725.568 411.552 725.760 411.576 ;
    END
  END tx[216]
  PIN tx[217]
    DIRECTION OUTPUT ;
    USE SIGNAL ;
    PORT
      LAYER M4 ;
        RECT 725.568 412.080 725.760 412.104 ;
    END
  END tx[217]
  PIN tx[218]
    DIRECTION OUTPUT ;
    USE SIGNAL ;
    PORT
      LAYER M4 ;
        RECT 725.568 412.656 725.760 412.680 ;
    END
  END tx[218]
  PIN tx[219]
    DIRECTION OUTPUT ;
    USE SIGNAL ;
    PORT
      LAYER M4 ;
        RECT 725.568 413.184 725.760 413.208 ;
    END
  END tx[219]
  PIN tx[220]
    DIRECTION OUTPUT ;
    USE SIGNAL ;
    PORT
      LAYER M4 ;
        RECT 725.568 413.760 725.760 413.784 ;
    END
  END tx[220]
  PIN tx[221]
    DIRECTION OUTPUT ;
    USE SIGNAL ;
    PORT
      LAYER M4 ;
        RECT 725.568 414.336 725.760 414.360 ;
    END
  END tx[221]
  PIN tx[222]
    DIRECTION OUTPUT ;
    USE SIGNAL ;
    PORT
      LAYER M4 ;
        RECT 725.568 414.864 725.760 414.888 ;
    END
  END tx[222]
  PIN tx[223]
    DIRECTION OUTPUT ;
    USE SIGNAL ;
    PORT
      LAYER M4 ;
        RECT 725.568 415.440 725.760 415.464 ;
    END
  END tx[223]
  PIN tx[224]
    DIRECTION OUTPUT ;
    USE SIGNAL ;
    PORT
      LAYER M4 ;
        RECT 725.568 416.016 725.760 416.040 ;
    END
  END tx[224]
  PIN tx[225]
    DIRECTION OUTPUT ;
    USE SIGNAL ;
    PORT
      LAYER M4 ;
        RECT 725.568 416.544 725.760 416.568 ;
    END
  END tx[225]
  PIN tx[226]
    DIRECTION OUTPUT ;
    USE SIGNAL ;
    PORT
      LAYER M4 ;
        RECT 725.568 417.120 725.760 417.144 ;
    END
  END tx[226]
  PIN tx[227]
    DIRECTION OUTPUT ;
    USE SIGNAL ;
    PORT
      LAYER M4 ;
        RECT 725.568 417.696 725.760 417.720 ;
    END
  END tx[227]
  PIN tx[228]
    DIRECTION OUTPUT ;
    USE SIGNAL ;
    PORT
      LAYER M4 ;
        RECT 725.568 418.224 725.760 418.248 ;
    END
  END tx[228]
  PIN tx[229]
    DIRECTION OUTPUT ;
    USE SIGNAL ;
    PORT
      LAYER M4 ;
        RECT 725.568 418.800 725.760 418.824 ;
    END
  END tx[229]
  PIN tx[230]
    DIRECTION OUTPUT ;
    USE SIGNAL ;
    PORT
      LAYER M4 ;
        RECT 725.568 419.376 725.760 419.400 ;
    END
  END tx[230]
  PIN tx[231]
    DIRECTION OUTPUT ;
    USE SIGNAL ;
    PORT
      LAYER M4 ;
        RECT 725.568 419.904 725.760 419.928 ;
    END
  END tx[231]
  PIN tx[232]
    DIRECTION OUTPUT ;
    USE SIGNAL ;
    PORT
      LAYER M4 ;
        RECT 725.568 420.480 725.760 420.504 ;
    END
  END tx[232]
  PIN tx[233]
    DIRECTION OUTPUT ;
    USE SIGNAL ;
    PORT
      LAYER M4 ;
        RECT 725.568 421.008 725.760 421.032 ;
    END
  END tx[233]
  PIN tx[234]
    DIRECTION OUTPUT ;
    USE SIGNAL ;
    PORT
      LAYER M4 ;
        RECT 725.568 421.584 725.760 421.608 ;
    END
  END tx[234]
  PIN tx[235]
    DIRECTION OUTPUT ;
    USE SIGNAL ;
    PORT
      LAYER M4 ;
        RECT 725.568 422.160 725.760 422.184 ;
    END
  END tx[235]
  PIN tx[236]
    DIRECTION OUTPUT ;
    USE SIGNAL ;
    PORT
      LAYER M4 ;
        RECT 725.568 422.688 725.760 422.712 ;
    END
  END tx[236]
  PIN tx[237]
    DIRECTION OUTPUT ;
    USE SIGNAL ;
    PORT
      LAYER M4 ;
        RECT 725.568 423.264 725.760 423.288 ;
    END
  END tx[237]
  PIN tx[238]
    DIRECTION OUTPUT ;
    USE SIGNAL ;
    PORT
      LAYER M4 ;
        RECT 725.568 423.840 725.760 423.864 ;
    END
  END tx[238]
  PIN tx[239]
    DIRECTION OUTPUT ;
    USE SIGNAL ;
    PORT
      LAYER M4 ;
        RECT 725.568 424.368 725.760 424.392 ;
    END
  END tx[239]
  PIN tx[240]
    DIRECTION OUTPUT ;
    USE SIGNAL ;
    PORT
      LAYER M4 ;
        RECT 725.568 424.944 725.760 424.968 ;
    END
  END tx[240]
  PIN tx[241]
    DIRECTION OUTPUT ;
    USE SIGNAL ;
    PORT
      LAYER M4 ;
        RECT 725.568 425.520 725.760 425.544 ;
    END
  END tx[241]
  PIN tx[242]
    DIRECTION OUTPUT ;
    USE SIGNAL ;
    PORT
      LAYER M4 ;
        RECT 725.568 426.048 725.760 426.072 ;
    END
  END tx[242]
  PIN tx[243]
    DIRECTION OUTPUT ;
    USE SIGNAL ;
    PORT
      LAYER M4 ;
        RECT 725.568 426.624 725.760 426.648 ;
    END
  END tx[243]
  PIN tx[244]
    DIRECTION OUTPUT ;
    USE SIGNAL ;
    PORT
      LAYER M4 ;
        RECT 725.568 427.200 725.760 427.224 ;
    END
  END tx[244]
  PIN tx[245]
    DIRECTION OUTPUT ;
    USE SIGNAL ;
    PORT
      LAYER M4 ;
        RECT 725.568 427.728 725.760 427.752 ;
    END
  END tx[245]
  PIN tx[246]
    DIRECTION OUTPUT ;
    USE SIGNAL ;
    PORT
      LAYER M4 ;
        RECT 725.568 428.304 725.760 428.328 ;
    END
  END tx[246]
  PIN tx[247]
    DIRECTION OUTPUT ;
    USE SIGNAL ;
    PORT
      LAYER M4 ;
        RECT 725.568 428.880 725.760 428.904 ;
    END
  END tx[247]
  PIN tx[248]
    DIRECTION OUTPUT ;
    USE SIGNAL ;
    PORT
      LAYER M4 ;
        RECT 725.568 429.408 725.760 429.432 ;
    END
  END tx[248]
  PIN tx[249]
    DIRECTION OUTPUT ;
    USE SIGNAL ;
    PORT
      LAYER M4 ;
        RECT 725.568 429.984 725.760 430.008 ;
    END
  END tx[249]
  PIN tx[250]
    DIRECTION OUTPUT ;
    USE SIGNAL ;
    PORT
      LAYER M4 ;
        RECT 725.568 430.512 725.760 430.536 ;
    END
  END tx[250]
  PIN tx[251]
    DIRECTION OUTPUT ;
    USE SIGNAL ;
    PORT
      LAYER M4 ;
        RECT 725.568 431.088 725.760 431.112 ;
    END
  END tx[251]
  PIN tx[252]
    DIRECTION OUTPUT ;
    USE SIGNAL ;
    PORT
      LAYER M4 ;
        RECT 725.568 431.664 725.760 431.688 ;
    END
  END tx[252]
  PIN tx[253]
    DIRECTION OUTPUT ;
    USE SIGNAL ;
    PORT
      LAYER M4 ;
        RECT 725.568 432.192 725.760 432.216 ;
    END
  END tx[253]
  PIN tx[254]
    DIRECTION OUTPUT ;
    USE SIGNAL ;
    PORT
      LAYER M4 ;
        RECT 725.568 432.768 725.760 432.792 ;
    END
  END tx[254]
  PIN tx[255]
    DIRECTION OUTPUT ;
    USE SIGNAL ;
    PORT
      LAYER M4 ;
        RECT 725.568 433.344 725.760 433.368 ;
    END
  END tx[255]
  PIN tx[256]
    DIRECTION OUTPUT ;
    USE SIGNAL ;
    PORT
      LAYER M4 ;
        RECT 725.568 433.872 725.760 433.896 ;
    END
  END tx[256]
  PIN tx[257]
    DIRECTION OUTPUT ;
    USE SIGNAL ;
    PORT
      LAYER M4 ;
        RECT 725.568 434.448 725.760 434.472 ;
    END
  END tx[257]
  PIN tx[258]
    DIRECTION OUTPUT ;
    USE SIGNAL ;
    PORT
      LAYER M4 ;
        RECT 725.568 435.024 725.760 435.048 ;
    END
  END tx[258]
  PIN tx[259]
    DIRECTION OUTPUT ;
    USE SIGNAL ;
    PORT
      LAYER M4 ;
        RECT 725.568 435.552 725.760 435.576 ;
    END
  END tx[259]
  PIN tx[260]
    DIRECTION OUTPUT ;
    USE SIGNAL ;
    PORT
      LAYER M4 ;
        RECT 725.568 436.128 725.760 436.152 ;
    END
  END tx[260]
  PIN tx[261]
    DIRECTION OUTPUT ;
    USE SIGNAL ;
    PORT
      LAYER M4 ;
        RECT 725.568 436.704 725.760 436.728 ;
    END
  END tx[261]
  PIN tx[262]
    DIRECTION OUTPUT ;
    USE SIGNAL ;
    PORT
      LAYER M4 ;
        RECT 725.568 437.232 725.760 437.256 ;
    END
  END tx[262]
  PIN tx[263]
    DIRECTION OUTPUT ;
    USE SIGNAL ;
    PORT
      LAYER M4 ;
        RECT 725.568 437.808 725.760 437.832 ;
    END
  END tx[263]
  PIN tx[264]
    DIRECTION OUTPUT ;
    USE SIGNAL ;
    PORT
      LAYER M4 ;
        RECT 725.568 438.336 725.760 438.360 ;
    END
  END tx[264]
  PIN tx[265]
    DIRECTION OUTPUT ;
    USE SIGNAL ;
    PORT
      LAYER M4 ;
        RECT 725.568 438.912 725.760 438.936 ;
    END
  END tx[265]
  PIN tx[266]
    DIRECTION OUTPUT ;
    USE SIGNAL ;
    PORT
      LAYER M4 ;
        RECT 725.568 439.488 725.760 439.512 ;
    END
  END tx[266]
  PIN tx[267]
    DIRECTION OUTPUT ;
    USE SIGNAL ;
    PORT
      LAYER M4 ;
        RECT 725.568 440.016 725.760 440.040 ;
    END
  END tx[267]
  PIN tx[268]
    DIRECTION OUTPUT ;
    USE SIGNAL ;
    PORT
      LAYER M4 ;
        RECT 725.568 440.592 725.760 440.616 ;
    END
  END tx[268]
  PIN tx[269]
    DIRECTION OUTPUT ;
    USE SIGNAL ;
    PORT
      LAYER M4 ;
        RECT 725.568 441.168 725.760 441.192 ;
    END
  END tx[269]
  PIN tx[270]
    DIRECTION OUTPUT ;
    USE SIGNAL ;
    PORT
      LAYER M4 ;
        RECT 725.568 441.696 725.760 441.720 ;
    END
  END tx[270]
  PIN tx[271]
    DIRECTION OUTPUT ;
    USE SIGNAL ;
    PORT
      LAYER M4 ;
        RECT 725.568 442.272 725.760 442.296 ;
    END
  END tx[271]
  PIN tx[272]
    DIRECTION OUTPUT ;
    USE SIGNAL ;
    PORT
      LAYER M4 ;
        RECT 725.568 442.848 725.760 442.872 ;
    END
  END tx[272]
  PIN tx[273]
    DIRECTION OUTPUT ;
    USE SIGNAL ;
    PORT
      LAYER M4 ;
        RECT 725.568 443.376 725.760 443.400 ;
    END
  END tx[273]
  PIN tx[274]
    DIRECTION OUTPUT ;
    USE SIGNAL ;
    PORT
      LAYER M4 ;
        RECT 725.568 443.952 725.760 443.976 ;
    END
  END tx[274]
  PIN tx[275]
    DIRECTION OUTPUT ;
    USE SIGNAL ;
    PORT
      LAYER M4 ;
        RECT 725.568 444.528 725.760 444.552 ;
    END
  END tx[275]
  PIN tx[276]
    DIRECTION OUTPUT ;
    USE SIGNAL ;
    PORT
      LAYER M4 ;
        RECT 725.568 445.056 725.760 445.080 ;
    END
  END tx[276]
  PIN tx[277]
    DIRECTION OUTPUT ;
    USE SIGNAL ;
    PORT
      LAYER M4 ;
        RECT 725.568 445.632 725.760 445.656 ;
    END
  END tx[277]
  PIN tx[278]
    DIRECTION OUTPUT ;
    USE SIGNAL ;
    PORT
      LAYER M4 ;
        RECT 725.568 446.208 725.760 446.232 ;
    END
  END tx[278]
  PIN tx[279]
    DIRECTION OUTPUT ;
    USE SIGNAL ;
    PORT
      LAYER M4 ;
        RECT 725.568 446.736 725.760 446.760 ;
    END
  END tx[279]
  PIN tx[280]
    DIRECTION OUTPUT ;
    USE SIGNAL ;
    PORT
      LAYER M4 ;
        RECT 725.568 447.312 725.760 447.336 ;
    END
  END tx[280]
  PIN tx[281]
    DIRECTION OUTPUT ;
    USE SIGNAL ;
    PORT
      LAYER M4 ;
        RECT 725.568 447.840 725.760 447.864 ;
    END
  END tx[281]
  PIN tx[282]
    DIRECTION OUTPUT ;
    USE SIGNAL ;
    PORT
      LAYER M4 ;
        RECT 725.568 448.416 725.760 448.440 ;
    END
  END tx[282]
  PIN tx[283]
    DIRECTION OUTPUT ;
    USE SIGNAL ;
    PORT
      LAYER M4 ;
        RECT 725.568 448.992 725.760 449.016 ;
    END
  END tx[283]
  PIN tx[284]
    DIRECTION OUTPUT ;
    USE SIGNAL ;
    PORT
      LAYER M4 ;
        RECT 725.568 449.520 725.760 449.544 ;
    END
  END tx[284]
  PIN tx[285]
    DIRECTION OUTPUT ;
    USE SIGNAL ;
    PORT
      LAYER M4 ;
        RECT 725.568 450.096 725.760 450.120 ;
    END
  END tx[285]
  PIN tx[286]
    DIRECTION OUTPUT ;
    USE SIGNAL ;
    PORT
      LAYER M4 ;
        RECT 725.568 450.672 725.760 450.696 ;
    END
  END tx[286]
  PIN tx[287]
    DIRECTION OUTPUT ;
    USE SIGNAL ;
    PORT
      LAYER M4 ;
        RECT 725.568 451.200 725.760 451.224 ;
    END
  END tx[287]
  PIN tx[288]
    DIRECTION OUTPUT ;
    USE SIGNAL ;
    PORT
      LAYER M4 ;
        RECT 725.568 451.776 725.760 451.800 ;
    END
  END tx[288]
  PIN tx[289]
    DIRECTION OUTPUT ;
    USE SIGNAL ;
    PORT
      LAYER M4 ;
        RECT 725.568 452.352 725.760 452.376 ;
    END
  END tx[289]
  PIN tx[290]
    DIRECTION OUTPUT ;
    USE SIGNAL ;
    PORT
      LAYER M4 ;
        RECT 725.568 452.880 725.760 452.904 ;
    END
  END tx[290]
  PIN tx[291]
    DIRECTION OUTPUT ;
    USE SIGNAL ;
    PORT
      LAYER M4 ;
        RECT 725.568 453.456 725.760 453.480 ;
    END
  END tx[291]
  PIN tx[292]
    DIRECTION OUTPUT ;
    USE SIGNAL ;
    PORT
      LAYER M4 ;
        RECT 725.568 454.032 725.760 454.056 ;
    END
  END tx[292]
  PIN tx[293]
    DIRECTION OUTPUT ;
    USE SIGNAL ;
    PORT
      LAYER M4 ;
        RECT 725.568 454.560 725.760 454.584 ;
    END
  END tx[293]
  PIN tx[294]
    DIRECTION OUTPUT ;
    USE SIGNAL ;
    PORT
      LAYER M4 ;
        RECT 725.568 455.136 725.760 455.160 ;
    END
  END tx[294]
  PIN tx[295]
    DIRECTION OUTPUT ;
    USE SIGNAL ;
    PORT
      LAYER M4 ;
        RECT 725.568 455.664 725.760 455.688 ;
    END
  END tx[295]
  PIN tx[296]
    DIRECTION OUTPUT ;
    USE SIGNAL ;
    PORT
      LAYER M4 ;
        RECT 725.568 456.240 725.760 456.264 ;
    END
  END tx[296]
  PIN tx[297]
    DIRECTION OUTPUT ;
    USE SIGNAL ;
    PORT
      LAYER M4 ;
        RECT 725.568 456.816 725.760 456.840 ;
    END
  END tx[297]
  PIN tx[298]
    DIRECTION OUTPUT ;
    USE SIGNAL ;
    PORT
      LAYER M4 ;
        RECT 725.568 457.344 725.760 457.368 ;
    END
  END tx[298]
  PIN tx[299]
    DIRECTION OUTPUT ;
    USE SIGNAL ;
    PORT
      LAYER M4 ;
        RECT 725.568 457.920 725.760 457.944 ;
    END
  END tx[299]
  PIN tx[300]
    DIRECTION OUTPUT ;
    USE SIGNAL ;
    PORT
      LAYER M4 ;
        RECT 725.568 458.496 725.760 458.520 ;
    END
  END tx[300]
  PIN tx[301]
    DIRECTION OUTPUT ;
    USE SIGNAL ;
    PORT
      LAYER M4 ;
        RECT 725.568 459.024 725.760 459.048 ;
    END
  END tx[301]
  PIN tx[302]
    DIRECTION OUTPUT ;
    USE SIGNAL ;
    PORT
      LAYER M4 ;
        RECT 725.568 459.600 725.760 459.624 ;
    END
  END tx[302]
  PIN tx[303]
    DIRECTION OUTPUT ;
    USE SIGNAL ;
    PORT
      LAYER M4 ;
        RECT 725.568 460.176 725.760 460.200 ;
    END
  END tx[303]
  PIN tx[304]
    DIRECTION OUTPUT ;
    USE SIGNAL ;
    PORT
      LAYER M4 ;
        RECT 725.568 460.704 725.760 460.728 ;
    END
  END tx[304]
  PIN tx[305]
    DIRECTION OUTPUT ;
    USE SIGNAL ;
    PORT
      LAYER M4 ;
        RECT 725.568 461.280 725.760 461.304 ;
    END
  END tx[305]
  PIN tx[306]
    DIRECTION OUTPUT ;
    USE SIGNAL ;
    PORT
      LAYER M4 ;
        RECT 725.568 461.856 725.760 461.880 ;
    END
  END tx[306]
  PIN tx[307]
    DIRECTION OUTPUT ;
    USE SIGNAL ;
    PORT
      LAYER M4 ;
        RECT 725.568 462.384 725.760 462.408 ;
    END
  END tx[307]
  PIN tx[308]
    DIRECTION OUTPUT ;
    USE SIGNAL ;
    PORT
      LAYER M4 ;
        RECT 725.568 462.960 725.760 462.984 ;
    END
  END tx[308]
  PIN tx[309]
    DIRECTION OUTPUT ;
    USE SIGNAL ;
    PORT
      LAYER M4 ;
        RECT 725.568 463.536 725.760 463.560 ;
    END
  END tx[309]
  PIN tx[310]
    DIRECTION OUTPUT ;
    USE SIGNAL ;
    PORT
      LAYER M4 ;
        RECT 725.568 464.064 725.760 464.088 ;
    END
  END tx[310]
  PIN tx[311]
    DIRECTION OUTPUT ;
    USE SIGNAL ;
    PORT
      LAYER M4 ;
        RECT 725.568 464.640 725.760 464.664 ;
    END
  END tx[311]
  PIN tx[312]
    DIRECTION OUTPUT ;
    USE SIGNAL ;
    PORT
      LAYER M4 ;
        RECT 725.568 465.168 725.760 465.192 ;
    END
  END tx[312]
  PIN tx[313]
    DIRECTION OUTPUT ;
    USE SIGNAL ;
    PORT
      LAYER M4 ;
        RECT 725.568 465.744 725.760 465.768 ;
    END
  END tx[313]
  PIN tx[314]
    DIRECTION OUTPUT ;
    USE SIGNAL ;
    PORT
      LAYER M4 ;
        RECT 725.568 466.320 725.760 466.344 ;
    END
  END tx[314]
  PIN tx[315]
    DIRECTION OUTPUT ;
    USE SIGNAL ;
    PORT
      LAYER M4 ;
        RECT 725.568 466.848 725.760 466.872 ;
    END
  END tx[315]
  PIN tx[316]
    DIRECTION OUTPUT ;
    USE SIGNAL ;
    PORT
      LAYER M4 ;
        RECT 725.568 467.424 725.760 467.448 ;
    END
  END tx[316]
  PIN tx[317]
    DIRECTION OUTPUT ;
    USE SIGNAL ;
    PORT
      LAYER M4 ;
        RECT 725.568 468.000 725.760 468.024 ;
    END
  END tx[317]
  PIN tx[318]
    DIRECTION OUTPUT ;
    USE SIGNAL ;
    PORT
      LAYER M4 ;
        RECT 725.568 468.528 725.760 468.552 ;
    END
  END tx[318]
  PIN tx[319]
    DIRECTION OUTPUT ;
    USE SIGNAL ;
    PORT
      LAYER M4 ;
        RECT 725.568 469.104 725.760 469.128 ;
    END
  END tx[319]
  PIN tx[320]
    DIRECTION OUTPUT ;
    USE SIGNAL ;
    PORT
      LAYER M4 ;
        RECT 725.568 469.680 725.760 469.704 ;
    END
  END tx[320]
  PIN tx[321]
    DIRECTION OUTPUT ;
    USE SIGNAL ;
    PORT
      LAYER M4 ;
        RECT 725.568 470.208 725.760 470.232 ;
    END
  END tx[321]
  PIN tx[322]
    DIRECTION OUTPUT ;
    USE SIGNAL ;
    PORT
      LAYER M4 ;
        RECT 725.568 470.784 725.760 470.808 ;
    END
  END tx[322]
  PIN tx[323]
    DIRECTION OUTPUT ;
    USE SIGNAL ;
    PORT
      LAYER M4 ;
        RECT 725.568 471.360 725.760 471.384 ;
    END
  END tx[323]
  PIN tx[324]
    DIRECTION OUTPUT ;
    USE SIGNAL ;
    PORT
      LAYER M4 ;
        RECT 725.568 471.888 725.760 471.912 ;
    END
  END tx[324]
  PIN tx[325]
    DIRECTION OUTPUT ;
    USE SIGNAL ;
    PORT
      LAYER M4 ;
        RECT 725.568 472.464 725.760 472.488 ;
    END
  END tx[325]
  PIN tx[326]
    DIRECTION OUTPUT ;
    USE SIGNAL ;
    PORT
      LAYER M4 ;
        RECT 725.568 473.040 725.760 473.064 ;
    END
  END tx[326]
  PIN tx[327]
    DIRECTION OUTPUT ;
    USE SIGNAL ;
    PORT
      LAYER M4 ;
        RECT 725.568 473.568 725.760 473.592 ;
    END
  END tx[327]
  PIN tx[328]
    DIRECTION OUTPUT ;
    USE SIGNAL ;
    PORT
      LAYER M4 ;
        RECT 725.568 474.144 725.760 474.168 ;
    END
  END tx[328]
  PIN tx[329]
    DIRECTION OUTPUT ;
    USE SIGNAL ;
    PORT
      LAYER M4 ;
        RECT 725.568 474.672 725.760 474.696 ;
    END
  END tx[329]
  PIN tx[330]
    DIRECTION OUTPUT ;
    USE SIGNAL ;
    PORT
      LAYER M4 ;
        RECT 725.568 475.248 725.760 475.272 ;
    END
  END tx[330]
  PIN tx[331]
    DIRECTION OUTPUT ;
    USE SIGNAL ;
    PORT
      LAYER M4 ;
        RECT 725.568 475.824 725.760 475.848 ;
    END
  END tx[331]
  PIN tx[332]
    DIRECTION OUTPUT ;
    USE SIGNAL ;
    PORT
      LAYER M4 ;
        RECT 725.568 476.352 725.760 476.376 ;
    END
  END tx[332]
  PIN tx[333]
    DIRECTION OUTPUT ;
    USE SIGNAL ;
    PORT
      LAYER M4 ;
        RECT 725.568 476.928 725.760 476.952 ;
    END
  END tx[333]
  PIN tx[334]
    DIRECTION OUTPUT ;
    USE SIGNAL ;
    PORT
      LAYER M4 ;
        RECT 725.568 477.504 725.760 477.528 ;
    END
  END tx[334]
  PIN tx[335]
    DIRECTION OUTPUT ;
    USE SIGNAL ;
    PORT
      LAYER M4 ;
        RECT 725.568 478.032 725.760 478.056 ;
    END
  END tx[335]
  PIN tx[336]
    DIRECTION OUTPUT ;
    USE SIGNAL ;
    PORT
      LAYER M4 ;
        RECT 725.568 478.608 725.760 478.632 ;
    END
  END tx[336]
  PIN tx[337]
    DIRECTION OUTPUT ;
    USE SIGNAL ;
    PORT
      LAYER M4 ;
        RECT 725.568 479.184 725.760 479.208 ;
    END
  END tx[337]
  PIN tx[338]
    DIRECTION OUTPUT ;
    USE SIGNAL ;
    PORT
      LAYER M4 ;
        RECT 725.568 479.712 725.760 479.736 ;
    END
  END tx[338]
  PIN tx[339]
    DIRECTION OUTPUT ;
    USE SIGNAL ;
    PORT
      LAYER M4 ;
        RECT 725.568 480.288 725.760 480.312 ;
    END
  END tx[339]
  PIN tx[340]
    DIRECTION OUTPUT ;
    USE SIGNAL ;
    PORT
      LAYER M4 ;
        RECT 725.568 480.864 725.760 480.888 ;
    END
  END tx[340]
  PIN tx[341]
    DIRECTION OUTPUT ;
    USE SIGNAL ;
    PORT
      LAYER M4 ;
        RECT 725.568 481.392 725.760 481.416 ;
    END
  END tx[341]
  PIN tx[342]
    DIRECTION OUTPUT ;
    USE SIGNAL ;
    PORT
      LAYER M4 ;
        RECT 725.568 481.968 725.760 481.992 ;
    END
  END tx[342]
  PIN tx[343]
    DIRECTION OUTPUT ;
    USE SIGNAL ;
    PORT
      LAYER M4 ;
        RECT 725.568 482.496 725.760 482.520 ;
    END
  END tx[343]
  PIN tx[344]
    DIRECTION OUTPUT ;
    USE SIGNAL ;
    PORT
      LAYER M4 ;
        RECT 725.568 483.072 725.760 483.096 ;
    END
  END tx[344]
  PIN tx[345]
    DIRECTION OUTPUT ;
    USE SIGNAL ;
    PORT
      LAYER M4 ;
        RECT 725.568 483.648 725.760 483.672 ;
    END
  END tx[345]
  PIN tx[346]
    DIRECTION OUTPUT ;
    USE SIGNAL ;
    PORT
      LAYER M4 ;
        RECT 725.568 484.176 725.760 484.200 ;
    END
  END tx[346]
  PIN tx[347]
    DIRECTION OUTPUT ;
    USE SIGNAL ;
    PORT
      LAYER M4 ;
        RECT 725.568 484.752 725.760 484.776 ;
    END
  END tx[347]
  PIN tx[348]
    DIRECTION OUTPUT ;
    USE SIGNAL ;
    PORT
      LAYER M4 ;
        RECT 725.568 485.328 725.760 485.352 ;
    END
  END tx[348]
  PIN tx[349]
    DIRECTION OUTPUT ;
    USE SIGNAL ;
    PORT
      LAYER M4 ;
        RECT 725.568 485.856 725.760 485.880 ;
    END
  END tx[349]
  PIN tx[350]
    DIRECTION OUTPUT ;
    USE SIGNAL ;
    PORT
      LAYER M4 ;
        RECT 725.568 486.432 725.760 486.456 ;
    END
  END tx[350]
  PIN tx[351]
    DIRECTION OUTPUT ;
    USE SIGNAL ;
    PORT
      LAYER M4 ;
        RECT 725.568 487.008 725.760 487.032 ;
    END
  END tx[351]
  PIN tx[352]
    DIRECTION OUTPUT ;
    USE SIGNAL ;
    PORT
      LAYER M4 ;
        RECT 725.568 487.536 725.760 487.560 ;
    END
  END tx[352]
  PIN tx[353]
    DIRECTION OUTPUT ;
    USE SIGNAL ;
    PORT
      LAYER M4 ;
        RECT 725.568 488.112 725.760 488.136 ;
    END
  END tx[353]
  PIN tx[354]
    DIRECTION OUTPUT ;
    USE SIGNAL ;
    PORT
      LAYER M4 ;
        RECT 725.568 488.688 725.760 488.712 ;
    END
  END tx[354]
  PIN tx[355]
    DIRECTION OUTPUT ;
    USE SIGNAL ;
    PORT
      LAYER M4 ;
        RECT 725.568 489.216 725.760 489.240 ;
    END
  END tx[355]
  PIN tx[356]
    DIRECTION OUTPUT ;
    USE SIGNAL ;
    PORT
      LAYER M4 ;
        RECT 725.568 489.792 725.760 489.816 ;
    END
  END tx[356]
  PIN tx[357]
    DIRECTION OUTPUT ;
    USE SIGNAL ;
    PORT
      LAYER M4 ;
        RECT 725.568 490.368 725.760 490.392 ;
    END
  END tx[357]
  PIN tx[358]
    DIRECTION OUTPUT ;
    USE SIGNAL ;
    PORT
      LAYER M4 ;
        RECT 725.568 490.896 725.760 490.920 ;
    END
  END tx[358]
  PIN tx[359]
    DIRECTION OUTPUT ;
    USE SIGNAL ;
    PORT
      LAYER M4 ;
        RECT 725.568 491.472 725.760 491.496 ;
    END
  END tx[359]
  PIN tx[360]
    DIRECTION OUTPUT ;
    USE SIGNAL ;
    PORT
      LAYER M4 ;
        RECT 725.568 492.000 725.760 492.024 ;
    END
  END tx[360]
  PIN tx[361]
    DIRECTION OUTPUT ;
    USE SIGNAL ;
    PORT
      LAYER M4 ;
        RECT 725.568 492.576 725.760 492.600 ;
    END
  END tx[361]
  PIN tx[362]
    DIRECTION OUTPUT ;
    USE SIGNAL ;
    PORT
      LAYER M4 ;
        RECT 725.568 493.152 725.760 493.176 ;
    END
  END tx[362]
  PIN tx[363]
    DIRECTION OUTPUT ;
    USE SIGNAL ;
    PORT
      LAYER M4 ;
        RECT 725.568 493.680 725.760 493.704 ;
    END
  END tx[363]
  PIN tx[364]
    DIRECTION OUTPUT ;
    USE SIGNAL ;
    PORT
      LAYER M4 ;
        RECT 725.568 494.256 725.760 494.280 ;
    END
  END tx[364]
  PIN tx[365]
    DIRECTION OUTPUT ;
    USE SIGNAL ;
    PORT
      LAYER M4 ;
        RECT 725.568 494.832 725.760 494.856 ;
    END
  END tx[365]
  PIN tx[366]
    DIRECTION OUTPUT ;
    USE SIGNAL ;
    PORT
      LAYER M4 ;
        RECT 725.568 495.360 725.760 495.384 ;
    END
  END tx[366]
  PIN tx[367]
    DIRECTION OUTPUT ;
    USE SIGNAL ;
    PORT
      LAYER M4 ;
        RECT 725.568 495.936 725.760 495.960 ;
    END
  END tx[367]
  PIN tx[368]
    DIRECTION OUTPUT ;
    USE SIGNAL ;
    PORT
      LAYER M4 ;
        RECT 725.568 496.512 725.760 496.536 ;
    END
  END tx[368]
  PIN tx[369]
    DIRECTION OUTPUT ;
    USE SIGNAL ;
    PORT
      LAYER M4 ;
        RECT 725.568 497.040 725.760 497.064 ;
    END
  END tx[369]
  PIN tx[370]
    DIRECTION OUTPUT ;
    USE SIGNAL ;
    PORT
      LAYER M4 ;
        RECT 725.568 497.616 725.760 497.640 ;
    END
  END tx[370]
  PIN tx[371]
    DIRECTION OUTPUT ;
    USE SIGNAL ;
    PORT
      LAYER M4 ;
        RECT 725.568 498.192 725.760 498.216 ;
    END
  END tx[371]
  PIN tx[372]
    DIRECTION OUTPUT ;
    USE SIGNAL ;
    PORT
      LAYER M4 ;
        RECT 725.568 498.720 725.760 498.744 ;
    END
  END tx[372]
  PIN tx[373]
    DIRECTION OUTPUT ;
    USE SIGNAL ;
    PORT
      LAYER M4 ;
        RECT 725.568 499.296 725.760 499.320 ;
    END
  END tx[373]
  PIN tx[374]
    DIRECTION OUTPUT ;
    USE SIGNAL ;
    PORT
      LAYER M4 ;
        RECT 725.568 499.824 725.760 499.848 ;
    END
  END tx[374]
  PIN tx[375]
    DIRECTION OUTPUT ;
    USE SIGNAL ;
    PORT
      LAYER M4 ;
        RECT 725.568 500.400 725.760 500.424 ;
    END
  END tx[375]
  PIN tx[376]
    DIRECTION OUTPUT ;
    USE SIGNAL ;
    PORT
      LAYER M4 ;
        RECT 725.568 500.976 725.760 501.000 ;
    END
  END tx[376]
  PIN tx[377]
    DIRECTION OUTPUT ;
    USE SIGNAL ;
    PORT
      LAYER M4 ;
        RECT 725.568 501.504 725.760 501.528 ;
    END
  END tx[377]
  PIN tx[378]
    DIRECTION OUTPUT ;
    USE SIGNAL ;
    PORT
      LAYER M4 ;
        RECT 725.568 502.080 725.760 502.104 ;
    END
  END tx[378]
  PIN tx[379]
    DIRECTION OUTPUT ;
    USE SIGNAL ;
    PORT
      LAYER M4 ;
        RECT 725.568 502.656 725.760 502.680 ;
    END
  END tx[379]
  PIN tx[380]
    DIRECTION OUTPUT ;
    USE SIGNAL ;
    PORT
      LAYER M4 ;
        RECT 725.568 503.184 725.760 503.208 ;
    END
  END tx[380]
  PIN tx[381]
    DIRECTION OUTPUT ;
    USE SIGNAL ;
    PORT
      LAYER M4 ;
        RECT 725.568 503.760 725.760 503.784 ;
    END
  END tx[381]
  PIN tx[382]
    DIRECTION OUTPUT ;
    USE SIGNAL ;
    PORT
      LAYER M4 ;
        RECT 725.568 504.336 725.760 504.360 ;
    END
  END tx[382]
  PIN tx[383]
    DIRECTION OUTPUT ;
    USE SIGNAL ;
    PORT
      LAYER M4 ;
        RECT 725.568 504.864 725.760 504.888 ;
    END
  END tx[383]
  PIN tx[384]
    DIRECTION OUTPUT ;
    USE SIGNAL ;
    PORT
      LAYER M4 ;
        RECT 725.568 505.440 725.760 505.464 ;
    END
  END tx[384]
  PIN tx[385]
    DIRECTION OUTPUT ;
    USE SIGNAL ;
    PORT
      LAYER M4 ;
        RECT 725.568 506.016 725.760 506.040 ;
    END
  END tx[385]
  PIN tx[386]
    DIRECTION OUTPUT ;
    USE SIGNAL ;
    PORT
      LAYER M4 ;
        RECT 725.568 506.544 725.760 506.568 ;
    END
  END tx[386]
  PIN tx[387]
    DIRECTION OUTPUT ;
    USE SIGNAL ;
    PORT
      LAYER M4 ;
        RECT 725.568 507.120 725.760 507.144 ;
    END
  END tx[387]
  PIN tx[388]
    DIRECTION OUTPUT ;
    USE SIGNAL ;
    PORT
      LAYER M4 ;
        RECT 725.568 507.696 725.760 507.720 ;
    END
  END tx[388]
  PIN tx[389]
    DIRECTION OUTPUT ;
    USE SIGNAL ;
    PORT
      LAYER M4 ;
        RECT 725.568 508.224 725.760 508.248 ;
    END
  END tx[389]
  PIN tx[390]
    DIRECTION OUTPUT ;
    USE SIGNAL ;
    PORT
      LAYER M4 ;
        RECT 725.568 508.800 725.760 508.824 ;
    END
  END tx[390]
  PIN tx[391]
    DIRECTION OUTPUT ;
    USE SIGNAL ;
    PORT
      LAYER M4 ;
        RECT 725.568 509.328 725.760 509.352 ;
    END
  END tx[391]
  PIN tx[392]
    DIRECTION OUTPUT ;
    USE SIGNAL ;
    PORT
      LAYER M4 ;
        RECT 725.568 509.904 725.760 509.928 ;
    END
  END tx[392]
  PIN tx[393]
    DIRECTION OUTPUT ;
    USE SIGNAL ;
    PORT
      LAYER M4 ;
        RECT 725.568 510.480 725.760 510.504 ;
    END
  END tx[393]
  PIN tx[394]
    DIRECTION OUTPUT ;
    USE SIGNAL ;
    PORT
      LAYER M4 ;
        RECT 725.568 511.008 725.760 511.032 ;
    END
  END tx[394]
  PIN tx[395]
    DIRECTION OUTPUT ;
    USE SIGNAL ;
    PORT
      LAYER M4 ;
        RECT 725.568 511.584 725.760 511.608 ;
    END
  END tx[395]
  PIN tx[396]
    DIRECTION OUTPUT ;
    USE SIGNAL ;
    PORT
      LAYER M4 ;
        RECT 725.568 512.160 725.760 512.184 ;
    END
  END tx[396]
  PIN tx[397]
    DIRECTION OUTPUT ;
    USE SIGNAL ;
    PORT
      LAYER M4 ;
        RECT 725.568 512.688 725.760 512.712 ;
    END
  END tx[397]
  PIN tx[398]
    DIRECTION OUTPUT ;
    USE SIGNAL ;
    PORT
      LAYER M4 ;
        RECT 725.568 513.264 725.760 513.288 ;
    END
  END tx[398]
  PIN tx[399]
    DIRECTION OUTPUT ;
    USE SIGNAL ;
    PORT
      LAYER M4 ;
        RECT 725.568 513.840 725.760 513.864 ;
    END
  END tx[399]
  PIN tx[400]
    DIRECTION OUTPUT ;
    USE SIGNAL ;
    PORT
      LAYER M4 ;
        RECT 725.568 514.368 725.760 514.392 ;
    END
  END tx[400]
  PIN tx[401]
    DIRECTION OUTPUT ;
    USE SIGNAL ;
    PORT
      LAYER M4 ;
        RECT 725.568 514.944 725.760 514.968 ;
    END
  END tx[401]
  PIN tx[402]
    DIRECTION OUTPUT ;
    USE SIGNAL ;
    PORT
      LAYER M4 ;
        RECT 725.568 515.520 725.760 515.544 ;
    END
  END tx[402]
  PIN tx[403]
    DIRECTION OUTPUT ;
    USE SIGNAL ;
    PORT
      LAYER M4 ;
        RECT 725.568 516.048 725.760 516.072 ;
    END
  END tx[403]
  PIN tx[404]
    DIRECTION OUTPUT ;
    USE SIGNAL ;
    PORT
      LAYER M4 ;
        RECT 725.568 516.624 725.760 516.648 ;
    END
  END tx[404]
  PIN tx[405]
    DIRECTION OUTPUT ;
    USE SIGNAL ;
    PORT
      LAYER M4 ;
        RECT 725.568 517.200 725.760 517.224 ;
    END
  END tx[405]
  PIN tx[406]
    DIRECTION OUTPUT ;
    USE SIGNAL ;
    PORT
      LAYER M4 ;
        RECT 725.568 517.728 725.760 517.752 ;
    END
  END tx[406]
  PIN tx[407]
    DIRECTION OUTPUT ;
    USE SIGNAL ;
    PORT
      LAYER M4 ;
        RECT 725.568 518.304 725.760 518.328 ;
    END
  END tx[407]
  PIN tx[408]
    DIRECTION OUTPUT ;
    USE SIGNAL ;
    PORT
      LAYER M4 ;
        RECT 725.568 518.832 725.760 518.856 ;
    END
  END tx[408]
  PIN tx[409]
    DIRECTION OUTPUT ;
    USE SIGNAL ;
    PORT
      LAYER M4 ;
        RECT 725.568 519.408 725.760 519.432 ;
    END
  END tx[409]
  PIN tx[410]
    DIRECTION OUTPUT ;
    USE SIGNAL ;
    PORT
      LAYER M4 ;
        RECT 725.568 519.984 725.760 520.008 ;
    END
  END tx[410]
  PIN tx[411]
    DIRECTION OUTPUT ;
    USE SIGNAL ;
    PORT
      LAYER M4 ;
        RECT 725.568 520.512 725.760 520.536 ;
    END
  END tx[411]
  PIN tx[412]
    DIRECTION OUTPUT ;
    USE SIGNAL ;
    PORT
      LAYER M4 ;
        RECT 725.568 521.088 725.760 521.112 ;
    END
  END tx[412]
  PIN tx[413]
    DIRECTION OUTPUT ;
    USE SIGNAL ;
    PORT
      LAYER M4 ;
        RECT 725.568 521.664 725.760 521.688 ;
    END
  END tx[413]
  PIN tx[414]
    DIRECTION OUTPUT ;
    USE SIGNAL ;
    PORT
      LAYER M4 ;
        RECT 725.568 522.192 725.760 522.216 ;
    END
  END tx[414]
  PIN tx[415]
    DIRECTION OUTPUT ;
    USE SIGNAL ;
    PORT
      LAYER M4 ;
        RECT 725.568 522.768 725.760 522.792 ;
    END
  END tx[415]
  PIN tx[416]
    DIRECTION OUTPUT ;
    USE SIGNAL ;
    PORT
      LAYER M4 ;
        RECT 725.568 523.344 725.760 523.368 ;
    END
  END tx[416]
  PIN tx[417]
    DIRECTION OUTPUT ;
    USE SIGNAL ;
    PORT
      LAYER M4 ;
        RECT 725.568 523.872 725.760 523.896 ;
    END
  END tx[417]
  PIN tx[418]
    DIRECTION OUTPUT ;
    USE SIGNAL ;
    PORT
      LAYER M4 ;
        RECT 725.568 524.448 725.760 524.472 ;
    END
  END tx[418]
  PIN tx[419]
    DIRECTION OUTPUT ;
    USE SIGNAL ;
    PORT
      LAYER M4 ;
        RECT 725.568 525.024 725.760 525.048 ;
    END
  END tx[419]
  PIN tx[420]
    DIRECTION OUTPUT ;
    USE SIGNAL ;
    PORT
      LAYER M4 ;
        RECT 725.568 525.552 725.760 525.576 ;
    END
  END tx[420]
  PIN tx[421]
    DIRECTION OUTPUT ;
    USE SIGNAL ;
    PORT
      LAYER M4 ;
        RECT 725.568 526.128 725.760 526.152 ;
    END
  END tx[421]
  PIN tx[422]
    DIRECTION OUTPUT ;
    USE SIGNAL ;
    PORT
      LAYER M4 ;
        RECT 725.568 526.656 725.760 526.680 ;
    END
  END tx[422]
  PIN tx[423]
    DIRECTION OUTPUT ;
    USE SIGNAL ;
    PORT
      LAYER M4 ;
        RECT 725.568 527.232 725.760 527.256 ;
    END
  END tx[423]
  PIN tx[424]
    DIRECTION OUTPUT ;
    USE SIGNAL ;
    PORT
      LAYER M4 ;
        RECT 725.568 527.808 725.760 527.832 ;
    END
  END tx[424]
  PIN tx[425]
    DIRECTION OUTPUT ;
    USE SIGNAL ;
    PORT
      LAYER M4 ;
        RECT 725.568 528.336 725.760 528.360 ;
    END
  END tx[425]
  PIN tx[426]
    DIRECTION OUTPUT ;
    USE SIGNAL ;
    PORT
      LAYER M4 ;
        RECT 725.568 528.912 725.760 528.936 ;
    END
  END tx[426]
  PIN tx[427]
    DIRECTION OUTPUT ;
    USE SIGNAL ;
    PORT
      LAYER M4 ;
        RECT 725.568 529.488 725.760 529.512 ;
    END
  END tx[427]
  PIN tx[428]
    DIRECTION OUTPUT ;
    USE SIGNAL ;
    PORT
      LAYER M4 ;
        RECT 725.568 530.016 725.760 530.040 ;
    END
  END tx[428]
  PIN tx[429]
    DIRECTION OUTPUT ;
    USE SIGNAL ;
    PORT
      LAYER M4 ;
        RECT 725.568 530.592 725.760 530.616 ;
    END
  END tx[429]
  PIN tx[430]
    DIRECTION OUTPUT ;
    USE SIGNAL ;
    PORT
      LAYER M4 ;
        RECT 725.568 531.168 725.760 531.192 ;
    END
  END tx[430]
  PIN tx[431]
    DIRECTION OUTPUT ;
    USE SIGNAL ;
    PORT
      LAYER M4 ;
        RECT 725.568 531.696 725.760 531.720 ;
    END
  END tx[431]
  PIN tx[432]
    DIRECTION OUTPUT ;
    USE SIGNAL ;
    PORT
      LAYER M4 ;
        RECT 725.568 532.272 725.760 532.296 ;
    END
  END tx[432]
  PIN tx[433]
    DIRECTION OUTPUT ;
    USE SIGNAL ;
    PORT
      LAYER M4 ;
        RECT 725.568 532.848 725.760 532.872 ;
    END
  END tx[433]
  PIN tx[434]
    DIRECTION OUTPUT ;
    USE SIGNAL ;
    PORT
      LAYER M4 ;
        RECT 725.568 533.376 725.760 533.400 ;
    END
  END tx[434]
  PIN tx[435]
    DIRECTION OUTPUT ;
    USE SIGNAL ;
    PORT
      LAYER M4 ;
        RECT 725.568 533.952 725.760 533.976 ;
    END
  END tx[435]
  PIN tx[436]
    DIRECTION OUTPUT ;
    USE SIGNAL ;
    PORT
      LAYER M4 ;
        RECT 725.568 534.528 725.760 534.552 ;
    END
  END tx[436]
  PIN tx[437]
    DIRECTION OUTPUT ;
    USE SIGNAL ;
    PORT
      LAYER M4 ;
        RECT 725.568 535.056 725.760 535.080 ;
    END
  END tx[437]
  PIN tx[438]
    DIRECTION OUTPUT ;
    USE SIGNAL ;
    PORT
      LAYER M4 ;
        RECT 725.568 535.632 725.760 535.656 ;
    END
  END tx[438]
  PIN tx[439]
    DIRECTION OUTPUT ;
    USE SIGNAL ;
    PORT
      LAYER M4 ;
        RECT 725.568 536.160 725.760 536.184 ;
    END
  END tx[439]
  PIN tx[440]
    DIRECTION OUTPUT ;
    USE SIGNAL ;
    PORT
      LAYER M4 ;
        RECT 725.568 536.736 725.760 536.760 ;
    END
  END tx[440]
  PIN tx[441]
    DIRECTION OUTPUT ;
    USE SIGNAL ;
    PORT
      LAYER M4 ;
        RECT 725.568 537.312 725.760 537.336 ;
    END
  END tx[441]
  PIN tx[442]
    DIRECTION OUTPUT ;
    USE SIGNAL ;
    PORT
      LAYER M4 ;
        RECT 725.568 537.840 725.760 537.864 ;
    END
  END tx[442]
  PIN tx[443]
    DIRECTION OUTPUT ;
    USE SIGNAL ;
    PORT
      LAYER M4 ;
        RECT 725.568 538.416 725.760 538.440 ;
    END
  END tx[443]
  PIN tx[444]
    DIRECTION OUTPUT ;
    USE SIGNAL ;
    PORT
      LAYER M4 ;
        RECT 725.568 538.992 725.760 539.016 ;
    END
  END tx[444]
  PIN tx[445]
    DIRECTION OUTPUT ;
    USE SIGNAL ;
    PORT
      LAYER M4 ;
        RECT 725.568 539.520 725.760 539.544 ;
    END
  END tx[445]
  PIN tx[446]
    DIRECTION OUTPUT ;
    USE SIGNAL ;
    PORT
      LAYER M4 ;
        RECT 725.568 540.096 725.760 540.120 ;
    END
  END tx[446]
  PIN tx[447]
    DIRECTION OUTPUT ;
    USE SIGNAL ;
    PORT
      LAYER M4 ;
        RECT 725.568 540.672 725.760 540.696 ;
    END
  END tx[447]
  PIN tx[448]
    DIRECTION OUTPUT ;
    USE SIGNAL ;
    PORT
      LAYER M4 ;
        RECT 725.568 541.200 725.760 541.224 ;
    END
  END tx[448]
  PIN tx[449]
    DIRECTION OUTPUT ;
    USE SIGNAL ;
    PORT
      LAYER M4 ;
        RECT 725.568 541.776 725.760 541.800 ;
    END
  END tx[449]
  PIN tx[450]
    DIRECTION OUTPUT ;
    USE SIGNAL ;
    PORT
      LAYER M4 ;
        RECT 725.568 542.352 725.760 542.376 ;
    END
  END tx[450]
  PIN tx[451]
    DIRECTION OUTPUT ;
    USE SIGNAL ;
    PORT
      LAYER M4 ;
        RECT 725.568 542.880 725.760 542.904 ;
    END
  END tx[451]
  PIN tx[452]
    DIRECTION OUTPUT ;
    USE SIGNAL ;
    PORT
      LAYER M4 ;
        RECT 725.568 543.456 725.760 543.480 ;
    END
  END tx[452]
  PIN tx[453]
    DIRECTION OUTPUT ;
    USE SIGNAL ;
    PORT
      LAYER M4 ;
        RECT 725.568 543.984 725.760 544.008 ;
    END
  END tx[453]
  PIN tx[454]
    DIRECTION OUTPUT ;
    USE SIGNAL ;
    PORT
      LAYER M4 ;
        RECT 725.568 544.560 725.760 544.584 ;
    END
  END tx[454]
  PIN tx[455]
    DIRECTION OUTPUT ;
    USE SIGNAL ;
    PORT
      LAYER M4 ;
        RECT 725.568 545.136 725.760 545.160 ;
    END
  END tx[455]
  PIN tx[456]
    DIRECTION OUTPUT ;
    USE SIGNAL ;
    PORT
      LAYER M4 ;
        RECT 725.568 545.664 725.760 545.688 ;
    END
  END tx[456]
  PIN tx[457]
    DIRECTION OUTPUT ;
    USE SIGNAL ;
    PORT
      LAYER M4 ;
        RECT 725.568 546.240 725.760 546.264 ;
    END
  END tx[457]
  PIN tx[458]
    DIRECTION OUTPUT ;
    USE SIGNAL ;
    PORT
      LAYER M4 ;
        RECT 725.568 546.816 725.760 546.840 ;
    END
  END tx[458]
  PIN tx[459]
    DIRECTION OUTPUT ;
    USE SIGNAL ;
    PORT
      LAYER M4 ;
        RECT 725.568 547.344 725.760 547.368 ;
    END
  END tx[459]
  PIN tx[460]
    DIRECTION OUTPUT ;
    USE SIGNAL ;
    PORT
      LAYER M4 ;
        RECT 725.568 547.920 725.760 547.944 ;
    END
  END tx[460]
  PIN tx[461]
    DIRECTION OUTPUT ;
    USE SIGNAL ;
    PORT
      LAYER M4 ;
        RECT 725.568 548.496 725.760 548.520 ;
    END
  END tx[461]
  PIN tx[462]
    DIRECTION OUTPUT ;
    USE SIGNAL ;
    PORT
      LAYER M4 ;
        RECT 725.568 549.024 725.760 549.048 ;
    END
  END tx[462]
  PIN tx[463]
    DIRECTION OUTPUT ;
    USE SIGNAL ;
    PORT
      LAYER M4 ;
        RECT 725.568 549.600 725.760 549.624 ;
    END
  END tx[463]
  PIN tx[464]
    DIRECTION OUTPUT ;
    USE SIGNAL ;
    PORT
      LAYER M4 ;
        RECT 725.568 550.176 725.760 550.200 ;
    END
  END tx[464]
  PIN tx[465]
    DIRECTION OUTPUT ;
    USE SIGNAL ;
    PORT
      LAYER M4 ;
        RECT 725.568 550.704 725.760 550.728 ;
    END
  END tx[465]
  PIN tx[466]
    DIRECTION OUTPUT ;
    USE SIGNAL ;
    PORT
      LAYER M4 ;
        RECT 725.568 551.280 725.760 551.304 ;
    END
  END tx[466]
  PIN tx[467]
    DIRECTION OUTPUT ;
    USE SIGNAL ;
    PORT
      LAYER M4 ;
        RECT 725.568 551.856 725.760 551.880 ;
    END
  END tx[467]
  PIN tx[468]
    DIRECTION OUTPUT ;
    USE SIGNAL ;
    PORT
      LAYER M4 ;
        RECT 725.568 552.384 725.760 552.408 ;
    END
  END tx[468]
  PIN tx[469]
    DIRECTION OUTPUT ;
    USE SIGNAL ;
    PORT
      LAYER M4 ;
        RECT 725.568 552.960 725.760 552.984 ;
    END
  END tx[469]
  PIN tx[470]
    DIRECTION OUTPUT ;
    USE SIGNAL ;
    PORT
      LAYER M4 ;
        RECT 725.568 553.488 725.760 553.512 ;
    END
  END tx[470]
  PIN tx[471]
    DIRECTION OUTPUT ;
    USE SIGNAL ;
    PORT
      LAYER M4 ;
        RECT 725.568 554.064 725.760 554.088 ;
    END
  END tx[471]
  PIN tx[472]
    DIRECTION OUTPUT ;
    USE SIGNAL ;
    PORT
      LAYER M4 ;
        RECT 725.568 554.640 725.760 554.664 ;
    END
  END tx[472]
  PIN tx[473]
    DIRECTION OUTPUT ;
    USE SIGNAL ;
    PORT
      LAYER M4 ;
        RECT 725.568 555.168 725.760 555.192 ;
    END
  END tx[473]
  PIN tx[474]
    DIRECTION OUTPUT ;
    USE SIGNAL ;
    PORT
      LAYER M4 ;
        RECT 725.568 555.744 725.760 555.768 ;
    END
  END tx[474]
  PIN tx[475]
    DIRECTION OUTPUT ;
    USE SIGNAL ;
    PORT
      LAYER M4 ;
        RECT 725.568 556.320 725.760 556.344 ;
    END
  END tx[475]
  PIN tx[476]
    DIRECTION OUTPUT ;
    USE SIGNAL ;
    PORT
      LAYER M4 ;
        RECT 725.568 556.848 725.760 556.872 ;
    END
  END tx[476]
  PIN tx[477]
    DIRECTION OUTPUT ;
    USE SIGNAL ;
    PORT
      LAYER M4 ;
        RECT 725.568 557.424 725.760 557.448 ;
    END
  END tx[477]
  PIN tx[478]
    DIRECTION OUTPUT ;
    USE SIGNAL ;
    PORT
      LAYER M4 ;
        RECT 725.568 558.000 725.760 558.024 ;
    END
  END tx[478]
  PIN tx[479]
    DIRECTION OUTPUT ;
    USE SIGNAL ;
    PORT
      LAYER M4 ;
        RECT 725.568 558.528 725.760 558.552 ;
    END
  END tx[479]
  PIN tx[480]
    DIRECTION OUTPUT ;
    USE SIGNAL ;
    PORT
      LAYER M4 ;
        RECT 725.568 559.104 725.760 559.128 ;
    END
  END tx[480]
  PIN tx[481]
    DIRECTION OUTPUT ;
    USE SIGNAL ;
    PORT
      LAYER M4 ;
        RECT 725.568 559.680 725.760 559.704 ;
    END
  END tx[481]
  PIN tx[482]
    DIRECTION OUTPUT ;
    USE SIGNAL ;
    PORT
      LAYER M4 ;
        RECT 725.568 560.208 725.760 560.232 ;
    END
  END tx[482]
  PIN tx[483]
    DIRECTION OUTPUT ;
    USE SIGNAL ;
    PORT
      LAYER M4 ;
        RECT 725.568 560.784 725.760 560.808 ;
    END
  END tx[483]
  PIN tx[484]
    DIRECTION OUTPUT ;
    USE SIGNAL ;
    PORT
      LAYER M4 ;
        RECT 725.568 561.312 725.760 561.336 ;
    END
  END tx[484]
  PIN tx[485]
    DIRECTION OUTPUT ;
    USE SIGNAL ;
    PORT
      LAYER M4 ;
        RECT 725.568 561.888 725.760 561.912 ;
    END
  END tx[485]
  PIN tx[486]
    DIRECTION OUTPUT ;
    USE SIGNAL ;
    PORT
      LAYER M4 ;
        RECT 725.568 562.464 725.760 562.488 ;
    END
  END tx[486]
  PIN tx[487]
    DIRECTION OUTPUT ;
    USE SIGNAL ;
    PORT
      LAYER M4 ;
        RECT 725.568 562.992 725.760 563.016 ;
    END
  END tx[487]
  PIN tx[488]
    DIRECTION OUTPUT ;
    USE SIGNAL ;
    PORT
      LAYER M4 ;
        RECT 725.568 563.568 725.760 563.592 ;
    END
  END tx[488]
  PIN tx[489]
    DIRECTION OUTPUT ;
    USE SIGNAL ;
    PORT
      LAYER M4 ;
        RECT 725.568 564.144 725.760 564.168 ;
    END
  END tx[489]
  PIN tx[490]
    DIRECTION OUTPUT ;
    USE SIGNAL ;
    PORT
      LAYER M4 ;
        RECT 725.568 564.672 725.760 564.696 ;
    END
  END tx[490]
  PIN tx[491]
    DIRECTION OUTPUT ;
    USE SIGNAL ;
    PORT
      LAYER M4 ;
        RECT 725.568 565.248 725.760 565.272 ;
    END
  END tx[491]
  PIN tx[492]
    DIRECTION OUTPUT ;
    USE SIGNAL ;
    PORT
      LAYER M4 ;
        RECT 725.568 565.824 725.760 565.848 ;
    END
  END tx[492]
  PIN tx[493]
    DIRECTION OUTPUT ;
    USE SIGNAL ;
    PORT
      LAYER M4 ;
        RECT 725.568 566.352 725.760 566.376 ;
    END
  END tx[493]
  PIN tx[494]
    DIRECTION OUTPUT ;
    USE SIGNAL ;
    PORT
      LAYER M4 ;
        RECT 725.568 566.928 725.760 566.952 ;
    END
  END tx[494]
  PIN tx[495]
    DIRECTION OUTPUT ;
    USE SIGNAL ;
    PORT
      LAYER M4 ;
        RECT 725.568 567.504 725.760 567.528 ;
    END
  END tx[495]
  PIN tx[496]
    DIRECTION OUTPUT ;
    USE SIGNAL ;
    PORT
      LAYER M4 ;
        RECT 725.568 568.032 725.760 568.056 ;
    END
  END tx[496]
  PIN tx[497]
    DIRECTION OUTPUT ;
    USE SIGNAL ;
    PORT
      LAYER M4 ;
        RECT 725.568 568.608 725.760 568.632 ;
    END
  END tx[497]
  PIN tx[498]
    DIRECTION OUTPUT ;
    USE SIGNAL ;
    PORT
      LAYER M4 ;
        RECT 725.568 569.184 725.760 569.208 ;
    END
  END tx[498]
  PIN tx[499]
    DIRECTION OUTPUT ;
    USE SIGNAL ;
    PORT
      LAYER M4 ;
        RECT 725.568 569.712 725.760 569.736 ;
    END
  END tx[499]
  PIN tx[500]
    DIRECTION OUTPUT ;
    USE SIGNAL ;
    PORT
      LAYER M4 ;
        RECT 725.568 570.288 725.760 570.312 ;
    END
  END tx[500]
  PIN tx[501]
    DIRECTION OUTPUT ;
    USE SIGNAL ;
    PORT
      LAYER M4 ;
        RECT 725.568 570.816 725.760 570.840 ;
    END
  END tx[501]
  PIN tx[502]
    DIRECTION OUTPUT ;
    USE SIGNAL ;
    PORT
      LAYER M4 ;
        RECT 725.568 571.392 725.760 571.416 ;
    END
  END tx[502]
  PIN tx[503]
    DIRECTION OUTPUT ;
    USE SIGNAL ;
    PORT
      LAYER M4 ;
        RECT 725.568 571.968 725.760 571.992 ;
    END
  END tx[503]
  PIN tx[504]
    DIRECTION OUTPUT ;
    USE SIGNAL ;
    PORT
      LAYER M4 ;
        RECT 725.568 572.496 725.760 572.520 ;
    END
  END tx[504]
  PIN tx[505]
    DIRECTION OUTPUT ;
    USE SIGNAL ;
    PORT
      LAYER M4 ;
        RECT 725.568 573.072 725.760 573.096 ;
    END
  END tx[505]
  PIN tx[506]
    DIRECTION OUTPUT ;
    USE SIGNAL ;
    PORT
      LAYER M4 ;
        RECT 725.568 573.648 725.760 573.672 ;
    END
  END tx[506]
  PIN tx[507]
    DIRECTION OUTPUT ;
    USE SIGNAL ;
    PORT
      LAYER M4 ;
        RECT 725.568 574.176 725.760 574.200 ;
    END
  END tx[507]
  PIN tx[508]
    DIRECTION OUTPUT ;
    USE SIGNAL ;
    PORT
      LAYER M4 ;
        RECT 725.568 574.752 725.760 574.776 ;
    END
  END tx[508]
  PIN tx[509]
    DIRECTION OUTPUT ;
    USE SIGNAL ;
    PORT
      LAYER M4 ;
        RECT 725.568 575.328 725.760 575.352 ;
    END
  END tx[509]
  PIN tx[510]
    DIRECTION OUTPUT ;
    USE SIGNAL ;
    PORT
      LAYER M4 ;
        RECT 725.568 575.856 725.760 575.880 ;
    END
  END tx[510]
  PIN tx[511]
    DIRECTION OUTPUT ;
    USE SIGNAL ;
    PORT
      LAYER M4 ;
        RECT 725.568 576.432 725.760 576.456 ;
    END
  END tx[511]
  PIN VDD
    DIRECTION INOUT ;
    USE POWER ;
    PORT
      LAYER M5 ;
        RECT 2.460 0.500 2.580 582.700 ;
        RECT 7.860 0.500 7.980 582.700 ;
        RECT 13.260 0.500 13.380 582.700 ;
        RECT 18.660 0.500 18.780 582.700 ;
        RECT 24.060 0.500 24.180 582.700 ;
        RECT 29.460 0.500 29.580 582.700 ;
        RECT 34.860 0.500 34.980 582.700 ;
        RECT 40.260 0.500 40.380 582.700 ;
        RECT 45.660 0.500 45.780 582.700 ;
        RECT 51.060 0.500 51.180 582.700 ;
        RECT 56.460 0.500 56.580 582.700 ;
        RECT 61.860 0.500 61.980 582.700 ;
        RECT 67.260 0.500 67.380 582.700 ;
        RECT 72.660 0.500 72.780 582.700 ;
        RECT 78.060 0.500 78.180 582.700 ;
        RECT 83.460 0.500 83.580 582.700 ;
        RECT 88.860 0.500 88.980 582.700 ;
        RECT 94.260 0.500 94.380 582.700 ;
        RECT 99.660 0.500 99.780 582.700 ;
        RECT 105.060 0.500 105.180 582.700 ;
        RECT 110.460 0.500 110.580 582.700 ;
        RECT 115.860 0.500 115.980 582.700 ;
        RECT 121.260 0.500 121.380 582.700 ;
        RECT 126.660 0.500 126.780 582.700 ;
        RECT 132.060 0.500 132.180 582.700 ;
        RECT 137.460 0.500 137.580 582.700 ;
        RECT 142.860 0.500 142.980 582.700 ;
        RECT 148.260 0.500 148.380 582.700 ;
        RECT 153.660 0.500 153.780 582.700 ;
        RECT 159.060 0.500 159.180 582.700 ;
        RECT 164.460 0.500 164.580 582.700 ;
        RECT 169.860 0.500 169.980 582.700 ;
        RECT 175.260 0.500 175.380 582.700 ;
        RECT 180.660 0.500 180.780 582.700 ;
        RECT 186.060 0.500 186.180 582.700 ;
        RECT 191.460 0.500 191.580 582.700 ;
        RECT 196.860 0.500 196.980 582.700 ;
        RECT 202.260 0.500 202.380 582.700 ;
        RECT 207.660 0.500 207.780 582.700 ;
        RECT 213.060 0.500 213.180 582.700 ;
        RECT 218.460 0.500 218.580 582.700 ;
        RECT 223.860 0.500 223.980 582.700 ;
        RECT 229.260 0.500 229.380 582.700 ;
        RECT 234.660 0.500 234.780 582.700 ;
        RECT 240.060 0.500 240.180 582.700 ;
        RECT 245.460 0.500 245.580 582.700 ;
        RECT 250.860 0.500 250.980 582.700 ;
        RECT 256.260 0.500 256.380 582.700 ;
        RECT 261.660 0.500 261.780 582.700 ;
        RECT 267.060 0.500 267.180 582.700 ;
        RECT 272.460 0.500 272.580 582.700 ;
        RECT 277.860 0.500 277.980 582.700 ;
        RECT 283.260 0.500 283.380 582.700 ;
        RECT 288.660 0.500 288.780 582.700 ;
        RECT 294.060 0.500 294.180 582.700 ;
        RECT 299.460 0.500 299.580 582.700 ;
        RECT 304.860 0.500 304.980 582.700 ;
        RECT 310.260 0.500 310.380 582.700 ;
        RECT 315.660 0.500 315.780 582.700 ;
        RECT 321.060 0.500 321.180 582.700 ;
        RECT 326.460 0.500 326.580 582.700 ;
        RECT 331.860 0.500 331.980 582.700 ;
        RECT 337.260 0.500 337.380 582.700 ;
        RECT 342.660 0.500 342.780 582.700 ;
        RECT 348.060 0.500 348.180 582.700 ;
        RECT 353.460 0.500 353.580 582.700 ;
        RECT 358.860 0.500 358.980 582.700 ;
        RECT 364.260 0.500 364.380 582.700 ;
        RECT 369.660 0.500 369.780 582.700 ;
        RECT 375.060 0.500 375.180 582.700 ;
        RECT 380.460 0.500 380.580 582.700 ;
        RECT 385.860 0.500 385.980 582.700 ;
        RECT 391.260 0.500 391.380 582.700 ;
        RECT 396.660 0.500 396.780 582.700 ;
        RECT 402.060 0.500 402.180 582.700 ;
        RECT 407.460 0.500 407.580 582.700 ;
        RECT 412.860 0.500 412.980 582.700 ;
        RECT 418.260 0.500 418.380 582.700 ;
        RECT 423.660 0.500 423.780 582.700 ;
        RECT 429.060 0.500 429.180 582.700 ;
        RECT 434.460 0.500 434.580 582.700 ;
        RECT 439.860 0.500 439.980 582.700 ;
        RECT 445.260 0.500 445.380 582.700 ;
        RECT 450.660 0.500 450.780 582.700 ;
        RECT 456.060 0.500 456.180 582.700 ;
        RECT 461.460 0.500 461.580 582.700 ;
        RECT 466.860 0.500 466.980 582.700 ;
        RECT 472.260 0.500 472.380 582.700 ;
        RECT 477.660 0.500 477.780 582.700 ;
        RECT 483.060 0.500 483.180 582.700 ;
        RECT 488.460 0.500 488.580 582.700 ;
        RECT 493.860 0.500 493.980 582.700 ;
        RECT 499.260 0.500 499.380 582.700 ;
        RECT 504.660 0.500 504.780 582.700 ;
        RECT 510.060 0.500 510.180 582.700 ;
        RECT 515.460 0.500 515.580 582.700 ;
        RECT 520.860 0.500 520.980 582.700 ;
        RECT 526.260 0.500 526.380 582.700 ;
        RECT 531.660 0.500 531.780 582.700 ;
        RECT 537.060 0.500 537.180 582.700 ;
        RECT 542.460 0.500 542.580 582.700 ;
        RECT 547.860 0.500 547.980 582.700 ;
        RECT 553.260 0.500 553.380 582.700 ;
        RECT 558.660 0.500 558.780 582.700 ;
        RECT 564.060 0.500 564.180 582.700 ;
        RECT 569.460 0.500 569.580 582.700 ;
        RECT 574.860 0.500 574.980 582.700 ;
        RECT 580.260 0.500 580.380 582.700 ;
        RECT 585.660 0.500 585.780 582.700 ;
        RECT 591.060 0.500 591.180 582.700 ;
        RECT 596.460 0.500 596.580 582.700 ;
        RECT 601.860 0.500 601.980 582.700 ;
        RECT 607.260 0.500 607.380 582.700 ;
        RECT 612.660 0.500 612.780 582.700 ;
        RECT 618.060 0.500 618.180 582.700 ;
        RECT 623.460 0.500 623.580 582.700 ;
        RECT 628.860 0.500 628.980 582.700 ;
        RECT 634.260 0.500 634.380 582.700 ;
        RECT 639.660 0.500 639.780 582.700 ;
        RECT 645.060 0.500 645.180 582.700 ;
        RECT 650.460 0.500 650.580 582.700 ;
        RECT 655.860 0.500 655.980 582.700 ;
        RECT 661.260 0.500 661.380 582.700 ;
        RECT 666.660 0.500 666.780 582.700 ;
        RECT 672.060 0.500 672.180 582.700 ;
        RECT 677.460 0.500 677.580 582.700 ;
        RECT 682.860 0.500 682.980 582.700 ;
        RECT 688.260 0.500 688.380 582.700 ;
        RECT 693.660 0.500 693.780 582.700 ;
        RECT 699.060 0.500 699.180 582.700 ;
        RECT 704.460 0.500 704.580 582.700 ;
        RECT 709.860 0.500 709.980 582.700 ;
        RECT 715.260 0.500 715.380 582.700 ;
        RECT 720.660 0.500 720.780 582.700 ;
    END
  END VDD
  PIN VSS
    DIRECTION INOUT ;
    USE GROUND ;
    PORT
      LAYER M5 ;
        RECT 2.652 0.500 2.772 582.700 ;
        RECT 8.052 0.500 8.172 582.700 ;
        RECT 13.452 0.500 13.572 582.700 ;
        RECT 18.852 0.500 18.972 582.700 ;
        RECT 24.252 0.500 24.372 582.700 ;
        RECT 29.652 0.500 29.772 582.700 ;
        RECT 35.052 0.500 35.172 582.700 ;
        RECT 40.452 0.500 40.572 582.700 ;
        RECT 45.852 0.500 45.972 582.700 ;
        RECT 51.252 0.500 51.372 582.700 ;
        RECT 56.652 0.500 56.772 582.700 ;
        RECT 62.052 0.500 62.172 582.700 ;
        RECT 67.452 0.500 67.572 582.700 ;
        RECT 72.852 0.500 72.972 582.700 ;
        RECT 78.252 0.500 78.372 582.700 ;
        RECT 83.652 0.500 83.772 582.700 ;
        RECT 89.052 0.500 89.172 582.700 ;
        RECT 94.452 0.500 94.572 582.700 ;
        RECT 99.852 0.500 99.972 582.700 ;
        RECT 105.252 0.500 105.372 582.700 ;
        RECT 110.652 0.500 110.772 582.700 ;
        RECT 116.052 0.500 116.172 582.700 ;
        RECT 121.452 0.500 121.572 582.700 ;
        RECT 126.852 0.500 126.972 582.700 ;
        RECT 132.252 0.500 132.372 582.700 ;
        RECT 137.652 0.500 137.772 582.700 ;
        RECT 143.052 0.500 143.172 582.700 ;
        RECT 148.452 0.500 148.572 582.700 ;
        RECT 153.852 0.500 153.972 582.700 ;
        RECT 159.252 0.500 159.372 582.700 ;
        RECT 164.652 0.500 164.772 582.700 ;
        RECT 170.052 0.500 170.172 582.700 ;
        RECT 175.452 0.500 175.572 582.700 ;
        RECT 180.852 0.500 180.972 582.700 ;
        RECT 186.252 0.500 186.372 582.700 ;
        RECT 191.652 0.500 191.772 582.700 ;
        RECT 197.052 0.500 197.172 582.700 ;
        RECT 202.452 0.500 202.572 582.700 ;
        RECT 207.852 0.500 207.972 582.700 ;
        RECT 213.252 0.500 213.372 582.700 ;
        RECT 218.652 0.500 218.772 582.700 ;
        RECT 224.052 0.500 224.172 582.700 ;
        RECT 229.452 0.500 229.572 582.700 ;
        RECT 234.852 0.500 234.972 582.700 ;
        RECT 240.252 0.500 240.372 582.700 ;
        RECT 245.652 0.500 245.772 582.700 ;
        RECT 251.052 0.500 251.172 582.700 ;
        RECT 256.452 0.500 256.572 582.700 ;
        RECT 261.852 0.500 261.972 582.700 ;
        RECT 267.252 0.500 267.372 582.700 ;
        RECT 272.652 0.500 272.772 582.700 ;
        RECT 278.052 0.500 278.172 582.700 ;
        RECT 283.452 0.500 283.572 582.700 ;
        RECT 288.852 0.500 288.972 582.700 ;
        RECT 294.252 0.500 294.372 582.700 ;
        RECT 299.652 0.500 299.772 582.700 ;
        RECT 305.052 0.500 305.172 582.700 ;
        RECT 310.452 0.500 310.572 582.700 ;
        RECT 315.852 0.500 315.972 582.700 ;
        RECT 321.252 0.500 321.372 582.700 ;
        RECT 326.652 0.500 326.772 582.700 ;
        RECT 332.052 0.500 332.172 582.700 ;
        RECT 337.452 0.500 337.572 582.700 ;
        RECT 342.852 0.500 342.972 582.700 ;
        RECT 348.252 0.500 348.372 582.700 ;
        RECT 353.652 0.500 353.772 582.700 ;
        RECT 359.052 0.500 359.172 582.700 ;
        RECT 364.452 0.500 364.572 582.700 ;
        RECT 369.852 0.500 369.972 582.700 ;
        RECT 375.252 0.500 375.372 582.700 ;
        RECT 380.652 0.500 380.772 582.700 ;
        RECT 386.052 0.500 386.172 582.700 ;
        RECT 391.452 0.500 391.572 582.700 ;
        RECT 396.852 0.500 396.972 582.700 ;
        RECT 402.252 0.500 402.372 582.700 ;
        RECT 407.652 0.500 407.772 582.700 ;
        RECT 413.052 0.500 413.172 582.700 ;
        RECT 418.452 0.500 418.572 582.700 ;
        RECT 423.852 0.500 423.972 582.700 ;
        RECT 429.252 0.500 429.372 582.700 ;
        RECT 434.652 0.500 434.772 582.700 ;
        RECT 440.052 0.500 440.172 582.700 ;
        RECT 445.452 0.500 445.572 582.700 ;
        RECT 450.852 0.500 450.972 582.700 ;
        RECT 456.252 0.500 456.372 582.700 ;
        RECT 461.652 0.500 461.772 582.700 ;
        RECT 467.052 0.500 467.172 582.700 ;
        RECT 472.452 0.500 472.572 582.700 ;
        RECT 477.852 0.500 477.972 582.700 ;
        RECT 483.252 0.500 483.372 582.700 ;
        RECT 488.652 0.500 488.772 582.700 ;
        RECT 494.052 0.500 494.172 582.700 ;
        RECT 499.452 0.500 499.572 582.700 ;
        RECT 504.852 0.500 504.972 582.700 ;
        RECT 510.252 0.500 510.372 582.700 ;
        RECT 515.652 0.500 515.772 582.700 ;
        RECT 521.052 0.500 521.172 582.700 ;
        RECT 526.452 0.500 526.572 582.700 ;
        RECT 531.852 0.500 531.972 582.700 ;
        RECT 537.252 0.500 537.372 582.700 ;
        RECT 542.652 0.500 542.772 582.700 ;
        RECT 548.052 0.500 548.172 582.700 ;
        RECT 553.452 0.500 553.572 582.700 ;
        RECT 558.852 0.500 558.972 582.700 ;
        RECT 564.252 0.500 564.372 582.700 ;
        RECT 569.652 0.500 569.772 582.700 ;
        RECT 575.052 0.500 575.172 582.700 ;
        RECT 580.452 0.500 580.572 582.700 ;
        RECT 585.852 0.500 585.972 582.700 ;
        RECT 591.252 0.500 591.372 582.700 ;
        RECT 596.652 0.500 596.772 582.700 ;
        RECT 602.052 0.500 602.172 582.700 ;
        RECT 607.452 0.500 607.572 582.700 ;
        RECT 612.852 0.500 612.972 582.700 ;
        RECT 618.252 0.500 618.372 582.700 ;
        RECT 623.652 0.500 623.772 582.700 ;
        RECT 629.052 0.500 629.172 582.700 ;
        RECT 634.452 0.500 634.572 582.700 ;
        RECT 639.852 0.500 639.972 582.700 ;
        RECT 645.252 0.500 645.372 582.700 ;
        RECT 650.652 0.500 650.772 582.700 ;
        RECT 656.052 0.500 656.172 582.700 ;
        RECT 661.452 0.500 661.572 582.700 ;
        RECT 666.852 0.500 666.972 582.700 ;
        RECT 672.252 0.500 672.372 582.700 ;
        RECT 677.652 0.500 677.772 582.700 ;
        RECT 683.052 0.500 683.172 582.700 ;
        RECT 688.452 0.500 688.572 582.700 ;
        RECT 693.852 0.500 693.972 582.700 ;
        RECT 699.252 0.500 699.372 582.700 ;
        RECT 704.652 0.500 704.772 582.700 ;
        RECT 710.052 0.500 710.172 582.700 ;
        RECT 715.452 0.500 715.572 582.700 ;
        RECT 720.852 0.500 720.972 582.700 ;
    END
  END VSS
  OBS
    LAYER M1 ;
      RECT 0.500 0.500 725.260 582.700 ;
    LAYER M2 ;
      RECT 0.500 0.500 725.260 582.700 ;
    LAYER M3 ;
      RECT 0.500 0.500 725.260 582.700 ;
    LAYER M4 ;
      RECT 10.800 0.500 714.960 582.700 ;
    LAYER M5 ;
      RECT 10.800 0.900 13.260 582.300 ;
      RECT 13.380 0.900 13.452 582.300 ;
      RECT 13.572 0.900 18.660 582.300 ;
      RECT 18.780 0.900 18.852 582.300 ;
      RECT 18.972 0.900 24.060 582.300 ;
      RECT 24.180 0.900 24.252 582.300 ;
      RECT 24.372 0.900 29.460 582.300 ;
      RECT 29.580 0.900 29.652 582.300 ;
      RECT 29.772 0.900 34.860 582.300 ;
      RECT 34.980 0.900 35.052 582.300 ;
      RECT 35.172 0.900 40.260 582.300 ;
      RECT 40.380 0.900 40.452 582.300 ;
      RECT 40.572 0.900 45.660 582.300 ;
      RECT 45.780 0.900 45.852 582.300 ;
      RECT 45.972 0.900 51.060 582.300 ;
      RECT 51.180 0.900 51.252 582.300 ;
      RECT 51.372 0.900 56.460 582.300 ;
      RECT 56.580 0.900 56.652 582.300 ;
      RECT 56.772 0.900 61.860 582.300 ;
      RECT 61.980 0.900 62.052 582.300 ;
      RECT 62.172 0.900 67.260 582.300 ;
      RECT 67.380 0.900 67.452 582.300 ;
      RECT 67.572 0.900 72.660 582.300 ;
      RECT 72.780 0.900 72.852 582.300 ;
      RECT 72.972 0.900 78.060 582.300 ;
      RECT 78.180 0.900 78.252 582.300 ;
      RECT 78.372 0.900 83.460 582.300 ;
      RECT 83.580 0.900 83.652 582.300 ;
      RECT 83.772 0.900 88.860 582.300 ;
      RECT 88.980 0.900 89.052 582.300 ;
      RECT 89.172 0.900 94.260 582.300 ;
      RECT 94.380 0.900 94.452 582.300 ;
      RECT 94.572 0.900 99.660 582.300 ;
      RECT 99.780 0.900 99.852 582.300 ;
      RECT 99.972 0.900 105.060 582.300 ;
      RECT 105.180 0.900 105.252 582.300 ;
      RECT 105.372 0.900 110.460 582.300 ;
      RECT 110.580 0.900 110.652 582.300 ;
      RECT 110.772 0.900 115.860 582.300 ;
      RECT 115.980 0.900 116.052 582.300 ;
      RECT 116.172 0.900 121.260 582.300 ;
      RECT 121.380 0.900 121.452 582.300 ;
      RECT 121.572 0.900 126.660 582.300 ;
      RECT 126.780 0.900 126.852 582.300 ;
      RECT 126.972 0.900 132.060 582.300 ;
      RECT 132.180 0.900 132.252 582.300 ;
      RECT 132.372 0.900 137.460 582.300 ;
      RECT 137.580 0.900 137.652 582.300 ;
      RECT 137.772 0.900 142.860 582.300 ;
      RECT 142.980 0.900 143.052 582.300 ;
      RECT 143.172 0.900 148.260 582.300 ;
      RECT 148.380 0.900 148.452 582.300 ;
      RECT 148.572 0.900 153.660 582.300 ;
      RECT 153.780 0.900 153.852 582.300 ;
      RECT 153.972 0.900 159.060 582.300 ;
      RECT 159.180 0.900 159.252 582.300 ;
      RECT 159.372 0.900 164.460 582.300 ;
      RECT 164.580 0.900 164.652 582.300 ;
      RECT 164.772 0.900 169.860 582.300 ;
      RECT 169.980 0.900 170.052 582.300 ;
      RECT 170.172 0.900 175.260 582.300 ;
      RECT 175.380 0.900 175.452 582.300 ;
      RECT 175.572 0.900 180.660 582.300 ;
      RECT 180.780 0.900 180.852 582.300 ;
      RECT 180.972 0.900 186.060 582.300 ;
      RECT 186.180 0.900 186.252 582.300 ;
      RECT 186.372 0.900 191.460 582.300 ;
      RECT 191.580 0.900 191.652 582.300 ;
      RECT 191.772 0.900 196.860 582.300 ;
      RECT 196.980 0.900 197.052 582.300 ;
      RECT 197.172 0.900 202.260 582.300 ;
      RECT 202.380 0.900 202.452 582.300 ;
      RECT 202.572 0.900 207.660 582.300 ;
      RECT 207.780 0.900 207.852 582.300 ;
      RECT 207.972 0.900 213.060 582.300 ;
      RECT 213.180 0.900 213.252 582.300 ;
      RECT 213.372 0.900 218.460 582.300 ;
      RECT 218.580 0.900 218.652 582.300 ;
      RECT 218.772 0.900 223.860 582.300 ;
      RECT 223.980 0.900 224.052 582.300 ;
      RECT 224.172 0.900 229.260 582.300 ;
      RECT 229.380 0.900 229.452 582.300 ;
      RECT 229.572 0.900 234.660 582.300 ;
      RECT 234.780 0.900 234.852 582.300 ;
      RECT 234.972 0.900 240.060 582.300 ;
      RECT 240.180 0.900 240.252 582.300 ;
      RECT 240.372 0.900 245.460 582.300 ;
      RECT 245.580 0.900 245.652 582.300 ;
      RECT 245.772 0.900 250.860 582.300 ;
      RECT 250.980 0.900 251.052 582.300 ;
      RECT 251.172 0.900 256.260 582.300 ;
      RECT 256.380 0.900 256.452 582.300 ;
      RECT 256.572 0.900 261.660 582.300 ;
      RECT 261.780 0.900 261.852 582.300 ;
      RECT 261.972 0.900 267.060 582.300 ;
      RECT 267.180 0.900 267.252 582.300 ;
      RECT 267.372 0.900 272.460 582.300 ;
      RECT 272.580 0.900 272.652 582.300 ;
      RECT 272.772 0.900 277.860 582.300 ;
      RECT 277.980 0.900 278.052 582.300 ;
      RECT 278.172 0.900 283.260 582.300 ;
      RECT 283.380 0.900 283.452 582.300 ;
      RECT 283.572 0.900 288.660 582.300 ;
      RECT 288.780 0.900 288.852 582.300 ;
      RECT 288.972 0.900 294.060 582.300 ;
      RECT 294.180 0.900 294.252 582.300 ;
      RECT 294.372 0.900 299.460 582.300 ;
      RECT 299.580 0.900 299.652 582.300 ;
      RECT 299.772 0.900 304.860 582.300 ;
      RECT 304.980 0.900 305.052 582.300 ;
      RECT 305.172 0.900 310.260 582.300 ;
      RECT 310.380 0.900 310.452 582.300 ;
      RECT 310.572 0.900 315.660 582.300 ;
      RECT 315.780 0.900 315.852 582.300 ;
      RECT 315.972 0.900 321.060 582.300 ;
      RECT 321.180 0.900 321.252 582.300 ;
      RECT 321.372 0.900 326.460 582.300 ;
      RECT 326.580 0.900 326.652 582.300 ;
      RECT 326.772 0.900 331.860 582.300 ;
      RECT 331.980 0.900 332.052 582.300 ;
      RECT 332.172 0.900 337.260 582.300 ;
      RECT 337.380 0.900 337.452 582.300 ;
      RECT 337.572 0.900 342.660 582.300 ;
      RECT 342.780 0.900 342.852 582.300 ;
      RECT 342.972 0.900 348.060 582.300 ;
      RECT 348.180 0.900 348.252 582.300 ;
      RECT 348.372 0.900 353.460 582.300 ;
      RECT 353.580 0.900 353.652 582.300 ;
      RECT 353.772 0.900 358.860 582.300 ;
      RECT 358.980 0.900 359.052 582.300 ;
      RECT 359.172 0.900 364.260 582.300 ;
      RECT 364.380 0.900 364.452 582.300 ;
      RECT 364.572 0.900 369.660 582.300 ;
      RECT 369.780 0.900 369.852 582.300 ;
      RECT 369.972 0.900 375.060 582.300 ;
      RECT 375.180 0.900 375.252 582.300 ;
      RECT 375.372 0.900 380.460 582.300 ;
      RECT 380.580 0.900 380.652 582.300 ;
      RECT 380.772 0.900 385.860 582.300 ;
      RECT 385.980 0.900 386.052 582.300 ;
      RECT 386.172 0.900 391.260 582.300 ;
      RECT 391.380 0.900 391.452 582.300 ;
      RECT 391.572 0.900 396.660 582.300 ;
      RECT 396.780 0.900 396.852 582.300 ;
      RECT 396.972 0.900 402.060 582.300 ;
      RECT 402.180 0.900 402.252 582.300 ;
      RECT 402.372 0.900 407.460 582.300 ;
      RECT 407.580 0.900 407.652 582.300 ;
      RECT 407.772 0.900 412.860 582.300 ;
      RECT 412.980 0.900 413.052 582.300 ;
      RECT 413.172 0.900 418.260 582.300 ;
      RECT 418.380 0.900 418.452 582.300 ;
      RECT 418.572 0.900 423.660 582.300 ;
      RECT 423.780 0.900 423.852 582.300 ;
      RECT 423.972 0.900 429.060 582.300 ;
      RECT 429.180 0.900 429.252 582.300 ;
      RECT 429.372 0.900 434.460 582.300 ;
      RECT 434.580 0.900 434.652 582.300 ;
      RECT 434.772 0.900 439.860 582.300 ;
      RECT 439.980 0.900 440.052 582.300 ;
      RECT 440.172 0.900 445.260 582.300 ;
      RECT 445.380 0.900 445.452 582.300 ;
      RECT 445.572 0.900 450.660 582.300 ;
      RECT 450.780 0.900 450.852 582.300 ;
      RECT 450.972 0.900 456.060 582.300 ;
      RECT 456.180 0.900 456.252 582.300 ;
      RECT 456.372 0.900 461.460 582.300 ;
      RECT 461.580 0.900 461.652 582.300 ;
      RECT 461.772 0.900 466.860 582.300 ;
      RECT 466.980 0.900 467.052 582.300 ;
      RECT 467.172 0.900 472.260 582.300 ;
      RECT 472.380 0.900 472.452 582.300 ;
      RECT 472.572 0.900 477.660 582.300 ;
      RECT 477.780 0.900 477.852 582.300 ;
      RECT 477.972 0.900 483.060 582.300 ;
      RECT 483.180 0.900 483.252 582.300 ;
      RECT 483.372 0.900 488.460 582.300 ;
      RECT 488.580 0.900 488.652 582.300 ;
      RECT 488.772 0.900 493.860 582.300 ;
      RECT 493.980 0.900 494.052 582.300 ;
      RECT 494.172 0.900 499.260 582.300 ;
      RECT 499.380 0.900 499.452 582.300 ;
      RECT 499.572 0.900 504.660 582.300 ;
      RECT 504.780 0.900 504.852 582.300 ;
      RECT 504.972 0.900 510.060 582.300 ;
      RECT 510.180 0.900 510.252 582.300 ;
      RECT 510.372 0.900 515.460 582.300 ;
      RECT 515.580 0.900 515.652 582.300 ;
      RECT 515.772 0.900 520.860 582.300 ;
      RECT 520.980 0.900 521.052 582.300 ;
      RECT 521.172 0.900 526.260 582.300 ;
      RECT 526.380 0.900 526.452 582.300 ;
      RECT 526.572 0.900 531.660 582.300 ;
      RECT 531.780 0.900 531.852 582.300 ;
      RECT 531.972 0.900 537.060 582.300 ;
      RECT 537.180 0.900 537.252 582.300 ;
      RECT 537.372 0.900 542.460 582.300 ;
      RECT 542.580 0.900 542.652 582.300 ;
      RECT 542.772 0.900 547.860 582.300 ;
      RECT 547.980 0.900 548.052 582.300 ;
      RECT 548.172 0.900 553.260 582.300 ;
      RECT 553.380 0.900 553.452 582.300 ;
      RECT 553.572 0.900 558.660 582.300 ;
      RECT 558.780 0.900 558.852 582.300 ;
      RECT 558.972 0.900 564.060 582.300 ;
      RECT 564.180 0.900 564.252 582.300 ;
      RECT 564.372 0.900 569.460 582.300 ;
      RECT 569.580 0.900 569.652 582.300 ;
      RECT 569.772 0.900 574.860 582.300 ;
      RECT 574.980 0.900 575.052 582.300 ;
      RECT 575.172 0.900 580.260 582.300 ;
      RECT 580.380 0.900 580.452 582.300 ;
      RECT 580.572 0.900 585.660 582.300 ;
      RECT 585.780 0.900 585.852 582.300 ;
      RECT 585.972 0.900 591.060 582.300 ;
      RECT 591.180 0.900 591.252 582.300 ;
      RECT 591.372 0.900 596.460 582.300 ;
      RECT 596.580 0.900 596.652 582.300 ;
      RECT 596.772 0.900 601.860 582.300 ;
      RECT 601.980 0.900 602.052 582.300 ;
      RECT 602.172 0.900 607.260 582.300 ;
      RECT 607.380 0.900 607.452 582.300 ;
      RECT 607.572 0.900 612.660 582.300 ;
      RECT 612.780 0.900 612.852 582.300 ;
      RECT 612.972 0.900 618.060 582.300 ;
      RECT 618.180 0.900 618.252 582.300 ;
      RECT 618.372 0.900 623.460 582.300 ;
      RECT 623.580 0.900 623.652 582.300 ;
      RECT 623.772 0.900 628.860 582.300 ;
      RECT 628.980 0.900 629.052 582.300 ;
      RECT 629.172 0.900 634.260 582.300 ;
      RECT 634.380 0.900 634.452 582.300 ;
      RECT 634.572 0.900 639.660 582.300 ;
      RECT 639.780 0.900 639.852 582.300 ;
      RECT 639.972 0.900 645.060 582.300 ;
      RECT 645.180 0.900 645.252 582.300 ;
      RECT 645.372 0.900 650.460 582.300 ;
      RECT 650.580 0.900 650.652 582.300 ;
      RECT 650.772 0.900 655.860 582.300 ;
      RECT 655.980 0.900 656.052 582.300 ;
      RECT 656.172 0.900 661.260 582.300 ;
      RECT 661.380 0.900 661.452 582.300 ;
      RECT 661.572 0.900 666.660 582.300 ;
      RECT 666.780 0.900 666.852 582.300 ;
      RECT 666.972 0.900 672.060 582.300 ;
      RECT 672.180 0.900 672.252 582.300 ;
      RECT 672.372 0.900 677.460 582.300 ;
      RECT 677.580 0.900 677.652 582.300 ;
      RECT 677.772 0.900 682.860 582.300 ;
      RECT 682.980 0.900 683.052 582.300 ;
      RECT 683.172 0.900 688.260 582.300 ;
      RECT 688.380 0.900 688.452 582.300 ;
      RECT 688.572 0.900 693.660 582.300 ;
      RECT 693.780 0.900 693.852 582.300 ;
      RECT 693.972 0.900 699.060 582.300 ;
      RECT 699.180 0.900 699.252 582.300 ;
      RECT 699.372 0.900 704.460 582.300 ;
      RECT 704.580 0.900 704.652 582.300 ;
      RECT 704.772 0.900 709.860 582.300 ;
      RECT 709.980 0.900 710.052 582.300 ;
      RECT 710.172 0.900 714.960 582.300 ;
  END
END dsfd_coll_lane_e_safe8_ntf
END LIBRARY
